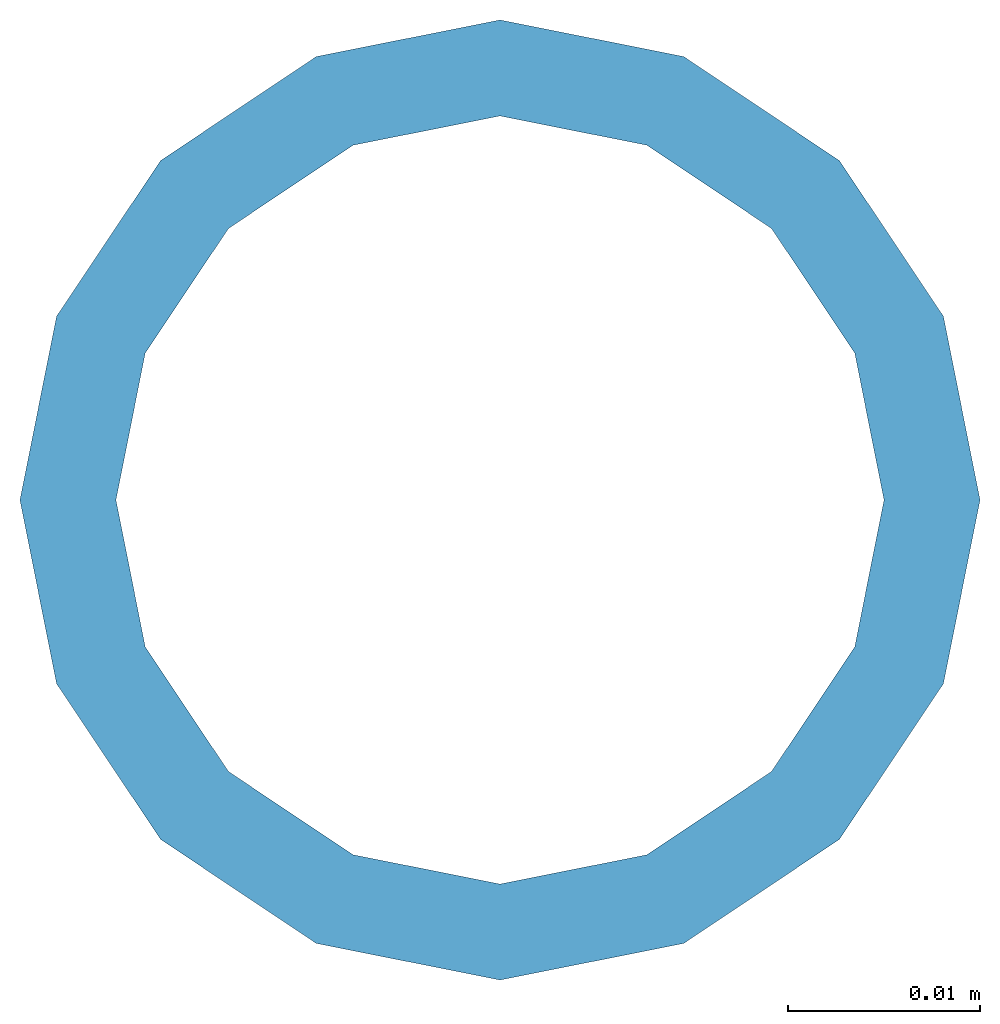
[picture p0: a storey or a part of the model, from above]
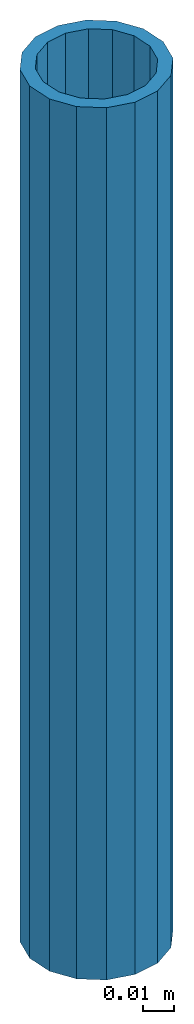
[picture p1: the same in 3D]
Properties of the parts of a building model (IFC2X3), part 1 of 6

# File
Description: ViewDefinition [CoordinationView]
File name: GM.TO-350-205.1 (EDITED).ifc (Edited by Naviate Simple BIM 2022 version 6)
Time: 2026-03-17T17:15:05+01:00
Written by: ODA SDAI 24.12
Made in: Autodesk Revit 25.4.20.11 (ENU) - IFC 25.4.0.27

# IfcProject, A181143
LongName: T2; Phase: Detaljprosjekt

# IfcSite (8)
Name | RefLatitude | RefLongitude | RefElevation (mm) | Reference latitude | Reference elevation | Reference longitude
ENGM | 33, 12, 51, 119999 | -97, -7, -51, -239999 | -4.85124e-10
Gardermoen
ENGM | 33, 12, 51, 119999 | -97, -7, -51, -239999 | 0 | 33, 12, 51, 119999 | 0 | -97, -7, -51, -239999 | MagiCAD Pset_Site - Name: ENGM
ENGM | 59, 54, 49, 759826 | 10, 44, 19, 467315 | 0 | 59, 54, 49, 759826 | 0 | 10, 44, 19, 467315 | MagiCAD Pset_Site - Name: ENGM
ENGM | 42, 24, 53, 508911 | -71, -15, -29, -58837 | 0 | 42, 24, 53, 508911 | 0 | -71, -15, -29, -58837 | MagiCAD Pset_Site - Name: ENGM
Default | 59, 54, 57, 599999 | 10, 44, 59, 999999 | 0
 | 33, 12, 51, 119998 | -97, -7, -51, -239998 | 0 | 33, 12, 51, 119998 | 0 | -97, -7, -51, -239998
ENGM | 33, 12, 51, 119998 | -97, -7, -51, -239998 | 0 | 33, 12, 51, 119998 | 0 | -97, -7, -51, -239998 | MagiCAD Pset_Site - Name: ENGM

# IfcBuilding (8)
Name
TI | LongName: TI; Pset_BuildingCommon - BuildingID: TI; NumberOfStoreys: 15
TI
4 x TI | MagiCAD Pset_Building - Building name: TI
 | Pset_BuildingCommon - NumberOfStoreys: 3; Pset_ProductRequirements - Category: Project Information
mc-building

# IfcBuildingStorey (20)
Name | In | Elevation (mm) | Name
D | TI | 0
F | TI | 0
B | TI | 0
Nivå G + 1,2 m | TI | 216900 | Nivå G + 1,2 m
4 x Nivå F | TI | 210900 | Nivå F
2 x Nivå D + 1,2 m | TI | 205200 | Nivå D + 1,2 m
Nivå H | TI | 219200 | Nivå H
Nivå C | TI | 200300 | Nivå C
Nivå C + 2,7 m | TI | 203000 | Nivå C + 2,7 m
2 x Nivå D | TI | 204000 | Nivå D
Nivå F | mc-building | 210900 | Nivå F
Nivå D | mc-building | 204000 | Nivå D
Nivå F -0,7 | mc-building | 210200 | Nivå F -0,7
Nivå E | TI | 207370 | Nivå E
Nivå F - 0,7 m | TI | 210200 | Nivå F - 0,7 m

# IfcBuildingStorey: Level:8mm Head, Nivå E
LongName: Nivå E; Elevation: 207370 mm
Pset_AirSideSystemInformation - Name: Nivå E
Pset_ProductRequirements - Name: Nivå E; Category: Levels

# IfcBuildingStorey: Level:T2 - Kote (4)
In: TI
Name | LongName | Elevation (mm)
Nivå D | Nivå D | 204000 | Pset_ProductRequirements - Name: Nivå D; sets with these values: 2
Nivå F - 0,7 m | Nivå F - 0,7 m | 210200 | Pset_AirSideSystemInformation - Name: Nivå F - 0,7 m; sets with these values: 2
Nivå F | Nivå F | 210900 | Pset_ProductRequirements - Name: Nivå F; sets with these values: 2
Nivå G - 2,0m | Nivå G - 2,0m | 213700 | Pset_AirSideSystemInformation - Name: Nivå G - 2,0m; sets with these values: 2

# IfcBeam: B223 - Bjelke - HUP:B223 - HUP - 100 x 100 x 5 mm, B223 - Bjelke - HUP:B223 - HUP - 100 x 100 x 5 mm:62363315
In: Nivå F
Type - PredefinedType: BEAM
Type - Pset_BeamCommon - LoadBearing: yes
Material: _NSW Stål
ePset_SimplebimBasicQuantities - Weight, as steel (Simplebim): 21.4029 kg; Area, sides, net (Simplebim): 1.09439 m2; Height (Simplebim): 100 mm; Length (Simplebim): 1434.99 mm; Volume, net (Simplebim): 0.00272648 m3; Width (Simplebim): 100 mm
AVINOR - 03_Ansvar: 72253; 08_Status: S4; 07_Fase: F90; 06_Omrade: TI; 02_Prosjekt: T20100; 01_Lufthavnkode: ENGM
ePset_Simplebim - Assembly Level: Leaf
Pset_ReinforcementBarPitchOfBeam - Reference: B223 - HUP - 100 x 100 x 5 mm; sets with these values: 2
ePset_LocationTool - Splitting: ORIGINAL
Pset_BeamCommon - Span: 1434.99 mm; IsExternal: no; Slope: 0 deg; Reference: B223 - HUP - 100 x 100 x 5 mm

# IfcBeam: FL80*15, STÅLBJELKE
In: F
Description: FL80*15; Material: STEEL/S355
ePset_Simplebim - Assembly Level: Leaf
ePset_LocationTool - Splitting: ORIGINAL
Tekla Quantity - Length: 639.985 mm; AREA_NET: 0.124 m2; AREA_GROSS: 0.124 m2; Width: 15 mm; Heigth: 80 mm; WEIGTH_NET: 6.02866 kg; WEIGTH_GROSS: 6.02866 kg; VOLUME_NET: 0.00077 m3; VOLUME_GROSS: 0.00077 m3
ePset_SimplebimBasicQuantities - Length (Simplebim): 639.985 mm; Volume, net (Simplebim): 0.000767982 m3; Height (Simplebim): 80 mm; Width (Simplebim): 15 mm; Weight, as steel (Simplebim): 6.02866 kg; Area, sides, net (Simplebim): 0.123997 m2
Pset_BeamCommon - LoadBearing: no; Reference: DSB-24802(?)
Tekla Common - Grade: S355; Bottom elevation: +213.805; Top elevation: +213.885; Profile: FL80*15; Name: STÅLBJELKE; Part mark: DSB-24802(?); Class: 330; Assembly mark: SB-14737(?)
AVINOR - 04_Kontrakt: 72253; 05_ID-nummer: +TI=221.025; 08_Status: S4; 07_Fase: F90; 06_Omrade: TI; 02_Prosjekt: T20100; 03_Ansvar: 72101; 01_Lufthavnkode: ENGM

# IfcBeam: HEA600 (2)
In: F
Description: HEA600
ePset_Simplebim - Assembly Level: Leaf
Pset_BeamCommon - LoadBearing: no
AVINOR - 08_Status: S4; 07_Fase: F40; 06_Omrade: TI; 05_ID-nummer: +TI=223.008; 03_Ansvar: 72242; 04_Kontrakt: 72242; 02_Prosjekt: T20100; 01_Lufthavnkode: ENGM
Tekla Common - Grade: S355; Bottom elevation: +210.090; Name: STÅLBJELKE; Profile: HEA600; Top elevation: +210.680; Class: 330
ePset_SimplebimBasicQuantities - Width (Simplebim): 300 mm; Height (Simplebim): 590 mm
Name | Reference = Part mark | Splitting | Assembly mark | Weight, as steel (Simplebim) (kg) | Area, sides, net (Simplebim) (m2) | Volume, net (Simplebim) (m3) | Length (Simplebim) (mm)
STÅLBJELKE | DSB-10256(?) | ORIGINAL | SB-5409(?) | 1493.49 | 20.3826 | 0.190253 | 8640.01 | Material: STEEL/S355; Tekla Quantity - WEIGTH_NET: 1493.49 kg; VOLUME_NET: 0.19025 m3; VOLUME_GROSS: 0.1957 m3; AREA_GROSS: 19.9411 m2; AREA_NET: 20.3826 m2; WEIGTH_GROSS: 1536.22 kg; Width: 300 mm; Heigth: 590 mm; Length: 8640.01 mm
STÅLBJELKE | DSB-10255(?) | RESULT | SB-5408(?) | 223.937 | 3.09366 | 0.028527 | 1296

# IfcBeam: HQ420*15-35*370-25*700 (2)
In: F
Description: HQ420*15-35*370-25*700
ePset_Simplebim - Assembly Level: Leaf
AVINOR - 08_Status: S4; 07_Fase: F40; 06_Omrade: TI; 05_ID-nummer: +TI=223.008; 03_Ansvar: 72242; 04_Kontrakt: 72242; 02_Prosjekt: T20100; 01_Lufthavnkode: ENGM
Tekla Common - Grade: S355; Top elevation: +210.673; Name: STÅLBJELKE; Profile: HQ420*15-35*370-25*700; Class: 330; Bottom elevation: +210.227
ePset_SimplebimBasicQuantities - Height (Simplebim): 444 mm
ePset_LocationTool - Splitting: RESULT
Pset_BeamCommon - LoadBearing: no
Name | Assembly mark | Part mark = Reference | Area, sides, net (Simplebim) (m2) | Volume, net (Simplebim) (m3) | Weight, as steel (Simplebim) (kg) | Width (Simplebim) (mm) | Length (Simplebim) (mm)
STÅLBJELKE | SB-6203 | DSB-373 | 5.1591 | 0.0574717 | 451.153 | 700 | 1335
STÅLBJELKE | SB-7092 | DSB-12327 | 5.4134 | 0.0589778 | 462.976 | 350 | 2740

# IfcBeam: HSQ110*6-10*68-10*280, STÅLBJELKE
In: F
Description: HSQ110*6-10*68-10*280; Material: STEEL/S355J2H
ePset_Simplebim - Assembly Level: Leaf
ePset_LocationTool - Splitting: ORIGINAL
Tekla Common - Top elevation: +213.810; Part mark: DSB-24857(?); Name: STÅLBJELKE; Grade: S355J2H; Assembly mark: SB-14759(?); Profile: HSQ110*6-10*68-10*280; Bottom elevation: +213.690; Class: 330
Tekla Quantity - VOLUME_NET: 0.02027 m3; Length: 4350.93 mm; AREA_NET: 4.82754 m2; VOLUME_GROSS: 0.02088 m3; Heigth: 120 mm; Width: 280 mm; WEIGTH_GROSS: 163.943 kg; WEIGTH_NET: 159.121 kg; AREA_GROSS: 4.95226 m2
Pset_BeamCommon - Reference: DSB-24857(?); LoadBearing: no
ePset_SimplebimBasicQuantities - Length (Simplebim): 4350.93 mm; Area, sides, net (Simplebim): 4.82754 m2; Height (Simplebim): 120 mm; Width (Simplebim): 280 mm; Weight, as steel (Simplebim): 159.121 kg; Volume, net (Simplebim): 0.0202702 m3
AVINOR - 08_Status: S4; 07_Fase: F90; 06_Omrade: TI; 04_Kontrakt: 72717; 02_Prosjekt: T20100; 05_ID-nummer: +TI=221.041; 03_Ansvar: 72101; 01_Lufthavnkode: ENGM

# IfcBeam: IPE120 (3)
In: F
Description: IPE120
ePset_Simplebim - Assembly Level: Leaf
Pset_BeamCommon - LoadBearing: no
ePset_SimplebimBasicQuantities - Height (Simplebim): 120 mm; Width (Simplebim): 64 mm
Tekla Common - Name: STÅLBJELKE; Profile: IPE120; Class: 330
AVINOR - 08_Status: S4; 06_Omrade: TI; 02_Prosjekt: T20100; 01_Lufthavnkode: ENGM
Name | Reference = Part mark | Volume, net (Simplebim) (m3) | Weight, as steel (Simplebim) (kg) | Area, sides, net (Simplebim) (m2) | Length (Simplebim) (mm) | Splitting | Bottom elevation | Top elevation | Grade | Assembly mark | 07_Fase | 04_Kontrakt | 05_ID-nummer | 03_Ansvar
STÅLBJELKE | DSB-22164(?) | 0.00570141 | 44.756 | 2.17868 | 4535.67 | ORIGINAL | +213.580 | +213.700 | S355J2H | SB-13216(?) | F90 | 72717 | +TI=221.041 | 72101 | Material: STEEL/S355J2H; Tekla Quantity - AREA_NET: 2.17868 m2; WEIGTH_GROSS: 46.9986 kg; WEIGTH_NET: 44.756 kg; Length: 4535.67 mm; VOLUME_NET: 0.0057 m3; Width: 64 mm; Heigth: 120 mm; AREA_GROSS: 2.15444 m2; VOLUME_GROSS: 0.00599 m3
2 x STÅLBJELKE | DSB-15659 | 0.00166968 | 13.107 | 0.638595 | 1305 | RESULT | +210.560 | +210.680 | S355 | SB-9378 | F40 | 72242 | +TI=223.008 | 72242

# IfcBeam: IPE140 (7)
In: F
Description: IPE140; Material: STEEL/S355J2H
ePset_Simplebim - Assembly Level: Leaf
ePset_LocationTool - Splitting: ORIGINAL
Tekla Quantity - Width: 73 mm; Heigth: 140 mm
Pset_BeamCommon - LoadBearing: no
Tekla Common - Bottom elevation: +213.560; Top elevation: +213.700; Name: STÅLBJELKE; Grade: S355J2H; Profile: IPE140; Class: 330
AVINOR - 08_Status: S4; 07_Fase: F90; 06_Omrade: TI; 04_Kontrakt: 72717; 02_Prosjekt: T20100; 05_ID-nummer: +TI=221.041; 03_Ansvar: 72101; 01_Lufthavnkode: ENGM
ePset_SimplebimBasicQuantities - Height (Simplebim): 140 mm; Width (Simplebim): 73 mm
Name | WEIGTH_NET (kg) | WEIGTH_GROSS (kg) | VOLUME_GROSS (m3) | VOLUME_NET (m3) | Length (mm) = Length (Simplebim) (mm) | AREA_GROSS (m2) | AREA_NET (m2) | Reference = Part mark | Assembly mark | Area, sides, net (Simplebim) (m2) | Volume, net (Simplebim) (m3) | Weight, as steel (Simplebim) (kg)
STÅLBJELKE | 37.7938 | 39.2136 | 0.00499 | 0.0048 | 3045.95 | 1.67832 | 1.69784 | DSB-19839(?) | SB-11959(?) | 1.69784 | 0.00481608 | 37.8063
STÅLBJELKE | 13.3062 | 13.6343 | 0.00174 | 0.0017 | 1059.06 | 0.58354 | 0.59903 | DSB-19837(?) | SS-7783(?) | 0.599026 | 0.00169506 | 13.3062
STÅLBJELKE | 38.2719 | 39.7163 | 0.00506 | 0.00489 | 3085 | 1.69984 | 1.71967 | DSB-19838(?) | SB-11958(?) | 1.71967 | 0.0048754 | 38.2719
STÅLBJELKE | 27.6579 | 29.7187 | 0.00379 | 0.00352 | 2308.43 | 1.27194 | 1.24608 | DSB-19836(?) | SB-11957(?) | 1.24608 | 0.0035233 | 27.6579
STÅLBJELKE | 7.70276 | 8.10866 | 0.00103 | 0.00098 | 629.848 | 0.34705 | 0.34929 | DSB-19835(?) | SB-11956(?) | 0.349291 | 0.000981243 | 7.70276
STÅLBJELKE | 25.6808 | 26.8353 | 0.00342 | 0.00327 | 2084.46 | 1.14854 | 1.15598 | DSB-19840(?) | SB-11960(?) | 1.15598 | 0.00327144 | 25.6808
STÅLBJELKE | 25.789 | 26.4248 | 0.00337 | 0.00329 | 2052.57 | 1.13097 | 1.15798 | DSB-19827(?) | SB-7478(?) | 1.15798 | 0.00328522 | 25.789

# IfcBeam: IPE180 (4)
In: F
Description: IPE180; Material: STEEL/S355J2H
ePset_Simplebim - Assembly Level: Leaf
ePset_LocationTool - Splitting: ORIGINAL
Pset_BeamCommon - LoadBearing: no
Tekla Quantity - Width: 91 mm; Heigth: 180 mm
Tekla Common - Bottom elevation: +213.520; Top elevation: +213.700; Name: STÅLBJELKE; Grade: S355J2H; Profile: IPE180; Class: 330
ePset_SimplebimBasicQuantities - Width (Simplebim): 91 mm; Height (Simplebim): 180 mm
AVINOR - 08_Status: S4; 07_Fase: F90; 06_Omrade: TI; 04_Kontrakt: 72717; 02_Prosjekt: T20100; 05_ID-nummer: +TI=221.041; 03_Ansvar: 72101; 01_Lufthavnkode: ENGM
Name | Reference = Part mark | VOLUME_GROSS (m3) | AREA_NET (m2) = Area, sides, net (Simplebim) (m2) | WEIGTH_GROSS (kg) | AREA_GROSS (m2) | Length (mm) = Length (Simplebim) (mm) | VOLUME_NET (m3) | WEIGTH_NET (kg) | Assembly mark | Volume, net (Simplebim) (m3) | Weight, as steel (Simplebim) (kg)
STÅLBJELKE | DSB-19708(?) | 0.00552 | 1.65139 | 43.3072 | 1.61119 | 2308.3 | 0.00537 | 42.133 | SB-7476(?) | 0.00536726 | 42.133
STÅLBJELKE | DSB-19707(?) | 0.00876 | 2.61543 | 68.6603 | 2.55443 | 3659.64 | 0.00851 | 66.7987 | SB-11895(?) | 0.00850939 | 66.7987
STÅLBJELKE | DSB-19706(?) | 0.01173 | 3.49031 | 92.0957 | 3.42631 | 4908.76 | 0.01135 | 89.1756 | SB-7474(?) | 0.0113599 | 89.1755
STÅLBJELKE | DSB-19705(?) | 0.01289 | 3.85171 | 101.173 | 3.76402 | 5392.57 | 0.01254 | 98.4297 | SB-7477(?) | 0.0125388 | 98.4297

# IfcBeam: L100*10 (3)
In: F
Description: L100*10; Material: STEEL/S355
Tekla Quantity - Width: 100 mm; Heigth: 100 mm
ePset_Simplebim - Assembly Level: Leaf
ePset_SimplebimBasicQuantities - Width (Simplebim): 100 mm
ePset_LocationTool - Splitting: ORIGINAL
Pset_BeamCommon - Reference: DSB-18464(?); LoadBearing: no
Tekla Common - Grade: S355; Part mark: DSB-18464(?); Bottom elevation: +213.500; Name: STÅLBJELKE; Assembly mark: SB-0(?); Class: 330; Profile: L100*10
AVINOR - 08_Status: S4; 07_Fase: F90; 06_Omrade: TI; 04_Kontrakt: 72717; 02_Prosjekt: T20100; 05_ID-nummer: +TI=221.041; 03_Ansvar: 72101; 01_Lufthavnkode: ENGM
Name | AREA_NET (m2) | Length (mm) | VOLUME_NET (m3) | VOLUME_GROSS (m3) | WEIGTH_GROSS (kg) | AREA_GROSS (m2) | WEIGTH_NET (kg) = Weight, as steel (Simplebim) (kg) | Area, sides, net (Simplebim) (m2) | Volume, net (Simplebim) (m3) | Height (Simplebim) (mm) | Length (Simplebim) (mm) | Top elevation
STÅLBJELKE | 0.0838 | 200 | 0.00037 | 0.00037 | 3.0144 | 0.07799 | 2.983 | 0.0838 | 0.00038 | 100 | 200 | +213.600
2 x STÅLBJELKE | 0.0632 | 183.102 | 0.00028 | 0.00035 | 2.75972 | 0.0714 | 2.18766 | 0.0631987 | 0.000278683 | 183.102 | 100 | +213.683

# IfcBeam: L100*150*10, STÅLBJELKE
In: F
Description: L100*150*10
Tekla Common - Grade: S355; Name: STÅLBJELKE; Top elevation: +210.830; Assembly mark: SB-14547; Profile: L100*150*10; Part mark: DSB-24359; Bottom elevation: +210.680; Class: 330
ePset_SimplebimBasicQuantities - Width (Simplebim): 100 mm; Height (Simplebim): 150 mm; Length (Simplebim): 10475 mm; Area, sides, net (Simplebim): 5.24255 m2; Volume, net (Simplebim): 0.0251412 m3; Weight, as steel (Simplebim): 197.358 kg
ePset_Simplebim - Assembly Level: Leaf
AVINOR - 08_Status: S4; 07_Fase: F40; 06_Omrade: TI; 05_ID-nummer: +TI=223.008; 03_Ansvar: 72242; 04_Kontrakt: 72242; 02_Prosjekt: T20100; 01_Lufthavnkode: ENGM
Pset_BeamCommon - LoadBearing: no; Reference: DSB-24359
ePset_LocationTool - Splitting: RESULT

# IfcBeam: L100*6 (2)
In: F
Description: L100*6; Material: STEEL/S355
ePset_Simplebim - Assembly Level: Leaf
ePset_LocationTool - Splitting: ORIGINAL
Tekla Quantity - Width: 100 mm; Heigth: 100 mm
Pset_BeamCommon - LoadBearing: no
ePset_SimplebimBasicQuantities - Width (Simplebim): 100 mm; Height (Simplebim): 100 mm
Tekla Common - Grade: S355; Name: STÅLBJELKE; Assembly mark: SB-10384(?); Bottom elevation: +213.694; Profile: L100*6; Top elevation: +213.794; Class: 330
AVINOR - 08_Status: S4; 07_Fase: F90; 06_Omrade: TI; 04_Kontrakt: 72717; 02_Prosjekt: T20100; 05_ID-nummer: +TI=221.041; 03_Ansvar: 72101; 01_Lufthavnkode: ENGM
Name | WEIGTH_NET (kg) = WEIGTH_GROSS (kg) = Weight, as steel (Simplebim) (kg) | AREA_GROSS (m2) = AREA_NET (m2) | VOLUME_NET (m3) = VOLUME_GROSS (m3) | Length (mm) = Length (Simplebim) (mm) | Reference = Part mark | Area, sides, net (Simplebim) (m2) | Volume, net (Simplebim) (m3)
STÅLBJELKE | 10.2906 | 0.45281 | 0.00131 | 1126.21 | DSB-18463(?) | 0.452811 | 0.00131091
STÅLBJELKE | 9.5262 | 0.41935 | 0.00121 | 1042.55 | DSB-18464(?) | 0.419348 | 0.00121353

# IfcBeam: L150*100*10 (6)
In: F
Description: L150*100*10; Material: STEEL/S355
ePset_Simplebim - Assembly Level: Leaf
Tekla Quantity - Width: 100 mm; Heigth: 150 mm
Tekla Common - Grade: S355; Name: STÅLBJELKE; Bottom elevation: +213.755; Profile: L150*100*10; Top elevation: +213.905; Class: 330
ePset_LocationTool - Splitting: ORIGINAL
Pset_BeamCommon - LoadBearing: no
AVINOR - 08_Status: S4; 07_Fase: F90; 06_Omrade: TI; 04_Kontrakt: 72717; 02_Prosjekt: T20100; 05_ID-nummer: +TI=221.041; 03_Ansvar: 72101; 01_Lufthavnkode: ENGM
ePset_SimplebimBasicQuantities - Height (Simplebim): 150 mm
Name | WEIGTH_NET (kg) = Weight, as steel (Simplebim) (kg) | VOLUME_NET (m3) = VOLUME_GROSS (m3) | AREA_GROSS (m2) | Length (mm) | AREA_NET (m2) | WEIGTH_GROSS (kg) | Assembly mark | Part mark = Reference | Area, sides, net (Simplebim) (m2) | Width (Simplebim) (mm) | Volume, net (Simplebim) (m3) | Length (Simplebim) (mm)
STÅLBJELKE | 1.92166 | 0.00025 | 0.04988 | 101.999 | 0.0558 | 1.93767 | SB-10597(?) | DSB-23275(?) | 0.0557994 | 100 | 0.000244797 | 101.999
STÅLBJELKE | 1.69558 | 0.00022 | 0.04401 | 89.9988 | 0.0498 | 1.70971 | SB-10385(?) | DSB-23276(?) | 0.0497994 | 89.9988 | 0.000215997 | 100
STÅLBJELKE | 1.69558 | 0.00022 | 0.04401 | 89.9988 | 0.0498 | 1.70971 | SB-10386(?) | DSB-23276(?) | 0.0497994 | 89.9988 | 0.000215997 | 100
STÅLBJELKE | 1.69558 | 0.00022 | 0.04401 | 89.9988 | 0.0498 | 1.70971 | SB-10595(?) | DSB-23276(?) | 0.0497994 | 89.9988 | 0.000215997 | 100
2 x STÅLBJELKE | 1.69558 | 0.00022 | 0.04401 | 89.9988 | 0.0498 | 1.70971 | SB-13280(?) | DSB-23276(?) | 0.0497994 | 89.9988 | 0.000215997 | 100

# IfcBeam: L150*14, STÅLBJELKE
In: F
Description: L150*14; Material: STEEL/S355
ePset_Simplebim - Assembly Level: Leaf
Tekla Quantity - VOLUME_GROSS: 0.04267 m3; AREA_GROSS: 6.20574 m2; WEIGTH_NET: 332.859 kg; AREA_NET: 6.36201 m2; Width: 150 mm; Heigth: 150 mm; Length: 10590 mm; VOLUME_NET: 0.04239 m3; WEIGTH_GROSS: 334.937 kg
Tekla Common - Grade: S355; Name: STÅLBJELKE; Part mark: DSB-12461; Bottom elevation: +210.401; Top elevation: +210.551; Assembly mark: SB-7753; Class: 330; Profile: L150*14
AVINOR - 08_Status: S4; 07_Fase: F40; 06_Omrade: TI; 05_ID-nummer: +TI=223.008; 03_Ansvar: 72242; 04_Kontrakt: 72242; 02_Prosjekt: T20100; 01_Lufthavnkode: ENGM
Pset_BeamCommon - Reference: DSB-12461; LoadBearing: no
ePset_SimplebimBasicQuantities - Weight, as steel (Simplebim): 332.859 kg; Volume, net (Simplebim): 0.0424024 m3; Height (Simplebim): 150 mm; Width (Simplebim): 150 mm; Length (Simplebim): 10590 mm; Area, sides, net (Simplebim): 6.36201 m2
ePset_LocationTool - Splitting: ORIGINAL

# IfcBeam: L150*75*9 (2)
In: F
Description: L150*75*9; Material: STEEL/S355
ePset_Simplebim - Assembly Level: Leaf
ePset_SimplebimBasicQuantities - Weight, as steel (Simplebim): 1.37349 kg; Area, sides, net (Simplebim): 0.0443897 m2; Volume, net (Simplebim): 0.000174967 m3; Width (Simplebim): 75 mm; Height (Simplebim): 150 mm; Length (Simplebim): 90.0038 mm
ePset_LocationTool - Splitting: ORIGINAL
Pset_BeamCommon - Reference: DSB-22246(?); LoadBearing: no
Tekla Common - Grade: S355; Top elevation: +213.850; Bottom elevation: +213.700; Assembly mark: SB-13280(?); Name: STÅLBJELKE; Part mark: DSB-22246(?); Profile: L150*75*9; Class: 330
Tekla Quantity - WEIGTH_NET: 1.37349 kg; WEIGTH_GROSS: 1.37773 kg; VOLUME_GROSS: 0.00017 m3; VOLUME_NET: 0.00017 m3; AREA_NET: 0.04439 m2; Width: 75 mm; Heigth: 150 mm; Length: 90.0038 mm; AREA_GROSS: 0.03969 m2
AVINOR - 08_Status: S4; 07_Fase: F90; 06_Omrade: TI; 04_Kontrakt: 72717; 02_Prosjekt: T20100; 05_ID-nummer: +TI=221.041; 03_Ansvar: 72101; 01_Lufthavnkode: ENGM

# IfcBeam: L180*90*10 (2)
In: F
Description: L180*90*10; Material: STEEL/S355
Pset_BeamCommon - LoadBearing: no
ePset_Simplebim - Assembly Level: Leaf
ePset_LocationTool - Splitting: ORIGINAL
ePset_SimplebimBasicQuantities - Height (Simplebim): 180 mm
Tekla Quantity - Width: 90 mm; Heigth: 180 mm
AVINOR - 08_Status: S4; 07_Fase: F90; 06_Omrade: TI; 04_Kontrakt: 72717; 02_Prosjekt: T20100; 05_ID-nummer: +TI=221.041; 03_Ansvar: 72101; 01_Lufthavnkode: ENGM
Tekla Common - Grade: S355; Top elevation: +213.880; Bottom elevation: +213.700; Name: STÅLBJELKE; Profile: L180*90*10; Class: 330
Name | Reference = Part mark | Area, sides, net (Simplebim) (m2) | Volume, net (Simplebim) (m3) | Length (Simplebim) (mm) | Width (Simplebim) (mm) | Weight, as steel (Simplebim) (kg) = WEIGTH_NET (kg) | AREA_NET (m2) | VOLUME_NET (m3) = VOLUME_GROSS (m3) | Length (mm) | AREA_GROSS (m2) | WEIGTH_GROSS (kg) | Assembly mark
STÅLBJELKE | DSB-24046(?) | 0.0543398 | 0.000236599 | 90.9997 | 90 | 1.8573 | 0.05434 | 0.00025 | 90.9997 | 0.04805 | 1.87159 | SB-7475(?)
STÅLBJELKE | DSB-24047(?) | 0.0446198 | 0.000189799 | 90 | 72.9997 | 1.48992 | 0.04462 | 0.0002 | 72.9997 | 0.03854 | 1.50138 | SB-14398(?)

# IfcBeam: L90*9 (60)
In: F
Description: L90*9; Material: STEEL/S355
ePset_Simplebim - Assembly Level: Leaf
ePset_LocationTool - Splitting: ORIGINAL
ePset_SimplebimBasicQuantities - Height (Simplebim): 90 mm; Width (Simplebim): 90 mm
Tekla Quantity - VOLUME_GROSS: 0.00022 m3; AREA_GROSS: 0.05265 m2; Width: 90 mm; Heigth: 90 mm
AVINOR - 04_Kontrakt: 72253; 05_ID-nummer: +TI=221.025; 08_Status: S4; 07_Fase: F90; 06_Omrade: TI; 02_Prosjekt: T20100; 03_Ansvar: 72101; 01_Lufthavnkode: ENGM
Tekla Common - Profile: L90*9; Grade: S355; Name: STÅLBJELKE; Class: 330
Pset_BeamCommon - LoadBearing: no
Name | Weight, as steel (Simplebim) (kg) | Length (Simplebim) (mm) | Volume, net (Simplebim) (m3) | Area, sides, net (Simplebim) (m2) | VOLUME_NET (m3) | AREA_NET (m2) | WEIGTH_NET (kg) | WEIGTH_GROSS (kg) | Length (mm) | Part mark = Reference | Bottom elevation | Top elevation | Assembly mark
22 x STÅLBJELKE | 1.81217 | 150 | 0.00023085 | 0.057078 | 0.00022 | 0.05708 | 1.81217 | 1.82512 | 149.999 | DSB-19624(?) | +213.405 | +213.495 | SB-11830(?)
22 x STÅLBJELKE | 1.81217 | 150 | 0.00023085 | 0.057078 | 0.00022 | 0.05708 | 1.81217 | 1.82512 | 149.999 | DSB-19624(?) | +213.805 | +213.895 | SB-11830(?)
7 x STÅLBJELKE | 1.81217 | 150 | 0.00023085 | 0.057078 | 0.00022 | 0.05708 | 1.81217 | 1.82513 | 150 | DSB-19624(?) | +213.405 | +213.495 | SB-11830(?)
7 x STÅLBJELKE | 1.81217 | 150 | 0.00023085 | 0.057078 | 0.00022 | 0.05708 | 1.81217 | 1.82513 | 150 | DSB-19624(?) | +213.805 | +213.895 | SB-11830(?)
STÅLBJELKE | 1.34862 | 149.999 | 0.000171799 | 0.0439556 | 0.00017 | 0.04396 | 1.34862 | 1.82512 | 149.999 | DSB-19623(?) | +213.405 | +213.495 | SB-11829(?)
STÅLBJELKE | 1.34863 | 149.999 | 0.0001718 | 0.0439558 | 0.00017 | 0.04396 | 1.34864 | 1.82512 | 149.999 | DSB-19621(?) | +213.805 | +213.895 | SB-11828(?)

# IfcBeam: M20 (19)
In: F
Description: M20; Material: STEEL/S355
ePset_Simplebim - Assembly Level: Leaf
AVINOR - 08_Status: S4; 07_Fase: F40; 06_Omrade: TI; 05_ID-nummer: +TI=222.006; 03_Ansvar: 72242; 04_Kontrakt: 72242; 02_Prosjekt: T20100; 01_Lufthavnkode: ENGM
Tekla Quantity - AREA_NET: 0.01587 m2; AREA_GROSS: 0.01587 m2; VOLUME_GROSS: 0.00007 m3; VOLUME_NET: 0.00007 m3; WEIGTH_NET: 0.55508 kg; WEIGTH_GROSS: 0.55508 kg; Width: 20 mm; Heigth: 20 mm; Length: 250 mm
Tekla Common - Grade: S355; Top elevation: +210.050; Name: INNSTØPNGODS; Part mark: DINN-150; Profile: M20; Class: 371; Bottom elevation: +209.800
ePset_LocationTool - Splitting: ORIGINAL
ePset_SimplebimBasicQuantities - Weight, as steel (Simplebim): 0.555079 kg; Area, sides, net (Simplebim): 0.015873 m2; Volume, net (Simplebim): 0.0000707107 m3; Width (Simplebim): 20 mm; Length (Simplebim): 20 mm; Height (Simplebim): 250 mm
Pset_BeamCommon - Reference: DINN-150; LoadBearing: no
Name | Assembly mark
8 x INNSTØPNGODS | INN-102
4 x INNSTØPNGODS | INN-115
7 x INNSTØPNGODS | INN-104

# IfcBeam: PL10*100 (4)
In: F
Description: PL10*100; Material: STEEL/S355J2H
ePset_Simplebim - Assembly Level: Leaf
ePset_SimplebimBasicQuantities - Height (Simplebim): 185 mm; Width (Simplebim): 10 mm; Length (Simplebim): 100 mm
Tekla Common - Name: STÅLBJELKE; Grade: S355J2H; Part mark: DSB-0(?); Profile: PL10*100; Class: 330
Pset_BeamCommon - LoadBearing: no; Reference: DSB-0(?)
Tekla Quantity - AREA_GROSS: 0.04269 m2; VOLUME_NET: 0.00017 m3; Width: 10 mm; Heigth: 100 mm; Length: 185 mm; WEIGTH_GROSS: 1.45225 kg
ePset_LocationTool - Splitting: ORIGINAL
AVINOR - 08_Status: S4; 07_Fase: F90; 06_Omrade: TI; 04_Kontrakt: 72717; 02_Prosjekt: T20100; 05_ID-nummer: +TI=221.041; 03_Ansvar: 72101; 01_Lufthavnkode: ENGM
Name | Volume, net (Simplebim) (m3) | Weight, as steel (Simplebim) (kg) = WEIGTH_NET (kg) | Area, sides, net (Simplebim) (m2) | Assembly mark | Bottom elevation | Top elevation | VOLUME_GROSS (m3) | AREA_NET (m2)
STÅLBJELKE | 0.000180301 | 1.41536 | 0.0415111 | SD-786(?) | +213.348 | +213.542 | 0.0002 | 0.04151
STÅLBJELKE | 0.000181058 | 1.42131 | 0.0417501 | SD-786(?) | +210.914 | +211.122 | 0.00017 | 0.04175
STÅLBJELKE | 0.000182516 | 1.43275 | 0.042075 | SD-787(?) | +213.225 | +213.434 | 0.00017 | 0.04208
STÅLBJELKE | 0.000182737 | 1.43448 | 0.0421305 | SD-788(?) | +213.160 | +213.370 | 0.00017 | 0.04213

# IfcBeam: PL10*111, STÅLBJELKE
In: F
Description: PL10*111; Material: STEEL/S355
ePset_Simplebim - Assembly Level: Leaf
ePset_SimplebimBasicQuantities - Length (Simplebim): 184.611 mm; Weight, as steel (Simplebim): 1.15222 kg; Width (Simplebim): 117.82 mm; Volume, net (Simplebim): 0.00014678 m3; Height (Simplebim): 10 mm; Area, sides, net (Simplebim): 0.0344922 m2
Pset_BeamCommon - Reference: DSB-17994(?); LoadBearing: no
Tekla Quantity - AREA_GROSS: 0.02096 m2; WEIGTH_NET: 1.15222 kg; VOLUME_NET: 0.00015 m3; VOLUME_GROSS: 0.00015 m3; Width: 10 mm; Length: 188.79 mm; WEIGTH_GROSS: 1.64504 kg; Heigth: 111.001 mm; AREA_NET: 0.03449 m2
ePset_LocationTool - Splitting: ORIGINAL
AVINOR - 08_Status: S4; 07_Fase: F90; 06_Omrade: TI; 04_Kontrakt: 72717; 02_Prosjekt: T20100; 05_ID-nummer: +TI=221.041; 03_Ansvar: 72101; 01_Lufthavnkode: ENGM
Tekla Common - Grade: S355; Profile: PL10*111; Bottom elevation: +213.700; Top elevation: +213.710; Name: STÅLBJELKE; Assembly mark: SB-10384(?); Part mark: DSB-17994(?); Class: 330

# IfcBeam: PL10*117, STÅLBJELKE
In: F
Description: PL10*117; Material: STEEL/S355J2H
ePset_Simplebim - Assembly Level: Leaf
ePset_LocationTool - Splitting: ORIGINAL
ePset_SimplebimBasicQuantities - Length (Simplebim): 231.393 mm; Volume, net (Simplebim): 0.000183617 m3; Area, sides, net (Simplebim): 0.0428143 m2; Height (Simplebim): 117.062 mm; Width (Simplebim): 10 mm; Weight, as steel (Simplebim): 1.44139 kg
Tekla Quantity - WEIGTH_NET: 1.44139 kg; VOLUME_GROSS: 0.00017 m3; VOLUME_NET: 0.00017 m3; Length: 231.393 mm; AREA_NET: 0.04281 m2; AREA_GROSS: 0.02709 m2; Heigth: 117.062 mm; Width: 10 mm; WEIGTH_GROSS: 2.12636 kg
Tekla Common - Name: STÅLBJELKE; Grade: S355J2H; Profile: PL10*117; Bottom elevation: +213.435; Part mark: DSB-0(?); Top elevation: +213.552; Class: 330; Assembly mark: SS-8709(?)
Pset_BeamCommon - LoadBearing: no; Reference: DSB-0(?)
AVINOR - 08_Status: S4; 07_Fase: F90; 06_Omrade: TI; 04_Kontrakt: 72717; 02_Prosjekt: T20100; 05_ID-nummer: +TI=221.041; 03_Ansvar: 72101; 01_Lufthavnkode: ENGM

# IfcBeam: PL10*120 (2)
In: F
Description: PL10*120; Material: STEEL/S355
Tekla Common - Grade: S355; Top elevation: +213.810; Bottom elevation: +213.800; Name: STÅLBJELKE; Profile: PL10*120; Class: 330
ePset_Simplebim - Assembly Level: Leaf
Tekla Quantity - Width: 10 mm
ePset_LocationTool - Splitting: ORIGINAL
Pset_BeamCommon - LoadBearing: no
ePset_SimplebimBasicQuantities - Height (Simplebim): 10 mm
AVINOR - 08_Status: S4; 07_Fase: F90; 06_Omrade: TI; 04_Kontrakt: 72717; 02_Prosjekt: T20100; 05_ID-nummer: +TI=221.041; 03_Ansvar: 72101; 01_Lufthavnkode: ENGM
Name | Part mark = Reference | Assembly mark | AREA_GROSS (m2) | AREA_NET (m2) | Heigth (mm) | VOLUME_NET (m3) = VOLUME_GROSS (m3) | WEIGTH_NET (kg) = Weight, as steel (Simplebim) (kg) | Length (mm) | WEIGTH_GROSS (kg) | Width (Simplebim) (mm) | Length (Simplebim) (mm) | Volume, net (Simplebim) (m3) | Area, sides, net (Simplebim) (m2)
STÅLBJELKE | DSB-17799(?) | SB-10597(?) | 0.01543 | 0.03584 | 119.999 | 0.00015 | 1.21153 | 128.616 | 1.21155 | 120.004 | 128.616 | 0.000154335 | 0.0358392
STÅLBJELKE | DSB-17800(?) | SB-10595(?) | 0.03054 | 0.04665 | 120 | 0.0002 | 1.56814 | 254.417 | 2.39661 | 130.02 | 281.164 | 0.000199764 | 0.0466529

# IfcBeam: PL10*207, STÅLBJELKE
In: F
Description: PL10*207; Material: STEEL/S355J2H
ePset_Simplebim - Assembly Level: Leaf
ePset_SimplebimBasicQuantities - Length (Simplebim): 207.497 mm; Height (Simplebim): 250.99 mm; Width (Simplebim): 10 mm; Volume, net (Simplebim): 0.000342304 m3; Weight, as steel (Simplebim): 2.68709 kg; Area, sides, net (Simplebim): 0.0762861 m2
Tekla Common - Name: STÅLBJELKE; Grade: S355J2H; Bottom elevation: +213.261; Profile: PL10*207; Part mark: DSB-0(?); Assembly mark: SS-8821(?); Top elevation: +213.512; Class: 330
Tekla Quantity - Heigth: 207.497 mm; AREA_NET: 0.0763 m2; VOLUME_GROSS: 0.00034 m3; VOLUME_NET: 0.00034 m3; Length: 250.99 mm; AREA_GROSS: 0.05208 m2; Width: 10 mm; WEIGTH_NET: 2.68709 kg; WEIGTH_GROSS: 4.08825 kg
Pset_BeamCommon - LoadBearing: no; Reference: DSB-0(?)
ePset_LocationTool - Splitting: ORIGINAL
AVINOR - 08_Status: S4; 07_Fase: F90; 06_Omrade: TI; 04_Kontrakt: 72717; 02_Prosjekt: T20100; 05_ID-nummer: +TI=221.041; 03_Ansvar: 72101; 01_Lufthavnkode: ENGM

# IfcBeam: PL10*215, STÅLBJELKE
In: F
Description: PL10*215; Material: STEEL/S355J2H
ePset_Simplebim - Assembly Level: Leaf
Tekla Common - Name: STÅLBJELKE; Top elevation: +213.565; Bottom elevation: +213.323; Grade: S355J2H; Profile: PL10*215; Part mark: DSB-0(?); Class: 330; Assembly mark: SS-7783(?)
ePset_LocationTool - Splitting: ORIGINAL
ePset_SimplebimBasicQuantities - Area, sides, net (Simplebim): 0.0830197 m2; Length (Simplebim): 214.816 mm; Volume, net (Simplebim): 0.000375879 m3; Weight, as steel (Simplebim): 2.95065 kg; Width (Simplebim): 10 mm; Height (Simplebim): 242.204 mm
Tekla Quantity - Heigth: 214.816 mm; VOLUME_NET: 0.00037 m3; VOLUME_GROSS: 0.00037 m3; WEIGTH_NET: 2.95065 kg; AREA_GROSS: 0.05203 m2; Width: 10 mm; AREA_NET: 0.08302 m2; WEIGTH_GROSS: 4.08429 kg; Length: 242.204 mm
Pset_BeamCommon - LoadBearing: no; Reference: DSB-0(?)
AVINOR - 08_Status: S4; 07_Fase: F90; 06_Omrade: TI; 04_Kontrakt: 72717; 02_Prosjekt: T20100; 05_ID-nummer: +TI=221.041; 03_Ansvar: 72101; 01_Lufthavnkode: ENGM

# IfcBeam: PL10*226, STÅLBJELKE
In: F
Description: PL10*226; Material: STEEL/S355J2H
ePset_Simplebim - Assembly Level: Leaf
ePset_LocationTool - Splitting: ORIGINAL
Tekla Common - Assembly mark: SB-7473(?); Name: STÅLBJELKE; Grade: S355J2H; Top elevation: +211.079; Bottom elevation: +210.895; Part mark: DSB-0(?); Class: 330; Profile: PL10*226
ePset_SimplebimBasicQuantities - Volume, net (Simplebim): 0.000334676 m3; Length (Simplebim): 226.458 mm; Width (Simplebim): 10 mm; Height (Simplebim): 184.069 mm; Area, sides, net (Simplebim): 0.0741029 m2; Weight, as steel (Simplebim): 2.62721 kg
Pset_BeamCommon - LoadBearing: no; Reference: DSB-0(?)
Tekla Quantity - AREA_GROSS: 0.04168 m2; AREA_NET: 0.0741 m2; VOLUME_GROSS: 0.00034 m3; VOLUME_NET: 0.00034 m3; WEIGTH_NET: 2.62721 kg; WEIGTH_GROSS: 3.27218 kg; Heigth: 226.458 mm; Width: 10 mm; Length: 184.069 mm
AVINOR - 08_Status: S4; 07_Fase: F90; 06_Omrade: TI; 04_Kontrakt: 72717; 02_Prosjekt: T20100; 05_ID-nummer: +TI=221.041; 03_Ansvar: 72101; 01_Lufthavnkode: ENGM

# IfcBeam: PL10*45 (4)
In: F
Description: PL10*45; Material: STEEL/S355
ePset_Simplebim - Assembly Level: Leaf
ePset_LocationTool - Splitting: ORIGINAL
Tekla Common - Grade: S355; Top elevation: +213.800; Name: STÅLBJELKE; Bottom elevation: +213.755; Class: 330; Profile: PL10*45
Tekla Quantity - Heigth: 44.9997 mm; Width: 10 mm
ePset_SimplebimBasicQuantities - Height (Simplebim): 44.9996 mm; Width (Simplebim): 10 mm
AVINOR - 08_Status: S4; 07_Fase: F90; 06_Omrade: TI; 04_Kontrakt: 72717; 02_Prosjekt: T20100; 05_ID-nummer: +TI=221.041; 03_Ansvar: 72101; 01_Lufthavnkode: ENGM
Pset_BeamCommon - LoadBearing: no
Name | Part mark = Reference | Assembly mark | AREA_GROSS (m2) | Length (mm) = Length (Simplebim) (mm) | WEIGTH_NET (kg) | WEIGTH_GROSS (kg) | AREA_NET (m2) | VOLUME_NET (m3) = VOLUME_GROSS (m3) | Volume, net (Simplebim) (m3) | Area, sides, net (Simplebim) (m2) | Weight, as steel (Simplebim) (kg)
STÅLBJELKE | DSB-17699(?) | SB-10597(?) | 0.00405 | 90.0011 | 0.31792 | 0.31793 | 0.0108 | 0.00003 | 0.0000404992 | 0.0107998 | 0.317919
STÅLBJELKE | DSB-17697(?) | SB-10385(?) | 0.00901 | 200.251 | 0.70737 | 0.70738 | 0.02294 | 0.00009 | 0.0000901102 | 0.022927 | 0.707365
STÅLBJELKE | DSB-17697(?) | SB-10386(?) | 0.00901 | 200.251 | 0.70737 | 0.70738 | 0.02294 | 0.00009 | 0.0000901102 | 0.022927 | 0.707365
STÅLBJELKE | DSB-17697(?) | SB-10595(?) | 0.00901 | 200.251 | 0.70737 | 0.70738 | 0.02294 | 0.00009 | 0.0000901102 | 0.022927 | 0.707365

# IfcBeam: PL10*490 (4)
In: F
Description: PL10*490; Material: STEEL/S355
ePset_Simplebim - Assembly Level: Leaf
Tekla Quantity - Width: 10 mm; Heigth: 490 mm
ePset_SimplebimBasicQuantities - Height (Simplebim): 490 mm; Width (Simplebim): 10 mm
ePset_LocationTool - Splitting: ORIGINAL
AVINOR - 04_Kontrakt: 72253; 05_ID-nummer: +TI=221.025; 08_Status: S4; 07_Fase: F90; 06_Omrade: TI; 02_Prosjekt: T20100; 03_Ansvar: 72101; 01_Lufthavnkode: ENGM
Tekla Common - Grade: S355; Top elevation: +213.895; Name: STÅLBJELKE; Profile: PL10*490; Bottom elevation: +213.405; Class: 330
Pset_BeamCommon - LoadBearing: no
Name | WEIGTH_GROSS (kg) = WEIGTH_NET (kg) = Weight, as steel (Simplebim) (kg) | AREA_GROSS (m2) = AREA_NET (m2) | VOLUME_GROSS (m3) | VOLUME_NET (m3) | Length (mm) | Volume, net (Simplebim) (m3) | Area, sides, net (Simplebim) (m2) | Length (Simplebim) (mm) | Assembly mark | Part mark = Reference
STÅLBJELKE | 16.9246 | 0.4498 | 0.00216 | 0.00216 | 440.001 | 0.002156 | 0.449801 | 440.001 | SB-10614(?) | DSB-17719(?)
STÅLBJELKE | 69.3997 | 1.81403 | 0.00885 | 0.00884 | 1804.23 | 0.00884073 | 1.81403 | 1804.23 | SS-9028(?) | DSS-5879(?)
STÅLBJELKE | 173.554 | 4.5218 | 0.02211 | 0.02211 | 4512 | 0.0221088 | 4.5218 | 4512 | SS-9029(?) | DSS-5880(?)
STÅLBJELKE | 173.554 | 4.52179 | 0.02211 | 0.02211 | 4511.99 | 0.0221088 | 4.5218 | 4512 | SS-9029(?) | DSS-5880(?)

# IfcBeam: PL10*87 (2)
In: F
Description: PL10*87; Material: STEEL/S355
ePset_Simplebim - Assembly Level: Leaf
Pset_BeamCommon - LoadBearing: no; Reference: DSB-17402(?)
Tekla Quantity - VOLUME_GROSS: 0.00034 m3; VOLUME_NET: 0.00034 m3; AREA_NET: 0.07768 m2; WEIGTH_GROSS: 2.86987 kg; AREA_GROSS: 0.03656 m2; Width: 10 mm; WEIGTH_NET: 2.67359 kg; Heigth: 86.9994 mm; Length: 420.22 mm
ePset_SimplebimBasicQuantities - Weight, as steel (Simplebim): 2.67359 kg; Volume, net (Simplebim): 0.000340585 m3; Width (Simplebim): 10 mm; Height (Simplebim): 86.9994 mm; Area, sides, net (Simplebim): 0.0776756 m2; Length (Simplebim): 420.22 mm
ePset_LocationTool - Splitting: ORIGINAL
Tekla Common - Grade: S355; Top elevation: +213.895; Name: STÅLBJELKE; Bottom elevation: +213.808; Profile: PL10*87; Part mark: DSB-17402(?); Class: 330
AVINOR - 08_Status: S4; 07_Fase: F90; 06_Omrade: TI; 04_Kontrakt: 72717; 02_Prosjekt: T20100; 05_ID-nummer: +TI=221.041; 03_Ansvar: 72101; 01_Lufthavnkode: ENGM
Name | Assembly mark
STÅLBJELKE | SB-10385(?)
STÅLBJELKE | SB-10386(?)

# IfcBeam: PL10*90 (3)
In: F
Description: PL10*90
ePset_LocationTool - Splitting: ORIGINAL
ePset_Simplebim - Assembly Level: Leaf
Tekla Common - Name: STÅLBJELKE; Profile: PL10*90; Class: 330
Tekla Quantity - Width: 10 mm
Pset_BeamCommon - LoadBearing: no
AVINOR - 08_Status: S4; 07_Fase: F90; 06_Omrade: TI; 04_Kontrakt: 72717; 02_Prosjekt: T20100; 05_ID-nummer: +TI=221.041; 03_Ansvar: 72101; 01_Lufthavnkode: ENGM
Name | Material | Bottom elevation | Top elevation | Grade | Part mark = Reference | Assembly mark | Volume, net (Simplebim) (m3) | Length (Simplebim) (mm) | Weight, as steel (Simplebim) (kg) | Area, sides, net (Simplebim) (m2) | Width (Simplebim) (mm) | Height (Simplebim) (mm) | AREA_GROSS (m2) | VOLUME_NET (m3) = VOLUME_GROSS (m3) | WEIGTH_NET (kg) | WEIGTH_GROSS (kg) | Heigth (mm) | Length (mm) | AREA_NET (m2)
STÅLBJELKE | STEEL/S355J0 | +213.500 | +213.590 | S355J0 | DSB-0(?) | SB-0(?) | 0.0000525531 | 90 | 0.412542 | 0.0136192 | 10 | 90 | 0.0081 | 0.00005 | 0.41254 | 0.63585 | 90 | 90 | 0.01362
STÅLBJELKE | STEEL/S355 | +213.800 | +213.810 | S355 | DSB-17418(?) | SB-10385(?) | 0.000118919 | 313.716 | 0.933511 | 0.0303504 | 59.9969 | 10 | 0.02756 | 0.00013 | 0.93351 | 2.16351 | 89.9974 | 306.238 | 0.03034
STÅLBJELKE | STEEL/S355 | +213.800 | +213.810 | S355 | DSB-17418(?) | SB-10386(?) | 0.000118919 | 313.716 | 0.933511 | 0.0303504 | 59.9969 | 10 | 0.02756 | 0.00013 | 0.93351 | 2.16351 | 89.9974 | 306.238 | 0.03034

# IfcBeam: PL10*95 (3)
In: F
Description: PL10*95; Material: STEEL/S355
ePset_Simplebim - Assembly Level: Leaf
Tekla Quantity - Width: 10 mm
ePset_SimplebimBasicQuantities - Width (Simplebim): 10 mm
Pset_BeamCommon - LoadBearing: no
Tekla Common - Grade: S355; Name: STÅLBJELKE; Profile: PL10*95; Class: 330
ePset_LocationTool - Splitting: ORIGINAL
AVINOR - 08_Status: S4; 07_Fase: F90; 06_Omrade: TI; 04_Kontrakt: 72717; 02_Prosjekt: T20100; 05_ID-nummer: +TI=221.041; 03_Ansvar: 72101; 01_Lufthavnkode: ENGM
Name | WEIGTH_NET (kg) | AREA_GROSS (m2) | VOLUME_NET (m3) = VOLUME_GROSS (m3) | WEIGTH_GROSS (kg) | AREA_NET (m2) | Heigth (mm) = Height (Simplebim) (mm) | Length (mm) = Length (Simplebim) (mm) | Area, sides, net (Simplebim) (m2) | Weight, as steel (Simplebim) (kg) | Volume, net (Simplebim) (m3) | Reference = Part mark | Top elevation | Bottom elevation | Assembly mark
2 x STÅLBJELKE | 2.93749 | 0.03992 | 0.00037 | 3.13377 | 0.08456 | 94.9994 | 420.22 | 0.0845591 | 2.93749 | 0.000374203 | DSB-17401(?) | +213.895 | +213.800 | SB-10384(?)
STÅLBJELKE | 0.76239 | 0.00971 | 0.00009 | 0.76239 | 0.02337 | 94.9993 | 102.233 | 0.0233687 | 0.762394 | 0.0000971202 | DSB-17698(?) | +213.700 | +213.605 | SB-10596(?)

# IfcBeam: PL170*10 (2)
In: F
Description: PL170*10; Material: STEEL/S355
ePset_Simplebim - Assembly Level: Leaf
Pset_BeamCommon - LoadBearing: no
ePset_LocationTool - Splitting: ORIGINAL
AVINOR - 08_Status: S4; 07_Fase: F40; 06_Omrade: TI; 05_ID-nummer: +TI=223.008; 03_Ansvar: 72242; 04_Kontrakt: 72242; 02_Prosjekt: T20100; 01_Lufthavnkode: ENGM
ePset_SimplebimBasicQuantities - Height (Simplebim): 10 mm; Width (Simplebim): 170 mm
Tekla Common - Top elevation: +210.415; Bottom elevation: +210.405; Grade: S355; Profile: PL170*10; Name: STÅLBJELKE; Assembly mark: SB-7670; Class: 330
Tekla Quantity - Width: 10 mm; Heigth: 170 mm
Name | Reference = Part mark | Weight, as steel (Simplebim) (kg) = WEIGTH_NET (kg) = WEIGTH_GROSS (kg) | Volume, net (Simplebim) (m3) | Area, sides, net (Simplebim) (m2) = AREA_NET (m2) = AREA_GROSS (m2) | Length (Simplebim) (mm) = Length (mm) | VOLUME_GROSS (m3) = VOLUME_NET (m3)
STÅLBJELKE | DSB-13434 | 167.014 | 0.0212756 | 4.50883 | 12515.1 | 0.02128
STÅLBJELKE | DSB-9524 | 141.324 | 0.018003 | 3.8158 | 10590 | 0.018

# IfcBeam: PL20*250 (3)
In: F
Description: PL20*250; Material: STEEL/S355
ePset_Simplebim - Assembly Level: Leaf
Pset_BeamCommon - LoadBearing: no; Reference: DSS-0(?)
Tekla Quantity - Length: 574.794 mm; VOLUME_NET: 0.00287 m3; VOLUME_GROSS: 0.00287 m3; WEIGTH_NET: 22.5607 kg; WEIGTH_GROSS: 22.5607 kg; AREA_NET: 0.32039 m2; AREA_GROSS: 0.32039 m2; Width: 20 mm; Heigth: 250 mm
AVINOR - 07_Fase: F40; 08_Status: S1; 06_Omrade: TI; 05_ID-nummer: +TI=222.007; 03_Ansvar: 72245; 04_Kontrakt: 72245; 02_Prosjekt: T20100; 01_Lufthavnkode: ENGM
ePset_LocationTool - Splitting: ORIGINAL
ePset_SimplebimBasicQuantities - Volume, net (Simplebim): 0.00287397 m3; Area, sides, net (Simplebim): 0.320389 m2; Length (Simplebim): 574.794 mm; Weight, as steel (Simplebim): 22.5607 kg; Height (Simplebim): 20 mm; Width (Simplebim): 250 mm
Tekla Common - Grade: S355; Bottom elevation: +211.000; Top elevation: +211.020; Assembly mark: SS-0(?); Profile: PL20*250; Class: 320; Name: STÅLSØYLE; Part mark: DSS-0(?)

# IfcBeam: PL20*45 (3)
In: F
Description: PL20*45; Material: STEEL/S355
Tekla Quantity - AREA_NET: 0.0369 m2; AREA_GROSS: 0.0369 m2; VOLUME_NET: 0.00025 m3; VOLUME_GROSS: 0.00025 m3; WEIGTH_NET: 1.90755 kg; WEIGTH_GROSS: 1.90755 kg; Width: 20 mm; Heigth: 45 mm; Length: 270 mm
ePset_Simplebim - Assembly Level: Leaf
Pset_BeamCommon - LoadBearing: no; Reference: DSS-0(?)
AVINOR - 07_Fase: F40; 08_Status: S1; 06_Omrade: TI; 05_ID-nummer: +TI=222.007; 03_Ansvar: 72245; 04_Kontrakt: 72245; 02_Prosjekt: T20100; 01_Lufthavnkode: ENGM
ePset_SimplebimBasicQuantities - Area, sides, net (Simplebim): 0.0369 m2; Weight, as steel (Simplebim): 1.90755 kg; Volume, net (Simplebim): 0.000243 m3; Width (Simplebim): 20 mm; Height (Simplebim): 45 mm; Length (Simplebim): 270 mm
Tekla Common - Grade: S355; Bottom elevation: +211.020; Assembly mark: SS-0(?); Class: 320; Name: STÅLSØYLE; Part mark: DSS-0(?); Top elevation: +211.065; Profile: PL20*45
ePset_LocationTool - Splitting: ORIGINAL

# IfcBeam: PL260*25 (6)
In: F
Description: PL260*25; Material: STEEL/S355
ePset_SimplebimBasicQuantities - Width (Simplebim): 206.027 mm; Volume, net (Simplebim): 0.00133917 m3; Area, sides, net (Simplebim): 0.130435 m2; Height (Simplebim): 25 mm; Length (Simplebim): 260 mm; Weight, as steel (Simplebim): 10.5125 kg
ePset_Simplebim - Assembly Level: Leaf
AVINOR - 08_Status: S4; 07_Fase: F40; 06_Omrade: TI; 05_ID-nummer: +TI=223.008; 03_Ansvar: 72242; 04_Kontrakt: 72242; 02_Prosjekt: T20100; 01_Lufthavnkode: ENGM
Tekla Common - Grade: S355; Assembly mark: SB-6984; Name: STÅLBJELKE; Profile: PL260*25; Part mark: DSB-12219; Top elevation: +210.680; Class: 330; Bottom elevation: +210.655
Tekla Quantity - Length: 206.027 mm; WEIGTH_GROSS: 10.5125 kg; WEIGTH_NET: 10.5125 kg; VOLUME_GROSS: 0.00134 m3; VOLUME_NET: 0.00134 m3; AREA_NET: 0.13044 m2; AREA_GROSS: 0.13044 m2; Width: 25 mm; Heigth: 260 mm
Pset_BeamCommon - LoadBearing: no; Reference: DSB-12219
ePset_LocationTool - Splitting: ORIGINAL

# IfcBeam: PL265*10 (2)
In: F
Description: PL265*10; Material: STEEL/S355
ePset_SimplebimBasicQuantities - Width (Simplebim): 10 mm; Height (Simplebim): 265 mm; Length (Simplebim): 12515 mm; Area, sides, net (Simplebim): 6.88855 m2; Weight, as steel (Simplebim): 260.343 kg; Volume, net (Simplebim): 0.0331647 m3
ePset_Simplebim - Assembly Level: Leaf
ePset_LocationTool - Splitting: ORIGINAL
Pset_BeamCommon - LoadBearing: no; Reference: DSB-13433
Tekla Quantity - WEIGTH_NET: 260.345 kg; WEIGTH_GROSS: 260.345 kg; VOLUME_NET: 0.03316 m3; VOLUME_GROSS: 0.03316 m3; AREA_GROSS: 6.88859 m2; AREA_NET: 6.88859 m2; Width: 10 mm; Heigth: 265 mm; Length: 12515.1 mm
AVINOR - 08_Status: S4; 07_Fase: F40; 06_Omrade: TI; 05_ID-nummer: +TI=223.008; 03_Ansvar: 72242; 04_Kontrakt: 72242; 02_Prosjekt: T20100; 01_Lufthavnkode: ENGM
Tekla Common - Top elevation: +210.405; Grade: S355; Profile: PL265*10; Name: STÅLBJELKE; Assembly mark: SB-7670; Bottom elevation: +210.140; Part mark: DSB-13433; Class: 330

# IfcBeam: PL280*4267 (3)
In: F
Description: PL280*4267
ePset_Simplebim - Assembly Level: Leaf
AVINOR - 08_Status: S4; 07_Fase: F40; 06_Omrade: TI; 03_Ansvar: 72245; 04_Kontrakt: 72245; 02_Prosjekt: T20100; 05_ID-nummer: +TI=223.010; 01_Lufthavnkode: ENGM
Tekla Common - Bottom elevation: +211.000; Top elevation: +221.927; Profile: PL280*4267; Grade: GL36c; Name: TREBJELKE; Class: 430
ePset_SimplebimBasicQuantities - Width (Simplebim): 280 mm
ePset_LocationTool - Splitting: RESULT
Pset_BeamCommon - LoadBearing: no
Name | Part mark = Reference | Assembly mark | Volume, net (Simplebim) (m3) | Weight, as steel (Simplebim) (kg) | Length (Simplebim) (mm) | Height (Simplebim) (mm) | Area, sides, net (Simplebim) (m2)
2 x TREBJELKE | DTB-374(?) | TB-313(?) | 0.393405 | 3088.23 | 2887 | 2135 | 5.2406
TREBJELKE | DTB-376(?) | TB-315(?) | 0.393345 | 3087.75 | 657 | 3341 | 5.24581

# IfcBeam: PL5*31 (8)
In: F
Description: PL5*31; Material: STEEL/S355J2H
Tekla Quantity - AREA_NET: 0.00549 m2; VOLUME_GROSS: 0.00001 m3; VOLUME_NET: 0.00001 m3; WEIGTH_NET: 0.08761 kg; WEIGTH_GROSS: 0.08761 kg; Length: 72 mm; AREA_GROSS: 0.00223 m2; Width: 5 mm; Heigth: 31 mm
ePset_Simplebim - Assembly Level: Leaf
Tekla Common - Name: STÅLBJELKE; Grade: S355J2H; Profile: PL5*31; Part mark: DSB-0(?); Class: 330
ePset_SimplebimBasicQuantities - Volume, net (Simplebim): 0.00001116 m3; Weight, as steel (Simplebim): 0.087606 kg; Height (Simplebim): 5 mm; Width (Simplebim): 31 mm; Length (Simplebim): 72 mm; Area, sides, net (Simplebim): 0.005494 m2
Pset_BeamCommon - LoadBearing: no; Reference: DSB-0(?)
AVINOR - 08_Status: S4; 07_Fase: F90; 06_Omrade: TI; 04_Kontrakt: 72717; 02_Prosjekt: T20100; 05_ID-nummer: +TI=221.041; 03_Ansvar: 72101; 01_Lufthavnkode: ENGM
ePset_LocationTool - Splitting: ORIGINAL
Name | Assembly mark | Bottom elevation | Top elevation
2 x STÅLBJELKE | SD-786(?) | +213.437 | +213.483
2 x STÅLBJELKE | SD-786(?) | +210.987 | +211.033
2 x STÅLBJELKE | SD-787(?) | +213.315 | +213.361
2 x STÅLBJELKE | SD-788(?) | +213.255 | +213.293

# IfcBeam: PL8*100 (7)
In: F
Description: PL8*100; Material: STEEL/S355
ePset_Simplebim - Assembly Level: Leaf
ePset_SimplebimBasicQuantities - Height (Simplebim): 8 mm; Width (Simplebim): 100 mm
ePset_LocationTool - Splitting: ORIGINAL
Tekla Common - Grade: S355; Name: STÅLBJELKE; Profile: PL8*100; Class: 330
Pset_BeamCommon - LoadBearing: no
Tekla Quantity - Width: 8 mm; Heigth: 100 mm
AVINOR - 08_Status: S4; 07_Fase: F90; 06_Omrade: TI; 02_Prosjekt: T20100; 03_Ansvar: 72101; 01_Lufthavnkode: ENGM
Name | Volume, net (Simplebim) (m3) | Weight, as steel (Simplebim) (kg) = WEIGTH_NET (kg) = WEIGTH_GROSS (kg) | Length (Simplebim) (mm) = Length (mm) | Area, sides, net (Simplebim) (m2) = AREA_NET (m2) | Top elevation | Assembly mark | Part mark = Reference | Bottom elevation | VOLUME_GROSS (m3) = VOLUME_NET (m3) | AREA_GROSS (m2) | 04_Kontrakt | 05_ID-nummer
STÅLBJELKE | 0.000124 | 0.9734 | 155 | 0.03508 | +213.520 | SS-7492(?) | DSB-0(?) | +213.512 | 0.00013 | 0.03508 | 72717 | +TI=221.041
STÅLBJELKE | 0.000124 | 0.9734 | 155 | 0.03508 | +213.520 | SB-7473(?) | DSB-0(?) | +213.512 | 0.00013 | 0.03508 | 72717 | +TI=221.041
2 x STÅLBJELKE | 0.00016 | 1.256 | 200 | 0.0448 | +213.895 | SB-9013(?) | DSB-14986(?) | +213.887 | 0.00015 | 0.02 | 72253 | +TI=221.025
2 x STÅLBJELKE | 0.00016 | 1.256 | 200 | 0.0448 | +213.745 | SB-9013(?) | DSB-14986(?) | +213.737 | 0.00015 | 0.02 | 72253 | +TI=221.025
STÅLBJELKE | 0.00016 | 1.256 | 200 | 0.0448 | +213.895 | SB-12106(?) | DSB-20132(?) | +213.887 | 0.00015 | 0.02 | 72253 | +TI=221.025

# IfcBeam: PL8*140, STÅLBJELKE
In: F
Description: PL8*140; Material: STEEL/S355
Tekla Quantity - AREA_GROSS: 0.04368 m2; AREA_NET: 0.04368 m2; WEIGTH_NET: 1.23088 kg; WEIGTH_GROSS: 1.23088 kg; VOLUME_NET: 0.00015 m3; VOLUME_GROSS: 0.00015 m3; Width: 8 mm; Heigth: 140 mm; Length: 140 mm
ePset_Simplebim - Assembly Level: Leaf
ePset_LocationTool - Splitting: ORIGINAL
Pset_BeamCommon - LoadBearing: no; Reference: DSB-0(?)
AVINOR - 08_Status: S4; 07_Fase: F90; 06_Omrade: TI; 04_Kontrakt: 72717; 02_Prosjekt: T20100; 05_ID-nummer: +TI=221.041; 03_Ansvar: 72101; 01_Lufthavnkode: ENGM
ePset_SimplebimBasicQuantities - Volume, net (Simplebim): 0.0001568 m3; Area, sides, net (Simplebim): 0.04368 m2; Weight, as steel (Simplebim): 1.23088 kg; Width (Simplebim): 8 mm; Height (Simplebim): 140 mm; Length (Simplebim): 140 mm
Tekla Common - Grade: S355; Bottom elevation: +213.540; Assembly mark: SB-11956(?); Name: STÅLBJELKE; Part mark: DSB-0(?); Top elevation: +213.680; Class: 330; Profile: PL8*140

# IfcBeam: PL8*200 (3)
In: F
Description: PL8*200; Material: STEEL/S355
ePset_Simplebim - Assembly Level: Leaf
ePset_LocationTool - Splitting: ORIGINAL
Tekla Quantity - Width: 8 mm; Heigth: 200 mm
ePset_SimplebimBasicQuantities - Length (Simplebim): 200 mm
Pset_BeamCommon - LoadBearing: no; Reference: DSB-0(?)
Tekla Common - Grade: S355; Name: STÅLBJELKE; Profile: PL8*200; Part mark: DSB-0(?); Class: 330
AVINOR - 08_Status: S4; 07_Fase: F90; 06_Omrade: TI; 04_Kontrakt: 72717; 02_Prosjekt: T20100; 05_ID-nummer: +TI=221.041; 03_Ansvar: 72101; 01_Lufthavnkode: ENGM
Name | AREA_GROSS (m2) | AREA_NET (m2) | VOLUME_GROSS (m3) = VOLUME_NET (m3) | WEIGTH_GROSS (kg) = WEIGTH_NET (kg) = Weight, as steel (Simplebim) (kg) | Length (mm) | Volume, net (Simplebim) (m3) | Height (Simplebim) (mm) | Width (Simplebim) (mm) | Area, sides, net (Simplebim) (m2) | Top elevation | Bottom elevation | Assembly mark
2 x STÅLBJELKE | 0.0473 | 0.0473 | 0.00017 | 1.33136 | 106 | 0.0001696 | 8 | 106 | 0.047296 | +213.708 | +213.700 | SB-14759(?)
STÅLBJELKE | 0.06145 | 0.06144 | 0.00022 | 1.7584 | 140 | 0.000224 | 140 | 8 | 0.06144 | +213.680 | +213.540 | SB-11957(?)

# IfcBeam: PL8*30 (2)
In: F
Description: PL8*30; Material: STEEL/S355J0
ePset_Simplebim - Assembly Level: Leaf
Tekla Common - Profile: PL8*30; Name: STÅLBJELKE; Assembly mark: SB-11957(?); Top elevation: +213.693; Grade: S355J0; Part mark: DSB-19961(?); Class: 330; Bottom elevation: +213.567
ePset_SimplebimBasicQuantities - Height (Simplebim): 126.2 mm; Weight, as steel (Simplebim): 0.231481 kg; Volume, net (Simplebim): 0.000029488 m3; Width (Simplebim): 8 mm; Length (Simplebim): 30 mm; Area, sides, net (Simplebim): 0.00977747 m2
Tekla Quantity - Length: 126.2 mm; WEIGTH_NET: 0.23148 kg; AREA_GROSS: 0.00379 m2; Width: 8 mm; Heigth: 30 mm; WEIGTH_GROSS: 0.23776 kg; AREA_NET: 0.00978 m2; VOLUME_NET: 0.00003 m3; VOLUME_GROSS: 0.00003 m3
ePset_LocationTool - Splitting: ORIGINAL
Pset_BeamCommon - LoadBearing: no; Reference: DSB-19961(?)
AVINOR - 08_Status: S4; 07_Fase: F90; 06_Omrade: TI; 04_Kontrakt: 72717; 02_Prosjekt: T20100; 05_ID-nummer: +TI=221.041; 03_Ansvar: 72101; 01_Lufthavnkode: ENGM

# IfcBeam: PL8*33, STÅLBJELKE
In: F
Description: PL8*33; Material: STEEL/S355J0
ePset_SimplebimBasicQuantities - Volume, net (Simplebim): 0.0000319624 m3; Area, sides, net (Simplebim): 0.0104105 m2; Weight, as steel (Simplebim): 0.250905 kg; Height (Simplebim): 124.1 mm; Width (Simplebim): 8 mm; Length (Simplebim): 33 mm
ePset_Simplebim - Assembly Level: Leaf
Tekla Quantity - AREA_NET: 0.01041 m2; WEIGTH_NET: 0.2509 kg; WEIGTH_GROSS: 0.25718 kg; Length: 124.1 mm; Width: 8 mm; Heigth: 33 mm; AREA_GROSS: 0.0041 m2; VOLUME_NET: 0.00003 m3; VOLUME_GROSS: 0.00003 m3
ePset_LocationTool - Splitting: ORIGINAL
Tekla Common - Bottom elevation: +213.568; Top elevation: +213.692; Assembly mark: SB-7478(?); Name: STÅLBJELKE; Grade: S355J0; Part mark: DSB-19960(?); Class: 330; Profile: PL8*33
Pset_BeamCommon - LoadBearing: no; Reference: DSB-19960(?)
AVINOR - 08_Status: S4; 07_Fase: F90; 06_Omrade: TI; 04_Kontrakt: 72717; 02_Prosjekt: T20100; 05_ID-nummer: +TI=221.041; 03_Ansvar: 72101; 01_Lufthavnkode: ENGM

# IfcBeam: PL8*40 (10)
In: F
Description: PL8*40; Material: STEEL/S355J0
ePset_Simplebim - Assembly Level: Leaf
Tekla Quantity - AREA_NET: 0.01609 m2; AREA_GROSS: 0.00656 m2; VOLUME_NET: 0.00005 m3; VOLUME_GROSS: 0.00005 m3; WEIGTH_NET: 0.40569 kg; Width: 8 mm; Heigth: 40 mm; Length: 164 mm; WEIGTH_GROSS: 0.41197 kg
Pset_BeamCommon - Reference: DSB-19959(?); LoadBearing: no
ePset_SimplebimBasicQuantities - Weight, as steel (Simplebim): 0.405688 kg; Area, sides, net (Simplebim): 0.0160903 m2; Width (Simplebim): 8 mm; Length (Simplebim): 40 mm; Height (Simplebim): 164 mm; Volume, net (Simplebim): 0.00005168 m3
ePset_LocationTool - Splitting: ORIGINAL
Tekla Common - Profile: PL8*40; Bottom elevation: +213.528; Top elevation: +213.692; Name: STÅLBJELKE; Part mark: DSB-19959(?); Grade: S355J0; Class: 330
AVINOR - 08_Status: S4; 07_Fase: F90; 06_Omrade: TI; 04_Kontrakt: 72717; 02_Prosjekt: T20100; 05_ID-nummer: +TI=221.041; 03_Ansvar: 72101; 01_Lufthavnkode: ENGM
Name | Assembly mark
2 x STÅLBJELKE | SB-7474(?)
STÅLBJELKE | SB-0(?)
3 x STÅLBJELKE | SB-7477(?)
2 x STÅLBJELKE | SB-7476(?)
2 x STÅLBJELKE | SB-11895(?)

# IfcBeam: PL8*56 (2)
In: F
Description: PL8*56; Material: STEEL/S355
ePset_SimplebimBasicQuantities - Weight, as steel (Simplebim): 0.376569 kg; Area, sides, net (Simplebim): 0.0146051 m2; Volume, net (Simplebim): 0.0000479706 m3; Length (Simplebim): 55.7798 mm; Width (Simplebim): 8 mm; Height (Simplebim): 107.5 mm
ePset_Simplebim - Assembly Level: Leaf
Tekla Quantity - AREA_GROSS: 0.006 m2; VOLUME_NET: 0.00005 m3; VOLUME_GROSS: 0.00005 m3; AREA_NET: 0.0146 m2; WEIGTH_GROSS: 0.37657 kg; WEIGTH_NET: 0.37657 kg; Heigth: 55.7798 mm; Width: 8 mm; Length: 107.5 mm
ePset_LocationTool - Splitting: ORIGINAL
AVINOR - 04_Kontrakt: 72253; 05_ID-nummer: +TI=221.025; 08_Status: S4; 07_Fase: F90; 06_Omrade: TI; 02_Prosjekt: T20100; 03_Ansvar: 72101; 01_Lufthavnkode: ENGM
Tekla Common - Grade: S355; Part mark: DSB-20131(?); Name: STÅLBJELKE; Bottom elevation: +213.785; Profile: PL8*56; Class: 330; Top elevation: +213.892; Assembly mark: SB-12105(?)
Pset_BeamCommon - Reference: DSB-20131(?); LoadBearing: no

# IfcBeam: PL8*64 (2)
In: F
Description: PL8*64; Material: STEEL/S355
ePset_Simplebim - Assembly Level: Leaf
ePset_SimplebimBasicQuantities - Volume, net (Simplebim): 0.0000514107 m3; Weight, as steel (Simplebim): 0.403574 kg; Area, sides, net (Simplebim): 0.0158854 m2; Width (Simplebim): 8 mm; Length (Simplebim): 63.78 mm; Height (Simplebim): 107.5 mm
Tekla Quantity - VOLUME_NET: 0.00005 m3; VOLUME_GROSS: 0.00005 m3; AREA_NET: 0.01589 m2; AREA_GROSS: 0.00686 m2; Width: 8 mm; Length: 107.5 mm; Heigth: 63.78 mm; WEIGTH_GROSS: 0.43058 kg; WEIGTH_NET: 0.40357 kg
AVINOR - 04_Kontrakt: 72253; 05_ID-nummer: +TI=221.025; 08_Status: S4; 07_Fase: F90; 06_Omrade: TI; 02_Prosjekt: T20100; 03_Ansvar: 72101; 01_Lufthavnkode: ENGM
ePset_LocationTool - Splitting: ORIGINAL
Tekla Common - Grade: S355; Part mark: DSB-20130(?); Name: STÅLBJELKE; Bottom elevation: +213.785; Profile: PL8*64; Class: 330; Top elevation: +213.892; Assembly mark: SB-12104(?)
Pset_BeamCommon - Reference: DSB-20130(?); LoadBearing: no

# IfcBeam: PL8*66 (2)
In: F
Description: PL8*66; Material: STEEL/S355
Tekla Quantity - Length: 90.0027 mm; AREA_NET: 0.01438 m2; AREA_GROSS: 0.01438 m2; VOLUME_NET: 0.00005 m3; VOLUME_GROSS: 0.00005 m3; WEIGTH_GROSS: 0.37304 kg; WEIGTH_NET: 0.37304 kg; Width: 8 mm; Heigth: 66 mm
ePset_Simplebim - Assembly Level: Leaf
Tekla Common - Grade: S355; Name: STÅLBJELKE; Assembly mark: SB-14759(?); Part mark: DSB-0(?); Profile: PL8*66; Top elevation: +213.799; Bottom elevation: +213.709; Class: 330
ePset_LocationTool - Splitting: ORIGINAL
Pset_BeamCommon - LoadBearing: no; Reference: DSB-0(?)
AVINOR - 08_Status: S4; 07_Fase: F90; 06_Omrade: TI; 04_Kontrakt: 72717; 02_Prosjekt: T20100; 05_ID-nummer: +TI=221.041; 03_Ansvar: 72101; 01_Lufthavnkode: ENGM
ePset_SimplebimBasicQuantities - Height (Simplebim): 90.0027 mm; Weight, as steel (Simplebim): 0.373043 kg; Width (Simplebim): 8 mm; Length (Simplebim): 66 mm; Volume, net (Simplebim): 0.0000475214 m3; Area, sides, net (Simplebim): 0.0143764 m2

# IfcBeam: PL8*72 (6)
In: F
Description: PL8*72; Material: STEEL/S355
ePset_Simplebim - Assembly Level: Leaf
Tekla Common - Grade: S355; Name: STÅLBJELKE; Profile: PL8*72; Part mark: DSB-0(?); Class: 330
Tekla Quantity - Width: 8 mm; Heigth: 72.36 mm
ePset_LocationTool - Splitting: ORIGINAL
Pset_BeamCommon - LoadBearing: no; Reference: DSB-0(?)
AVINOR - 08_Status: S4; 07_Fase: F90; 06_Omrade: TI; 04_Kontrakt: 72717; 02_Prosjekt: T20100; 05_ID-nummer: +TI=221.041; 03_Ansvar: 72101; 01_Lufthavnkode: ENGM
ePset_SimplebimBasicQuantities - Width (Simplebim): 8 mm
Name | Assembly mark | Bottom elevation | Top elevation | WEIGTH_GROSS (kg) | AREA_NET (m2) | VOLUME_GROSS (m3) = VOLUME_NET (m3) | Length (mm) = Height (Simplebim) (mm) | WEIGTH_NET (kg) | AREA_GROSS (m2) | Area, sides, net (Simplebim) (m2) | Weight, as steel (Simplebim) (kg) | Length (Simplebim) (mm) | Volume, net (Simplebim) (m3)
STÅLBJELKE | SB-7475(?) | +213.710 | +213.874 | 0.74525 | 0.02278 | 0.00007 | 164 | 0.60727 | 0.01187 | 0.022778 | 0.607268 | 72.3612 | 0.000077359
STÅLBJELKE | SB-7478(?) | +213.568 | +213.692 | 0.56394 | 0.02025 | 0.00007 | 124.1 | 0.54333 | 0.00898 | 0.0202525 | 0.543329 | 72.36 | 0.0000692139
STÅLBJELKE | SB-7477(?) | +213.528 | +213.692 | 0.74525 | 0.02525 | 0.00009 | 164 | 0.6841 | 0.01187 | 0.0252463 | 0.684101 | 72.36 | 0.0000871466
STÅLBJELKE | SB-7474(?) | +213.528 | +213.692 | 0.74525 | 0.02525 | 0.00009 | 164 | 0.6841 | 0.01187 | 0.0252463 | 0.684101 | 72.36 | 0.0000871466
2 x STÅLBJELKE | SB-7476(?) | +213.528 | +213.692 | 0.74525 | 0.02525 | 0.00009 | 164 | 0.6841 | 0.01187 | 0.0252463 | 0.684101 | 72.36 | 0.0000871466

# IfcBeam: PL8*84 (2)
In: F
Description: PL8*84; Material: STEEL/S355
ePset_Simplebim - Assembly Level: Leaf
ePset_SimplebimBasicQuantities - Volume, net (Simplebim): 0.000090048 m3; Weight, as steel (Simplebim): 0.706877 kg; Width (Simplebim): 8 mm; Length (Simplebim): 84 mm; Height (Simplebim): 134 mm; Area, sides, net (Simplebim): 0.026 m2
Tekla Quantity - AREA_GROSS: 0.01126 m2; WEIGTH_GROSS: 0.70688 kg; WEIGTH_NET: 0.70688 kg; VOLUME_NET: 0.00009 m3; VOLUME_GROSS: 0.00009 m3; Width: 8 mm; Heigth: 84 mm; Length: 134 mm; AREA_NET: 0.026 m2
AVINOR - 04_Kontrakt: 72253; 05_ID-nummer: +TI=221.025; 08_Status: S4; 07_Fase: F90; 06_Omrade: TI; 02_Prosjekt: T20100; 03_Ansvar: 72101; 01_Lufthavnkode: ENGM
Pset_BeamCommon - LoadBearing: no; Reference: DSB-20045(?)
ePset_LocationTool - Splitting: ORIGINAL
Tekla Common - Grade: S355; Bottom elevation: +213.758; Name: STÅLBJELKE; Assembly mark: SB-12048(?); Profile: PL8*84; Class: 330; Top elevation: +213.892; Part mark: DSB-20045(?)

# IfcBeam: PLANNJA111 (30)
In: F
Description: PLANNJA111; Material: STEEL/S355J2H
ePset_Simplebim - Assembly Level: Leaf
ePset_LocationTool - Splitting: ORIGINAL
ePset_SimplebimBasicQuantities - Height (Simplebim): 111.5 mm
Tekla Quantity - Heigth: 111.5 mm
AVINOR - 08_Status: S4; 07_Fase: F90; 06_Omrade: TI; 04_Kontrakt: 72717; 02_Prosjekt: T20100; 05_ID-nummer: +TI=251.049; 03_Ansvar: 72101; 01_Lufthavnkode: ENGM
Pset_BeamCommon - LoadBearing: no
Tekla Common - Bottom elevation: +213.700; Name: STÅLBJELKE; Grade: S355J2H; Top elevation: +213.811; Profile: PLANNJA111; Class: 330
Name | Volume, net (Simplebim) (m3) | Area, sides, net (Simplebim) (m2) = AREA_NET (m2) | Width (Simplebim) (mm) = Width (mm) | Length (Simplebim) (mm) = Length (mm) | Weight, as steel (Simplebim) (kg) = WEIGTH_NET (kg) | VOLUME_NET (m3) | AREA_GROSS (m2) | WEIGTH_GROSS (kg) | VOLUME_GROSS (m3) | Reference = Part mark | Assembly mark
8 x STÅLBJELKE | 0.00226517 | 4.5366 | 720 | 1986.5 | 17.7816 | 0.00227 | 0 | 17.4001 | 0.00222 | DSB-22297(?) | SB-13317(?)
STÅLBJELKE | 0.00145551 | 2.91646 | 452.512 | 1986.5 | 11.4258 | 0.00146 | 0 | 17.4001 | 0.00222 | DSB-22295(?) | SB-13315(?)
STÅLBJELKE | 0.00239269 | 4.79516 | 653 | 2357.09 | 18.7826 | 0.00239 | 0 | 20.6462 | 0.00263 | DSB-22298(?) | SB-13318(?)
STÅLBJELKE | 0.00373525 | 7.48035 | 720 | 3786.73 | 29.3217 | 0.00374 | 0 | 33.1686 | 0.00423 | DSB-22288(?) | SB-13308(?)
2 x STÅLBJELKE | 0.00431795 | 8.64574 | 720 | 3786.73 | 33.8959 | 0.00432 | 0 | 33.1686 | 0.00423 | DSB-22299(?) | SB-13319(?)
STÅLBJELKE | 0.00414669 | 8.30529 | 720 | 3786.73 | 32.5515 | 0.00415 | 0 | 33.1686 | 0.00423 | DSB-22287(?) | SB-13307(?)
STÅLBJELKE | 0.00443294 | 8.87693 | 720 | 4148.81 | 34.7986 | 0.00443 | 0 | 36.3401 | 0.00463 | DSB-22286(?) | SB-13306(?)
STÅLBJELKE | 0.0048027 | 9.61624 | 720 | 4395.28 | 37.7012 | 0.0048 | 0 | 38.499 | 0.0049 | DSB-22300(?) | SB-13320(?)
STÅLBJELKE | 0.00508158 | 10.1745 | 720 | 4639.85 | 39.8904 | 0.00507 | 0.00001 | 40.6412 | 0.00518 | DSB-22301(?) | SB-13321(?)
STÅLBJELKE | 0.00530564 | 10.623 | 720 | 4798.28 | 41.6493 | 0.00531 | 0.00001 | 42.0289 | 0.00535 | DSB-22284(?) | SB-13304(?)
STÅLBJELKE | 0.00481577 | 9.64333 | 720 | 4798.28 | 37.8038 | 0.00483 | 0.00001 | 42.0289 | 0.00535 | DSB-22285(?) | SB-13305(?)
STÅLBJELKE | 0.006076 | 12.1675 | 720 | 6081.94 | 47.6966 | 0.00608 | 0.00001 | 53.2727 | 0.00679 | DSB-22283(?) | SB-13303(?)
8 x STÅLBJELKE | 0.00528557 | 10.5827 | 720 | 4635.31 | 41.4917 | 0.0053 | 0.00001 | 40.6015 | 0.00517 | DSB-22302(?) | SB-13322(?)
STÅLBJELKE | 0.00511144 | 10.2358 | 720 | 4635.31 | 40.1248 | 0.00512 | 0.00001 | 40.6015 | 0.00517 | DSB-22282(?) | SB-13302(?)
STÅLBJELKE | 0.00515945 | 10.3311 | 720 | 4635.31 | 40.5017 | 0.00516 | 0.00001 | 40.6015 | 0.00517 | DSB-22281(?) | SB-13301(?)

# IfcBeam: PLANNJA45 (2)
In: F
Description: PLANNJA45; Material: STEEL/S355
ePset_Simplebim - Assembly Level: Leaf
ePset_LocationTool - Splitting: ORIGINAL
Tekla Common - Grade: S355; Name: STÅLBJELKE; Profile: PLANNJA45; Top elevation: +210.724; Bottom elevation: +210.680; Class: 330
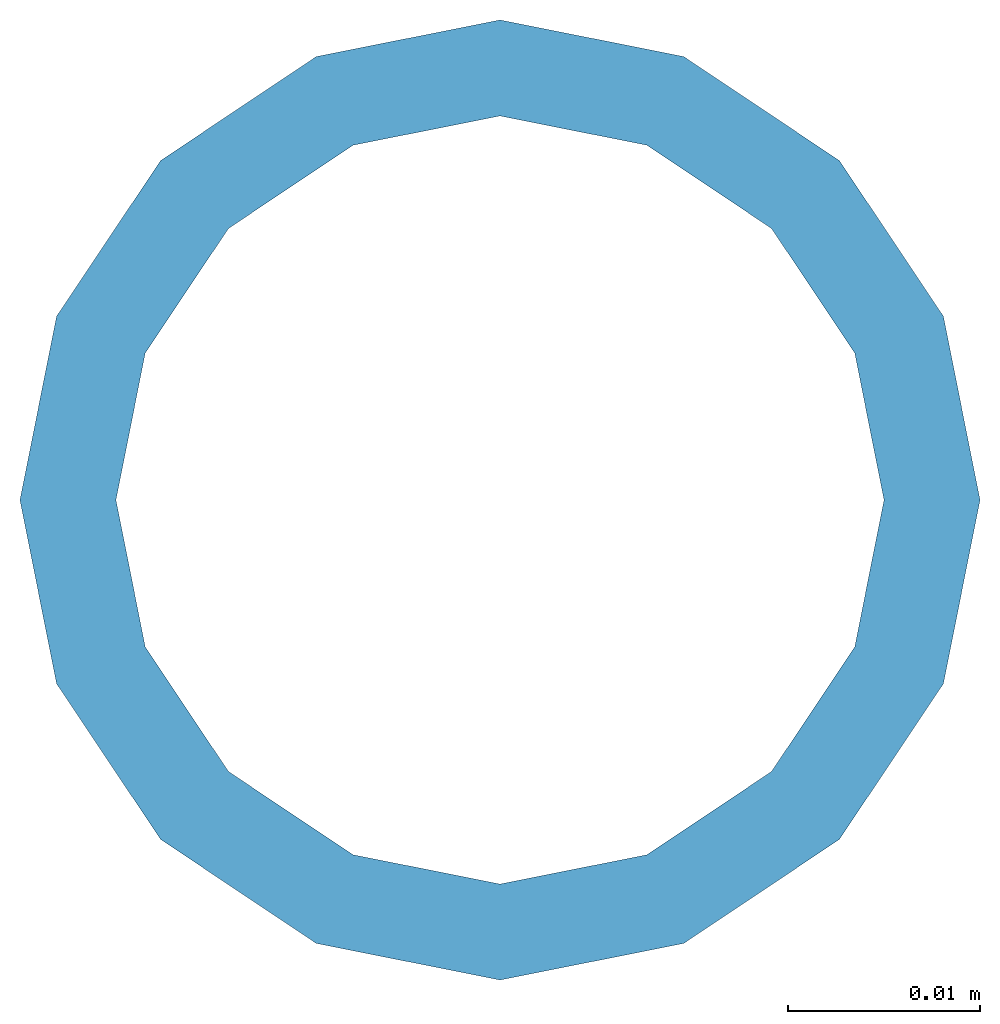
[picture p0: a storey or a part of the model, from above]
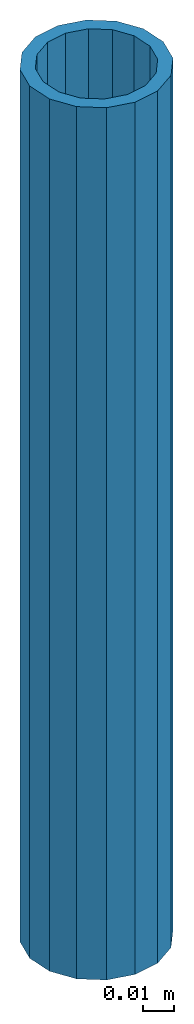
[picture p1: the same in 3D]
Properties of the parts of a building model (IFC2X3), part 2 of 6

# IfcBeam: PLANNJA45 (2)
Tekla Quantity - Heigth: 43.6 mm; Length: 2860.01 mm; WEIGTH_GROSS: 20.483 kg; AREA_GROSS: 0 m2; VOLUME_GROSS: 0.00261 m3
Pset_BeamCommon - LoadBearing: no
ePset_SimplebimBasicQuantities - Length (Simplebim): 2860.01 mm; Height (Simplebim): 43.6 mm
AVINOR - 08_Status: S4; 07_Fase: F40; 05_ID-nummer: +TI=251.008; 06_Omrade: TI; 03_Ansvar: 72242; 04_Kontrakt: 72242; 02_Prosjekt: T20100; 01_Lufthavnkode: ENGM
Name | Part mark = Reference | Assembly mark | Width (mm) = Width (Simplebim) (mm) | AREA_NET (m2) = Area, sides, net (Simplebim) (m2) | VOLUME_NET (m3) | WEIGTH_NET (kg) = Weight, as steel (Simplebim) (kg) | Volume, net (Simplebim) (m3)
STÅLBJELKE | DSB-14467 | SB-8722 | 574.324 | 4.03722 | 0.00202 | 15.8181 | 0.00201505
STÅLBJELKE | DSB-14496 | SB-8749 | 1042.63 | 7.33874 | 0.00366 | 28.772 | 0.00366522

# IfcBeam: RHS150*100*6.3 (6)
In: F
Description: RHS150*100*6.3; Material: STEEL/S355J2H
ePset_Simplebim - Assembly Level: Leaf
ePset_LocationTool - Splitting: ORIGINAL
Pset_BeamCommon - LoadBearing: no
ePset_SimplebimBasicQuantities - Height (Simplebim): 150 mm; Width (Simplebim): 100 mm
Tekla Quantity - Width: 100 mm; Heigth: 150 mm
Tekla Common - Bottom elevation: +213.750; Name: STÅLBJELKE; Grade: S355J2H; Profile: RHS150*100*6.3; Top elevation: +213.900; Class: 330
AVINOR - 08_Status: S4; 07_Fase: F90; 06_Omrade: TI; 04_Kontrakt: 72717; 02_Prosjekt: T20100; 05_ID-nummer: +TI=221.041; 03_Ansvar: 72101; 01_Lufthavnkode: ENGM
Name | Reference = Part mark | Volume, net (Simplebim) (m3) | Weight, as steel (Simplebim) (kg) = WEIGTH_NET (kg) | Length (Simplebim) (mm) = Length (mm) | Area, sides, net (Simplebim) (m2) | AREA_GROSS (m2) | WEIGTH_GROSS (kg) | AREA_NET (m2) | VOLUME_GROSS (m3) | VOLUME_NET (m3) | Assembly mark
STÅLBJELKE | DSB-22352(?) | 0.00767611 | 60.2575 | 2647.85 | 2.44483 | 1.28686 | 61.7334 | 1.27601 | 0.00786 | 0.00768 | SB-10597(?)
STÅLBJELKE | DSB-22353(?) | 0.00752533 | 59.0739 | 2671.63 | 2.40024 | 1.29841 | 62.2878 | 1.25273 | 0.00793 | 0.00753 | SB-10385(?)
STÅLBJELKE | DSB-22354(?) | 0.0163313 | 128.201 | 5615.55 | 5.19578 | 2.72916 | 130.924 | 2.71179 | 0.01668 | 0.01633 | SB-10386(?)
STÅLBJELKE | DSB-22355(?) | 0.0251971 | 197.797 | 8496.87 | 8.00875 | 4.12948 | 198.1 | 4.17993 | 0.02524 | 0.0252 | SB-10595(?)
2 x STÅLBJELKE | DSB-22350(?) | 0.0252608 | 198.297 | 8444.93 | 8.02528 | 4.10423 | 196.889 | 4.18856 | 0.02508 | 0.02526 | SB-13280(?)

# IfcBeam: RHS150*100*8 (6)
In: F
Description: RHS150*100*8; Material: STEEL/S355
Tekla Quantity - Width: 100 mm; Heigth: 150 mm
ePset_Simplebim - Assembly Level: Leaf
ePset_SimplebimBasicQuantities - Width (Simplebim): 100 mm; Height (Simplebim): 150 mm
Pset_BeamCommon - LoadBearing: no
Tekla Common - Grade: S355; Name: STÅLBJELKE; Profile: RHS150*100*8; Class: 330
ePset_LocationTool - Splitting: ORIGINAL
AVINOR - 04_Kontrakt: 72253; 05_ID-nummer: +TI=221.025; 08_Status: S4; 07_Fase: F90; 06_Omrade: TI; 02_Prosjekt: T20100; 03_Ansvar: 72101; 01_Lufthavnkode: ENGM
Name | AREA_NET (m2) | AREA_GROSS (m2) | WEIGTH_GROSS (kg) | WEIGTH_NET (kg) = Weight, as steel (Simplebim) (kg) | Length (mm) | VOLUME_NET (m3) | VOLUME_GROSS (m3) | Volume, net (Simplebim) (m3) | Length (Simplebim) (mm) | Area, sides, net (Simplebim) (m2) | Reference = Part mark | Top elevation | Bottom elevation | Assembly mark
STÅLBJELKE | 0.94534 | 0.91974 | 55.4578 | 55.9661 | 1904.23 | 0.00714 | 0.00706 | 0.00712944 | 1904.23 | 1.78985 | DSS-6603(?) | +213.895 | +213.745 | SS-9350(?)
STÅLBJELKE | 0.89875 | 0.87423 | 52.7132 | 53.1963 | 1809.99 | 0.00678 | 0.00671 | 0.0067766 | 1809.99 | 1.70164 | DSS-6602(?) | +213.555 | +213.405 | SS-9349(?)
STÅLBJELKE | 2.23454 | 2.1793 | 131.405 | 132.609 | 4512 | 0.01689 | 0.01674 | 0.0168929 | 4512 | 4.23072 | DSS-6613(?) | +213.895 | +213.745 | SS-9352(?)
STÅLBJELKE | 2.28397 | 2.22759 | 134.317 | 135.548 | 4611.99 | 0.01728 | 0.01712 | 0.0172673 | 4611.99 | 4.32431 | DSS-6614(?) | +213.895 | +213.745 | SS-9353(?)
STÅLBJELKE | 2.23454 | 2.1793 | 131.405 | 132.609 | 4512 | 0.01689 | 0.01674 | 0.0168929 | 4512 | 4.23072 | DSS-6601(?) | +213.555 | +213.405 | SS-9348(?)
STÅLBJELKE | 2.23454 | 2.1793 | 131.405 | 132.609 | 4511.99 | 0.01689 | 0.01674 | 0.0168929 | 4512 | 4.23072 | DSS-6601(?) | +213.555 | +213.405 | SS-9348(?)

# IfcBeam: RHS150*5 (3)
In: F
Description: RHS150*5
ePset_Simplebim - Assembly Level: Leaf
Tekla Common - Top elevation: +210.415; Grade: S355; Profile: RHS150*5; Bottom elevation: +210.265; Name: STÅLBJELKE; Class: 330
AVINOR - 08_Status: S4; 07_Fase: F40; 06_Omrade: TI; 05_ID-nummer: +TI=223.008; 03_Ansvar: 72242; 04_Kontrakt: 72242; 02_Prosjekt: T20100; 01_Lufthavnkode: ENGM
Pset_BeamCommon - LoadBearing: no
ePset_SimplebimBasicQuantities - Height (Simplebim): 150 mm; Width (Simplebim): 150 mm
ePset_LocationTool - Splitting: RESULT
Name | Assembly mark | Part mark = Reference | Length (Simplebim) (mm) | Weight, as steel (Simplebim) (kg) | Area, sides, net (Simplebim) (m2) | Volume, net (Simplebim) (m3)
STÅLBJELKE | SB-6203 | DSB-983 | 1335 | 30.3917 | 1.55442 | 0.00387156
STÅLBJELKE | SB-6203 | DSB-983 | 1335 | 30.3913 | 1.5544 | 0.0038715
STÅLBJELKE | SB-7036 | DSB-12261 | 2740 | 62.3761 | 3.1842 | 0.007946

# IfcBeam: RHS150*50*5 (2)
In: F
Description: RHS150*50*5; Material: STEEL/S355
ePset_Simplebim - Assembly Level: Leaf
Tekla Quantity - AREA_NET: 0.17493 m2; AREA_GROSS: 0.17493 m2; Width: 50 mm; Heigth: 150 mm; Length: 440 mm; WEIGTH_GROSS: 6.5626 kg; WEIGTH_NET: 6.5626 kg; VOLUME_GROSS: 0.00084 m3; VOLUME_NET: 0.00084 m3
Pset_BeamCommon - LoadBearing: no; Reference: DSS-7668(?)
ePset_LocationTool - Splitting: ORIGINAL
ePset_SimplebimBasicQuantities - Area, sides, net (Simplebim): 0.3382 m2; Height (Simplebim): 150 mm; Length (Simplebim): 440 mm; Width (Simplebim): 50 mm; Volume, net (Simplebim): 0.000836 m3; Weight, as steel (Simplebim): 6.5626 kg
AVINOR - 04_Kontrakt: 72253; 05_ID-nummer: +TI=221.025; 08_Status: S4; 07_Fase: F90; 06_Omrade: TI; 02_Prosjekt: T20100; 03_Ansvar: 72101; 01_Lufthavnkode: ENGM
Tekla Common - Grade: S355; Name: STÅLBJELKE; Assembly mark: SS-9602(?); Profile: RHS150*50*5; Part mark: DSS-7668(?); Class: 330
Name | Top elevation | Bottom elevation
STÅLBJELKE | +213.555 | +213.405
STÅLBJELKE | +213.895 | +213.745

# IfcBeam: RHS200*100*6.3, STÅLBJELKE
In: F
Description: RHS200*100*6.3; Material: STEEL/S355J2H
ePset_LocationTool - Splitting: ORIGINAL
ePset_Simplebim - Assembly Level: Leaf
Tekla Common - Top elevation: +213.800; Name: STÅLBJELKE; Assembly mark: SB-10384(?); Grade: S355J2H; Bottom elevation: +213.600; Class: 330; Part mark: DSB-19538(?); Profile: RHS200*100*6.3
ePset_SimplebimBasicQuantities - Weight, as steel (Simplebim): 197.536 kg; Volume, net (Simplebim): 0.0251639 m3; Area, sides, net (Simplebim): 7.99779 m2; Length (Simplebim): 7041.07 mm; Height (Simplebim): 200 mm; Width (Simplebim): 100 mm
Tekla Quantity - VOLUME_GROSS: 0.02535 m3; WEIGTH_NET: 197.536 kg; WEIGTH_GROSS: 198.981 kg; VOLUME_NET: 0.02516 m3; Length: 7041.07 mm; AREA_GROSS: 4.12607 m2; Width: 100 mm; Heigth: 200 mm; AREA_NET: 4.12896 m2
AVINOR - 08_Status: S4; 07_Fase: F90; 06_Omrade: TI; 04_Kontrakt: 72717; 02_Prosjekt: T20100; 05_ID-nummer: +TI=221.041; 03_Ansvar: 72101; 01_Lufthavnkode: ENGM
Pset_BeamCommon - LoadBearing: no; Reference: DSB-19538(?)

# IfcBeam: RHS200*200*10 (2)
In: F
Description: RHS200*200*10; Material: STEEL/S355
Pset_BeamCommon - Reference: DSB-12381; LoadBearing: no
ePset_Simplebim - Assembly Level: Leaf
AVINOR - 08_Status: S4; 07_Fase: F40; 06_Omrade: TI; 05_ID-nummer: +TI=223.008; 03_Ansvar: 72242; 04_Kontrakt: 72242; 02_Prosjekt: T20100; 01_Lufthavnkode: ENGM
ePset_LocationTool - Splitting: ORIGINAL
ePset_SimplebimBasicQuantities - Weight, as steel (Simplebim): 36.3926 kg; Volume, net (Simplebim): 0.004636 m3; Area, sides, net (Simplebim): 0.9424 m2; Width (Simplebim): 200 mm; Length (Simplebim): 200 mm; Height (Simplebim): 610 mm
Tekla Quantity - AREA_NET: 0.496 m2; WEIGTH_NET: 36.3926 kg; VOLUME_NET: 0.00463 m3; WEIGTH_GROSS: 36.1532 kg; VOLUME_GROSS: 0.0046 m3; Width: 200 mm; Heigth: 200 mm; Length: 610 mm; AREA_GROSS: 0.47519 m2
Tekla Common - Grade: S355; Bottom elevation: +210.080; Profile: RHS200*200*10; Name: STÅLBJELKE; Part mark: DSB-12381; Assembly mark: SB-7129; Top elevation: +210.690; Class: 330

# IfcBeam: RHS80*8 (2)
In: F
Description: RHS80*8; Material: STEEL/S355J2H
ePset_Simplebim - Assembly Level: Leaf
Tekla Common - Profile: RHS80*8; Assembly mark: SB-7473(?); Name: STÅLBJELKE; Grade: S355J2H; Part mark: DSB-22094(?); Class: 330
Tekla Quantity - VOLUME_GROSS: 0.00707 m3; VOLUME_NET: 0.00707 m3; WEIGTH_NET: 55.5254 kg; WEIGTH_GROSS: 55.5254 kg; AREA_GROSS: 0.98496 m2; AREA_NET: 0.98496 m2; Length: 3070.01 mm; Width: 80 mm; Heigth: 80 mm
ePset_SimplebimBasicQuantities - Volume, net (Simplebim): 0.0070733 m3; Weight, as steel (Simplebim): 55.5254 kg; Length (Simplebim): 3070.01 mm; Area, sides, net (Simplebim): 1.77293 m2; Height (Simplebim): 80 mm; Width (Simplebim): 80 mm
ePset_LocationTool - Splitting: ORIGINAL
Pset_BeamCommon - LoadBearing: no; Reference: DSB-22094(?)
AVINOR - 08_Status: S4; 07_Fase: F90; 06_Omrade: TI; 04_Kontrakt: 72717; 02_Prosjekt: T20100; 05_ID-nummer: +TI=221.041; 03_Ansvar: 72101; 01_Lufthavnkode: ENGM
Name | Bottom elevation | Top elevation
STÅLBJELKE | +211.720 | +211.800
STÅLBJELKE | +213.000 | +213.080

# IfcBeam: RHS80*80*6.3 (3)
In: F
Description: RHS80*80*6.3; Material: STEEL/S355
ePset_Simplebim - Assembly Level: Leaf
Tekla Quantity - Width: 80 mm; Heigth: 80 mm
Tekla Common - Grade: S355; Bottom elevation: +213.815; Top elevation: +213.895; Name: STÅLBJELKE; Profile: RHS80*80*6.3; Class: 330
AVINOR - 04_Kontrakt: 72253; 05_ID-nummer: +TI=221.025; 08_Status: S4; 07_Fase: F90; 06_Omrade: TI; 02_Prosjekt: T20100; 03_Ansvar: 72101; 01_Lufthavnkode: ENGM
ePset_SimplebimBasicQuantities - Height (Simplebim): 80 mm; Width (Simplebim): 80 mm
Pset_BeamCommon - LoadBearing: no
ePset_LocationTool - Splitting: ORIGINAL
Name | WEIGTH_NET (kg) = Weight, as steel (Simplebim) (kg) | WEIGTH_GROSS (kg) | VOLUME_NET (m3) | AREA_NET (m2) | Length (mm) = Length (Simplebim) (mm) | AREA_GROSS (m2) | VOLUME_GROSS (m3) | Assembly mark | Part mark = Reference | Volume, net (Simplebim) (m3) | Area, sides, net (Simplebim) (m2)
STÅLBJELKE | 119.55 | 118.441 | 0.01523 | 2.62601 | 8199.99 | 2.5092 | 0.01508 | SB-14385(?) | DSB-24032(?) | 0.0152293 | 4.83843
STÅLBJELKE | 31.3314 | 31.0405 | 0.004 | 0.6897 | 2149.03 | 0.6576 | 0.00396 | SB-14386(?) | DSB-24033(?) | 0.00399126 | 1.27078
STÅLBJELKE | 11.8094 | 11.6998 | 0.0015 | 0.26122 | 810.01 | 0.24786 | 0.0015 | SB-14387(?) | DSB-24034(?) | 0.00150438 | 0.481296

# IfcBeam: WQ545*10-35*360-25*700, STÅLBJELKE
In: F
Description: WQ545*10-35*360-25*700; Material: STEEL/S355
ePset_Simplebim - Assembly Level: Leaf
Tekla Common - Grade: S355; Top elevation: +210.673; Name: STÅLBJELKE; Assembly mark: SB-7670; Part mark: DSB-10287; Bottom elevation: +210.102; Profile: WQ545*10-35*360-25*700; Class: 330
Pset_BeamCommon - Reference: DSB-10287; LoadBearing: no
AVINOR - 08_Status: S4; 07_Fase: F40; 06_Omrade: TI; 05_ID-nummer: +TI=223.008; 03_Ansvar: 72242; 04_Kontrakt: 72242; 02_Prosjekt: T20100; 01_Lufthavnkode: ENGM
ePset_SimplebimBasicQuantities - Volume, net (Simplebim): 0.512348 m3; Area, sides, net (Simplebim): 53.982 m2; Weight, as steel (Simplebim): 4021.93 kg; Width (Simplebim): 700 mm; Height (Simplebim): 570 mm; Length (Simplebim): 12658.6 mm
ePset_LocationTool - Splitting: ORIGINAL
Tekla Quantity - WEIGTH_GROSS: 4078.99 kg; AREA_GROSS: 54.3249 m2; VOLUME_NET: 0.51235 m3; VOLUME_GROSS: 0.51962 m3; WEIGTH_NET: 4021.93 kg; AREA_NET: 53.982 m2; Width: 700 mm; Heigth: 570 mm; Length: 12658.6 mm

# IfcBuildingElementProxy (5)
ePset_Simplebim - Assembly Level: Leaf
Name | In | Splitting | Thickness (Simplebim) (mm) | Length (Simplebim) (mm) | Volume, net (Simplebim) (m3) | Area, largest surface, net (Simplebim) (m2) | Height (Simplebim) (mm)
11143573 | Nivå E | ORIGINAL | 8188.37 | 9465.99 | 0.0748153 | 15.3797 | 136.457 | Pset_ProductRequirements - Category: Generic Models; Group: Model Group:TI-F26:11143567
Håndslukker | Nivå F | ORIGINAL | 179.937 | 323.075 | 0.0130382 | 0.261216 | 600.535
hette 1100-2000-550 2ø315 | Nivå F | ORIGINAL | 1500 | 2000 | 1.50009 | 3 | 509.515
hette 1400-1400-450 | Nivå F | ORIGINAL | 1400 | 1400 | 1.52545 | 3.90646 | 510
11143572 | Nivå E | RESULT | 5151 | 9665 | 0.047515 | 3.03018 | 169 | Pset_ProductRequirements - Category: Generic Models; Group: Model Group:TI-F26:11143567

# IfcBuildingElementProxy: A234 - Gitter:A241 - Gitter 300 x 300_UK_2550 (3)
In: Nivå F
Type - Material: <Unnamed>
ePset_Simplebim - Assembly Level: Leaf
Pset_BuildingElementProxyCommon - Reference: A241 - Gitter 300 x 300_UK_2550; sets with these values: 2
ePset_SimplebimBasicQuantities - Height (Simplebim): 300 mm; Thickness (Simplebim): 300 mm
ePset_LocationTool - Splitting: ORIGINAL
AVINOR - 08_Status: S4; 07_Fase: F90; 05_ID-nummer: +TI=245.051; 06_Omrade: TI; 03_Ansvar: 72717; 02_Prosjekt: T20100; 01_Lufthavnkode: ENGM
Name (A234 - Gitter:A241 - Gitter 300 x 300_UK_2550:...) | Area, largest surface, net (Simplebim) (m2) | Length (Simplebim) (mm) | Volume, net (Simplebim) (m3)
66414007 | 1.39875 | 4662.5 | 0.419625
66414070 | 0.6015 | 2005 | 0.18045
66414279 | 1.39875 | 4662.5 | 0.419625

# IfcBuildingElementProxy: A247 - Fendring - Konsoll FE-S01:A247 - Fendring - Konsoll FE-S01 (10)
In: Nivå F
Type - Material: _NSW Stål
ePset_Simplebim - Assembly Level: Leaf
ePset_LocationTool - Splitting: ORIGINAL
Pset_QuantityTakeOff - Reference: A247 - Fendring - Konsoll FE-S01; sets with these values: 2
AVINOR - 03_Ansvar: 72253; 08_Status: S4; 07_Fase: F90; 06_Omrade: TI; 05_ID-nummer: +TI=251.012-IY0002; 02_Prosjekt: T20100; 01_Lufthavnkode: ENGM
ePset_SimplebimBasicQuantities - Length (Simplebim): 100.913 mm; Area, largest surface, net (Simplebim): 0.0127758 m2; Height (Simplebim): 174.945 mm; Thickness (Simplebim): 15 mm; Volume, net (Simplebim): 0.000191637 m3
Name (A247 - Fendring - Konsoll FE-S01:A247 - Fendring - Konsoll FE-S01:...)
61720054
61720584
61721114
61721644
61722174
61722704
61723234
61723766
61724296
61724826

# IfcBuildingElementProxy: A275 - Pylon - venstrehengslet:A275 - Pylon - venstrehengslet, A275 - Pylon - venstrehengslet:A275 - Pylon - venstrehengslet:68419012
In: Nivå F
Type - Material: <Unnamed>
AVINOR - 08_Status: S1; 06_Omrade: TI; 02_Prosjekt: T20100; 07_Fase: F50; 03_Ansvar: OSL; 01_Lufthavnkode: ENGM
ePset_Simplebim - Assembly Level: Leaf
ePset_SimplebimBasicQuantities - Area, largest surface, net (Simplebim): 1.78713 m2; Volume, net (Simplebim): 0.0408924 m3; Thickness (Simplebim): 195 mm; Length (Simplebim): 752 mm; Height (Simplebim): 2500 mm
Pset_QuantityTakeOff - Reference: A275 - Pylon - venstrehengslet; sets with these values: 2
ePset_LocationTool - Splitting: ORIGINAL

# IfcBuildingElementProxy: A36 - Føringsskinner rullegitter:A36 - Føringsskinner rullegitter (6)
In: Nivå F
Type - Material: <Unnamed>
ePset_Simplebim - Assembly Level: Leaf
ePset_SimplebimBasicQuantities - Volume, net (Simplebim): 0.00117 m3; Area, largest surface, net (Simplebim): 0.25 m2; Thickness (Simplebim): 38 mm; Length (Simplebim): 100 mm; Height (Simplebim): 2500 mm
Pset_BuildingElementProxyCommon - Reference: A36 - Føringsskinner rullegitter; sets with these values: 2
AVINOR - 08_Status: S4; 07_Fase: F90; 05_ID-nummer: +TI=245.051; 06_Omrade: TI; 03_Ansvar: 72717; 02_Prosjekt: T20100; 01_Lufthavnkode: ENGM
ePset_LocationTool - Splitting: ORIGINAL
Name (A36 - Føringsskinner rullegitter:A36 - Føringsskinner rullegitter:...)
62671091
62671092
62671093
62671094
62671095
62671096

# IfcColumn: A222 - Ekstrudert Aluminiumsprofil - Hjørneprofil - Hel:A222 - Ekstrudert Aluminiumsprofil (8)
Type - PredefinedType: COLUMN; Material: _NSW Aluminium
Type - Pset_ColumnCommon - LoadBearing: yes
ePset_Simplebim - Assembly Level: Leaf
AVINOR - 03_Ansvar: 72253; 08_Status: S4; 07_Fase: F90; 06_Omrade: TI; 05_ID-nummer: +TI=245.028; 02_Prosjekt: T20100; 01_Lufthavnkode: ENGM
ePset_SimplebimBasicQuantities - Width (Simplebim): 100 mm; Depth (Simplebim): 100 mm
Pset_QuantityTakeOff - Reference: A222 - Ekstrudert Aluminiumsprofil; sets with these values: 2
Pset_ColumnCommon - Reference: A222 - Ekstrudert Aluminiumsprofil; IsExternal: no
Name (A222 - Ekstrudert Aluminiumsprofil - Hjørneprofil - Hel:A222 - Ekstrudert Aluminiumsprofil:...) | In | Height (Simplebim) (mm) | Volume, net (Simplebim) (m3) | Area, sides, net (Simplebim) (m2) | Weight, as steel (Simplebim) (kg) | Splitting
44746933 | Nivå F | 2800 | 0.00218628 | 1.10919 | 17.1623 | ORIGINAL | Group: Model Group:A240 - Hjørneprofiler - Teknisk Sjakt (members excluded):44025593
44746937 | Nivå F | 2800 | 0.00218628 | 1.10919 | 17.1623 | ORIGINAL | Group: Model Group:A240 - Hjørneprofiler - Teknisk Sjakt (members excluded):44025593
61927427 | Nivå F | 2800 | 0.00218628 | 1.10919 | 17.1623 | ORIGINAL
61927429 | Nivå F | 2800 | 0.00218628 | 1.10919 | 17.1623 | ORIGINAL
44746937 | Nivå G - 2,0m | 500 | 0.000390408 | 0.198069 | 3.0647 | RESULT | Group: Model Group:A240 - Hjørneprofiler - Teknisk Sjakt (members excluded):44025593
61927429 | Nivå G - 2,0m | 500 | 0.000390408 | 0.198069 | 3.0647 | RESULT
61927427 | Nivå G - 2,0m | 500 | 0.000390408 | 0.198069 | 3.0647 | RESULT
44746933 | Nivå G - 2,0m | 500 | 0.000390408 | 0.198069 | 3.0647 | RESULT | Group: Model Group:A240 - Hjørneprofiler - Teknisk Sjakt (members excluded):44025593

# IfcColumn: B220 - Søylefot - Primærdragere - PirNord1:B220 - Søylefot - Primærdragere - PirNord - h=470 (4)
In: Nivå F
Type - PredefinedType: COLUMN; Material: <Unnamed>
Type - Pset_ColumnCommon - LoadBearing: yes
ePset_Simplebim - Assembly Level: Leaf
AVINOR - 08_Status: S4; 06_Omrade: TI; 02_Prosjekt: T20100; 01_Lufthavnkode: ENGM
Pset_ReinforcementBarPitchOfColumn - Reference: B220 - Søylefot - Primærdragere - PirNord - h=470; sets with these values: 2
Pset_ColumnCommon - Reference: B220 - Søylefot - Primærdragere - PirNord - h=470; IsExternal: no
ePset_LocationTool - Splitting: ORIGINAL
Name (B220 - Søylefot - Primærdragere - PirNord1:B220 - Søylefot - Primærdragere - PirNord - h=470:...) | 07_Fase | 03_Ansvar | Width (Simplebim) (mm) | Weight, as steel (Simplebim) (kg) | Volume, net (Simplebim) (m3) | Depth (Simplebim) (mm) | Height (Simplebim) (mm) | Area, sides, net (Simplebim) (m2)
39436117 | F40 | 72245 | 619.009 | 226.004 | 0.0287904 | 651.5 | 820 | 2.89514
39436118 | F40 | 72245 | 619.009 | 226.004 | 0.0287904 | 651.5 | 820 | 2.89514
44181054 | F90 | 72253 | 18 | 66.5419 | 0.00847668 | 677.753 | 880 | 0.0825931
44181055 | F90 | 72253 | 18 | 66.5419 | 0.00847668 | 677.753 | 880 | 0.0825931

# IfcColumn: B222 - HUP:B222 - HUP - 120 x 120 x 5 mm, B222 - HUP:B222 - HUP - 120 x 120 x 5 mm:46053164
In: Nivå F - 0,7 m
Type - PredefinedType: COLUMN; Material: Stål_ RAL 7035
Type - Pset_ColumnCommon - LoadBearing: yes
ePset_Simplebim - Assembly Level: Leaf
AVINOR - 08_Status: S4; 07_Fase: F40; 06_Omrade: TI; 03_Ansvar: 72242; 02_Prosjekt: T20100; 01_Lufthavnkode: ENGM
Pset_ReinforcementBarPitchOfColumn - Reference: B222 - HUP - 120 x 120 x 5 mm; sets with these values: 2
Pset_ColumnCommon - Reference: B222 - HUP - 120 x 120 x 5 mm; IsExternal: no
ePset_LocationTool - Splitting: ORIGINAL
ePset_SimplebimBasicQuantities - Weight, as steel (Simplebim): 7.73605 kg; Volume, net (Simplebim): 0.000985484 m3; Width (Simplebim): 120 mm; Depth (Simplebim): 120 mm; Height (Simplebim): 215 mm; Area, sides, net (Simplebim): 0.392818 m2

# IfcColumn: B222 - HUP:B222 - HUP - 200 x 100 x 8 (5)
In: Nivå F
Type - PredefinedType: COLUMN; Material: _NSW Stål
Type - Pset_ColumnCommon - LoadBearing: yes
Pset_ReinforcementBarPitchOfColumn - Reference: B222 - HUP - 200 x 100 x 8; sets with these values: 2
Pset_ColumnCommon - Reference: B222 - HUP - 200 x 100 x 8; IsExternal: no
AVINOR - 08_Status: S4; 07_Fase: F90; 06_Omrade: TI; 03_Ansvar: 72717; 02_Prosjekt: T20100; 01_Lufthavnkode: ENGM
ePset_Simplebim - Assembly Level: Leaf
ePset_SimplebimBasicQuantities - Height (Simplebim): 2915 mm; Width (Simplebim): 100 mm; Depth (Simplebim): 200 mm; Weight, as steel (Simplebim): 207 kg
ePset_LocationTool - Splitting: ORIGINAL
Name (B222 - HUP:B222 - HUP - 200 x 100 x 8:...) | Area, sides, net (Simplebim) (m2) | Volume, net (Simplebim) (m3)
58551887 | 6.56257 | 0.0263694
58551898 | 6.56257 | 0.0263694
58551900 | 6.56257 | 0.0263694
59292802 | 6.56257 | 0.0263694
59292817 | 6.56256 | 0.0263695

# IfcColumn: B222 - HUP:B222 - HUP - 80 x 80 x 5 mm (4)
Type - PredefinedType: COLUMN; Material: _NSW Stål
Type - Pset_ColumnCommon - LoadBearing: yes
ePset_Simplebim - Assembly Level: Leaf
ePset_SimplebimBasicQuantities - Width (Simplebim): 80 mm; Depth (Simplebim): 80 mm
Pset_ReinforcementBarPitchOfColumn - Reference: B222 - HUP - 80 x 80 x 5 mm; sets with these values: 2
Pset_ColumnCommon - Reference: B222 - HUP - 80 x 80 x 5 mm; IsExternal: no
AVINOR - 03_Ansvar: 72253; 08_Status: S4; 07_Fase: F90; 06_Omrade: TI; 02_Prosjekt: T20100; 01_Lufthavnkode: ENGM
Group: Model Group:A240 - Hjørneprofiler - Teknisk Sjakt (members excluded):44025593
Name (B222 - HUP:B222 - HUP - 80 x 80 x 5 mm:...) | In | Volume, net (Simplebim) (m3) | Weight, as steel (Simplebim) (kg) | Height (Simplebim) (mm) | Area, sides, net (Simplebim) (m2) | Splitting
44746935 | Nivå F | 0.00835418 | 65.5803 | 2800 | 3.3238 | ORIGINAL
44746939 | Nivå F | 0.00835419 | 65.5804 | 2800 | 3.32379 | ORIGINAL
44746935 | Nivå G - 2,0m | 0.00149181 | 11.7107 | 500 | 0.593534 | RESULT
44746939 | Nivå G - 2,0m | 0.00149181 | 11.7107 | 500 | 0.593533 | RESULT

# IfcColumn: D300 (3)
In: F
Description: D300; Material: CONCRETE/C35/45
ePset_Simplebim - Assembly Level: Leaf
Tekla Common - Profile: D300; Bottom elevation: +210.750; Part mark: Concrete-20751; Name: UTSPARING; Top elevation: +210.900; Grade: C35/45; Class: 260; Assembly mark: PLD-2880
AVINOR - 08_Status: S4; 07_Fase: F40; 06_Omrade: TI; 05_ID-nummer: +TI=223.008; 03_Ansvar: 72242; 04_Kontrakt: 72242; 02_Prosjekt: T20100; 01_Lufthavnkode: ENGM
Tekla Quantity - VOLUME_GROSS: 0.01053 m3; VOLUME_NET: 0.01053 m3; AREA_NET: 0.28161 m2; AREA_GROSS: 0.28161 m2; WEIGTH_NET: 25.2838 kg; WEIGTH_GROSS: 25.2838 kg; Width: 300 mm; Heigth: 300 mm; Length: 150.001 mm
Pset_ColumnCommon - Reference: Concrete-20751; LoadBearing: no
ePset_LocationTool - Splitting: ORIGINAL
ePset_SimplebimBasicQuantities - Weight, as steel (Simplebim): 82.6991 kg; Volume, net (Simplebim): 0.0105349 m3; Depth (Simplebim): 300 mm; Height (Simplebim): 300 mm; Area, sides, net (Simplebim): 0.141145 m2; Width (Simplebim): 150.001 mm

# IfcColumn: PL15*100 (6)
In: F
Description: PL15*100; Material: STEEL/S355
Tekla Quantity - AREA_NET: 0.06971 m2; VOLUME_NET: 0.00044 m3; VOLUME_GROSS: 0.00044 m3; AREA_GROSS: 0.0697 m2; Width: 15 mm; Heigth: 100 mm
ePset_Simplebim - Assembly Level: Leaf
ePset_LocationTool - Splitting: ORIGINAL
Tekla Common - Profile: PL15*100; Grade: S355; Class: 320; Bottom elevation: +210.830; Name: STÅLSØYLE; Top elevation: +210.845
Pset_ColumnCommon - LoadBearing: no
AVINOR - 04_Kontrakt: 72253; 05_ID-nummer: +TI=221.025; 08_Status: S4; 07_Fase: F90; 06_Omrade: TI; 02_Prosjekt: T20100; 03_Ansvar: 72101; 01_Lufthavnkode: ENGM
ePset_SimplebimBasicQuantities - Area, sides, net (Simplebim): 0.0117001 m2; Weight, as steel (Simplebim): 3.41478 kg; Height (Simplebim): 290.003 mm; Volume, net (Simplebim): 0.000435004 m3; Width (Simplebim): 15 mm; Depth (Simplebim): 100 mm
Name | Length (mm) | WEIGTH_GROSS (kg) = WEIGTH_NET (kg) | Assembly mark | Part mark = Reference
4 x STÅLSØYLE | 290.003 | 3.41478 | SS-19(?) | DSS-5369(?)
STÅLSØYLE | 290 | 3.41475 | SS-20(?) | DSS-5370(?)
STÅLSØYLE | 289.998 | 3.41473 | SS-19(?) | DSS-5369(?)

# IfcColumn: PL15*280 (9)
In: F
Description: PL15*280; Material: STEEL/S355
Pset_ColumnCommon - LoadBearing: no; Reference: DSS-5405(?)
ePset_Simplebim - Assembly Level: Leaf
Tekla Common - Grade: S355; Class: 320; Profile: PL15*280; Name: STÅLSØYLE; Part mark: DSS-5405(?)
Tekla Quantity - Width: 15 mm; Heigth: 280 mm
ePset_SimplebimBasicQuantities - Width (Simplebim): 15 mm; Height (Simplebim): 280 mm
ePset_LocationTool - Splitting: ORIGINAL
AVINOR - 08_Status: S4; 07_Fase: F90; 06_Omrade: TI; 04_Kontrakt: 72717; 02_Prosjekt: T20100; 05_ID-nummer: +TI=221.041; 03_Ansvar: 72101; 01_Lufthavnkode: ENGM
Name | Bottom elevation | Top elevation | Assembly mark | VOLUME_GROSS (m3) | VOLUME_NET (m3) | WEIGTH_GROSS (kg) = WEIGTH_NET (kg) | Length (mm) | AREA_NET (m2) = AREA_GROSS (m2) | Weight, as steel (Simplebim) (kg) | Area, sides, net (Simplebim) (m2) | Depth (Simplebim) (mm) | Volume, net (Simplebim) (m3)
STÅLSØYLE | +210.830 | +210.845 | SS-8706(?) | 0.00041 | 0.00041 | 3.297 | 100 | 0.0674 | 3.297 | 0.0114 | 100 | 0.00042
STÅLSØYLE | +210.830 | +210.845 | SS-8704(?) | 0.00041 | 0.00041 | 3.297 | 100 | 0.0674 | 3.297 | 0.0114 | 100 | 0.00042
STÅLSØYLE | +210.830 | +210.845 | SS-0(?) | 0.00041 | 0.00041 | 3.297 | 100 | 0.0674 | 3.297 | 0.0114 | 100 | 0.00042
STÅLSØYLE | +210.880 | +210.895 | SS-7783(?) | 0.00034 | 0.00034 | 2.63762 | 80.0007 | 0.0556 | 2.63762 | 0.0108 | 80.0007 | 0.000336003
STÅLSØYLE | +210.880 | +210.895 | SS-8704(?) | 0.00034 | 0.00034 | 2.6376 | 80 | 0.0556 | 2.63762 | 0.0108 | 80.0007 | 0.000336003
STÅLSØYLE | +210.880 | +210.895 | SB-7473(?) | 0.00034 | 0.00034 | 2.6376 | 80 | 0.0556 | 2.63762 | 0.0108 | 80.0007 | 0.000336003
STÅLSØYLE | +210.830 | +210.845 | SS-8704(?) | 0.00046 | 0.00045 | 3.62685 | 110.004 | 0.0733 | 3.62685 | 0.0117001 | 110.004 | 0.000462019
STÅLSØYLE | +210.880 | +210.895 | SS-7492(?) | 0.00034 | 0.00034 | 2.6376 | 80 | 0.0556 | 2.63762 | 0.0108 | 80.0007 | 0.000336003
STÅLSØYLE | +210.880 | +210.895 | SS-8703(?) | 0.00034 | 0.00034 | 2.6376 | 80 | 0.0556 | 2.63762 | 0.0108 | 80.0007 | 0.000336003

# IfcColumn: PL15*350, STÅLSØYLE
In: F
Description: PL15*350; Material: STEEL/S355
ePset_Simplebim - Assembly Level: Leaf
Tekla Common - Grade: S355; Part mark: DSS-5406(?); Profile: PL15*350; Class: 320; Bottom elevation: +210.880; Name: STÅLSØYLE; Top elevation: +210.895; Assembly mark: SS-8709(?)
Pset_ColumnCommon - Reference: DSS-5406(?); LoadBearing: no
ePset_LocationTool - Splitting: ORIGINAL
Tekla Quantity - VOLUME_GROSS: 0.00041 m3; VOLUME_NET: 0.00041 m3; WEIGTH_GROSS: 3.297 kg; WEIGTH_NET: 3.297 kg; AREA_NET: 0.0689 m2; AREA_GROSS: 0.0689 m2; Width: 15 mm; Length: 80 mm; Heigth: 350 mm
AVINOR - 08_Status: S4; 07_Fase: F90; 06_Omrade: TI; 04_Kontrakt: 72717; 02_Prosjekt: T20100; 05_ID-nummer: +TI=221.041; 03_Ansvar: 72101; 01_Lufthavnkode: ENGM
ePset_SimplebimBasicQuantities - Area, sides, net (Simplebim): 0.0129 m2; Depth (Simplebim): 80 mm; Weight, as steel (Simplebim): 3.297 kg; Width (Simplebim): 15 mm; Height (Simplebim): 350 mm; Volume, net (Simplebim): 0.00042 m3

# IfcColumn: PL15*80 (5)
In: F
Description: PL15*80; Material: STEEL/S355
ePset_Simplebim - Assembly Level: Leaf
Tekla Quantity - Width: 15 mm
ePset_LocationTool - Splitting: ORIGINAL
Tekla Common - Grade: S355; Class: 320; Bottom elevation: +210.880; Profile: PL15*80; Name: STÅLSØYLE; Top elevation: +210.895
AVINOR - 08_Status: S4; 07_Fase: F90; 06_Omrade: TI; 04_Kontrakt: 72717; 02_Prosjekt: T20100; 05_ID-nummer: +TI=221.041; 03_Ansvar: 72101; 01_Lufthavnkode: ENGM
ePset_SimplebimBasicQuantities - Width (Simplebim): 15 mm
Pset_ColumnCommon - LoadBearing: no
Name | VOLUME_GROSS (m3) = VOLUME_NET (m3) | Length (mm) = Height (Simplebim) (mm) | AREA_GROSS (m2) | AREA_NET (m2) | WEIGTH_GROSS (kg) | WEIGTH_NET (kg) | Heigth (mm) | Part mark = Reference | Assembly mark | Area, sides, net (Simplebim) (m2) | Depth (Simplebim) (mm) | Volume, net (Simplebim) (m3) | Weight, as steel (Simplebim) (kg)
STÅLSØYLE | 0.00035 | 290.003 | 0.0575 | 0.0575 | 2.73183 | 2.73183 | 80 | DSS-5534(?) | SS-8821(?) | 0.0111001 | 80 | 0.000348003 | 2.73183
STÅLSØYLE | 0.00044 | 360.001 | 0.0288 | 0.0708 | 3.39116 | 3.39116 | 79.999 | DSS-5407(?) | SD-788(?) | 0.0132 | 79.999 | 0.000431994 | 3.39116
STÅLSØYLE | 0.00044 | 360.001 | 0.0288 | 0.0708 | 3.39116 | 3.39115 | 79.9989 | DSS-5407(?) | SD-787(?) | 0.0132 | 79.999 | 0.000431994 | 3.39116
STÅLSØYLE | 0.00044 | 370.001 | 0.02959 | 0.0727 | 3.48536 | 3.48535 | 79.9989 | DSS-5408(?) | SB-7473(?) | 0.0135 | 79.9989 | 0.000443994 | 3.48535
STÅLSØYLE | 0.00041 | 350.001 | 0.028 | 0.0689 | 3.29738 | 3.29737 | 80.0089 | DSS-5408(?) | SS-7783(?) | 0.0129003 | 80.0089 | 0.000420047 | 3.29737

# IfcColumn: PL25*145 (2)
In: F
Description: PL25*145; Material: STEEL/S355
ePset_Simplebim - Assembly Level: Leaf
ePset_SimplebimBasicQuantities - Weight, as steel (Simplebim): 11.3825 kg; Volume, net (Simplebim): 0.00145 m3; Height (Simplebim): 400 mm; Width (Simplebim): 25 mm; Depth (Simplebim): 145 mm; Area, sides, net (Simplebim): 0.02725 m2
Pset_ColumnCommon - Reference: DSS-6185(?); LoadBearing: no
AVINOR - 04_Kontrakt: 72253; 05_ID-nummer: +TI=221.025; 08_Status: S4; 07_Fase: F90; 06_Omrade: TI; 02_Prosjekt: T20100; 03_Ansvar: 72101; 01_Lufthavnkode: ENGM
ePset_LocationTool - Splitting: ORIGINAL
Tekla Quantity - VOLUME_GROSS: 0.00145 m3; VOLUME_NET: 0.00145 m3; WEIGTH_NET: 11.3825 kg; WEIGTH_GROSS: 11.3825 kg; AREA_GROSS: 0.14325 m2; AREA_NET: 0.14325 m2; Width: 25 mm; Heigth: 145 mm; Length: 400 mm
Tekla Common - Grade: S355; Assembly mark: SS-46(?); Part mark: DSS-6185(?); Profile: PL25*145; Class: 320; Bottom elevation: +210.830; Name: STÅLSØYLE; Top elevation: +210.855

# IfcColumn: PL25*240 (3)
In: F
Description: PL25*240; Material: STEEL/S355
Pset_ColumnCommon - LoadBearing: no; Reference: DSS-6148(?)
ePset_Simplebim - Assembly Level: Leaf
Tekla Common - Grade: S355; Assembly mark: SS-41(?); Class: 320; Bottom elevation: +210.830; Profile: PL25*240; Name: STÅLSØYLE; Top elevation: +210.855; Part mark: DSS-6148(?)
Tekla Quantity - AREA_GROSS: 0.2028 m2; WEIGTH_NET: 16.22 kg; AREA_NET: 0.20076 m2; VOLUME_NET: 0.00207 m3; VOLUME_GROSS: 0.00216 m3; WEIGTH_GROSS: 16.956 kg; Width: 25 mm; Heigth: 240 mm; Length: 360 mm
AVINOR - 04_Kontrakt: 72253; 05_ID-nummer: +TI=221.025; 08_Status: S4; 07_Fase: F90; 06_Omrade: TI; 02_Prosjekt: T20100; 03_Ansvar: 72101; 01_Lufthavnkode: ENGM
ePset_SimplebimBasicQuantities - Volume, net (Simplebim): 0.00206624 m3; Area, sides, net (Simplebim): 0.0354625 m2; Width (Simplebim): 25 mm; Depth (Simplebim): 240 mm; Height (Simplebim): 360 mm; Weight, as steel (Simplebim): 16.22 kg
ePset_LocationTool - Splitting: ORIGINAL

# IfcColumn: PL25*260 (2)
In: F
Description: PL25*260; Material: STEEL/S355
ePset_Simplebim - Assembly Level: Leaf
ePset_SimplebimBasicQuantities - Width (Simplebim): 25 mm; Depth (Simplebim): 260 mm
Tekla Quantity - Width: 25 mm; Heigth: 260 mm
Tekla Common - Grade: S355; Class: 320; Bottom elevation: +210.830; Profile: PL25*260; Name: STÅLSØYLE; Top elevation: +210.855
ePset_LocationTool - Splitting: ORIGINAL
AVINOR - 04_Kontrakt: 72253; 05_ID-nummer: +TI=221.025; 08_Status: S4; 07_Fase: F90; 06_Omrade: TI; 02_Prosjekt: T20100; 03_Ansvar: 72101; 01_Lufthavnkode: ENGM
Pset_ColumnCommon - LoadBearing: no
Name | Volume, net (Simplebim) (m3) | Weight, as steel (Simplebim) (kg) = WEIGTH_NET (kg) | Area, sides, net (Simplebim) (m2) | Height (Simplebim) (mm) = Length (mm) | VOLUME_NET (m3) | VOLUME_GROSS (m3) | AREA_NET (m2) | AREA_GROSS (m2) | WEIGTH_GROSS (kg) | Assembly mark | Part mark = Reference
STÅLSØYLE | 0.00195 | 15.3075 | 0.028 | 300 | 0.00195 | 0.00195 | 0.184 | 0.184 | 15.3075 | SS-47(?) | DSS-6186(?)
STÅLSØYLE | 0.00224624 | 17.633 | 0.0364625 | 360 | 0.00225 | 0.00234 | 0.21616 | 0.2182 | 18.369 | SS-42(?) | DSS-6149(?)

# IfcColumn: PL5*72 (4)
In: F
Description: PL5*72; Material: STEEL/S355J0
ePset_Simplebim - Assembly Level: Leaf
Pset_ColumnCommon - LoadBearing: no; Reference: DSS-6994(?)
ePset_SimplebimBasicQuantities - Weight, as steel (Simplebim): 0.203472 kg; Volume, net (Simplebim): 0.00002592 m3; Area, sides, net (Simplebim): 0.00144 m2; Width (Simplebim): 5 mm; Depth (Simplebim): 72 mm; Height (Simplebim): 72 mm
Tekla Quantity - WEIGTH_NET: 0.20347 kg; WEIGTH_GROSS: 0.20347 kg; Width: 5 mm; Length: 72 mm; Heigth: 72 mm; AREA_GROSS: 0.01181 m2; AREA_NET: 0.01181 m2; VOLUME_GROSS: 0.00003 m3; VOLUME_NET: 0.00003 m3
AVINOR - 08_Status: S4; 07_Fase: F90; 06_Omrade: TI; 04_Kontrakt: 72717; 02_Prosjekt: T20100; 05_ID-nummer: +TI=221.041; 03_Ansvar: 72101; 01_Lufthavnkode: ENGM
Tekla Common - Top elevation: +213.700; Class: 320; Profile: PL5*72; Name: STÅLSØYLE; Grade: S355J0; Part mark: DSS-6994(?); Bottom elevation: +213.695
ePset_LocationTool - Splitting: ORIGINAL
Name | Assembly mark
STÅLSØYLE | SS-8703(?)
2 x STÅLSØYLE | SS-7783(?)
STÅLSØYLE | SB-7473(?)

# IfcColumn: PL8*105 (4)
In: F
Description: PL8*105; Material: STEEL/S355J0
ePset_Simplebim - Assembly Level: Leaf
Tekla Common - Top elevation: +213.682; Class: 320; Name: STÅLSØYLE; Profile: PL8*105; Grade: S355J0; Bottom elevation: +213.577
Pset_ColumnCommon - LoadBearing: no
ePset_SimplebimBasicQuantities - Width (Simplebim): 8 mm; Depth (Simplebim): 105 mm
AVINOR - 08_Status: S4; 07_Fase: F90; 06_Omrade: TI; 04_Kontrakt: 72717; 02_Prosjekt: T20100; 05_ID-nummer: +TI=221.041; 03_Ansvar: 72101; 01_Lufthavnkode: ENGM
Tekla Quantity - Width: 8 mm; Heigth: 105 mm
ePset_LocationTool - Splitting: ORIGINAL
Name | Part mark = Reference | Assembly mark | Weight, as steel (Simplebim) (kg) = WEIGTH_GROSS (kg) = WEIGTH_NET (kg) | Height (Simplebim) (mm) = Length (mm) | Area, sides, net (Simplebim) (m2) | Volume, net (Simplebim) (m3) | AREA_NET (m2) | AREA_GROSS (m2) | VOLUME_NET (m3) = VOLUME_GROSS (m3)
2 x STÅLSØYLE | DSS-6518(?) | SS-8703(?) | 1.18692 | 180 | 0.03948 | 0.0001512 | 0.04236 | 0.0189 | 0.00015
STÅLSØYLE | DSS-6516(?) | SS-7783(?) | 1.71444 | 260 | 0.05628 | 0.0002184 | 0.06044 | 0.0273 | 0.00022
STÅLSØYLE | DSS-6516(?) | SB-7473(?) | 1.71444 | 260 | 0.05628 | 0.0002184 | 0.06044 | 0.0273 | 0.00022

# IfcColumn: PL8*140, STÅLSØYLE
In: F
Description: PL8*140; Material: STEEL/S355
ePset_Simplebim - Assembly Level: Leaf
Tekla Common - Grade: S355; Bottom elevation: +213.540; Class: 320; Name: STÅLSØYLE; Part mark: DSS-6517(?); Top elevation: +213.680; Assembly mark: SS-7783(?); Profile: PL8*140
Tekla Quantity - VOLUME_NET: 0.00022 m3; VOLUME_GROSS: 0.00022 m3; AREA_GROSS: 0.028 m2; Length: 200 mm; WEIGTH_GROSS: 1.7584 kg; WEIGTH_NET: 1.7584 kg; Width: 8 mm; Heigth: 140 mm; AREA_NET: 0.06144 m2
ePset_LocationTool - Splitting: ORIGINAL
Pset_ColumnCommon - Reference: DSS-6517(?); LoadBearing: no
ePset_SimplebimBasicQuantities - Area, sides, net (Simplebim): 0.05824 m2; Weight, as steel (Simplebim): 1.7584 kg; Volume, net (Simplebim): 0.000224 m3; Height (Simplebim): 200 mm; Depth (Simplebim): 140 mm; Width (Simplebim): 8 mm
AVINOR - 08_Status: S4; 07_Fase: F90; 06_Omrade: TI; 04_Kontrakt: 72717; 02_Prosjekt: T20100; 05_ID-nummer: +TI=221.041; 03_Ansvar: 72101; 01_Lufthavnkode: ENGM

# IfcColumn: PL8*95 (7)
In: F
Description: PL8*95; Material: STEEL/S355J0
ePset_Simplebim - Assembly Level: Leaf
Pset_ColumnCommon - LoadBearing: no
ePset_LocationTool - Splitting: ORIGINAL
Tekla Quantity - Width: 8 mm; Heigth: 95 mm
ePset_SimplebimBasicQuantities - Width (Simplebim): 8 mm; Depth (Simplebim): 95 mm
Tekla Common - Profile: PL8*95; Class: 320; Name: STÅLSØYLE; Grade: S355J0
AVINOR - 08_Status: S4; 07_Fase: F90; 06_Omrade: TI; 04_Kontrakt: 72717; 02_Prosjekt: T20100; 05_ID-nummer: +TI=221.041; 03_Ansvar: 72101; 01_Lufthavnkode: ENGM
Name | Reference = Part mark | AREA_NET (m2) | AREA_GROSS (m2) | VOLUME_NET (m3) = VOLUME_GROSS (m3) | WEIGTH_NET (kg) = WEIGTH_GROSS (kg) = Weight, as steel (Simplebim) (kg) | Length (mm) = Height (Simplebim) (mm) | Area, sides, net (Simplebim) (m2) | Volume, net (Simplebim) (m3) | Top elevation | Bottom elevation | Assembly mark
STÅLSØYLE | DSS-6520(?) | 0.05302 | 0.05302 | 0.0002 | 1.4915 | 250 | 0.00552 | 0.00019 | +213.560 | +213.552 | SS-8709(?)
STÅLSØYLE | DSS-6519(?) | 0.0489 | 0.0489 | 0.00017 | 1.37218 | 230 | 0.0052 | 0.0001748 | +213.600 | +213.592 | SS-0(?)
STÅLSØYLE | DSS-6522(?) | 0.04709 | 0.0471 | 0.00017 | 1.32017 | 221.282 | 0.00506051 | 0.000168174 | +213.520 | +213.512 | SS-8821(?)
3 x STÅLSØYLE | DSS-6521(?) | 0.0489 | 0.0489 | 0.00017 | 1.37218 | 230 | 0.0052 | 0.0001748 | +213.520 | +213.512 | SS-8704(?)
STÅLSØYLE | DSS-6523(?) | 0.05096 | 0.05096 | 0.00017 | 1.43184 | 240 | 0.00536 | 0.0001824 | +213.520 | +213.512 | SS-8706(?)

# IfcColumn: RHS200*100*8 (5)
In: F
Description: RHS200*100*8; Material: STEEL/S355
ePset_SimplebimBasicQuantities - Width (Simplebim): 100 mm; Depth (Simplebim): 200 mm
ePset_Simplebim - Assembly Level: Leaf
ePset_LocationTool - Splitting: ORIGINAL
AVINOR - 04_Kontrakt: 72253; 05_ID-nummer: +TI=221.025; 08_Status: S4; 07_Fase: F90; 06_Omrade: TI; 02_Prosjekt: T20100; 03_Ansvar: 72101; 01_Lufthavnkode: ENGM
Pset_ColumnCommon - LoadBearing: no
Tekla Quantity - Width: 100 mm; Heigth: 200 mm
Tekla Common - Grade: S355; Class: 320; Name: STÅLSØYLE; Profile: RHS200*100*8; Bottom elevation: +210.855
Name | Height (Simplebim) (mm) = Length (mm) | Weight, as steel (Simplebim) (kg) | Area, sides, net (Simplebim) (m2) | Volume, net (Simplebim) (m3) | Reference = Part mark | AREA_NET (m2) | AREA_GROSS (m2) | WEIGTH_NET (kg) | VOLUME_NET (m3) | WEIGTH_GROSS (kg) | VOLUME_GROSS (m3) | Assembly mark | Top elevation
STÅLSØYLE | 2882 | 102.32 | 3.26245 | 0.0130344 | DSS-7491(?) | 1.70392 | 1.68021 | 102.331 | 0.01305 | 102.033 | 0.01299 | SS-9580(?) | +213.737
STÅLSØYLE | 3032 | 107.681 | 3.43285 | 0.0137173 | DSS-7492(?) | 1.79267 | 1.76766 | 107.682 | 0.01371 | 107.343 | 0.01367 | SS-9581(?) | +213.887
STÅLSØYLE | 3032 | 108.153 | 3.44435 | 0.0137774 | DSS-7498(?) | 1.79867 | 1.76766 | 108.153 | 0.01378 | 107.343 | 0.01367 | SS-9583(?) | +213.887
STÅLSØYLE | 2882 | 102.334 | 3.26245 | 0.0130362 | DSS-7491(?) | 1.70393 | 1.68021 | 102.331 | 0.01305 | 102.033 | 0.01299 | SS-9580(?) | +213.737
STÅLSØYLE | 3032 | 107.446 | 3.42709 | 0.0136874 | DSS-7500(?) | 1.78968 | 1.76766 | 107.446 | 0.01369 | 107.343 | 0.01367 | SS-9584(?) | +213.887

# IfcColumn: RHS80*8 (6)
In: F
Description: RHS80*8; Material: STEEL/S355J2H
ePset_Simplebim - Assembly Level: Leaf
Pset_ColumnCommon - LoadBearing: no
Tekla Quantity - Width: 80 mm; Heigth: 80 mm
ePset_LocationTool - Splitting: ORIGINAL
ePset_SimplebimBasicQuantities - Width (Simplebim): 80 mm; Depth (Simplebim): 80 mm
AVINOR - 08_Status: S4; 07_Fase: F90; 06_Omrade: TI; 04_Kontrakt: 72717; 02_Prosjekt: T20100; 05_ID-nummer: +TI=221.041; 03_Ansvar: 72101; 01_Lufthavnkode: ENGM
Tekla Common - Profile: RHS80*8; Class: 320; Grade: S355J2H; Name: STÅLSØYLE
Name | Reference = Part mark | VOLUME_NET (m3) | VOLUME_GROSS (m3) | WEIGTH_GROSS (kg) | AREA_NET (m2) | AREA_GROSS (m2) | Length (mm) = Height (Simplebim) (mm) | WEIGTH_NET (kg) | Volume, net (Simplebim) (m3) | Area, sides, net (Simplebim) (m2) | Weight, as steel (Simplebim) (kg) | Bottom elevation | Top elevation | Assembly mark
STÅLSØYLE | DSS-7270(?) | 0.00611 | 0.00611 | 48.0556 | 0.85209 | 0.8528 | 2657 | 47.9344 | 0.0061063 | 1.52915 | 47.9344 | +210.895 | +213.552 | SS-8709(?)
2 x STÅLSØYLE | DSS-7268(?) | 0.00614 | 0.00614 | 48.2364 | 0.856 | 0.856 | 2667 | 48.2364 | 0.00495326 | 1.57246 | 38.8831 | +210.845 | +213.512 | SS-8704(?)
STÅLSØYLE | DSS-7276(?) | 0.0064 | 0.00645 | 50.6419 | 0.89662 | 0.89856 | 2800 | 50.2286 | 0.00639855 | 1.60898 | 50.2286 | +210.895 | +213.695 | SB-7473(?)
STÅLSØYLE | DSS-7268(?) | 0.00603 | 0.00603 | 47.3321 | 0.84 | 0.84 | 2617 | 47.3321 | 0.0048604 | 1.54298 | 38.1541 | +210.895 | +213.512 | SB-7473(?)
STÅLSØYLE | DSS-7268(?) | 0.00603 | 0.00603 | 47.3321 | 0.84 | 0.84 | 2617 | 47.3321 | 0.0048604 | 1.54298 | 38.1541 | +210.895 | +213.512 | SS-8704(?)

# IfcColumn: RHS80*80*6.3 (18)
In: F
Description: RHS80*80*6.3
ePset_Simplebim - Assembly Level: Leaf
Tekla Quantity - Width: 80 mm; Heigth: 80 mm
ePset_SimplebimBasicQuantities - Width (Simplebim): 80 mm; Depth (Simplebim): 80 mm
ePset_LocationTool - Splitting: ORIGINAL
Pset_ColumnCommon - LoadBearing: no
Tekla Common - Profile: RHS80*80*6.3
AVINOR - 08_Status: S4; 07_Fase: F90; 06_Omrade: TI; 02_Prosjekt: T20100; 03_Ansvar: 72101; 01_Lufthavnkode: ENGM
Name | Material | AREA_NET (m2) | WEIGTH_GROSS (kg) | VOLUME_NET (m3) | WEIGTH_NET (kg) | AREA_GROSS (m2) | Length (mm) = Height (Simplebim) (mm) | VOLUME_GROSS (m3) | Weight, as steel (Simplebim) (kg) | Area, sides, net (Simplebim) (m2) | Volume, net (Simplebim) (m3) | Reference = Part mark | Assembly mark | Class | Grade | Name | Bottom elevation | Top elevation | 04_Kontrakt | 05_ID-nummer
STÅLSØYLE | STEEL/S355J2H | 0.88106 | 39.6777 | 0.0051 | 40.0494 | 0.84058 | 2747 | 0.00506 | 40.0494 | 1.61963 | 0.00510184 | DSS-7948(?) | SS-0(?) | 320 | S355J2H | STÅLSØYLE | +210.845 | +213.592 | 72717 | +TI=221.041
STÅLSØYLE | STEEL/S355J2H | 0.89657 | 40.4432 | 0.00516 | 40.6105 | 0.8568 | 2800 | 0.00515 | 40.6105 | 1.64771 | 0.00517331 | DSS-7944(?) | SS-8703(?) | 320 | S355J2H | STÅLSØYLE | +210.895 | +213.695 | 72717 | +TI=221.041
STÅLSØYLE | STEEL/S355J2H | 0.85546 | 38.5222 | 0.00496 | 38.8831 | 0.8161 | 2667 | 0.0049 | 38.8831 | 1.57246 | 0.00495326 | DSS-7946(?) | SS-8706(?) | 320 | S355J2H | STÅLSØYLE | +210.845 | +213.512 | 72717 | +TI=221.041
STÅLSØYLE | STEEL/S355J2H | 0.8369 | 37.8 | 0.00483 | 37.9092 | 0.8008 | 2617 | 0.00483 | 37.9092 | 1.53828 | 0.0048292 | DSS-7921(?) | SS-8821(?) | 320 | S355J2H | STÅLSØYLE | +210.895 | +213.512 | 72717 | +TI=221.041
STÅLSØYLE | STEEL/S355J2H | 0.83946 | 37.8 | 0.00487 | 38.1541 | 0.8008 | 2617 | 0.00483 | 38.1541 | 1.54298 | 0.0048604 | DSS-7946(?) | SS-7492(?) | 320 | S355J2H | STÅLSØYLE | +210.895 | +213.512 | 72717 | +TI=221.041
STÅLSØYLE | STEEL/S355J2H | 0.8964 | 40.4432 | 0.00518 | 40.6512 | 0.8568 | 2800 | 0.00515 | 40.6512 | 1.6476 | 0.0051785 | DSS-7920(?) | SS-7783(?) | 320 | S355J2H | STÅLSØYLE | +210.895 | +213.695 | 72717 | +TI=221.041
STÅLSØYLE | STEEL/S355J2H | 0.89444 | 40.4432 | 0.00515 | 40.4265 | 0.8568 | 2800 | 0.00515 | 40.4265 | 1.64373 | 0.00514987 | DSS-7945(?) | SS-7783(?) | 320 | S355J2H | STÅLSØYLE | +210.895 | +213.695 | 72717 | +TI=221.041
STÅLSØYLE | STEEL/S355 | 0.99143 | 44.6598 | 0.00573 | 45.0782 | 0.94613 | 3091.93 | 0.00569 | 45.0782 | 1.823 | 0.00574245 | DSS-7960(?) | SS-9708(?) | 320 | S355 | STÅLSØYLE | +210.855 | +213.844 | 72253 | +TI=221.025
STÅLDIAGONAL | STEEL/S355 | 1.12942 | 50.8882 | 0.00654 | 51.365 | 1.07808 | 3523.14 | 0.00647 | 51.365 | 2.07724 | 0.00654331 | DSB-24044(?) | SB-14397(?) | 331 | S355 | STÅLDIAGONAL | +210.855 | +213.814 | 72253 | +TI=221.025
STÅLDIAGONAL | STEEL/S355 | 1.1571 | 52.1377 | 0.00669 | 52.6262 | 1.10455 | 3609.64 | 0.00664 | 52.6262 | 2.12824 | 0.00670397 | DSB-24043(?) | SB-14396(?) | 331 | S355 | STÅLDIAGONAL | +210.845 | +213.816 | 72253 | +TI=221.025
5 x STÅLSØYLE | STEEL/S355 | 0.95242 | 42.8987 | 0.00552 | 43.3006 | 0.90882 | 2970 | 0.00545 | 43.3006 | 1.75111 | 0.005516 | DSS-7954(?) | SS-9705(?) | 320 | S355 | STÅLSØYLE | +210.845 | +213.815 | 72253 | +TI=221.025
2 x STÅLSØYLE | STEEL/S355 | 0.94922 | 42.7542 | 0.00551 | 43.1548 | 0.90576 | 2960 | 0.00545 | 43.1548 | 1.74522 | 0.00549743 | DSS-7955(?) | SS-9706(?) | 320 | S355 | STÅLSØYLE | +210.855 | +213.815 | 72253 | +TI=221.025
STÅLSØYLE | STEEL/S355 | 0.97802 | 44.0542 | 0.00565 | 44.467 | 0.9333 | 3050 | 0.00561 | 42.5219 | 1.8056 | 0.0054168 | DSS-7956(?) | SS-9707(?) | 320 | S355 | STÅLSØYLE | +210.845 | +213.895 | 72253 | +TI=221.025

# IfcColumn: Ø50*5, INNSTØPNGODS
In: D
Description: Ø50*5; Material: MISCELLANEOUS/Misc_Undefined
ePset_SimplebimBasicQuantities - Volume, net (Simplebim): 0.000237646 m3; Weight, as steel (Simplebim): 1.86552 kg; Depth (Simplebim): 50 mm; Width (Simplebim): 50 mm; Height (Simplebim): 345 mm; Area, sides, net (Simplebim): 0.0969209 m2
ePset_Simplebim - Assembly Level: Leaf
AVINOR - 08_Status: S4; 07_Fase: F40; 06_Omrade: TI; 05_ID-nummer: +TI=222.006; 03_Ansvar: 72242; 04_Kontrakt: 72242; 02_Prosjekt: T20100; 01_Lufthavnkode: ENGM
Tekla Quantity - AREA_GROSS: 0.05461 m2; AREA_NET: 0.05461 m2; VOLUME_GROSS: 0.00025 m3; VOLUME_NET: 0.00025 m3; WEIGTH_GROSS: 0 kg; WEIGTH_NET: 0 kg; Width: 50 mm; Heigth: 50 mm; Length: 345 mm
ePset_LocationTool - Splitting: ORIGINAL
Pset_ColumnCommon - Reference: DINN-145; LoadBearing: no
Tekla Common - Top elevation: +210.555; Grade: Misc_Undefined; Name: INNSTØPNGODS; Part mark: DINN-145; Assembly mark: INN-108; Class: 371; Profile: Ø50*5; Bottom elevation: +210.210

# IfcCovering (257)
PredefinedType: INSULATION
ePset_Simplebim - Assembly Level: Leaf
Name | In | Description | Length (Simplebim) (mm) | Area, largest surface, net (Simplebim) (m2) | Volume, net (Simplebim) (m3) | Height (Simplebim) (mm) | Width (Simplebim) (mm) | Splitting
BI11T - Rørskål m/Al.folie - varme 60-25 | Nivå C + 2,7 m | BI11T - Rørskål m/Al.folie - varme 60-25 | 160.4 | 0.0497388 | 0.00189969 | 140.6 | 140.6 | ORIGINAL | MagiCAD Pset_Elbow - qv_SizingFlow_ls: 0 m3/s; pTot_SizingFlow_Pa: 0 Pa; dpTot_SizingFlow_Pa: 0 Pa; v_SizingFlow_ms: 0 m/s; ConnectionSize_mm: 0 mm; Insulation_thickness_mm: 50 mm
BI11T - Rørskål m/Al.folie - varme 60-25 | Nivå D | BI11T - Rørskål m/Al.folie - varme 60-25 | 102.8 | 0.0483819 | 0.00160659 | 150 | 150 | ORIGINAL | MagiCAD Pset_Heating - v_SizingFlow_ms: 0 m/s; pTot_SizingFlow_kPa: 0 Pa; dpTot_SizingFlow_kPa: 0 Pa; MagiCAD Pset_Water - dpTot_SizingFlow_kPa: 0 Pa; pTot_SizingFlow_kPa: 0 Pa; v_SizingFlow_ms: 0 m/s; MagiCAD Pset_Pipe - Length_mm: 102.752 mm; SystemName: +TI=322.004 T; SystemType: SHUNTET VARME T; qv_SizingFlow_ls: 0 m3/s; NationalCode: UB3.144613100; ConnectionSize_mm: 50 mm; Insulation_thickness_mm: 50 mm; User Code: DN; SystemClass: Hydronic Supply; Material: Stålrør normaltykke
5 x BI11T - Rørskål m/Al.folie - varme 60-25 | Nivå D | BI11T - Rørskål m/Al.folie - varme 60-25 | 128.4 | 0.0318666 | 0.000974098 | 112.6 | 112.6 | ORIGINAL | MagiCAD Pset_Elbow - qv_SizingFlow_ls: 0 m3/s; pTot_SizingFlow_Pa: 0 Pa; dpTot_SizingFlow_Pa: 0 Pa; v_SizingFlow_ms: 0 m/s; ConnectionSize_mm: 0 mm; Insulation_thickness_mm: 40 mm
BI11T - Rørskål m/Al.folie - varme 60-25 | Nivå D | BI11T - Rørskål m/Al.folie - varme 60-25 | 26.6 | 0.0156283 | 0.000415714 | 150 | 150 | ORIGINAL | MagiCAD Pset_Heating - v_SizingFlow_ms: 0 m/s; pTot_SizingFlow_kPa: 0 Pa; dpTot_SizingFlow_kPa: 0 Pa; MagiCAD Pset_Water - dpTot_SizingFlow_kPa: 0 Pa; pTot_SizingFlow_kPa: 0 Pa; v_SizingFlow_ms: 0 m/s; MagiCAD Pset_Pipe - Length_mm: 26.605 mm; SystemName: +TI=322.004 R; SystemType: SHUNTET VARME R; qv_SizingFlow_ls: 0 m3/s; NationalCode: UB3.144613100; ConnectionSize_mm: 50 mm; Insulation_thickness_mm: 50 mm; User Code: DN; SystemClass: Hydronic Return; Material: Stålrør normaltykke
3 x BI11T - Rørskål m/Al.folie - varme 60-25 | Nivå D | BI11T - Rørskål m/Al.folie - varme 60-25 | 160.4 | 0.0497388 | 0.00189969 | 140.6 | 140.6 | ORIGINAL | MagiCAD Pset_Elbow - qv_SizingFlow_ls: 0 m3/s; pTot_SizingFlow_Pa: 0 Pa; dpTot_SizingFlow_Pa: 0 Pa; v_SizingFlow_ms: 0 m/s; ConnectionSize_mm: 0 mm; Insulation_thickness_mm: 50 mm
BI11T - Rørskål m/Al.folie - varme 60-25 | Nivå D | BI11T - Rørskål m/Al.folie - varme 60-25 | 533.4 | 0.25104 | 0.00833615 | 150 | 150 | ORIGINAL | MagiCAD Pset_Heating - v_SizingFlow_ms: 0 m/s; pTot_SizingFlow_kPa: 0 Pa; dpTot_SizingFlow_kPa: 0 Pa; MagiCAD Pset_Water - dpTot_SizingFlow_kPa: 0 Pa; pTot_SizingFlow_kPa: 0 Pa; v_SizingFlow_ms: 0 m/s; MagiCAD Pset_Pipe - Length_mm: 533.417 mm; SystemName: +TI=322.004 R; SystemType: SHUNTET VARME R; qv_SizingFlow_ls: 0 m3/s; NationalCode: UB3.144613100; ConnectionSize_mm: 50 mm; Insulation_thickness_mm: 50 mm; User Code: DN; SystemClass: Hydronic Return; Material: Stålrør normaltykke
BI11T - Rørskål m/Al.folie - varme 60-25 | Nivå D | BI11T - Rørskål m/Al.folie - varme 60-25 | 717.4 | 0.337638 | 0.0112118 | 150 | 150 | ORIGINAL | MagiCAD Pset_Heating - v_SizingFlow_ms: 0 m/s; pTot_SizingFlow_kPa: 0 Pa; dpTot_SizingFlow_kPa: 0 Pa; MagiCAD Pset_Water - dpTot_SizingFlow_kPa: 0 Pa; pTot_SizingFlow_kPa: 0 Pa; v_SizingFlow_ms: 0 m/s; MagiCAD Pset_Pipe - Length_mm: 717.417 mm; SystemName: +TI=322.004 T; SystemType: SHUNTET VARME T; qv_SizingFlow_ls: 0 m3/s; NationalCode: UB3.144613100; ConnectionSize_mm: 50 mm; Insulation_thickness_mm: 50 mm; User Code: DN; SystemClass: Hydronic Supply; Material: Stålrør normaltykke
BI11T - Rørskål m/Al.folie - varme 60-25 | Nivå D | BI11T - Rørskål m/Al.folie - varme 60-25 | 140 | 0.0613995 | 0.0021306 | 140 | 140 | ORIGINAL | MagiCAD Pset_Valve - Manufacturer: Axel Larsson; Description: Magnetventil; qv_SizingFlow_ls: 0 m3/s; pTot_SizingFlow_kPa: 0 Pa; dpTot_SizingFlow_kPa: 0 Pa; Product Code: 322G-3910-40; User Code: MV04; Insulation_thickness_mm: 40 mm; MagiCAD Pset_FireDamper - Manufacturer: Axel Larsson; Description: Magnetventil; qv_SizingFlow_ls: 0 m3/s; pTot_SizingFlow_Pa: 0 Pa; dpTot_SizingFlow_Pa: 0 Pa; v_SizingFlow_ms: 0 m/s; Product Code: 322G-3910-40; User Code: MV04; sets with these values: 2; MagiCAD Pset_Silencer - Manufacturer: Axel Larsson; Description: Magnetventil; qv_SizingFlow_ls: 0 m3/s; pTot_SizingFlow_Pa: 0 Pa; dpTot_SizingFlow_Pa: 0 Pa; ProductCode: 322G-3910-40; User Code: MV04
BI11T - Rørskål m/Al.folie - varme 60-25 | Nivå D | BI11T - Rørskål m/Al.folie - varme 60-25 | 109.1 | 0.0410775 | 0.00109123 | 120 | 120 | ORIGINAL | MagiCAD Pset_Heating - v_SizingFlow_ms: 0 m/s; pTot_SizingFlow_kPa: 0 Pa; dpTot_SizingFlow_kPa: 0 Pa; MagiCAD Pset_Water - dpTot_SizingFlow_kPa: 0 Pa; pTot_SizingFlow_kPa: 0 Pa; v_SizingFlow_ms: 0 m/s; MagiCAD Pset_Pipe - Length_mm: 109.141 mm; SystemName: +TI=322.004 R; SystemType: SHUNTET VARME R; qv_SizingFlow_ls: 0 m3/s; NationalCode: UB3.144613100; ConnectionSize_mm: 40 mm; Insulation_thickness_mm: 40 mm; User Code: DN; SystemClass: Hydronic Return; Material: Stålrør normaltykke
2 x BI11T - Rørskål m/Al.folie - varme 60-25 | Nivå D | BI11T - Rørskål m/Al.folie - varme 60-25 | 128.4 | 0.0107831 | 0.000370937 | 100.5 | 34.4 | ORIGINAL | MagiCAD Pset_TBranch - qv_SizingFlow_ls: 0 m3/s; pTot_SizingFlow_Pa: 0 Pa; dpTot_SizingFlow_Pa: 0 Pa; v_SizingFlow_ms: 0 m/s; ConnectionSize_mm: 0 mm; Insulation_thickness_mm: 40 mm
BI11T - Rørskål m/Al.folie - varme 60-25 | Nivå D | BI11T - Rørskål m/Al.folie - varme 60-25 | 266.5 | 0.100341 | 0.00266557 | 120 | 120 | ORIGINAL | MagiCAD Pset_Heating - v_SizingFlow_ms: 0 m/s; pTot_SizingFlow_kPa: 0 Pa; dpTot_SizingFlow_kPa: 0 Pa; MagiCAD Pset_Water - dpTot_SizingFlow_kPa: 0 Pa; pTot_SizingFlow_kPa: 0 Pa; v_SizingFlow_ms: 0 m/s; MagiCAD Pset_Pipe - Length_mm: 266.548 mm; SystemName: +TI=322.004 R; SystemType: SHUNTET VARME R; qv_SizingFlow_ls: 0 m3/s; NationalCode: UB3.144613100; ConnectionSize_mm: 40 mm; Insulation_thickness_mm: 40 mm; User Code: DN; SystemClass: Hydronic Return; Material: Stålrør normaltykke
2 x BI11T - Rørskål m/Al.folie - varme 60-25 | Nivå D | BI11T - Rørskål m/Al.folie - varme 60-25 | 146.5 | 0.0321762 | 0.000549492 | 70 | 70 | ORIGINAL | MagiCAD Pset_Heating - v_SizingFlow_ms: 0 m/s; pTot_SizingFlow_kPa: 0 Pa; dpTot_SizingFlow_kPa: 0 Pa; MagiCAD Pset_Water - dpTot_SizingFlow_kPa: 0 Pa; pTot_SizingFlow_kPa: 0 Pa; v_SizingFlow_ms: 0 m/s; MagiCAD Pset_Pipe - Length_mm: 146.5 mm; SystemName: +TI=322.004 R; SystemType: SHUNTET VARME R; qv_SizingFlow_ls: 0 m3/s; NationalCode: UB3.144613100; ConnectionSize_mm: 10 mm; Insulation_thickness_mm: 30 mm; User Code: DN; SystemClass: Hydronic Return; Material: Stålrør normaltykke
BI11T - Rørskål m/Al.folie - varme 60-25 | Nivå D | BI11T - Rørskål m/Al.folie - varme 60-25 | 134.6 | 0.0295625 | 0.000504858 | 70 | 70 | ORIGINAL | MagiCAD Pset_Heating - v_SizingFlow_ms: 0 m/s; pTot_SizingFlow_kPa: 0 Pa; dpTot_SizingFlow_kPa: 0 Pa; MagiCAD Pset_Water - dpTot_SizingFlow_kPa: 0 Pa; pTot_SizingFlow_kPa: 0 Pa; v_SizingFlow_ms: 0 m/s; MagiCAD Pset_Pipe - Length_mm: 134.55 mm; SystemName: +TI=322.004 R; SystemType: SHUNTET VARME R; qv_SizingFlow_ls: 0 m3/s; NationalCode: UB3.144613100; ConnectionSize_mm: 10 mm; Insulation_thickness_mm: 30 mm; User Code: DN; SystemClass: Hydronic Return; Material: Stålrør normaltykke
2 x BI11T - Rørskål m/Al.folie - varme 60-25 | Nivå D | BI11T - Rørskål m/Al.folie - varme 60-25 | 77.2 | 0.00790934 | 0.000138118 | 55.8 | 55.8 | ORIGINAL | MagiCAD Pset_Elbow - qv_SizingFlow_ls: 0 m3/s; pTot_SizingFlow_Pa: 0 Pa; dpTot_SizingFlow_Pa: 0 Pa; v_SizingFlow_ms: 0 m/s; ConnectionSize_mm: 0 mm; Insulation_thickness_mm: 30 mm
BI11T - Rørskål m/Al.folie - varme 60-25 | Nivå D | BI11T - Rørskål m/Al.folie - varme 60-25 | 116.5 | 0.0438637 | 0.00116525 | 120 | 120 | ORIGINAL | MagiCAD Pset_Heating - v_SizingFlow_ms: 0 m/s; pTot_SizingFlow_kPa: 0 Pa; dpTot_SizingFlow_kPa: 0 Pa; MagiCAD Pset_Water - dpTot_SizingFlow_kPa: 0 Pa; pTot_SizingFlow_kPa: 0 Pa; v_SizingFlow_ms: 0 m/s; MagiCAD Pset_Pipe - Length_mm: 116.459 mm; SystemName: +TI=322.004 R; SystemType: SHUNTET VARME R; qv_SizingFlow_ls: 0 m3/s; NationalCode: UB3.144613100; ConnectionSize_mm: 40 mm; Insulation_thickness_mm: 40 mm; User Code: DN; SystemClass: Hydronic Return; Material: Stålrør normaltykke
BI11T - Rørskål m/Al.folie - varme 60-25 | Nivå D | BI11T - Rørskål m/Al.folie - varme 60-25 | 83 | 0.0152625 | 0.000222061 | 58.7 | 58.7 | ORIGINAL | MagiCAD Pset_Valve - Manufacturer: TA; Description: Presetting of flow, shut-off valve, flow measuring,pressure reading 10-50; qv_SizingFlow_ls: 0 m3/s; pTot_SizingFlow_kPa: 0 Pa; dpTot_SizingFlow_kPa: 0 Pa; Product Code: STAD/F-10/09; User Code: SV01T; Insulation_thickness_mm: 20 mm; NationalCode: UL5.11091
BI11T - Rørskål m/Al.folie - varme 60-25 | Nivå D | BI11T - Rørskål m/Al.folie - varme 60-25 | 148 | 0.0325056 | 0.000555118 | 70 | 70 | ORIGINAL | MagiCAD Pset_Heating - v_SizingFlow_ms: 0 m/s; pTot_SizingFlow_kPa: 0 Pa; dpTot_SizingFlow_kPa: 0 Pa; MagiCAD Pset_Water - dpTot_SizingFlow_kPa: 0 Pa; pTot_SizingFlow_kPa: 0 Pa; v_SizingFlow_ms: 0 m/s; MagiCAD Pset_Pipe - Length_mm: 148.05 mm; SystemName: +TI=322.004 R; SystemType: SHUNTET VARME R; qv_SizingFlow_ls: 0 m3/s; NationalCode: UB3.144613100; ConnectionSize_mm: 10 mm; Insulation_thickness_mm: 30 mm; User Code: DN; SystemClass: Hydronic Return; Material: Stålrør normaltykke
BI11T - Rørskål m/Al.folie - varme 60-25 | Nivå D | BI11T - Rørskål m/Al.folie - varme 60-25 | 132.8 | 0.0540817 | 0.00178015 | 132.8 | 130 | ORIGINAL | MagiCAD Pset_Valve - Manufacturer: TA; Description: Presetting of flow, shut-off valve, flow measuring,pressure reading 10-50; qv_SizingFlow_ls: 0 m3/s; pTot_SizingFlow_kPa: 0 Pa; dpTot_SizingFlow_kPa: 0 Pa; Product Code: STAD/F-40; User Code: SV01T; Insulation_thickness_mm: 40 mm; NationalCode: UL5.11091
BI11T - Rørskål m/Al.folie - varme 60-25 | Nivå D | BI11T - Rørskål m/Al.folie - varme 60-25 | 156.7 | 0.0589996 | 0.00156733 | 120 | 120 | ORIGINAL | MagiCAD Pset_Heating - v_SizingFlow_ms: 0 m/s; pTot_SizingFlow_kPa: 0 Pa; dpTot_SizingFlow_kPa: 0 Pa; MagiCAD Pset_Water - dpTot_SizingFlow_kPa: 0 Pa; pTot_SizingFlow_kPa: 0 Pa; v_SizingFlow_ms: 0 m/s; MagiCAD Pset_Pipe - Length_mm: 156.595 mm; SystemName: +TI=322.004 R; SystemType: SHUNTET VARME R; qv_SizingFlow_ls: 0 m3/s; NationalCode: UB3.144613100; ConnectionSize_mm: 40 mm; Insulation_thickness_mm: 40 mm; User Code: DN; SystemClass: Hydronic Return; Material: Stålrør normaltykke
2 x BI11T - Rørskål m/Al.folie - varme 60-25 | Nivå D | BI11T - Rørskål m/Al.folie - varme 60-25 | 160.4 | 0.0201302 | 0.0019486 | 125.5 | 96.8 | ORIGINAL | MagiCAD Pset_TBranch - qv_SizingFlow_ls: 0 m3/s; pTot_SizingFlow_Pa: 0 Pa; dpTot_SizingFlow_Pa: 0 Pa; v_SizingFlow_ms: 0 m/s; ConnectionSize_mm: 0 mm; Insulation_thickness_mm: 50 mm
BI11T - Rørskål m/Al.folie - varme 60-25 | Nivå D | BI11T - Rørskål m/Al.folie - varme 60-25 | 591.4 | 0.22267 | 0.00591526 | 120 | 120 | ORIGINAL | MagiCAD Pset_Heating - v_SizingFlow_ms: 0 m/s; pTot_SizingFlow_kPa: 0 Pa; dpTot_SizingFlow_kPa: 0 Pa; MagiCAD Pset_Water - dpTot_SizingFlow_kPa: 0 Pa; pTot_SizingFlow_kPa: 0 Pa; v_SizingFlow_ms: 0 m/s; MagiCAD Pset_Pipe - Length_mm: 591.401 mm; SystemName: +TI=322.004 T; SystemType: SHUNTET VARME T; qv_SizingFlow_ls: 0 m3/s; NationalCode: UB3.144613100; ConnectionSize_mm: 40 mm; Insulation_thickness_mm: 40 mm; User Code: DN; SystemClass: Hydronic Supply; Material: Stålrør normaltykke
BI11T - Rørskål m/Al.folie - varme 60-25 | Nivå D | BI11T - Rørskål m/Al.folie - varme 60-25 | 127.1 | 0.0478548 | 0.00127127 | 120 | 120 | ORIGINAL | MagiCAD Pset_Heating - v_SizingFlow_ms: 0 m/s; pTot_SizingFlow_kPa: 0 Pa; dpTot_SizingFlow_kPa: 0 Pa; MagiCAD Pset_Water - dpTot_SizingFlow_kPa: 0 Pa; pTot_SizingFlow_kPa: 0 Pa; v_SizingFlow_ms: 0 m/s; MagiCAD Pset_Pipe - Length_mm: 127.106 mm; SystemName: +TI=322.004 R; SystemType: SHUNTET VARME R; qv_SizingFlow_ls: 0 m3/s; NationalCode: UB3.144613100; ConnectionSize_mm: 40 mm; Insulation_thickness_mm: 40 mm; User Code: DN; SystemClass: Hydronic Return; Material: Stålrør normaltykke
BI11T - Rørskål m/Al.folie - varme 60-25 | Nivå D | BI11T - Rørskål m/Al.folie - varme 60-25 | 283.3 | 0.106666 | 0.0028336 | 120 | 120 | ORIGINAL | MagiCAD Pset_Heating - v_SizingFlow_ms: 0 m/s; pTot_SizingFlow_kPa: 0 Pa; dpTot_SizingFlow_kPa: 0 Pa; MagiCAD Pset_Water - dpTot_SizingFlow_kPa: 0 Pa; pTot_SizingFlow_kPa: 0 Pa; v_SizingFlow_ms: 0 m/s; MagiCAD Pset_Pipe - Length_mm: 283.3 mm; SystemName: +TI=322.004 T; SystemType: SHUNTET VARME T; qv_SizingFlow_ls: 0 m3/s; NationalCode: UB3.144613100; ConnectionSize_mm: 40 mm; Insulation_thickness_mm: 40 mm; User Code: DN; SystemClass: Hydronic Supply; Material: Stålrør normaltykke
BI11T - Rørskål m/Al.folie - varme 60-25 | Nivå D | BI11T - Rørskål m/Al.folie - varme 60-25 | 376.9 | 0.141908 | 0.0037698 | 120 | 120 | ORIGINAL | MagiCAD Pset_Heating - v_SizingFlow_ms: 0 m/s; pTot_SizingFlow_kPa: 0 Pa; dpTot_SizingFlow_kPa: 0 Pa; MagiCAD Pset_Water - dpTot_SizingFlow_kPa: 0 Pa; pTot_SizingFlow_kPa: 0 Pa; v_SizingFlow_ms: 0 m/s; MagiCAD Pset_Pipe - Length_mm: 376.89 mm; SystemName: +TI=322.004 R; SystemType: SHUNTET VARME R; qv_SizingFlow_ls: 0 m3/s; NationalCode: UB3.144613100; ConnectionSize_mm: 40 mm; Insulation_thickness_mm: 40 mm; User Code: DN; SystemClass: Hydronic Return; Material: Stålrør normaltykke
2 x BI11T - Rørskål m/Al.folie - varme 60-25 | Nivå D | BI11T - Rørskål m/Al.folie - varme 60-25 | 12 | 0.0196915 | 0.00021906 | 160.4 | 160.4 | ORIGINAL | MagiCAD Pset_Reduction - qv_SizingFlow_ls: 0 m3/s; pTot_SizingFlow_Pa: 0 Pa; dpTot_SizingFlow_Pa: 0 Pa; v_SizingFlow_ms: 0 m/s; ConnectionSize_mm: 0 mm; Insulation_thickness_mm: 50 mm
BI11T - Rørskål m/Al.folie - varme 60-25 | Nivå D | BI11T - Rørskål m/Al.folie - varme 60-25 | 120 | 0.0225908 | 0.000600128 | 60 | 120 | ORIGINAL | MagiCAD Pset_Heating - v_SizingFlow_ms: 0 m/s; pTot_SizingFlow_kPa: 0 Pa; dpTot_SizingFlow_kPa: 0 Pa; MagiCAD Pset_Water - dpTot_SizingFlow_kPa: 0 Pa; pTot_SizingFlow_kPa: 0 Pa; v_SizingFlow_ms: 0 m/s; MagiCAD Pset_Pipe - Length_mm: 60.018 mm; SystemName: +TI=322.004 T; SystemType: SHUNTET VARME T; qv_SizingFlow_ls: 0 m3/s; NationalCode: UB3.144613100; ConnectionSize_mm: 40 mm; Insulation_thickness_mm: 40 mm; User Code: DN; SystemClass: Hydronic Supply; Material: Stålrør normaltykke
BI11T - Rørskål m/Al.folie - varme 60-25 | Nivå D | BI11T - Rørskål m/Al.folie - varme 60-25 | 643.4 | 0.211967 | 0.00522874 | 105 | 105 | ORIGINAL | MagiCAD Pset_Heating - v_SizingFlow_ms: 0 m/s; pTot_SizingFlow_kPa: 0 Pa; dpTot_SizingFlow_kPa: 0 Pa; MagiCAD Pset_Water - dpTot_SizingFlow_kPa: 0 Pa; pTot_SizingFlow_kPa: 0 Pa; v_SizingFlow_ms: 0 m/s; MagiCAD Pset_Pipe - Length_mm: 642.716 mm; SystemName: 32= T 55° Kopi 1; SystemType: GULVVARME T; qv_SizingFlow_ls: 0 m3/s; NationalCode: UB3.144613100; ConnectionSize_mm: 25 mm; Insulation_thickness_mm: 40 mm; User Code: DN; SystemClass: Hydronic Supply; Material: Stålrør normaltykke
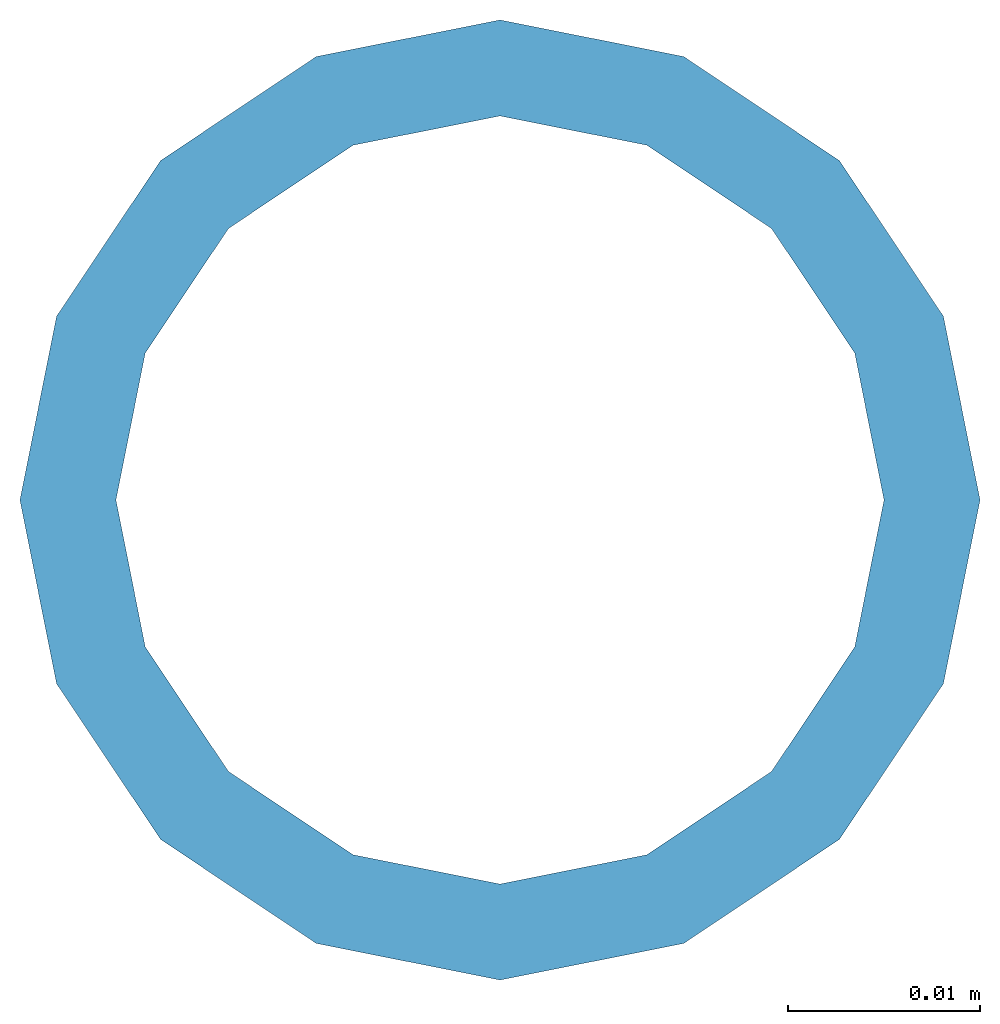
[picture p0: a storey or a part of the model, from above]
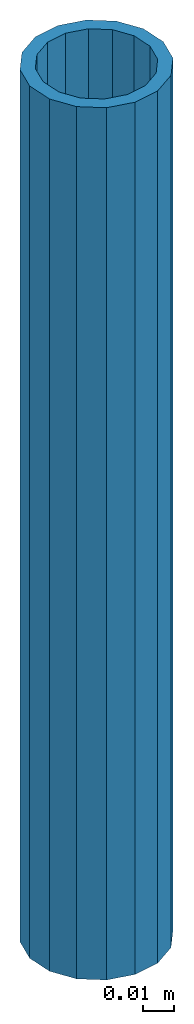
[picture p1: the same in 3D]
Properties of the parts of a building model (IFC2X3), part 3 of 6

# IfcCovering (257)
Name | In | Description | Length (Simplebim) (mm) | Area, largest surface, net (Simplebim) (m2) | Volume, net (Simplebim) (m3) | Height (Simplebim) (mm) | Width (Simplebim) (mm) | Splitting
BI11T - Rørskål m/Al.folie - varme 60-25 | Nivå D | BI11T - Rørskål m/Al.folie - varme 60-25 | 966.4 | 0.318379 | 0.00785368 | 105 | 105 | ORIGINAL | MagiCAD Pset_Heating - v_SizingFlow_ms: 0 m/s; pTot_SizingFlow_kPa: 0 Pa; dpTot_SizingFlow_kPa: 0 Pa; MagiCAD Pset_Water - dpTot_SizingFlow_kPa: 0 Pa; pTot_SizingFlow_kPa: 0 Pa; v_SizingFlow_ms: 0 m/s; MagiCAD Pset_Pipe - Length_mm: 966.448 mm; SystemName: +TI=323.002 R-1; SystemType: GULVVARME R; qv_SizingFlow_ls: 0 m3/s; NationalCode: UB3.144613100; ConnectionSize_mm: 25 mm; Insulation_thickness_mm: 40 mm; User Code: DN; SystemClass: Hydronic Return; Material: Stålrør normaltykke
BI11T - Rørskål m/Al.folie - varme 60-25 | Nivå D | BI11T - Rørskål m/Al.folie - varme 60-25 | 27.2 | 0.00751018 | 0.000147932 | 88 | 88 | ORIGINAL | MagiCAD Pset_Heating - v_SizingFlow_ms: 0 m/s; pTot_SizingFlow_kPa: 0 Pa; dpTot_SizingFlow_kPa: 0 Pa; MagiCAD Pset_Water - dpTot_SizingFlow_kPa: 0 Pa; pTot_SizingFlow_kPa: 0 Pa; v_SizingFlow_ms: 0 m/s; MagiCAD Pset_Pipe - Length_mm: 27.199 mm; SystemName: 32= T 55° Kopi 1; SystemType: GULVVARME T; qv_SizingFlow_ls: 0 m3/s; NationalCode: UB1.111423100; ConnectionSize_mm: 28 mm; Insulation_thickness_mm: 30 mm; SystemClass: Hydronic Supply; Material: PEX rør
BI11T - Rørskål m/Al.folie - varme 60-25 | Nivå D | BI11T - Rørskål m/Al.folie - varme 60-25 | 27.2 | 0.00751018 | 0.000147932 | 88 | 88 | ORIGINAL | MagiCAD Pset_Heating - v_SizingFlow_ms: 0 m/s; pTot_SizingFlow_kPa: 0 Pa; dpTot_SizingFlow_kPa: 0 Pa; MagiCAD Pset_Water - dpTot_SizingFlow_kPa: 0 Pa; pTot_SizingFlow_kPa: 0 Pa; v_SizingFlow_ms: 0 m/s; MagiCAD Pset_Pipe - Length_mm: 27.2 mm; SystemName: +TI=323.002 R-1; SystemType: GULVVARME R; qv_SizingFlow_ls: 0 m3/s; NationalCode: UB1.111423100; ConnectionSize_mm: 28 mm; Insulation_thickness_mm: 30 mm; SystemClass: Hydronic Return; Material: PEX rør
BI11T - Rørskål m/Al.folie - varme 60-25 | Nivå D | BI11T - Rørskål m/Al.folie - varme 60-25 | 175.5 | 0.0578182 | 0.00142624 | 105 | 105 | ORIGINAL | MagiCAD Pset_Heating - v_SizingFlow_ms: 0 m/s; pTot_SizingFlow_kPa: 0 Pa; dpTot_SizingFlow_kPa: 0 Pa; MagiCAD Pset_Water - dpTot_SizingFlow_kPa: 0 Pa; pTot_SizingFlow_kPa: 0 Pa; v_SizingFlow_ms: 0 m/s; MagiCAD Pset_Pipe - Length_mm: 175.502 mm; SystemName: 32= T 55° Kopi 1; SystemType: GULVVARME T; qv_SizingFlow_ls: 0 m3/s; NationalCode: UB3.144613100; ConnectionSize_mm: 25 mm; Insulation_thickness_mm: 40 mm; User Code: DN; SystemClass: Hydronic Supply; Material: Stålrør normaltykke
BI11T - Rørskål m/Al.folie - varme 60-25 | Nivå D | BI11T - Rørskål m/Al.folie - varme 60-25 | 66.4 | 0.0218754 | 0.000539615 | 105 | 105 | ORIGINAL | MagiCAD Pset_Heating - v_SizingFlow_ms: 0 m/s; pTot_SizingFlow_kPa: 0 Pa; dpTot_SizingFlow_kPa: 0 Pa; MagiCAD Pset_Water - dpTot_SizingFlow_kPa: 0 Pa; pTot_SizingFlow_kPa: 0 Pa; v_SizingFlow_ms: 0 m/s; MagiCAD Pset_Pipe - Length_mm: 66.386 mm; SystemName: 32= T 55° Kopi 1; SystemType: GULVVARME T; qv_SizingFlow_ls: 0 m3/s; NationalCode: UB3.144613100; ConnectionSize_mm: 25 mm; Insulation_thickness_mm: 40 mm; User Code: DN; SystemClass: Hydronic Supply; Material: Stålrør normaltykke
4 x BI11T - Rørskål m/Al.folie - varme 60-25 | Nivå D | BI11T - Rørskål m/Al.folie - varme 60-25 | 113.8 | 0.021304 | 0.000551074 | 90.7 | 90.7 | ORIGINAL | MagiCAD Pset_Elbow - qv_SizingFlow_ls: 0 m3/s; pTot_SizingFlow_Pa: 0 Pa; dpTot_SizingFlow_Pa: 0 Pa; v_SizingFlow_ms: 0 m/s; ConnectionSize_mm: 0 mm; Insulation_thickness_mm: 40 mm
2 x BI11T - Rørskål m/Al.folie - varme 60-25 | Nivå D | BI11T - Rørskål m/Al.folie - varme 60-25 | 5.8 | 0.00673403 | 0.0000363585 | 93.8 | 93.8 | ORIGINAL | MagiCAD Pset_Reduction - qv_SizingFlow_ls: 0 m3/s; pTot_SizingFlow_Pa: 0 Pa; dpTot_SizingFlow_Pa: 0 Pa; v_SizingFlow_ms: 0 m/s; ConnectionSize_mm: 0 mm; Insulation_thickness_mm: 30 mm
BI11T - Rørskål m/Al.folie - varme 60-25 | Nivå D | BI11T - Rørskål m/Al.folie - varme 60-25 | 234.1 | 0.0771239 | 0.00190247 | 105 | 105 | ORIGINAL | MagiCAD Pset_Heating - v_SizingFlow_ms: 0 m/s; pTot_SizingFlow_kPa: 0 Pa; dpTot_SizingFlow_kPa: 0 Pa; MagiCAD Pset_Water - dpTot_SizingFlow_kPa: 0 Pa; pTot_SizingFlow_kPa: 0 Pa; v_SizingFlow_ms: 0 m/s; MagiCAD Pset_Pipe - Length_mm: 234.099 mm; SystemName: +TI=323.002 R-1; SystemType: GULVVARME R; qv_SizingFlow_ls: 0 m3/s; NationalCode: UB3.144613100; ConnectionSize_mm: 25 mm; Insulation_thickness_mm: 40 mm; User Code: DN; SystemClass: Hydronic Return; Material: Stålrør normaltykke
BI11T - Rørskål m/Al.folie - varme 60-25 | Nivå D | BI11T - Rørskål m/Al.folie - varme 60-25 | 192 | 0.0632542 | 0.00156033 | 105 | 105 | ORIGINAL | MagiCAD Pset_Heating - v_SizingFlow_ms: 0 m/s; pTot_SizingFlow_kPa: 0 Pa; dpTot_SizingFlow_kPa: 0 Pa; MagiCAD Pset_Water - dpTot_SizingFlow_kPa: 0 Pa; pTot_SizingFlow_kPa: 0 Pa; v_SizingFlow_ms: 0 m/s; MagiCAD Pset_Pipe - Length_mm: 192.04 mm; SystemName: +TI=323.002 R-1; SystemType: GULVVARME R; qv_SizingFlow_ls: 0 m3/s; NationalCode: UB3.144613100; ConnectionSize_mm: 25 mm; Insulation_thickness_mm: 40 mm; User Code: DN; SystemClass: Hydronic Return; Material: Stålrør normaltykke
BI11T - Rørskål m/Al.folie - varme 60-25 | Nivå D | BI11T - Rørskål m/Al.folie - varme 60-25 | 113.8 | 0.0213021 | 0.000551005 | 90.7 | 90.7007 | ORIGINAL | MagiCAD Pset_Elbow - qv_SizingFlow_ls: 0 m3/s; pTot_SizingFlow_Pa: 0 Pa; dpTot_SizingFlow_Pa: 0 Pa; v_SizingFlow_ms: 0 m/s; ConnectionSize_mm: 0 mm; Insulation_thickness_mm: 40 mm
BI11T - Rørskål m/Al.folie - varme 60-25 | Nivå D | BI11T - Rørskål m/Al.folie - varme 60-25 | 113.8 | 0.0213022 | 0.000551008 | 90.7 | 90.7016 | ORIGINAL | MagiCAD Pset_Elbow - qv_SizingFlow_ls: 0 m3/s; pTot_SizingFlow_Pa: 0 Pa; dpTot_SizingFlow_Pa: 0 Pa; v_SizingFlow_ms: 0 m/s; ConnectionSize_mm: 0 mm; Insulation_thickness_mm: 40 mm
BI15T - Cellegummi KV 15mm | Nivå D | BI15T - Cellegummi KV 15mm | 70 | 0.00392 | 0.00021952 | 56 | 56 | ORIGINAL | MagiCAD Pset_TBranch - qv_SizingFlow_ls: 0 m3/s; pTot_SizingFlow_Pa: 0 Pa; dpTot_SizingFlow_Pa: 0 Pa; v_SizingFlow_ms: 0 m/s; ConnectionSize_mm: 0 mm; Insulation_thickness_mm: 21 mm
BI15T - Cellegummi KV 15mm | Nivå D | BI15T - Cellegummi KV 15mm | 67 | 0.018365 | 0.000398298 | 87.5 | 87.5 | ORIGINAL | MagiCAD Pset_Valve - Manufacturer: Armatec; Description: Ball valve, threaded, brass; qv_SizingFlow_ls: 0 m3/s; pTot_SizingFlow_kPa: 0 Pa; dpTot_SizingFlow_kPa: 0 Pa; Product Code: AT3600-25; User Code: SM01T; Insulation_thickness_mm: 21 mm
BI15T - Cellegummi KV 15mm | Nivå D | BI15T - Cellegummi KV 15mm | 159.6 | 0.0350533 | 0.000513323 | 70 | 70 | ORIGINAL | MagiCAD Pset_Heating - v_SizingFlow_ms: 0 m/s; pTot_SizingFlow_kPa: 0 Pa; dpTot_SizingFlow_kPa: 0 Pa; MagiCAD Pset_Water - dpTot_SizingFlow_kPa: 0 Pa; pTot_SizingFlow_kPa: 0 Pa; v_SizingFlow_ms: 0 m/s; MagiCAD Pset_Pipe - Length_mm: 159.593 mm; SystemName: +TI=310.101-1; SystemType: KV; qv_SizingFlow_ls: 0 m3/s; NationalCode: UB1.111713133; ConnectionSize_mm: 28 mm; Insulation_thickness_mm: 21 mm; User Code: Cu; SystemClass: Domestic Cold Water; Material: Kobberrør
4 x BI15T - Cellegummi KV 15mm | Nivå D | BI15T - Cellegummi KV 15mm | 3 | 0.003675 | 0.000011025 | 70 | 70 | ORIGINAL | MagiCAD Pset_Reduction - qv_SizingFlow_ls: 0 m3/s; pTot_SizingFlow_Pa: 0 Pa; dpTot_SizingFlow_Pa: 0 Pa; v_SizingFlow_ms: 0 m/s; ConnectionSize_mm: 0 mm; Insulation_thickness_mm: 21 mm
BI16T - Rørskål m/Al.folie - VV 40mm | Nivå D | BI16T - Rørskål m/Al.folie - VV 40mm | 67 | 0.022143 | 0.000579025 | 105.5 | 105.5 | ORIGINAL | MagiCAD Pset_Valve - Manufacturer: Armatec; Description: Ball valve, threaded, brass; qv_SizingFlow_ls: 0 m3/s; pTot_SizingFlow_kPa: 0 Pa; dpTot_SizingFlow_kPa: 0 Pa; Product Code: AT3600-25; User Code: SM01T; Insulation_thickness_mm: 30 mm
2 x BI16T - Rørskål m/Al.folie - VV 40mm | Nivå D | BI16T - Rørskål m/Al.folie - VV 40mm | 7 | 0.00843817 | 0.0000590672 | 105 | 105 | ORIGINAL | MagiCAD Pset_Reduction - qv_SizingFlow_ls: 0 m3/s; pTot_SizingFlow_Pa: 0 Pa; dpTot_SizingFlow_Pa: 0 Pa; v_SizingFlow_ms: 0 m/s; ConnectionSize_mm: 0 mm; Insulation_thickness_mm: 40 mm
2 x BI10T - Cellegummi 18-32 mm kalde rør | Nivå D | BI10T - Cellegummi 18-32 mm kalde rør | 81 | 0.0247907 | 0.000600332 | 97.7 | 97.7 | ORIGINAL | MagiCAD Pset_Valve - Manufacturer: Armatec; Description: Ball valve, threaded, brass; qv_SizingFlow_ls: 0 m3/s; pTot_SizingFlow_kPa: 0 Pa; dpTot_SizingFlow_kPa: 0 Pa; Product Code: AT3600-32; User Code: SM01T; Insulation_thickness_mm: 24 mm
BI11T - Rørskål m/Al.folie - varme 60-25 | Nivå D | BI11T - Rørskål m/Al.folie - varme 60-25 | 95 | 0.0199392 | 0.000469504 | 95 | 67 | ORIGINAL | MagiCAD Pset_Valve - Manufacturer: Armatec; Description: Ball valve, threaded, brass, long neck; qv_SizingFlow_ls: 0 m3/s; pTot_SizingFlow_kPa: 0 Pa; dpTot_SizingFlow_kPa: 0 Pa; Product Code: AT3601-25; User Code: SM02T; Insulation_thickness_mm: 30 mm; NationalCode: UL1.4091
BI11T - Rørskål m/Al.folie - varme 60-25 | Nivå D | BI11T - Rørskål m/Al.folie - varme 60-25 | 1249.8 | 0.411745 | 0.0101568 | 105 | 105 | ORIGINAL | MagiCAD Pset_Heating - v_SizingFlow_ms: 0 m/s; pTot_SizingFlow_kPa: 0 Pa; dpTot_SizingFlow_kPa: 0 Pa; MagiCAD Pset_Water - dpTot_SizingFlow_kPa: 0 Pa; pTot_SizingFlow_kPa: 0 Pa; v_SizingFlow_ms: 0 m/s; MagiCAD Pset_Pipe - Length_mm: 1249.77 mm; SystemName: +TI=323.002 R-1; SystemType: GULVVARME R; qv_SizingFlow_ls: 0 m3/s; NationalCode: UB3.144613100; ConnectionSize_mm: 25 mm; Insulation_thickness_mm: 40 mm; User Code: DN; SystemClass: Hydronic Return; Material: Stålrør normaltykke
BI11T - Rørskål m/Al.folie - varme 60-25 | Nivå D | BI11T - Rørskål m/Al.folie - varme 60-25 | 67 | 0.0199392 | 0.000469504 | 95 | 95 | ORIGINAL | MagiCAD Pset_Valve - Manufacturer: Armatec; Description: Ball valve, threaded, brass, long neck; qv_SizingFlow_ls: 0 m3/s; pTot_SizingFlow_kPa: 0 Pa; dpTot_SizingFlow_kPa: 0 Pa; Product Code: AT3601-25; User Code: SM02T; Insulation_thickness_mm: 30 mm; NationalCode: UL1.4091
BI11T - Rørskål m/Al.folie - varme 60-25 | Nivå D | BI11T - Rørskål m/Al.folie - varme 60-25 | 701.7 | 0.231174 | 0.00570253 | 105 | 105 | ORIGINAL | MagiCAD Pset_Heating - v_SizingFlow_ms: 0 m/s; pTot_SizingFlow_kPa: 0 Pa; dpTot_SizingFlow_kPa: 0 Pa; MagiCAD Pset_Water - dpTot_SizingFlow_kPa: 0 Pa; pTot_SizingFlow_kPa: 0 Pa; v_SizingFlow_ms: 0 m/s; MagiCAD Pset_Pipe - Length_mm: 701.668 mm; SystemName: 32= T 55° Kopi 1; SystemType: GULVVARME T; qv_SizingFlow_ls: 0 m3/s; NationalCode: UB3.144613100; ConnectionSize_mm: 25 mm; Insulation_thickness_mm: 40 mm; User Code: DN; SystemClass: Hydronic Supply; Material: Stålrør normaltykke
BI11T - Rørskål m/Al.folie - varme 60-25 | Nivå D | BI11T - Rørskål m/Al.folie - varme 60-25 | 94 | 0.0382807 | 0.00123348 | 130 | 130 | ORIGINAL | MagiCAD Pset_Valve - Manufacturer: Armatec; Description: Ball valve, threaded, brass, long neck; qv_SizingFlow_ls: 0 m3/s; pTot_SizingFlow_kPa: 0 Pa; dpTot_SizingFlow_kPa: 0 Pa; Product Code: AT3601-40; User Code: SM02T; Insulation_thickness_mm: 40 mm; NationalCode: UL1.4091
BI11T - Rørskål m/Al.folie - varme 60-25 | Nivå D | BI11T - Rørskål m/Al.folie - varme 60-25 | 613.2 | 0.230878 | 0.00613331 | 120 | 120 | ORIGINAL | MagiCAD Pset_Heating - v_SizingFlow_ms: 0 m/s; pTot_SizingFlow_kPa: 0 Pa; dpTot_SizingFlow_kPa: 0 Pa; MagiCAD Pset_Water - dpTot_SizingFlow_kPa: 0 Pa; pTot_SizingFlow_kPa: 0 Pa; v_SizingFlow_ms: 0 m/s; MagiCAD Pset_Pipe - Length_mm: 613.248 mm; SystemName: +TI=322.004 T; SystemType: SHUNTET VARME T; qv_SizingFlow_ls: 0 m3/s; NationalCode: UB3.144613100; ConnectionSize_mm: 40 mm; Insulation_thickness_mm: 40 mm; User Code: DN; SystemClass: Hydronic Supply; Material: Stålrør normaltykke
BI11T - Rørskål m/Al.folie - varme 60-25 | Nivå D | BI11T - Rørskål m/Al.folie - varme 60-25 | 4145.8 | 1.56095 | 0.0414669 | 120 | 120 | ORIGINAL | MagiCAD Pset_Heating - v_SizingFlow_ms: 0 m/s; pTot_SizingFlow_kPa: 0 Pa; dpTot_SizingFlow_kPa: 0 Pa; MagiCAD Pset_Water - dpTot_SizingFlow_kPa: 0 Pa; pTot_SizingFlow_kPa: 0 Pa; v_SizingFlow_ms: 0 m/s; MagiCAD Pset_Pipe - Length_mm: 4145.84 mm; SystemName: +TI=322.004 T; SystemType: SHUNTET VARME T; qv_SizingFlow_ls: 0 m3/s; NationalCode: UB3.144613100; ConnectionSize_mm: 40 mm; Insulation_thickness_mm: 40 mm; User Code: DN; SystemClass: Hydronic Supply; Material: Stålrør normaltykke
BI10T - Cellegummi 18-32 mm kalde rør | Nivå D | BI10T - Cellegummi 18-32 mm kalde rør | 9506.4 | 1.8493 | 0.0255836 | 62 | 62 | ORIGINAL | MagiCAD Pset_Heating - v_SizingFlow_ms: 0 m/s; pTot_SizingFlow_kPa: 0 Pa; dpTot_SizingFlow_kPa: 0 Pa; MagiCAD Pset_Water - dpTot_SizingFlow_kPa: 0 Pa; pTot_SizingFlow_kPa: 0 Pa; v_SizingFlow_ms: 0 m/s; MagiCAD Pset_Pipe - Length_mm: 9506.4 mm; SystemName: +TI=370.001 T; SystemType: KJØL T; qv_SizingFlow_ls: 0 m3/s; NationalCode: UB3.144613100; ConnectionSize_mm: 20 mm; Insulation_thickness_mm: 21 mm; User Code: DN; SystemClass: Hydronic Supply; Material: Stålrør normaltykke
10 x BI10T - Cellegummi 18-32 mm kalde rør | Nivå D | BI10T - Cellegummi 18-32 mm kalde rør | 68.8 | 0.00821363 | 0.000154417 | 61.2 | 61.2 | ORIGINAL | MagiCAD Pset_Elbow - qv_SizingFlow_ls: 0 m3/s; pTot_SizingFlow_Pa: 0 Pa; dpTot_SizingFlow_Pa: 0 Pa; v_SizingFlow_ms: 0 m/s; ConnectionSize_mm: 0 mm; Insulation_thickness_mm: 21 mm
BI10T - Cellegummi 18-32 mm kalde rør | Nivå D | BI10T - Cellegummi 18-32 mm kalde rør | 3366.4 | 0.654871 | 0.00905965 | 62 | 62 | ORIGINAL | MagiCAD Pset_Heating - v_SizingFlow_ms: 0 m/s; pTot_SizingFlow_kPa: 0 Pa; dpTot_SizingFlow_kPa: 0 Pa; MagiCAD Pset_Water - dpTot_SizingFlow_kPa: 0 Pa; pTot_SizingFlow_kPa: 0 Pa; v_SizingFlow_ms: 0 m/s; MagiCAD Pset_Pipe - Length_mm: 3366.4 mm; SystemName: +TI=370.001 T; SystemType: KJØL T; qv_SizingFlow_ls: 0 m3/s; NationalCode: UB3.144613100; ConnectionSize_mm: 20 mm; Insulation_thickness_mm: 21 mm; User Code: DN; SystemClass: Hydronic Supply; Material: Stålrør normaltykke
BI10T - Cellegummi 18-32 mm kalde rør | Nivå D | BI10T - Cellegummi 18-32 mm kalde rør | 9343.9 | 1.81768 | 0.0251463 | 62 | 62 | ORIGINAL | MagiCAD Pset_Heating - v_SizingFlow_ms: 0 m/s; pTot_SizingFlow_kPa: 0 Pa; dpTot_SizingFlow_kPa: 0 Pa; MagiCAD Pset_Water - dpTot_SizingFlow_kPa: 0 Pa; pTot_SizingFlow_kPa: 0 Pa; v_SizingFlow_ms: 0 m/s; MagiCAD Pset_Pipe - Length_mm: 9343.9 mm; SystemName: +TI=370.001 R; SystemType: KJØL R; qv_SizingFlow_ls: 0 m3/s; NationalCode: UB3.144613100; ConnectionSize_mm: 20 mm; Insulation_thickness_mm: 21 mm; User Code: DN; SystemClass: Hydronic Return; Material: Stålrør normaltykke
BI10T - Cellegummi 18-32 mm kalde rør | Nivå D | BI10T - Cellegummi 18-32 mm kalde rør | 3366.4 | 0.654871 | 0.00905965 | 62 | 62 | ORIGINAL | MagiCAD Pset_Heating - v_SizingFlow_ms: 0 m/s; pTot_SizingFlow_kPa: 0 Pa; dpTot_SizingFlow_kPa: 0 Pa; MagiCAD Pset_Water - dpTot_SizingFlow_kPa: 0 Pa; pTot_SizingFlow_kPa: 0 Pa; v_SizingFlow_ms: 0 m/s; MagiCAD Pset_Pipe - Length_mm: 3366.4 mm; SystemName: +TI=370.001 R; SystemType: KJØL R; qv_SizingFlow_ls: 0 m3/s; NationalCode: UB3.144613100; ConnectionSize_mm: 20 mm; Insulation_thickness_mm: 21 mm; User Code: DN; SystemClass: Hydronic Return; Material: Stålrør normaltykke
BI16T - Rørskål m/Al.folie - VV 40mm | Nivå D | BI16T - Rørskål m/Al.folie - VV 40mm | 9064 | 2.21826 | 0.0407967 | 78 | 78 | ORIGINAL | MagiCAD Pset_Heating - v_SizingFlow_ms: 0 m/s; pTot_SizingFlow_kPa: 0 Pa; dpTot_SizingFlow_kPa: 0 Pa; MagiCAD Pset_Water - dpTot_SizingFlow_kPa: 0 Pa; pTot_SizingFlow_kPa: 0 Pa; v_SizingFlow_ms: 0 m/s; MagiCAD Pset_Pipe - Length_mm: 9064 mm; SystemName: +TI=310.201-1; SystemType: VV; qv_SizingFlow_ls: 0 m3/s; NationalCode: UB1.111713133; ConnectionSize_mm: 18 mm; Insulation_thickness_mm: 30 mm; User Code: Cu; SystemClass: Domestic Hot Water; Material: Kobberrør
4 x BI16T - Rørskål m/Al.folie - VV 40mm | Nivå D | BI16T - Rørskål m/Al.folie - VV 40mm | 78 | 0.00819582 | 0.000146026 | 57 | 57 | ORIGINAL | MagiCAD Pset_Elbow - qv_SizingFlow_ls: 0 m3/s; pTot_SizingFlow_Pa: 0 Pa; dpTot_SizingFlow_Pa: 0 Pa; v_SizingFlow_ms: 0 m/s; ConnectionSize_mm: 0 mm; Insulation_thickness_mm: 30 mm
BI15T - Cellegummi KV 15mm | Nivå D | BI15T - Cellegummi KV 15mm | 9194 | 2.0193 | 0.0295708 | 70 | 70 | ORIGINAL | MagiCAD Pset_Heating - v_SizingFlow_ms: 0 m/s; pTot_SizingFlow_kPa: 0 Pa; dpTot_SizingFlow_kPa: 0 Pa; MagiCAD Pset_Water - dpTot_SizingFlow_kPa: 0 Pa; pTot_SizingFlow_kPa: 0 Pa; v_SizingFlow_ms: 0 m/s; MagiCAD Pset_Pipe - Length_mm: 9194 mm; SystemName: +TI=310.101-1; SystemType: KV; qv_SizingFlow_ls: 0 m3/s; NationalCode: UB1.111713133; ConnectionSize_mm: 28 mm; Insulation_thickness_mm: 21 mm; User Code: Cu; SystemClass: Domestic Cold Water; Material: Kobberrør
BI10T - Cellegummi 18-32 mm kalde rør | Nivå D | BI10T - Cellegummi 18-32 mm kalde rør | 2091.8 | 0.406921 | 0.00562945 | 62 | 62 | ORIGINAL | MagiCAD Pset_Heating - v_SizingFlow_ms: 0 m/s; pTot_SizingFlow_kPa: 0 Pa; dpTot_SizingFlow_kPa: 0 Pa; MagiCAD Pset_Water - dpTot_SizingFlow_kPa: 0 Pa; pTot_SizingFlow_kPa: 0 Pa; v_SizingFlow_ms: 0 m/s; MagiCAD Pset_Pipe - Length_mm: 2091.85 mm; SystemName: +TI=370.001 T; SystemType: KJØL T; qv_SizingFlow_ls: 0 m3/s; NationalCode: UB3.144613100; ConnectionSize_mm: 20 mm; Insulation_thickness_mm: 21 mm; User Code: DN; SystemClass: Hydronic Supply; Material: Stålrør normaltykke
BI10T - Cellegummi 18-32 mm kalde rør | Nivå D | BI10T - Cellegummi 18-32 mm kalde rør | 2091.8 | 0.406921 | 0.00562945 | 62 | 62 | ORIGINAL | MagiCAD Pset_Heating - v_SizingFlow_ms: 0 m/s; pTot_SizingFlow_kPa: 0 Pa; dpTot_SizingFlow_kPa: 0 Pa; MagiCAD Pset_Water - dpTot_SizingFlow_kPa: 0 Pa; pTot_SizingFlow_kPa: 0 Pa; v_SizingFlow_ms: 0 m/s; MagiCAD Pset_Pipe - Length_mm: 2091.85 mm; SystemName: +TI=370.001 R; SystemType: KJØL R; qv_SizingFlow_ls: 0 m3/s; NationalCode: UB3.144613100; ConnectionSize_mm: 20 mm; Insulation_thickness_mm: 21 mm; User Code: DN; SystemClass: Hydronic Return; Material: Stålrør normaltykke
BI15T - Cellegummi KV 15mm | Nivå D | BI15T - Cellegummi KV 15mm | 2117.3 | 0.465028 | 0.0068099 | 70 | 70 | ORIGINAL | MagiCAD Pset_Heating - v_SizingFlow_ms: 0 m/s; pTot_SizingFlow_kPa: 0 Pa; dpTot_SizingFlow_kPa: 0 Pa; MagiCAD Pset_Water - dpTot_SizingFlow_kPa: 0 Pa; pTot_SizingFlow_kPa: 0 Pa; v_SizingFlow_ms: 0 m/s; MagiCAD Pset_Pipe - Length_mm: 2117.25 mm; SystemName: +TI=310.101-1; SystemType: KV; qv_SizingFlow_ls: 0 m3/s; NationalCode: UB1.111713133; ConnectionSize_mm: 28 mm; Insulation_thickness_mm: 21 mm; User Code: Cu; SystemClass: Domestic Cold Water; Material: Kobberrør
BI16T - Rørskål m/Al.folie - VV 40mm | Nivå D | BI16T - Rørskål m/Al.folie - VV 40mm | 2140 | 0.523729 | 0.00963206 | 78 | 78 | ORIGINAL | MagiCAD Pset_Heating - v_SizingFlow_ms: 0 m/s; pTot_SizingFlow_kPa: 0 Pa; dpTot_SizingFlow_kPa: 0 Pa; MagiCAD Pset_Water - dpTot_SizingFlow_kPa: 0 Pa; pTot_SizingFlow_kPa: 0 Pa; v_SizingFlow_ms: 0 m/s; MagiCAD Pset_Pipe - Length_mm: 2140 mm; SystemName: +TI=310.201-1; SystemType: VV; qv_SizingFlow_ls: 0 m3/s; NationalCode: UB1.111713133; ConnectionSize_mm: 18 mm; Insulation_thickness_mm: 30 mm; User Code: Cu; SystemClass: Domestic Hot Water; Material: Kobberrør
2 x BI15T - Cellegummi KV 15mm | Nivå D | BI15T - Cellegummi KV 15mm | 70 | 0.00863032 | 0.000166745 | 63 | 63 | ORIGINAL | MagiCAD Pset_Elbow - qv_SizingFlow_ls: 0 m3/s; pTot_SizingFlow_Pa: 0 Pa; dpTot_SizingFlow_Pa: 0 Pa; v_SizingFlow_ms: 0 m/s; ConnectionSize_mm: 0 mm; Insulation_thickness_mm: 21 mm
BI16T - Rørskål m/Al.folie - VV 40mm | Nivå D | BI16T - Rørskål m/Al.folie - VV 40mm | 4799 | 1.17448 | 0.0216001 | 78 | 78 | ORIGINAL | MagiCAD Pset_Heating - v_SizingFlow_ms: 0 m/s; pTot_SizingFlow_kPa: 0 Pa; dpTot_SizingFlow_kPa: 0 Pa; MagiCAD Pset_Water - dpTot_SizingFlow_kPa: 0 Pa; pTot_SizingFlow_kPa: 0 Pa; v_SizingFlow_ms: 0 m/s; MagiCAD Pset_Pipe - Length_mm: 4799 mm; SystemName: +TI=310.201-1; SystemType: VV; qv_SizingFlow_ls: 0 m3/s; NationalCode: UB1.111713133; ConnectionSize_mm: 18 mm; Insulation_thickness_mm: 30 mm; User Code: Cu; SystemClass: Domestic Hot Water; Material: Kobberrør
BI16T - Rørskål m/Al.folie - VV 40mm | Nivå D | BI16T - Rørskål m/Al.folie - VV 40mm | 131.8 | 0.0322559 | 0.000593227 | 78 | 78 | ORIGINAL | MagiCAD Pset_Heating - v_SizingFlow_ms: 0 m/s; pTot_SizingFlow_kPa: 0 Pa; dpTot_SizingFlow_kPa: 0 Pa; MagiCAD Pset_Water - dpTot_SizingFlow_kPa: 0 Pa; pTot_SizingFlow_kPa: 0 Pa; v_SizingFlow_ms: 0 m/s; MagiCAD Pset_Pipe - Length_mm: 131.8 mm; SystemName: +TI=310.201-1; SystemType: VV; qv_SizingFlow_ls: 0 m3/s; NationalCode: UB1.111713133; ConnectionSize_mm: 18 mm; Insulation_thickness_mm: 30 mm; User Code: Cu; SystemClass: Domestic Hot Water; Material: Kobberrør
BI15T - Cellegummi KV 15mm | Nivå D | BI15T - Cellegummi KV 15mm | 112 | 0.0245988 | 0.000360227 | 70 | 70 | ORIGINAL | MagiCAD Pset_Heating - v_SizingFlow_ms: 0 m/s; pTot_SizingFlow_kPa: 0 Pa; dpTot_SizingFlow_kPa: 0 Pa; MagiCAD Pset_Water - dpTot_SizingFlow_kPa: 0 Pa; pTot_SizingFlow_kPa: 0 Pa; v_SizingFlow_ms: 0 m/s; MagiCAD Pset_Pipe - Length_mm: 111.818 mm; SystemName: +TI=310.101-1; SystemType: KV; qv_SizingFlow_ls: 0 m3/s; NationalCode: UB1.111713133; ConnectionSize_mm: 28 mm; Insulation_thickness_mm: 21 mm; User Code: Cu; SystemClass: Domestic Cold Water; Material: Kobberrør
BI15T - Cellegummi KV 15mm | Nivå D | BI15T - Cellegummi KV 15mm | 70 | 0.00863755 | 0.000166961 | 63.0002 | 63 | ORIGINAL | MagiCAD Pset_Elbow - qv_SizingFlow_ls: 0 m3/s; pTot_SizingFlow_Pa: 0 Pa; dpTot_SizingFlow_Pa: 0 Pa; v_SizingFlow_ms: 0 m/s; ConnectionSize_mm: 0 mm; Insulation_thickness_mm: 21 mm
2 x BI10T - Cellegummi 18-32 mm kalde rør | Nivå D | BI10T - Cellegummi 18-32 mm kalde rør | 15.6 | 0.00612912 | 0.0000800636 | 90.4 | 90.4 | ORIGINAL | MagiCAD Pset_Reduction - qv_SizingFlow_ls: 0 m3/s; pTot_SizingFlow_Pa: 0 Pa; dpTot_SizingFlow_Pa: 0 Pa; v_SizingFlow_ms: 0 m/s; ConnectionSize_mm: 0 mm; Insulation_thickness_mm: 24 mm
BI10T - Cellegummi 18-32 mm kalde rør | Nivå D | BI10T - Cellegummi 18-32 mm kalde rør | 5312.1 | 1.03337 | 0.0142959 | 62 | 62 | ORIGINAL | MagiCAD Pset_Heating - v_SizingFlow_ms: 0 m/s; pTot_SizingFlow_kPa: 0 Pa; dpTot_SizingFlow_kPa: 0 Pa; MagiCAD Pset_Water - dpTot_SizingFlow_kPa: 0 Pa; pTot_SizingFlow_kPa: 0 Pa; v_SizingFlow_ms: 0 m/s; MagiCAD Pset_Pipe - Length_mm: 5312.15 mm; SystemName: +TI=370.001 R; SystemType: KJØL R; qv_SizingFlow_ls: 0 m3/s; NationalCode: UB3.144613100; ConnectionSize_mm: 20 mm; Insulation_thickness_mm: 21 mm; User Code: DN; SystemClass: Hydronic Return; Material: Stålrør normaltykke
BI10T - Cellegummi 18-32 mm kalde rør | Nivå D | BI10T - Cellegummi 18-32 mm kalde rør | 5412.2 | 1.05284 | 0.0145653 | 62 | 62 | ORIGINAL | MagiCAD Pset_Heating - v_SizingFlow_ms: 0 m/s; pTot_SizingFlow_kPa: 0 Pa; dpTot_SizingFlow_kPa: 0 Pa; MagiCAD Pset_Water - dpTot_SizingFlow_kPa: 0 Pa; pTot_SizingFlow_kPa: 0 Pa; v_SizingFlow_ms: 0 m/s; MagiCAD Pset_Pipe - Length_mm: 5412.15 mm; SystemName: +TI=370.001 T; SystemType: KJØL T; qv_SizingFlow_ls: 0 m3/s; NationalCode: UB3.144613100; ConnectionSize_mm: 20 mm; Insulation_thickness_mm: 21 mm; User Code: DN; SystemClass: Hydronic Supply; Material: Stålrør normaltykke
BI10T - Cellegummi 18-32 mm kalde rør | Nivå D | BI10T - Cellegummi 18-32 mm kalde rør | 114.2 | 0.0222155 | 0.000307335 | 62 | 62 | ORIGINAL | MagiCAD Pset_Heating - v_SizingFlow_ms: 0 m/s; pTot_SizingFlow_kPa: 0 Pa; dpTot_SizingFlow_kPa: 0 Pa; MagiCAD Pset_Water - dpTot_SizingFlow_kPa: 0 Pa; pTot_SizingFlow_kPa: 0 Pa; v_SizingFlow_ms: 0 m/s; MagiCAD Pset_Pipe - Length_mm: 114.2 mm; SystemName: +TI=370.001 T; SystemType: KJØL T; qv_SizingFlow_ls: 0 m3/s; NationalCode: UB3.144613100; ConnectionSize_mm: 20 mm; Insulation_thickness_mm: 21 mm; User Code: DN; SystemClass: Hydronic Supply; Material: Stålrør normaltykke
BI10T - Cellegummi 18-32 mm kalde rør | Nivå D | BI10T - Cellegummi 18-32 mm kalde rør | 114.2 | 0.0222155 | 0.000307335 | 62 | 62 | ORIGINAL | MagiCAD Pset_Heating - v_SizingFlow_ms: 0 m/s; pTot_SizingFlow_kPa: 0 Pa; dpTot_SizingFlow_kPa: 0 Pa; MagiCAD Pset_Water - dpTot_SizingFlow_kPa: 0 Pa; pTot_SizingFlow_kPa: 0 Pa; v_SizingFlow_ms: 0 m/s; MagiCAD Pset_Pipe - Length_mm: 113.996 mm; SystemName: +TI=370.001 R; SystemType: KJØL R; qv_SizingFlow_ls: 0 m3/s; NationalCode: UB3.144613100; ConnectionSize_mm: 20 mm; Insulation_thickness_mm: 21 mm; User Code: DN; SystemClass: Hydronic Return; Material: Stålrør normaltykke
BI15T - Cellegummi KV 15mm | Nivå D | BI15T - Cellegummi KV 15mm | 613.9 | 0.10594 | 0.00134319 | 55 | 55 | ORIGINAL | MagiCAD Pset_Heating - v_SizingFlow_ms: 0 m/s; pTot_SizingFlow_kPa: 0 Pa; dpTot_SizingFlow_kPa: 0 Pa; MagiCAD Pset_Water - dpTot_SizingFlow_kPa: 0 Pa; pTot_SizingFlow_kPa: 0 Pa; v_SizingFlow_ms: 0 m/s; MagiCAD Pset_Pipe - Length_mm: 613.9 mm; SystemName: +TI=310.101-1; SystemType: KV; qv_SizingFlow_ls: 0 m3/s; NationalCode: UB1.111713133; ConnectionSize_mm: 15 mm; Insulation_thickness_mm: 20 mm; User Code: Cu; SystemClass: Domestic Cold Water; Material: Kobberrør
BI15T - Cellegummi KV 15mm | Nivå D | BI15T - Cellegummi KV 15mm | 132.2 | 0.0228135 | 0.000289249 | 55 | 55 | ORIGINAL | MagiCAD Pset_Heating - v_SizingFlow_ms: 0 m/s; pTot_SizingFlow_kPa: 0 Pa; dpTot_SizingFlow_kPa: 0 Pa; MagiCAD Pset_Water - dpTot_SizingFlow_kPa: 0 Pa; pTot_SizingFlow_kPa: 0 Pa; v_SizingFlow_ms: 0 m/s; MagiCAD Pset_Pipe - Length_mm: 132.212 mm; SystemName: +TI=310.101-1; SystemType: KV; qv_SizingFlow_ls: 0 m3/s; NationalCode: UB1.111713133; ConnectionSize_mm: 15 mm; Insulation_thickness_mm: 20 mm; User Code: Cu; SystemClass: Domestic Cold Water; Material: Kobberrør
BI15T - Cellegummi KV 15mm | Nivå D | BI15T - Cellegummi KV 15mm | 59 | 0.0101815 | 0.00012909 | 55 | 55 | ORIGINAL | MagiCAD Pset_Heating - v_SizingFlow_ms: 0 m/s; pTot_SizingFlow_kPa: 0 Pa; dpTot_SizingFlow_kPa: 0 Pa; MagiCAD Pset_Water - dpTot_SizingFlow_kPa: 0 Pa; pTot_SizingFlow_kPa: 0 Pa; v_SizingFlow_ms: 0 m/s; MagiCAD Pset_Pipe - Length_mm: 59 mm; SystemName: +TI=310.101-1; SystemType: KV; qv_SizingFlow_ls: 0 m3/s; NationalCode: UB1.111713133; ConnectionSize_mm: 15 mm; Insulation_thickness_mm: 20 mm; User Code: Cu; SystemClass: Domestic Cold Water; Material: Kobberrør
BI15T - Cellegummi KV 15mm | Nivå D | BI15T - Cellegummi KV 15mm | 70 | 0.00392 | 0.0001176 | 56 | 30 | ORIGINAL | MagiCAD Pset_TBranch - qv_SizingFlow_ls: 0 m3/s; pTot_SizingFlow_Pa: 0 Pa; dpTot_SizingFlow_Pa: 0 Pa; v_SizingFlow_ms: 0 m/s; ConnectionSize_mm: 0 mm; Insulation_thickness_mm: 21 mm
BI15T - Cellegummi KV 15mm | Nivå D | BI15T - Cellegummi KV 15mm | 1996.7 | 0.43854 | 0.00642201 | 70 | 70 | ORIGINAL | MagiCAD Pset_Heating - v_SizingFlow_ms: 0 m/s; pTot_SizingFlow_kPa: 0 Pa; dpTot_SizingFlow_kPa: 0 Pa; MagiCAD Pset_Water - dpTot_SizingFlow_kPa: 0 Pa; pTot_SizingFlow_kPa: 0 Pa; v_SizingFlow_ms: 0 m/s; MagiCAD Pset_Pipe - Length_mm: 1996.72 mm; SystemName: +TI=310.101-1; SystemType: KV; qv_SizingFlow_ls: 0 m3/s; NationalCode: UB1.111713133; ConnectionSize_mm: 28 mm; Insulation_thickness_mm: 21 mm; User Code: Cu; SystemClass: Domestic Cold Water; Material: Kobberrør
2 x BI15T - Cellegummi KV 15mm | Nivå D | BI15T - Cellegummi KV 15mm | 55 | 0.00439181 | 0.0000578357 | 42.5 | 42.5 | ORIGINAL | MagiCAD Pset_Elbow - qv_SizingFlow_ls: 0 m3/s; pTot_SizingFlow_Pa: 0 Pa; dpTot_SizingFlow_Pa: 0 Pa; v_SizingFlow_ms: 0 m/s; ConnectionSize_mm: 0 mm; Insulation_thickness_mm: 20 mm
BI10T - Cellegummi 18-32 mm kalde rør | Nivå D | BI10T - Cellegummi 18-32 mm kalde rør | 1351.3 | 0.245911 | 0.00321002 | 58 | 58 | ORIGINAL | MagiCAD Pset_Heating - v_SizingFlow_ms: 0 m/s; pTot_SizingFlow_kPa: 0 Pa; dpTot_SizingFlow_kPa: 0 Pa; MagiCAD Pset_Water - dpTot_SizingFlow_kPa: 0 Pa; pTot_SizingFlow_kPa: 0 Pa; v_SizingFlow_ms: 0 m/s; MagiCAD Pset_Pipe - Length_mm: 1351.26 mm; SystemName: +TI=350.001 R-1; SystemType: KJØLMEDIE R; qv_SizingFlow_ls: 0 m3/s; NationalCode: UB1.111713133; ConnectionSize_mm: 18 mm; Insulation_thickness_mm: 20 mm; User Code: Cu; SystemClass: Hydronic Return; Material: Kobberrør
BI10T - Cellegummi 18-32 mm kalde rør | Nivå D | BI10T - Cellegummi 18-32 mm kalde rør | 1004 | 0.182709 | 0.00238501 | 58 | 58 | ORIGINAL | MagiCAD Pset_Heating - v_SizingFlow_ms: 0 m/s; pTot_SizingFlow_kPa: 0 Pa; dpTot_SizingFlow_kPa: 0 Pa; MagiCAD Pset_Water - dpTot_SizingFlow_kPa: 0 Pa; pTot_SizingFlow_kPa: 0 Pa; v_SizingFlow_ms: 0 m/s; MagiCAD Pset_Pipe - Length_mm: 1004 mm; SystemName: +TI=350.001 R-1; SystemType: KJØLMEDIE R; qv_SizingFlow_ls: 0 m3/s; NationalCode: UB1.111713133; ConnectionSize_mm: 18 mm; Insulation_thickness_mm: 20 mm; User Code: Cu; SystemClass: Hydronic Return; Material: Kobberrør
BI10T - Cellegummi 18-32 mm kalde rør | Nivå D | BI10T - Cellegummi 18-32 mm kalde rør | 174 | 0.0316647 | 0.000413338 | 58 | 58 | ORIGINAL | MagiCAD Pset_Heating - v_SizingFlow_ms: 0 m/s; pTot_SizingFlow_kPa: 0 Pa; dpTot_SizingFlow_kPa: 0 Pa; MagiCAD Pset_Water - dpTot_SizingFlow_kPa: 0 Pa; pTot_SizingFlow_kPa: 0 Pa; v_SizingFlow_ms: 0 m/s; MagiCAD Pset_Pipe - Length_mm: 174 mm; SystemName: +TI=350.001 R-1; SystemType: KJØLMEDIE R; qv_SizingFlow_ls: 0 m3/s; NationalCode: UB1.111713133; ConnectionSize_mm: 18 mm; Insulation_thickness_mm: 20 mm; User Code: Cu; SystemClass: Hydronic Return; Material: Kobberrør
14 x BI10T - Cellegummi 18-32 mm kalde rør | Nivå D | BI10T - Cellegummi 18-32 mm kalde rør | 58 | 0.00520685 | 0.0000756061 | 47 | 47 | ORIGINAL | MagiCAD Pset_Elbow - qv_SizingFlow_ls: 0 m3/s; pTot_SizingFlow_Pa: 0 Pa; dpTot_SizingFlow_Pa: 0 Pa; v_SizingFlow_ms: 0 m/s; ConnectionSize_mm: 0 mm; Insulation_thickness_mm: 20 mm
BI10T - Cellegummi 18-32 mm kalde rør | Nivå D | BI10T - Cellegummi 18-32 mm kalde rør | 3644 | 0.663139 | 0.00865635 | 58 | 58 | ORIGINAL | MagiCAD Pset_Heating - v_SizingFlow_ms: 0 m/s; pTot_SizingFlow_kPa: 0 Pa; dpTot_SizingFlow_kPa: 0 Pa; MagiCAD Pset_Water - dpTot_SizingFlow_kPa: 0 Pa; pTot_SizingFlow_kPa: 0 Pa; v_SizingFlow_ms: 0 m/s; MagiCAD Pset_Pipe - Length_mm: 3644 mm; SystemName: +TI=350.001 R-1; SystemType: KJØLMEDIE R; qv_SizingFlow_ls: 0 m3/s; NationalCode: UB1.111713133; ConnectionSize_mm: 18 mm; Insulation_thickness_mm: 20 mm; User Code: Cu; SystemClass: Hydronic Return; Material: Kobberrør
BI10T - Cellegummi 18-32 mm kalde rør | Nivå D | BI10T - Cellegummi 18-32 mm kalde rør | 1336.3 | 0.243181 | 0.00317439 | 58 | 58 | ORIGINAL | MagiCAD Pset_Heating - v_SizingFlow_ms: 0 m/s; pTot_SizingFlow_kPa: 0 Pa; dpTot_SizingFlow_kPa: 0 Pa; MagiCAD Pset_Water - dpTot_SizingFlow_kPa: 0 Pa; pTot_SizingFlow_kPa: 0 Pa; v_SizingFlow_ms: 0 m/s; MagiCAD Pset_Pipe - Length_mm: 1336.26 mm; SystemName: +TI=350.001 T-1; SystemType: KJØLMEDIE T; qv_SizingFlow_ls: 0 m3/s; NationalCode: UB1.111713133; ConnectionSize_mm: 18 mm; Insulation_thickness_mm: 20 mm; User Code: Cu; SystemClass: Hydronic Supply; Material: Kobberrør
BI10T - Cellegummi 18-32 mm kalde rør | Nivå D | BI10T - Cellegummi 18-32 mm kalde rør | 899.3 | 0.163656 | 0.00213629 | 58 | 58 | ORIGINAL | MagiCAD Pset_Heating - v_SizingFlow_ms: 0 m/s; pTot_SizingFlow_kPa: 0 Pa; dpTot_SizingFlow_kPa: 0 Pa; MagiCAD Pset_Water - dpTot_SizingFlow_kPa: 0 Pa; pTot_SizingFlow_kPa: 0 Pa; v_SizingFlow_ms: 0 m/s; MagiCAD Pset_Pipe - Length_mm: 899.267 mm; SystemName: +TI=350.001 T-1; SystemType: KJØLMEDIE T; qv_SizingFlow_ls: 0 m3/s; NationalCode: UB1.111713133; ConnectionSize_mm: 18 mm; Insulation_thickness_mm: 20 mm; User Code: Cu; SystemClass: Hydronic Supply; Material: Kobberrør
BI10T - Cellegummi 18-32 mm kalde rør | Nivå D | BI10T - Cellegummi 18-32 mm kalde rør | 104 | 0.018926 | 0.000247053 | 58 | 58 | ORIGINAL | MagiCAD Pset_Heating - v_SizingFlow_ms: 0 m/s; pTot_SizingFlow_kPa: 0 Pa; dpTot_SizingFlow_kPa: 0 Pa; MagiCAD Pset_Water - dpTot_SizingFlow_kPa: 0 Pa; pTot_SizingFlow_kPa: 0 Pa; v_SizingFlow_ms: 0 m/s; MagiCAD Pset_Pipe - Length_mm: 104 mm; SystemName: +TI=350.001 T-1; SystemType: KJØLMEDIE T; qv_SizingFlow_ls: 0 m3/s; NationalCode: UB1.111713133; ConnectionSize_mm: 18 mm; Insulation_thickness_mm: 20 mm; User Code: Cu; SystemClass: Hydronic Supply; Material: Kobberrør
BI10T - Cellegummi 18-32 mm kalde rør | Nivå D | BI10T - Cellegummi 18-32 mm kalde rør | 3644 | 0.663139 | 0.00865635 | 58 | 58 | ORIGINAL | MagiCAD Pset_Heating - v_SizingFlow_ms: 0 m/s; pTot_SizingFlow_kPa: 0 Pa; dpTot_SizingFlow_kPa: 0 Pa; MagiCAD Pset_Water - dpTot_SizingFlow_kPa: 0 Pa; pTot_SizingFlow_kPa: 0 Pa; v_SizingFlow_ms: 0 m/s; MagiCAD Pset_Pipe - Length_mm: 3644 mm; SystemName: +TI=350.001 T-1; SystemType: KJØLMEDIE T; qv_SizingFlow_ls: 0 m3/s; NationalCode: UB1.111713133; ConnectionSize_mm: 18 mm; Insulation_thickness_mm: 20 mm; User Code: Cu; SystemClass: Hydronic Supply; Material: Kobberrør
BI10T - Cellegummi 18-32 mm kalde rør | Nivå D | BI10T - Cellegummi 18-32 mm kalde rør | 809 | 0.147223 | 0.00192179 | 58 | 58 | ORIGINAL | MagiCAD Pset_Heating - v_SizingFlow_ms: 0 m/s; pTot_SizingFlow_kPa: 0 Pa; dpTot_SizingFlow_kPa: 0 Pa; MagiCAD Pset_Water - dpTot_SizingFlow_kPa: 0 Pa; pTot_SizingFlow_kPa: 0 Pa; v_SizingFlow_ms: 0 m/s; MagiCAD Pset_Pipe - Length_mm: 809 mm; SystemName: +TI=350.001 T-1; SystemType: KJØLMEDIE T; qv_SizingFlow_ls: 0 m3/s; NationalCode: UB1.111713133; ConnectionSize_mm: 18 mm; Insulation_thickness_mm: 20 mm; User Code: Cu; SystemClass: Hydronic Supply; Material: Kobberrør
BI10T - Cellegummi 18-32 mm kalde rør | Nivå D | BI10T - Cellegummi 18-32 mm kalde rør | 373.8 | 0.0680246 | 0.000887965 | 58 | 58 | ORIGINAL | MagiCAD Pset_Heating - v_SizingFlow_ms: 0 m/s; pTot_SizingFlow_kPa: 0 Pa; dpTot_SizingFlow_kPa: 0 Pa; MagiCAD Pset_Water - dpTot_SizingFlow_kPa: 0 Pa; pTot_SizingFlow_kPa: 0 Pa; v_SizingFlow_ms: 0 m/s; MagiCAD Pset_Pipe - Length_mm: 374 mm; SystemName: +TI=350.001 T-1; SystemType: KJØLMEDIE T; qv_SizingFlow_ls: 0 m3/s; NationalCode: UB1.111713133; ConnectionSize_mm: 18 mm; Insulation_thickness_mm: 20 mm; User Code: Cu; SystemClass: Hydronic Supply; Material: Kobberrør
BI10T - Cellegummi 18-32 mm kalde rør | Nivå D | BI10T - Cellegummi 18-32 mm kalde rør | 821.9 | 0.14957 | 0.00195243 | 58 | 58 | ORIGINAL | MagiCAD Pset_Heating - v_SizingFlow_ms: 0 m/s; pTot_SizingFlow_kPa: 0 Pa; dpTot_SizingFlow_kPa: 0 Pa; MagiCAD Pset_Water - dpTot_SizingFlow_kPa: 0 Pa; pTot_SizingFlow_kPa: 0 Pa; v_SizingFlow_ms: 0 m/s; MagiCAD Pset_Pipe - Length_mm: 821.931 mm; SystemName: +TI=350.001 R-1; SystemType: KJØLMEDIE R; qv_SizingFlow_ls: 0 m3/s; NationalCode: UB1.111713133; ConnectionSize_mm: 18 mm; Insulation_thickness_mm: 20 mm; User Code: Cu; SystemClass: Hydronic Return; Material: Kobberrør
BI10T - Cellegummi 18-32 mm kalde rør | Nivå D | BI10T - Cellegummi 18-32 mm kalde rør | 373.8 | 0.0680246 | 0.000887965 | 58 | 58 | ORIGINAL | MagiCAD Pset_Heating - v_SizingFlow_ms: 0 m/s; pTot_SizingFlow_kPa: 0 Pa; dpTot_SizingFlow_kPa: 0 Pa; MagiCAD Pset_Water - dpTot_SizingFlow_kPa: 0 Pa; pTot_SizingFlow_kPa: 0 Pa; v_SizingFlow_ms: 0 m/s; MagiCAD Pset_Pipe - Length_mm: 374 mm; SystemName: +TI=350.001 R-1; SystemType: KJØLMEDIE R; qv_SizingFlow_ls: 0 m3/s; NationalCode: UB1.111713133; ConnectionSize_mm: 18 mm; Insulation_thickness_mm: 20 mm; User Code: Cu; SystemClass: Hydronic Return; Material: Kobberrør
BI15T - Cellegummi KV 15mm | Nivå D | BI15T - Cellegummi KV 15mm | 70 | 0.00990542 | 0.000145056 | 45.1 | 70 | ORIGINAL | MagiCAD Pset_Heating - v_SizingFlow_ms: 0 m/s; pTot_SizingFlow_kPa: 0 Pa; dpTot_SizingFlow_kPa: 0 Pa; MagiCAD Pset_Water - dpTot_SizingFlow_kPa: 0 Pa; pTot_SizingFlow_kPa: 0 Pa; v_SizingFlow_ms: 0 m/s; MagiCAD Pset_Pipe - Length_mm: 45.057 mm; SystemName: +TI=310.101-1; SystemType: KV; qv_SizingFlow_ls: 0 m3/s; NationalCode: UB1.111713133; ConnectionSize_mm: 28 mm; Insulation_thickness_mm: 21 mm; User Code: Cu; SystemClass: Domestic Cold Water; Material: Kobberrør
BI16T - Rørskål m/Al.folie - VV 40mm | Nivå D | BI16T - Rørskål m/Al.folie - VV 40mm | 78 | 0.0133869 | 0.000246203 | 54.7 | 78 | ORIGINAL | MagiCAD Pset_Heating - v_SizingFlow_ms: 0 m/s; pTot_SizingFlow_kPa: 0 Pa; dpTot_SizingFlow_kPa: 0 Pa; MagiCAD Pset_Water - dpTot_SizingFlow_kPa: 0 Pa; pTot_SizingFlow_kPa: 0 Pa; v_SizingFlow_ms: 0 m/s; MagiCAD Pset_Pipe - Length_mm: 54.66 mm; SystemName: +TI=310.201-1; SystemType: VV; qv_SizingFlow_ls: 0 m3/s; NationalCode: UB1.111713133; ConnectionSize_mm: 18 mm; Insulation_thickness_mm: 30 mm; User Code: Cu; SystemClass: Domestic Hot Water; Material: Kobberrør
BI15T - Cellegummi KV 15mm | Nivå D | BI15T - Cellegummi KV 15mm | 190 | 0.04464 | 0.000829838 | 75 | 75 | ORIGINAL | MagiCAD Pset_PipeComponent - User Code: RF11T; ConnectionSize_mm: 0 mm; qv_SizingFlow_ls: 0 m3/s; pTot_SizingFlow_Pa: 0 Pa; dpTot_SizingFlow_kPa: 0 Pa; Manufacturer: General; Description: Flow meter; Product Code: FM-25
BI15T - Cellegummi KV 15mm | Nivå D | BI15T - Cellegummi KV 15mm | 858.9 | 0.188642 | 0.00276249 | 70 | 70 | ORIGINAL | MagiCAD Pset_Heating - v_SizingFlow_ms: 0 m/s; pTot_SizingFlow_kPa: 0 Pa; dpTot_SizingFlow_kPa: 0 Pa; MagiCAD Pset_Water - dpTot_SizingFlow_kPa: 0 Pa; pTot_SizingFlow_kPa: 0 Pa; v_SizingFlow_ms: 0 m/s; MagiCAD Pset_Pipe - Length_mm: 858.943 mm; SystemName: +TI=310.101-1; SystemType: KV; qv_SizingFlow_ls: 0 m3/s; NationalCode: UB1.111713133; ConnectionSize_mm: 28 mm; Insulation_thickness_mm: 21 mm; User Code: Cu; SystemClass: Domestic Cold Water; Material: Kobberrør
BI16T - Rørskål m/Al.folie - VV 40mm | Nivå D | BI16T - Rørskål m/Al.folie - VV 40mm | 190 | 0.0553535 | 0.00127596 | 93 | 93 | ORIGINAL | MagiCAD Pset_PipeComponent - User Code: RF11T; ConnectionSize_mm: 0 mm; qv_SizingFlow_ls: 0 m3/s; pTot_SizingFlow_Pa: 0 Pa; dpTot_SizingFlow_kPa: 0 Pa; Manufacturer: General; Description: Flow meter; Product Code: FM-25
BI16T - Rørskål m/Al.folie - VV 40mm | Nivå D | BI16T - Rørskål m/Al.folie - VV 40mm | 851.3 | 0.208341 | 0.00383167 | 78 | 78 | ORIGINAL | MagiCAD Pset_Heating - v_SizingFlow_ms: 0 m/s; pTot_SizingFlow_kPa: 0 Pa; dpTot_SizingFlow_kPa: 0 Pa; MagiCAD Pset_Water - dpTot_SizingFlow_kPa: 0 Pa; pTot_SizingFlow_kPa: 0 Pa; v_SizingFlow_ms: 0 m/s; MagiCAD Pset_Pipe - Length_mm: 851.34 mm; SystemName: +TI=310.201-1; SystemType: VV; qv_SizingFlow_ls: 0 m3/s; NationalCode: UB1.111713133; ConnectionSize_mm: 18 mm; Insulation_thickness_mm: 30 mm; User Code: Cu; SystemClass: Domestic Hot Water; Material: Kobberrør
2 x BI16T - Rørskål m/Al.folie - VV 40mm | Nivå D | BI16T - Rørskål m/Al.folie - VV 40mm | 85 | 0.00541875 | 0.0000379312 | 7 | 85 | ORIGINAL | MagiCAD Pset_Reduction - qv_SizingFlow_ls: 0 m3/s; pTot_SizingFlow_Pa: 0 Pa; dpTot_SizingFlow_Pa: 0 Pa; v_SizingFlow_ms: 0 m/s; ConnectionSize_mm: 0 mm; Insulation_thickness_mm: 30 mm
BI15T - Cellegummi KV 15mm | Nivå D | BI15T - Cellegummi KV 15mm | 70 | 0.00863754 | 0.00016696 | 63 | 63.0001 | ORIGINAL | MagiCAD Pset_Elbow - qv_SizingFlow_ls: 0 m3/s; pTot_SizingFlow_Pa: 0 Pa; dpTot_SizingFlow_Pa: 0 Pa; v_SizingFlow_ms: 0 m/s; ConnectionSize_mm: 0 mm; Insulation_thickness_mm: 21 mm
BI10T - Cellegummi 18-32 mm kalde rør | Nivå F | BI10T - Cellegummi 18-32 mm kalde rør | 76.7 | 0.0149206 | 0.000206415 | 62 | 62 | ORIGINAL | MagiCAD Pset_Heating - v_SizingFlow_ms: 0 m/s; pTot_SizingFlow_kPa: 0 Pa; dpTot_SizingFlow_kPa: 0 Pa; MagiCAD Pset_Water - dpTot_SizingFlow_kPa: 0 Pa; pTot_SizingFlow_kPa: 0 Pa; v_SizingFlow_ms: 0 m/s; MagiCAD Pset_Pipe - Length_mm: 76.684 mm; SystemType: Undefined; qv_SizingFlow_ls: 0 m3/s; NationalCode: UB3.144613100; ConnectionSize_mm: 20 mm; Insulation_thickness_mm: 21 mm; User Code: DN; SystemClass: Undefined; Material: Stålrør normaltykke
BI10T - Cellegummi 18-32 mm kalde rør | Nivå F | BI10T - Cellegummi 18-32 mm kalde rør | 72 | 0.0130819 | 0.000233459 | 72 | 58 | ORIGINAL | MagiCAD Pset_Valve - Manufacturer: Armatec; Description: Ball valve, threaded, brass, long neck; qv_SizingFlow_ls: 0 m3/s; pTot_SizingFlow_kPa: 0 Pa; dpTot_SizingFlow_kPa: 0 Pa; Product Code: AT3601-20; User Code: SM02T; Insulation_thickness_mm: 21 mm; NationalCode: UL1.4091
BI10T - Cellegummi 18-32 mm kalde rør | Nivå F | BI10T - Cellegummi 18-32 mm kalde rør | 97 | 0.0217871 | 0.000387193 | 71.7 | 71.7 | ORIGINAL | MagiCAD Pset_Valve - Manufacturer: TA; Description: Presetting of flow, shut-off valve, flow measuring,pressure reading 10-50; qv_SizingFlow_ls: 0 m3/s; pTot_SizingFlow_kPa: 0 Pa; dpTot_SizingFlow_kPa: 0 Pa; Product Code: STAD/F-20; User Code: SV01T; Insulation_thickness_mm: 21 mm; NationalCode: UL5.11091
BI10T - Cellegummi 18-32 mm kalde rør | Nivå F | BI10T - Cellegummi 18-32 mm kalde rør | 83 | 0.0239208 | 0.00054547 | 92 | 92 | ORIGINAL | MagiCAD Pset_Valve - Manufacturer: Honeywell; Description: Two-way control valve PN16, threaded, with 600N motor; qv_SizingFlow_ls: 0 m3/s; pTot_SizingFlow_kPa: 0 Pa; dpTot_SizingFlow_kPa: 0 Pa; Product Code: V5011R1059+ML6425A; User Code: MV01; Insulation_thickness_mm: 21 mm; MagiCAD Pset_FireDamper - Manufacturer: Honeywell; Description: Two-way control valve PN16, threaded, with 600N motor; qv_SizingFlow_ls: 0 m3/s; pTot_SizingFlow_Pa: 0 Pa; dpTot_SizingFlow_Pa: 0 Pa; v_SizingFlow_ms: 0 m/s; Product Code: V5011R1059+ML6425A; User Code: MV01; sets with these values: 2; MagiCAD Pset_Silencer - Manufacturer: Honeywell; Description: Two-way control valve PN16, threaded, with 600N motor; qv_SizingFlow_ls: 0 m3/s; pTot_SizingFlow_Pa: 0 Pa; dpTot_SizingFlow_Pa: 0 Pa; ProductCode: V5011R1059+ML6425A; User Code: MV01
BI10T - Cellegummi 18-32 mm kalde rør | Nivå F | BI10T - Cellegummi 18-32 mm kalde rør | 7.6 | 0.0026912 | 0.0000204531 | 62 | 62 | ORIGINAL | MagiCAD Pset_Heating - v_SizingFlow_ms: 0 m/s; pTot_SizingFlow_kPa: 0 Pa; dpTot_SizingFlow_kPa: 0 Pa; MagiCAD Pset_Water - dpTot_SizingFlow_kPa: 0 Pa; pTot_SizingFlow_kPa: 0 Pa; v_SizingFlow_ms: 0 m/s; MagiCAD Pset_Pipe - Length_mm: 8.054 mm; SystemType: Undefined; qv_SizingFlow_ls: 0 m3/s; NationalCode: UB3.144613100; ConnectionSize_mm: 20 mm; Insulation_thickness_mm: 21 mm; User Code: DN; SystemClass: Undefined; Material: Stålrør normaltykke
BI10T - Cellegummi 18-32 mm kalde rør | Nivå F | BI10T - Cellegummi 18-32 mm kalde rør | 89.6 | 0.01743 | 0.000241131 | 62 | 62 | ORIGINAL | MagiCAD Pset_Heating - v_SizingFlow_ms: 0 m/s; pTot_SizingFlow_kPa: 0 Pa; dpTot_SizingFlow_kPa: 0 Pa; MagiCAD Pset_Water - dpTot_SizingFlow_kPa: 0 Pa; pTot_SizingFlow_kPa: 0 Pa; v_SizingFlow_ms: 0 m/s; MagiCAD Pset_Pipe - Length_mm: 89.641 mm; SystemType: Undefined; qv_SizingFlow_ls: 0 m3/s; NationalCode: UB3.144613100; ConnectionSize_mm: 20 mm; Insulation_thickness_mm: 21 mm; User Code: DN; SystemClass: Undefined; Material: Stålrør normaltykke
11 x BI10T - Cellegummi 18-32 mm kalde rør | Nivå F | BI10T - Cellegummi 18-32 mm kalde rør | 68.8 | 0.00821363 | 0.000154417 | 61.2 | 61.2 | ORIGINAL | MagiCAD Pset_Elbow - qv_SizingFlow_ls: 0 m3/s; pTot_SizingFlow_Pa: 0 Pa; dpTot_SizingFlow_Pa: 0 Pa; v_SizingFlow_ms: 0 m/s; ConnectionSize_mm: 0 mm; Insulation_thickness_mm: 21 mm
BI10T - Cellegummi 18-32 mm kalde rør | Nivå F | BI10T - Cellegummi 18-32 mm kalde rør | 13.8 | 0.0026912 | 0.0000371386 | 62 | 62 | ORIGINAL | MagiCAD Pset_Heating - v_SizingFlow_ms: 0 m/s; pTot_SizingFlow_kPa: 0 Pa; dpTot_SizingFlow_kPa: 0 Pa; MagiCAD Pset_Water - dpTot_SizingFlow_kPa: 0 Pa; pTot_SizingFlow_kPa: 0 Pa; v_SizingFlow_ms: 0 m/s; MagiCAD Pset_Pipe - Length_mm: 13.774 mm; SystemType: Undefined; qv_SizingFlow_ls: 0 m3/s; NationalCode: UB3.144613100; ConnectionSize_mm: 20 mm; Insulation_thickness_mm: 21 mm; User Code: DN; SystemClass: Undefined; Material: Stålrør normaltykke
BI10T - Cellegummi 18-32 mm kalde rør | Nivå F | BI10T - Cellegummi 18-32 mm kalde rør | 762.8 | 0.148389 | 0.00205285 | 62 | 62 | ORIGINAL | MagiCAD Pset_Heating - v_SizingFlow_ms: 0 m/s; pTot_SizingFlow_kPa: 0 Pa; dpTot_SizingFlow_kPa: 0 Pa; MagiCAD Pset_Water - dpTot_SizingFlow_kPa: 0 Pa; pTot_SizingFlow_kPa: 0 Pa; v_SizingFlow_ms: 0 m/s; MagiCAD Pset_Pipe - Length_mm: 762.811 mm; SystemType: Undefined; qv_SizingFlow_ls: 0 m3/s; NationalCode: UB3.144613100; ConnectionSize_mm: 20 mm; Insulation_thickness_mm: 21 mm; User Code: DN; SystemClass: Undefined; Material: Stålrør normaltykke
BI10T - Cellegummi 18-32 mm kalde rør | Nivå F | BI10T - Cellegummi 18-32 mm kalde rør | 1071.7 | 0.20848 | 0.00288416 | 62 | 62 | ORIGINAL | MagiCAD Pset_Heating - v_SizingFlow_ms: 0 m/s; pTot_SizingFlow_kPa: 0 Pa; dpTot_SizingFlow_kPa: 0 Pa; MagiCAD Pset_Water - dpTot_SizingFlow_kPa: 0 Pa; pTot_SizingFlow_kPa: 0 Pa; v_SizingFlow_ms: 0 m/s; MagiCAD Pset_Pipe - Length_mm: 1071.69 mm; SystemName: +TI=370.001 T; SystemType: KJØL T; qv_SizingFlow_ls: 0 m3/s; NationalCode: UB3.144613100; ConnectionSize_mm: 20 mm; Insulation_thickness_mm: 21 mm; User Code: DN; SystemClass: Hydronic Supply; Material: Stålrør normaltykke
BI10T - Cellegummi 18-32 mm kalde rør | Nivå F | BI10T - Cellegummi 18-32 mm kalde rør | 144 | 0.0262053 | 0.000342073 | 58 | 58 | ORIGINAL | MagiCAD Pset_Heating - v_SizingFlow_ms: 0 m/s; pTot_SizingFlow_kPa: 0 Pa; dpTot_SizingFlow_kPa: 0 Pa; MagiCAD Pset_Water - dpTot_SizingFlow_kPa: 0 Pa; pTot_SizingFlow_kPa: 0 Pa; v_SizingFlow_ms: 0 m/s; MagiCAD Pset_Pipe - Length_mm: 144 mm; SystemName: +TI=350.001 R-1; SystemType: KJØLMEDIE R; qv_SizingFlow_ls: 0 m3/s; NationalCode: UB1.111713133; ConnectionSize_mm: 18 mm; Insulation_thickness_mm: 20 mm; User Code: Cu; SystemClass: Hydronic Return; Material: Kobberrør
BI10T - Cellegummi 18-32 mm kalde rør | Nivå F | BI10T - Cellegummi 18-32 mm kalde rør | 104 | 0.018926 | 0.000247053 | 58 | 58 | ORIGINAL | MagiCAD Pset_Heating - v_SizingFlow_ms: 0 m/s; pTot_SizingFlow_kPa: 0 Pa; dpTot_SizingFlow_kPa: 0 Pa; MagiCAD Pset_Water - dpTot_SizingFlow_kPa: 0 Pa; pTot_SizingFlow_kPa: 0 Pa; v_SizingFlow_ms: 0 m/s; MagiCAD Pset_Pipe - Length_mm: 104 mm; SystemName: +TI=350.001 T-1; SystemType: KJØLMEDIE T; qv_SizingFlow_ls: 0 m3/s; NationalCode: UB1.111713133; ConnectionSize_mm: 18 mm; Insulation_thickness_mm: 20 mm; User Code: Cu; SystemClass: Hydronic Supply; Material: Kobberrør
BI10T - Cellegummi 18-32 mm kalde rør | Nivå F | BI10T - Cellegummi 18-32 mm kalde rør | 3722 | 0.677334 | 0.00884164 | 58 | 58 | ORIGINAL | MagiCAD Pset_Heating - v_SizingFlow_ms: 0 m/s; pTot_SizingFlow_kPa: 0 Pa; dpTot_SizingFlow_kPa: 0 Pa; MagiCAD Pset_Water - dpTot_SizingFlow_kPa: 0 Pa; pTot_SizingFlow_kPa: 0 Pa; v_SizingFlow_ms: 0 m/s; MagiCAD Pset_Pipe - Length_mm: 3722 mm; SystemName: +TI=350.001 T-1; SystemType: KJØLMEDIE T; qv_SizingFlow_ls: 0 m3/s; NationalCode: UB1.111713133; ConnectionSize_mm: 18 mm; Insulation_thickness_mm: 20 mm; User Code: Cu; SystemClass: Hydronic Supply; Material: Kobberrør
2 x BI10T - Cellegummi 18-32 mm kalde rør | Nivå F | BI10T - Cellegummi 18-32 mm kalde rør | 58 | 0.00520685 | 0.0000756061 | 47 | 47 | ORIGINAL | MagiCAD Pset_Elbow - qv_SizingFlow_ls: 0 m3/s; pTot_SizingFlow_Pa: 0 Pa; dpTot_SizingFlow_Pa: 0 Pa; v_SizingFlow_ms: 0 m/s; ConnectionSize_mm: 0 mm; Insulation_thickness_mm: 20 mm
BI10T - Cellegummi 18-32 mm kalde rør | Nivå F | BI10T - Cellegummi 18-32 mm kalde rør | 3772 | 0.686433 | 0.00896041 | 58 | 58 | ORIGINAL | MagiCAD Pset_Heating - v_SizingFlow_ms: 0 m/s; pTot_SizingFlow_kPa: 0 Pa; dpTot_SizingFlow_kPa: 0 Pa; MagiCAD Pset_Water - dpTot_SizingFlow_kPa: 0 Pa; pTot_SizingFlow_kPa: 0 Pa; v_SizingFlow_ms: 0 m/s; MagiCAD Pset_Pipe - Length_mm: 3772 mm; SystemName: +TI=350.001 R-1; SystemType: KJØLMEDIE R; qv_SizingFlow_ls: 0 m3/s; NationalCode: UB1.111713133; ConnectionSize_mm: 18 mm; Insulation_thickness_mm: 20 mm; User Code: Cu; SystemClass: Hydronic Return; Material: Kobberrør
BI10T - Cellegummi 18-32 mm kalde rør | Nivå F | BI10T - Cellegummi 18-32 mm kalde rør | 140 | 0.0272344 | 0.000376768 | 62 | 62 | ORIGINAL | MagiCAD Pset_Heating - v_SizingFlow_ms: 0 m/s; pTot_SizingFlow_kPa: 0 Pa; dpTot_SizingFlow_kPa: 0 Pa; MagiCAD Pset_Water - dpTot_SizingFlow_kPa: 0 Pa; pTot_SizingFlow_kPa: 0 Pa; v_SizingFlow_ms: 0 m/s; MagiCAD Pset_Pipe - Length_mm: 140 mm; SystemName: +TI=370.001 R; SystemType: KJØL R; qv_SizingFlow_ls: 0 m3/s; NationalCode: UB3.144613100; ConnectionSize_mm: 20 mm; Insulation_thickness_mm: 21 mm; User Code: DN; SystemClass: Hydronic Return; Material: Stålrør normaltykke
BI16T - Rørskål m/Al.folie - VV 40mm | Nivå F | BI16T - Rørskål m/Al.folie - VV 40mm | 62 | 0.0112245 | 0.000155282 | 57.7 | 62 | ORIGINAL | MagiCAD Pset_Heating - v_SizingFlow_ms: 0 m/s; pTot_SizingFlow_kPa: 0 Pa; dpTot_SizingFlow_kPa: 0 Pa; MagiCAD Pset_Water - dpTot_SizingFlow_kPa: 0 Pa; pTot_SizingFlow_kPa: 0 Pa; v_SizingFlow_ms: 0 m/s; MagiCAD Pset_Pipe - Length_mm: 58.4 mm; SystemName: 37= T 9° Kopi 1; SystemType: KJØL T; qv_SizingFlow_ls: 0 m3/s; NationalCode: UB3.144613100; ConnectionSize_mm: 20 mm; Insulation_thickness_mm: 21 mm; User Code: DN; SystemClass: Hydronic Supply; Material: Stålrør normaltykke
BI10T - Cellegummi 18-32 mm kalde rør | Nivå F | BI10T - Cellegummi 18-32 mm kalde rør | 68.8 | 0.0043105 | 0.0000735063 | 20 | 68.8 | ORIGINAL | MagiCAD Pset_Joint - qv_SizingFlow_ls: 0 m3/s; pTot_SizingFlow_Pa: 0 Pa; dpTot_SizingFlow_Pa: 0 Pa; v_SizingFlow_ms: 0 m/s; ConnectionSize_mm: 0 mm; Insulation_thickness_mm: 21 mm
BI10T - Cellegummi 18-32 mm kalde rør | Nivå F | BI10T - Cellegummi 18-32 mm kalde rør | 133.4 | 0.0259505 | 0.000359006 | 62 | 62 | ORIGINAL | MagiCAD Pset_Heating - v_SizingFlow_ms: 0 m/s; pTot_SizingFlow_kPa: 0 Pa; dpTot_SizingFlow_kPa: 0 Pa; MagiCAD Pset_Water - dpTot_SizingFlow_kPa: 0 Pa; pTot_SizingFlow_kPa: 0 Pa; v_SizingFlow_ms: 0 m/s; MagiCAD Pset_Pipe - Length_mm: 133.2 mm; SystemName: 37= T 9° Kopi 1; SystemType: KJØL T; qv_SizingFlow_ls: 0 m3/s; NationalCode: UB3.144613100; ConnectionSize_mm: 20 mm; Insulation_thickness_mm: 21 mm; User Code: DN; SystemClass: Hydronic Supply; Material: Stålrør normaltykke
BI10T - Cellegummi 18-32 mm kalde rør | Nivå F | BI10T - Cellegummi 18-32 mm kalde rør | 20.6 | 0.00400735 | 0.0000554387 | 62 | 62 | ORIGINAL | MagiCAD Pset_Heating - v_SizingFlow_ms: 0 m/s; pTot_SizingFlow_kPa: 0 Pa; dpTot_SizingFlow_kPa: 0 Pa; MagiCAD Pset_Water - dpTot_SizingFlow_kPa: 0 Pa; pTot_SizingFlow_kPa: 0 Pa; v_SizingFlow_ms: 0 m/s; MagiCAD Pset_Pipe - Length_mm: 21.4 mm; SystemName: 37= T 9° Kopi 1; SystemType: KJØL T; qv_SizingFlow_ls: 0 m3/s; NationalCode: UB3.144613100; ConnectionSize_mm: 20 mm; Insulation_thickness_mm: 21 mm; User Code: DN; SystemClass: Hydronic Supply; Material: Stålrør normaltykke
BI10T - Cellegummi 18-32 mm kalde rør | Nivå F | BI10T - Cellegummi 18-32 mm kalde rør | 291.4 | 0.0566865 | 0.000784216 | 62 | 62 | ORIGINAL | MagiCAD Pset_Heating - v_SizingFlow_ms: 0 m/s; pTot_SizingFlow_kPa: 0 Pa; dpTot_SizingFlow_kPa: 0 Pa; MagiCAD Pset_Water - dpTot_SizingFlow_kPa: 0 Pa; pTot_SizingFlow_kPa: 0 Pa; v_SizingFlow_ms: 0 m/s; MagiCAD Pset_Pipe - Length_mm: 291.4 mm; SystemName: 37= T 9° Kopi 1; SystemType: KJØL T; qv_SizingFlow_ls: 0 m3/s; NationalCode: UB3.144613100; ConnectionSize_mm: 20 mm; Insulation_thickness_mm: 21 mm; User Code: DN; SystemClass: Hydronic Supply; Material: Stålrør normaltykke
BI10T - Cellegummi 18-32 mm kalde rør | Nivå F | BI10T - Cellegummi 18-32 mm kalde rør | 142.8 | 0.0277791 | 0.000384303 | 62 | 62 | ORIGINAL | MagiCAD Pset_Heating - v_SizingFlow_ms: 0 m/s; pTot_SizingFlow_kPa: 0 Pa; dpTot_SizingFlow_kPa: 0 Pa; MagiCAD Pset_Water - dpTot_SizingFlow_kPa: 0 Pa; pTot_SizingFlow_kPa: 0 Pa; v_SizingFlow_ms: 0 m/s; MagiCAD Pset_Pipe - Length_mm: 142.875 mm; SystemName: 37= T 9° Kopi 1; SystemType: KJØL T; qv_SizingFlow_ls: 0 m3/s; NationalCode: UB3.144613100; ConnectionSize_mm: 20 mm; Insulation_thickness_mm: 21 mm; User Code: DN; SystemClass: Hydronic Supply; Material: Stålrør normaltykke
BI10T - Cellegummi 18-32 mm kalde rør | Nivå F | BI10T - Cellegummi 18-32 mm kalde rør | 103.2 | 0.0200757 | 0.000277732 | 62 | 62 | ORIGINAL | MagiCAD Pset_Heating - v_SizingFlow_ms: 0 m/s; pTot_SizingFlow_kPa: 0 Pa; dpTot_SizingFlow_kPa: 0 Pa; MagiCAD Pset_Water - dpTot_SizingFlow_kPa: 0 Pa; pTot_SizingFlow_kPa: 0 Pa; v_SizingFlow_ms: 0 m/s; MagiCAD Pset_Pipe - Length_mm: 103.2 mm; SystemName: 37= R 18° Kopi 1; SystemType: KJØL R; qv_SizingFlow_ls: 0 m3/s; NationalCode: UB3.144613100; ConnectionSize_mm: 20 mm; Insulation_thickness_mm: 21 mm; User Code: DN; SystemClass: Hydronic Return; Material: Stålrør normaltykke
BI10T - Cellegummi 18-32 mm kalde rør | Nivå F | BI10T - Cellegummi 18-32 mm kalde rør | 210.9 | 0.0410267 | 0.000567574 | 62 | 62 | ORIGINAL | MagiCAD Pset_Heating - v_SizingFlow_ms: 0 m/s; pTot_SizingFlow_kPa: 0 Pa; dpTot_SizingFlow_kPa: 0 Pa; MagiCAD Pset_Water - dpTot_SizingFlow_kPa: 0 Pa; pTot_SizingFlow_kPa: 0 Pa; v_SizingFlow_ms: 0 m/s; MagiCAD Pset_Pipe - Length_mm: 211.4 mm; SystemName: 37= R 18° Kopi 1; SystemType: KJØL R; qv_SizingFlow_ls: 0 m3/s; NationalCode: UB3.144613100; ConnectionSize_mm: 20 mm; Insulation_thickness_mm: 21 mm; User Code: DN; SystemClass: Hydronic Return; Material: Stålrør normaltykke
BI10T - Cellegummi 18-32 mm kalde rør | Nivå F | BI10T - Cellegummi 18-32 mm kalde rør | 299.9 | 0.05834 | 0.000807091 | 62 | 62 | ORIGINAL | MagiCAD Pset_Heating - v_SizingFlow_ms: 0 m/s; pTot_SizingFlow_kPa: 0 Pa; dpTot_SizingFlow_kPa: 0 Pa; MagiCAD Pset_Water - dpTot_SizingFlow_kPa: 0 Pa; pTot_SizingFlow_kPa: 0 Pa; v_SizingFlow_ms: 0 m/s; MagiCAD Pset_Pipe - Length_mm: 299.6 mm; SystemName: 37= R 18° Kopi 1; SystemType: KJØL R; qv_SizingFlow_ls: 0 m3/s; NationalCode: UB3.144613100; ConnectionSize_mm: 20 mm; Insulation_thickness_mm: 21 mm; User Code: DN; SystemClass: Hydronic Return; Material: Stålrør normaltykke
BI10T - Cellegummi 18-32 mm kalde rør | Nivå F | BI10T - Cellegummi 18-32 mm kalde rør | 62 | 0.00599157 | 0.0000828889 | 30.8 | 62 | ORIGINAL | MagiCAD Pset_Heating - v_SizingFlow_ms: 0 m/s; pTot_SizingFlow_kPa: 0 Pa; dpTot_SizingFlow_kPa: 0 Pa; MagiCAD Pset_Water - dpTot_SizingFlow_kPa: 0 Pa; pTot_SizingFlow_kPa: 0 Pa; v_SizingFlow_ms: 0 m/s; MagiCAD Pset_Pipe - Length_mm: 31.4 mm; SystemName: 37= R 18° Kopi 1; SystemType: KJØL R; qv_SizingFlow_ls: 0 m3/s; NationalCode: UB3.144613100; ConnectionSize_mm: 20 mm; Insulation_thickness_mm: 21 mm; User Code: DN; SystemClass: Hydronic Return; Material: Stålrør normaltykke
BI10T - Cellegummi 18-32 mm kalde rør | Nivå F | BI10T - Cellegummi 18-32 mm kalde rør | 106.4 | 0.0206982 | 0.000286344 | 62 | 62 | ORIGINAL | MagiCAD Pset_Heating - v_SizingFlow_ms: 0 m/s; pTot_SizingFlow_kPa: 0 Pa; dpTot_SizingFlow_kPa: 0 Pa; MagiCAD Pset_Water - dpTot_SizingFlow_kPa: 0 Pa; pTot_SizingFlow_kPa: 0 Pa; v_SizingFlow_ms: 0 m/s; MagiCAD Pset_Pipe - Length_mm: 106.4 mm; SystemName: 37= R 18° Kopi 1; SystemType: KJØL R; qv_SizingFlow_ls: 0 m3/s; NationalCode: UB3.144613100; ConnectionSize_mm: 20 mm; Insulation_thickness_mm: 21 mm; User Code: DN; SystemClass: Hydronic Return; Material: Stålrør normaltykke
BI10T - Cellegummi 18-32 mm kalde rør | Nivå F | BI10T - Cellegummi 18-32 mm kalde rør | 38.2 | 0.00743111 | 0.000102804 | 62 | 62 | ORIGINAL | MagiCAD Pset_Heating - v_SizingFlow_ms: 0 m/s; pTot_SizingFlow_kPa: 0 Pa; dpTot_SizingFlow_kPa: 0 Pa; MagiCAD Pset_Water - dpTot_SizingFlow_kPa: 0 Pa; pTot_SizingFlow_kPa: 0 Pa; v_SizingFlow_ms: 0 m/s; MagiCAD Pset_Pipe - Length_mm: 38.2 mm; SystemName: 37= R 18° Kopi 1; SystemType: KJØL R; qv_SizingFlow_ls: 0 m3/s; NationalCode: UB3.144613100; ConnectionSize_mm: 20 mm; Insulation_thickness_mm: 21 mm; User Code: DN; SystemClass: Hydronic Return; Material: Stålrør normaltykke
BI11T - Rørskål m/Al.folie - varme 60-25 | Nivå D + 1,2 m | BI11T - Rørskål m/Al.folie - varme 60-25 | 113.8 | 0.021304 | 0.000551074 | 90.7 | 90.7 | ORIGINAL | MagiCAD Pset_Elbow - qv_SizingFlow_ls: 0 m3/s; pTot_SizingFlow_Pa: 0 Pa; dpTot_SizingFlow_Pa: 0 Pa; v_SizingFlow_ms: 0 m/s; ConnectionSize_mm: 0 mm; Insulation_thickness_mm: 40 mm
050mm | Nivå E | 50 mm lamellmatte | 2550 | 3.4425 | 0.38475 | 1350 | 400 | ORIGINAL | MagiCAD Pset_Duct - qv_SizingFlow_ls: 0 m3/s; dpTot_SizingFlow_Pa: 0 Pa; pTot_SizingFlow_Pa: 0 Pa; v_SizingFlow_ms: 0 m/s; Description: Rektangulære, Forsinket stål; Insulation_thickness_mm: 50 mm; Length_mm: 1350 mm; UserCode: 1-REKT
T=25mm | Nivå F | 25mm lamellmatte | 464.2 | 0.990404 | 0.0237591 | 680 | 680 | ORIGINAL | MagiCAD Pset_Duct - qv_SizingFlow_ls: 0 m3/s; dpTot_SizingFlow_Pa: 0 Pa; pTot_SizingFlow_Pa: 0 Pa; v_SizingFlow_ms: 0 m/s; Description: Spiro kanaler, Forsinket stål; Insulation_thickness_mm: 25 mm; Length_mm: 464.193 mm; UserCode: Circ
T=25mm | Nivå F | 25mm lamellmatte | 680 | 0.361327 | 4.69725e-08 | 680 | 0.00039 | ORIGINAL
B-EI60 | Nivå F | EI60 Brannisolasjon 30 mm | 923.1 | 1.08612 | 0.0298629 | 375 | 375 | ORIGINAL | MagiCAD Pset_Duct - qv_SizingFlow_ls: 0 m3/s; dpTot_SizingFlow_Pa: 0 Pa; pTot_SizingFlow_Pa: 0 Pa; v_SizingFlow_ms: 0 m/s; Description: Spiro kanaler, Forsinket stål; Insulation_thickness_mm: 30 mm; Length_mm: 923.135 mm; UserCode: Circ
B-EI60 | Nivå F | EI60 Brannisolasjon 30 mm | 502.5 | 0.57858 | 0.0537249 | 375 | 502.5 | ORIGINAL | MagiCAD Pset_Elbow - qv_SizingFlow_ls: 0 m3/s; pTot_SizingFlow_Pa: 0 Pa; dpTot_SizingFlow_Pa: 0 Pa; v_SizingFlow_ms: 0 m/s; ConnectionSize_mm: 0 mm; Insulation_thickness_mm: 30 mm
B-EI60 | Nivå F | EI60 Brannisolasjon 30 mm | 1368.3 | 1.60995 | 0.0442654 | 375 | 375 | ORIGINAL | MagiCAD Pset_Duct - qv_SizingFlow_ls: 0 m3/s; dpTot_SizingFlow_Pa: 0 Pa; pTot_SizingFlow_Pa: 0 Pa; v_SizingFlow_ms: 0 m/s; Description: Spiro kanaler, Forsinket stål; Insulation_thickness_mm: 30 mm; Length_mm: 1368.35 mm; UserCode: Circ
2 x B-EI60 | Nivå F | EI60 Brannisolasjon 30 mm | 438.75 | 0.38566 | 0.0358162 | 375 | 435.178 | ORIGINAL | MagiCAD Pset_Elbow - qv_SizingFlow_ls: 0 m3/s; pTot_SizingFlow_Pa: 0 Pa; dpTot_SizingFlow_Pa: 0 Pa; v_SizingFlow_ms: 0 m/s; ConnectionSize_mm: 0 mm; Insulation_thickness_mm: 30 mm
B-EI60 | Nivå F | EI60 Brannisolasjon 30 mm | 235 | 0.228212 | 0.0175351 | 310 | 310 | ORIGINAL | MagiCAD Pset_FireDamper - Manufacturer: RF-Technologies; Description: Circular fire damper; qv_SizingFlow_ls: 0 m3/s; pTot_SizingFlow_Pa: 0 Pa; dpTot_SizingFlow_Pa: 0 Pa; v_SizingFlow_ms: 0 m/s; Product Code: CR60-250; User Code: DI-EI60/120 Ø315; ConnectionSize_mm: 250
B-EI60 | Nivå F | EI60 Brannisolasjon 30 mm | 116.2 | 0.113023 | 0.0030509 | 310 | 310 | ORIGINAL | MagiCAD Pset_Duct - qv_SizingFlow_ls: 0 m3/s; dpTot_SizingFlow_Pa: 0 Pa; pTot_SizingFlow_Pa: 0 Pa; v_SizingFlow_ms: 0 m/s; Description: Spiro kanaler, Forsinket stål; Insulation_thickness_mm: 30 mm; Length_mm: 116.23 mm; UserCode: Circ
B-EI60 | Nivå F | EI60 Brannisolasjon 30 mm | 38 | 0.036961 | 0.000997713 | 310 | 310 | ORIGINAL | MagiCAD Pset_Duct - qv_SizingFlow_ls: 0 m3/s; dpTot_SizingFlow_Pa: 0 Pa; pTot_SizingFlow_Pa: 0 Pa; v_SizingFlow_ms: 0 m/s; Description: Spiro kanaler, Forsinket stål; Insulation_thickness_mm: 30 mm; Length_mm: 38.013 mm; UserCode: Circ
B-EI60 | Nivå F | EI60 Brannisolasjon 30 mm | 322.728 | 0.126342 | 0.00968982 | 310 | 202.5 | ORIGINAL | MagiCAD Pset_Elbow - qv_SizingFlow_ls: 0 m3/s; pTot_SizingFlow_Pa: 0 Pa; dpTot_SizingFlow_Pa: 0 Pa; v_SizingFlow_ms: 0 m/s; ConnectionSize_mm: 0 mm; Insulation_thickness_mm: 30 mm
B-EI60 | Nivå F | EI60 Brannisolasjon 30 mm | 310 | 0.0746175 | 0.00410396 | 55 | 310 | ORIGINAL | MagiCAD Pset_FlowDamper - Description: Balancing damper; Product Code: IRIS-250; qv_SizingFlow_ls: 0 m3/s; pTot_SizingFlow_Pa: 0 Pa; dpTot_SizingFlow_Pa: 0 Pa; v_SizingFlow_ms: 0 m/s; NationalCode: VE5.142012; ConnectionSize_mm: 250; Manufacturer: Oeland; User Code: SR01T
B-EI60 | Nivå F | EI60 Brannisolasjon 30 mm | 147.7 | 0.143662 | 0.00387795 | 310 | 310 | ORIGINAL | MagiCAD Pset_Duct - qv_SizingFlow_ls: 0 m3/s; dpTot_SizingFlow_Pa: 0 Pa; pTot_SizingFlow_Pa: 0 Pa; v_SizingFlow_ms: 0 m/s; Description: Spiro kanaler, Forsinket stål; Insulation_thickness_mm: 30 mm; Length_mm: 147.684 mm; UserCode: Circ
B-EI60 | Nivå F | EI60 Brannisolasjon 30 mm | 55 | 0.109522 | 0.00602371 | 375 | 375 | ORIGINAL | MagiCAD Pset_FlowDamper - Description: Balancing damper; Product Code: IRIS-315; qv_SizingFlow_ls: 0 m3/s; pTot_SizingFlow_Pa: 0 Pa; dpTot_SizingFlow_Pa: 0 Pa; v_SizingFlow_ms: 0 m/s; NationalCode: VE5.142012; ConnectionSize_mm: 315; Manufacturer: Oeland; User Code: SR01T
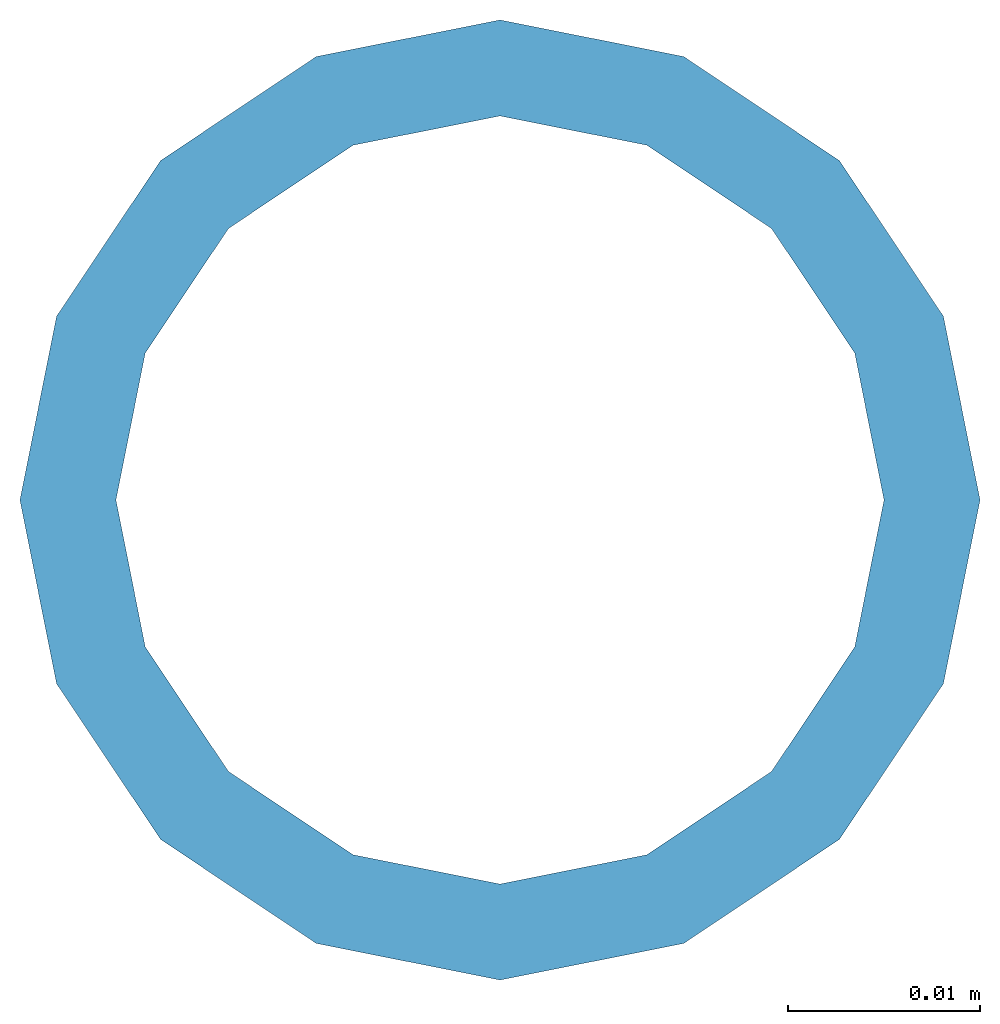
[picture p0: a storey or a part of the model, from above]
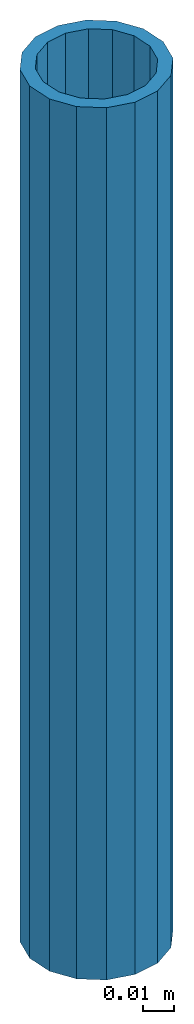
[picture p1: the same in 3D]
Properties of the parts of a building model (IFC2X3), part 4 of 6

# IfcCovering (257)
Name | In | Description | Length (Simplebim) (mm) | Area, largest surface, net (Simplebim) (m2) | Volume, net (Simplebim) (m3) | Height (Simplebim) (mm) | Width (Simplebim) (mm) | Splitting
B-EI60 | Nivå F | EI60 Brannisolasjon 30 mm | 1336.6 | 1.57265 | 0.0432399 | 375 | 375 | ORIGINAL | MagiCAD Pset_Duct - qv_SizingFlow_ls: 0 m3/s; dpTot_SizingFlow_Pa: 0 Pa; pTot_SizingFlow_Pa: 0 Pa; v_SizingFlow_ms: 0 m/s; Description: Spiro kanaler, Forsinket stål; Insulation_thickness_mm: 30 mm; Length_mm: 1336.6 mm; UserCode: Circ
B-EI60 | Nivå F | EI60 Brannisolasjon 30 mm | 76.4 | 0.0743111 | 0.00200593 | 310 | 310 | ORIGINAL | MagiCAD Pset_Duct - qv_SizingFlow_ls: 0 m3/s; dpTot_SizingFlow_Pa: 0 Pa; pTot_SizingFlow_Pa: 0 Pa; v_SizingFlow_ms: 0 m/s; Description: Spiro kanaler, Forsinket stål; Insulation_thickness_mm: 30 mm; Length_mm: 76.447 mm; UserCode: Circ
B-EI60 | Nivå F | EI60 Brannisolasjon 30 mm | 405 | 0.379852 | 0.0291658 | 310 | 405 | ORIGINAL | MagiCAD Pset_Elbow - qv_SizingFlow_ls: 0 m3/s; pTot_SizingFlow_Pa: 0 Pa; dpTot_SizingFlow_Pa: 0 Pa; v_SizingFlow_ms: 0 m/s; ConnectionSize_mm: 0 mm; Insulation_thickness_mm: 30 mm
B-EI60 | Nivå F | EI60 Brannisolasjon 30 mm | 867.7 | 0.843975 | 0.022782 | 310 | 310 | ORIGINAL | MagiCAD Pset_Duct - qv_SizingFlow_ls: 0 m3/s; dpTot_SizingFlow_Pa: 0 Pa; pTot_SizingFlow_Pa: 0 Pa; v_SizingFlow_ms: 0 m/s; Description: Spiro kanaler, Forsinket stål; Insulation_thickness_mm: 30 mm; Length_mm: 867.696 mm; UserCode: Circ
4 x B-EI60 | Nivå F | EI60 Brannisolasjon 30 mm | 337.825 | 0.189962 | 0.0145856 | 310 | 286.378 | ORIGINAL | MagiCAD Pset_Elbow - qv_SizingFlow_ls: 0 m3/s; pTot_SizingFlow_Pa: 0 Pa; dpTot_SizingFlow_Pa: 0 Pa; v_SizingFlow_ms: 0 m/s; ConnectionSize_mm: 0 mm; Insulation_thickness_mm: 30 mm
B-EI60 | Nivå F | EI60 Brannisolasjon 30 mm | 69.9 | 0.0679888 | 0.00183527 | 310 | 310 | ORIGINAL | MagiCAD Pset_Duct - qv_SizingFlow_ls: 0 m3/s; dpTot_SizingFlow_Pa: 0 Pa; pTot_SizingFlow_Pa: 0 Pa; v_SizingFlow_ms: 0 m/s; Description: Spiro kanaler, Forsinket stål; Insulation_thickness_mm: 30 mm; Length_mm: 69.871 mm; UserCode: Circ
B-EI60 | Nivå F | EI60 Brannisolasjon 30 mm | 276.2 | 0.268648 | 0.0072518 | 310 | 310 | ORIGINAL | MagiCAD Pset_Duct - qv_SizingFlow_ls: 0 m3/s; dpTot_SizingFlow_Pa: 0 Pa; pTot_SizingFlow_Pa: 0 Pa; v_SizingFlow_ms: 0 m/s; Description: Spiro kanaler, Forsinket stål; Insulation_thickness_mm: 30 mm; Length_mm: 276.181 mm; UserCode: Circ
B-EI60 | Nivå F | EI60 Brannisolasjon 30 mm | 705 | 0.685724 | 0.0185102 | 310 | 310 | ORIGINAL | MagiCAD Pset_Duct - qv_SizingFlow_ls: 0 m3/s; dpTot_SizingFlow_Pa: 0 Pa; pTot_SizingFlow_Pa: 0 Pa; v_SizingFlow_ms: 0 m/s; Description: Spiro kanaler, Forsinket stål; Insulation_thickness_mm: 30 mm; Length_mm: 705 mm; UserCode: Circ
B-EI60 | Nivå F | EI60 Brannisolasjon 30 mm | 138.904 | 0.134892 | 0.0103647 | 310 | 310 | ORIGINAL
B-EI60 | Nivå F | EI60 Brannisolasjon 30 mm | 660 | 0.3696 | 0.030096 | 260 | 560 | ORIGINAL | MagiCAD Pset_Duct - qv_SizingFlow_ls: 0 m3/s; dpTot_SizingFlow_Pa: 0 Pa; pTot_SizingFlow_Pa: 0 Pa; v_SizingFlow_ms: 0 m/s; Description: Rektangulære, Forsinket stål; Insulation_thickness_mm: 30 mm; Length_mm: 660.003 mm; UserCode: Rect; NationalCode: VB2.111212
B-EI60 | Nivå F | EI60 Brannisolasjon 30 mm | 56.6 | 0.0665957 | 0.00183105 | 375 | 375 | ORIGINAL | MagiCAD Pset_Duct - qv_SizingFlow_ls: 0 m3/s; dpTot_SizingFlow_Pa: 0 Pa; pTot_SizingFlow_Pa: 0 Pa; v_SizingFlow_ms: 0 m/s; Description: Spiro kanaler, Forsinket stål; Insulation_thickness_mm: 30 mm; Length_mm: 56.601 mm; UserCode: Circ
B-EI60 | Nivå F | EI60 Brannisolasjon 30 mm | 10 | 0.109522 | 0.00109522 | 375 | 375 | ORIGINAL | MagiCAD Pset_Joint - qv_SizingFlow_ls: 0 m3/s; pTot_SizingFlow_Pa: 0 Pa; dpTot_SizingFlow_Pa: 0 Pa; v_SizingFlow_ms: 0 m/s; ConnectionSize_mm: 0 mm; Insulation_thickness_mm: 30 mm
B-EI60 | Nivå F | EI60 Brannisolasjon 30 mm | 1545.5 | 1.81844 | 0.0499979 | 375 | 375 | ORIGINAL | MagiCAD Pset_Duct - qv_SizingFlow_ls: 0 m3/s; dpTot_SizingFlow_Pa: 0 Pa; pTot_SizingFlow_Pa: 0 Pa; v_SizingFlow_ms: 0 m/s; Description: Spiro kanaler, Forsinket stål; Insulation_thickness_mm: 30 mm; Length_mm: 1545.52 mm; UserCode: Circ
B-EI60 | Nivå F | EI60 Brannisolasjon 30 mm | 530 | 0.515509 | 0.0139155 | 310 | 310 | ORIGINAL | MagiCAD Pset_Duct - qv_SizingFlow_ls: 0 m3/s; dpTot_SizingFlow_Pa: 0 Pa; pTot_SizingFlow_Pa: 0 Pa; v_SizingFlow_ms: 0 m/s; Description: Spiro kanaler, Forsinket stål; Insulation_thickness_mm: 30 mm; Length_mm: 530 mm; UserCode: Circ
B-EI60 | Nivå F | EI60 Brannisolasjon 30 mm | 10 | 0.0746175 | 0.000746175 | 310 | 310 | ORIGINAL | MagiCAD Pset_Joint - qv_SizingFlow_ls: 0 m3/s; pTot_SizingFlow_Pa: 0 Pa; dpTot_SizingFlow_Pa: 0 Pa; v_SizingFlow_ms: 0 m/s; ConnectionSize_mm: 0 mm; Insulation_thickness_mm: 30 mm
B-EI60 | Nivå F | EI60 Brannisolasjon 30 mm | 246.4 | 0.239663 | 0.00646938 | 310 | 310 | ORIGINAL | MagiCAD Pset_Duct - qv_SizingFlow_ls: 0 m3/s; dpTot_SizingFlow_Pa: 0 Pa; pTot_SizingFlow_Pa: 0 Pa; v_SizingFlow_ms: 0 m/s; Description: Spiro kanaler, Forsinket stål; Insulation_thickness_mm: 30 mm; Length_mm: 246.447 mm; UserCode: Circ
B-EI60 | Nivå F | EI60 Brannisolasjon 30 mm | 19.2 | 0.0262556 | 0.000504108 | 310 | 310 | ORIGINAL | MagiCAD Pset_Duct - qv_SizingFlow_ls: 0 m3/s; dpTot_SizingFlow_Pa: 0 Pa; pTot_SizingFlow_Pa: 0 Pa; v_SizingFlow_ms: 0 m/s; Description: Spiro kanaler, Forsinket stål; Insulation_thickness_mm: 30 mm; Length_mm: 19.167 mm; UserCode: Circ
2 x B-EI60 | Nivå F | EI60 Brannisolasjon 30 mm | 49.5 | 0.040381 | 0.00106757 | 260 | 260 | ORIGINAL | MagiCAD Pset_Duct - qv_SizingFlow_ls: 0 m3/s; dpTot_SizingFlow_Pa: 0 Pa; pTot_SizingFlow_Pa: 0 Pa; v_SizingFlow_ms: 0 m/s; Description: Spiro kanaler, Forsinket stål; Insulation_thickness_mm: 30 mm; Length_mm: 49.469 mm; UserCode: Circ
4 x B-EI60 | Nivå F | EI60 Brannisolasjon 30 mm | 264.222 | 0.0563246 | 0.0036163 | 260 | 112.867 | ORIGINAL | MagiCAD Pset_Elbow - qv_SizingFlow_ls: 0 m3/s; pTot_SizingFlow_Pa: 0 Pa; dpTot_SizingFlow_Pa: 0 Pa; v_SizingFlow_ms: 0 m/s; ConnectionSize_mm: 0 mm; Insulation_thickness_mm: 30 mm
B-EI60 | Nivå F | EI60 Brannisolasjon 30 mm | 84.7 | 0.0690964 | 0.00182673 | 260 | 260 | ORIGINAL | MagiCAD Pset_Duct - qv_SizingFlow_ls: 0 m3/s; dpTot_SizingFlow_Pa: 0 Pa; pTot_SizingFlow_Pa: 0 Pa; v_SizingFlow_ms: 0 m/s; Description: Spiro kanaler, Forsinket stål; Insulation_thickness_mm: 30 mm; Length_mm: 84.735 mm; UserCode: Circ
2 x B-EI60 | Nivå F | EI60 Brannisolasjon 30 mm | 75 | 0.0746175 | 0.00474221 | 310 | 310 | ORIGINAL | MagiCAD Pset_Reduction - qv_SizingFlow_ls: 0 m3/s; pTot_SizingFlow_Pa: 0 Pa; dpTot_SizingFlow_Pa: 0 Pa; v_SizingFlow_ms: 0 m/s; ConnectionSize_mm: 0 mm; Insulation_thickness_mm: 30 mm
B-EI60 | Nivå F | EI60 Brannisolasjon 30 mm | 310 | 0.228128 | 0.017491 | 305 | 305 | ORIGINAL | MagiCAD Pset_Elbow - qv_SizingFlow_ls: 0 m3/s; pTot_SizingFlow_Pa: 0 Pa; dpTot_SizingFlow_Pa: 0 Pa; v_SizingFlow_ms: 0 m/s; ConnectionSize_mm: 0 mm; Insulation_thickness_mm: 30 mm
B-EI60 | Nivå F | EI60 Brannisolasjon 30 mm | 260 | 0.0215671 | 0.000312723 | 14.5 | 260 | ORIGINAL | MagiCAD Pset_Duct - qv_SizingFlow_ls: 0 m3/s; dpTot_SizingFlow_Pa: 0 Pa; pTot_SizingFlow_Pa: 0 Pa; v_SizingFlow_ms: 0 m/s; Description: Spiro kanaler, Forsinket stål; Insulation_thickness_mm: 30 mm; Length_mm: 14.469 mm; UserCode: Circ
B-EI60 | Nivå F | EI60 Brannisolasjon 30 mm | 64.7 | 0.0527808 | 0.00139539 | 260 | 260 | ORIGINAL | MagiCAD Pset_Duct - qv_SizingFlow_ls: 0 m3/s; dpTot_SizingFlow_Pa: 0 Pa; pTot_SizingFlow_Pa: 0 Pa; v_SizingFlow_ms: 0 m/s; Description: Spiro kanaler, Forsinket stål; Insulation_thickness_mm: 30 mm; Length_mm: 64.735 mm; UserCode: Circ
T=25mm | Nivå F | 25mm lamellmatte | 11.6 | 0.0323507 | 0.000375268 | 375 | 375 | ORIGINAL | MagiCAD Pset_Duct - qv_SizingFlow_ls: 0 m3/s; dpTot_SizingFlow_Pa: 0 Pa; pTot_SizingFlow_Pa: 0 Pa; v_SizingFlow_ms: 0 m/s; Description: Spiro kanaler, Forsinket stål; Insulation_thickness_mm: 30 mm; Length_mm: 11.627 mm; UserCode: Circ
T=25mm | Nivå F | 25mm lamellmatte | 15.7 | 0.0323507 | 0.000507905 | 375 | 375 | ORIGINAL | MagiCAD Pset_Duct - qv_SizingFlow_ls: 0 m3/s; dpTot_SizingFlow_Pa: 0 Pa; pTot_SizingFlow_Pa: 0 Pa; v_SizingFlow_ms: 0 m/s; Description: Spiro kanaler, Forsinket stål; Insulation_thickness_mm: 30 mm; Length_mm: 15.654 mm; UserCode: Circ
T=25mm | Nivå F | 25mm lamellmatte | 377.283 | 0.110131 | 0.00652578 | 375 | 94.674 | ORIGINAL | MagiCAD Pset_Elbow - qv_SizingFlow_ls: 0 m3/s; pTot_SizingFlow_Pa: 0 Pa; dpTot_SizingFlow_Pa: 0 Pa; v_SizingFlow_ms: 0 m/s; ConnectionSize_mm: 0 mm; Insulation_thickness_mm: 30 mm
T=25mm | Nivå F | 25mm lamellmatte | 51.2 | 0.0602421 | 0.00165635 | 375 | 375 | ORIGINAL | MagiCAD Pset_Duct - qv_SizingFlow_ls: 0 m3/s; dpTot_SizingFlow_Pa: 0 Pa; pTot_SizingFlow_Pa: 0 Pa; v_SizingFlow_ms: 0 m/s; Description: Spiro kanaler, Forsinket stål; Insulation_thickness_mm: 30 mm; Length_mm: 51.192 mm; UserCode: Circ
2 x T=25mm | Nivå F | 25mm lamellmatte | 392.082 | 0.192853 | 0.0179181 | 375 | 251.25 | ORIGINAL | MagiCAD Pset_Elbow - qv_SizingFlow_ls: 0 m3/s; pTot_SizingFlow_Pa: 0 Pa; dpTot_SizingFlow_Pa: 0 Pa; v_SizingFlow_ms: 0 m/s; ConnectionSize_mm: 0 mm; Insulation_thickness_mm: 30 mm
BI17T - Cellegummi 13 mm SPV fett | Nivå D | BI17T - Cellegummi 13 mm SPV fett | 4506 | 0.0659742 | 0.0567497 | 168 | 168 | RESULT | MagiCAD Pset_Pipe - SystemName: +TI=313.403; SystemType: SPV FETT; NationalCode: UB2.1115131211; User Code: Super-MA; SystemClass: Sanitary; Material: MA
BI11T - Rørskål m/Al.folie - varme 60-25 | Nivå D | BI11T - Rørskål m/Al.folie - varme 60-25 | 5312 | 0.0486099 | 0.0431673 | 104 | 104 | RESULT | MagiCAD Pset_Pipe - SystemName: 32= T 55° Kopi 1; SystemType: GULVVARME T; NationalCode: UB3.144613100; User Code: DN; SystemClass: Hydronic Supply; Material: Stålrør normaltykke
BI11T - Rørskål m/Al.folie - varme 60-25 | Nivå D | BI11T - Rørskål m/Al.folie - varme 60-25 | 4889 | 0.0447439 | 0.0397342 | 104 | 104 | RESULT | MagiCAD Pset_Pipe - SystemName: +TI=323.002 R-1; SystemType: GULVVARME R; NationalCode: UB3.144613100; User Code: DN; SystemClass: Hydronic Return; Material: Stålrør normaltykke
BI10T - Cellegummi 18-32 mm kalde rør | Nivå D | BI10T - Cellegummi 18-32 mm kalde rør | 666 | 0.00336507 | 0.00158134 | 58 | 58 | RESULT | MagiCAD Pset_Pipe - SystemName: +TI=350.001 T-1; SystemType: KJØLMEDIE T; NationalCode: UB1.111713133; User Code: Cu; SystemClass: Hydronic Supply; Material: Kobberrør
BI10T - Cellegummi 18-32 mm kalde rør | Nivå D | BI10T - Cellegummi 18-32 mm kalde rør | 721 | 0.00364332 | 0.0017121 | 58 | 58 | RESULT | MagiCAD Pset_Pipe - SystemName: +TI=350.001 R-1; SystemType: KJØLMEDIE R; NationalCode: UB1.111713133; User Code: Cu; SystemClass: Hydronic Return; Material: Kobberrør
BI11T - Rørskål m/Al.folie - varme 60-25 | Nivå D + 1,2 m | BI11T - Rørskål m/Al.folie - varme 60-25 | 9790 | 0.0895939 | 0.0795626 | 104 | 104 | RESULT | MagiCAD Pset_Pipe - SystemName: +TI=320.001 T; SystemType: VARME T; NationalCode: UB3.144613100; User Code: DN; SystemClass: Hydronic Supply; Material: Stålrør normaltykke
B-EI60 | Nivå F | EI60 Brannisolasjon 30 mm | 538 | 0.0323507 | 0.0174125 | 376 | 376 | RESULT | MagiCAD Pset_Duct - Description: Spiro kanaler, Forsinket stål; UserCode: Circ
BI11T - Rørskål m/Al.folie - varme 60-25 | Nivå D | BI11T - Rørskål m/Al.folie - varme 60-25 | 6277 | 0.0656572 | 0.0627911 | 120 | 120 | RESULT | MagiCAD Pset_Pipe - SystemName: +TI=322.004 T; SystemType: SHUNTET VARME T; NationalCode: UB3.144613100; User Code: DN; SystemClass: Hydronic Supply; Material: Stålrør normaltykke
BI11T - Rørskål m/Al.folie - varme 60-25 | Nivå D | BI11T - Rørskål m/Al.folie - varme 60-25 | 10704 | 0.111954 | 0.107067 | 120 | 120 | RESULT | MagiCAD Pset_Pipe - SystemName: +TI=322.004 R; SystemType: SHUNTET VARME R; NationalCode: UB3.144613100; User Code: DN; SystemClass: Hydronic Return; Material: Stålrør normaltykke
BI15T - Cellegummi KV 15mm | Nivå D | BI15T - Cellegummi KV 15mm | 434 | 0.00321631 | 0.00139572 | 70 | 70 | RESULT | MagiCAD Pset_Pipe - SystemName: +TI=310.101-1; SystemType: KV; NationalCode: UB1.111713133; User Code: Cu; SystemClass: Domestic Cold Water; Material: Kobberrør
BI16T - Rørskål m/Al.folie - VV 40mm | Nivå D | BI16T - Rørskål m/Al.folie - VV 40mm | 629 | 0.00450096 | 0.00283025 | 78 | 78 | RESULT | MagiCAD Pset_Pipe - SystemName: +TI=310.201-1; SystemType: VV; NationalCode: UB1.111713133; User Code: Cu; SystemClass: Domestic Hot Water; Material: Kobberrør
BI10T - Cellegummi 18-32 mm kalde rør | Nivå D | BI10T - Cellegummi 18-32 mm kalde rør | 653 | 0.0045497 | 0.00274118 | 80 | 80 | RESULT | MagiCAD Pset_Pipe - SystemName: +TI=370.001 R; SystemType: KJØL R; NationalCode: UB3.144613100; User Code: DN; SystemClass: Hydronic Return; Material: Stålrør normaltykke
BI10T - Cellegummi 18-32 mm kalde rør | Nivå D | BI10T - Cellegummi 18-32 mm kalde rør | 653 | 0.00454967 | 0.00274117 | 80 | 80 | RESULT | MagiCAD Pset_Pipe - SystemName: +TI=370.001 T; SystemType: KJØL T; NationalCode: UB3.144613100; User Code: DN; SystemClass: Hydronic Supply; Material: Stålrør normaltykke
BI15T - Cellegummi KV 15mm | Nivå D | BI15T - Cellegummi KV 15mm | 9985 | 0.0609216 | 0.0321168 | 70 | 70 | RESULT | MagiCAD Pset_Pipe - SystemName: +TI=310.101-1; SystemType: KV; NationalCode: UB1.111713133; User Code: Cu; SystemClass: Domestic Cold Water; Material: Kobberrør

# IfcCovering: Compound Ceiling:A255 - HI-G03 (2)
In: Nivå D
Type - PredefinedType: CEILING
Type - Pset_CoveringCommon - TotalThickness: 30 mm
ePset_LocationTool - Splitting: RESULT
ePset_SimplebimBasicQuantities - Height (Simplebim): 30 mm
ePset_Simplebim - Assembly Level: Leaf
AVINOR - 03_Ansvar: 72253; 08_Status: S4; 07_Fase: F90; 06_Omrade: TI; 05_ID-nummer: +TI=255.001-ID0005; 02_Prosjekt: T20100; 01_Lufthavnkode: ENGM
Pset_CoveringCommon - Reference: A255 - HI-G03; sets with these values: 2
Name (Compound Ceiling:A255 - HI-G03:...) | Area, largest surface, net (Simplebim) (m2) | Volume, net (Simplebim) (m3) | Width (Simplebim) (mm) | Length (Simplebim) (mm)
3403036 | 4.1565 | 0.143154 | 1025 | 9600
3402959 | 87.84 | 2.6352 | 8100 | 12000

# IfcCurtainWall: Curtain Wall:A242 - IGV - Glass - 10 mm, Curtain Wall:A242 - IGV - Glass - 10 mm:66368416
In: Nivå F
Pset_CurtainWallCommon - IsExternal: no; Reference: A242 - IGV - Glass - 10 mm
Pset_QuantityTakeOff - Reference: A242 - IGV - Glass - 10 mm
AVINOR - 08_Status: S4; 07_Fase: F90; 06_Omrade: TI; 03_Ansvar: 72717; 02_Prosjekt: T20100; 05_ID-nummer: +TI=245.039; 01_Lufthavnkode: ENGM
ePset_Simplebim - Assembly Level: Topmost
ePset_SimplebimBasicQuantities - Volume, net (Simplebim): 0.00878669 m3; Length: 713.138 mm; Width: 10 mm; Height: 2300 mm

# IfcCurtainWall: Curtain Wall:A245 - IGK - Glass Kledning, Curtain Wall:A245 - IGK - Glass Kledning:58696939
In: Nivå F
Pset_QuantityTakeOff - Reference: A245 - IGK - Glass Kledning
Pset_CurtainWallCommon - Reference: A245 - IGK - Glass Kledning; IsExternal: no
AVINOR - 03_Ansvar: 72253; 08_Status: S4; 07_Fase: F90; 05_ID-nummer: +TI=245.002; 06_Omrade: TI; 02_Prosjekt: T20100; 01_Lufthavnkode: ENGM
ePset_Simplebim - Assembly Level: Topmost
ePset_SimplebimBasicQuantities - Height: 2986 mm; Length: 823.003 mm; Volume, net (Simplebim): 0.0246572 m3; Width: 20 mm

# IfcCurtainWall: Curtain Wall:A245 - IMK - Metal Kledning (12)
In: Nivå F
Pset_QuantityTakeOff - Reference: A245 - IMK - Metal Kledning
AVINOR - 08_Status: S4; 07_Fase: F90; 06_Omrade: TI; 02_Prosjekt: T20100; 01_Lufthavnkode: ENGM
Pset_CurtainWallCommon - IsExternal: no; Reference: A245 - IMK - Metal Kledning
ePset_Simplebim - Assembly Level: Topmost
Name (Curtain Wall:A245 - IMK - Metal Kledning:...) | 03_Ansvar | 05_ID-nummer | Height (mm) | Volume, net (Simplebim) (m3) | Width (mm) | Length (mm)
15186954 | 72253 | +TI=245.003 | 9850 | 0.109718 | 20 | 3418
21289026 | 72253 | +TI=245.003 | 6000 | 0.0257541 | 20 | 7318
27491891 | 72253 | +TI=245.003 | 9850 | 0.234908 | 20 | 7318
44968983 | 72253 | +TI=245.003 | 4640 | 0.114326 | 20 | 7162.75
44969053 | 72253 | +TI=245.003 | 4490 | 0.226079 | 30 | 7162.44
44969057 | 72253 | +TI=245.003 | 4490 | 0.133938 | 30 | 3180
58847891 | 72253 | +TI=245.003 | 500 | 0.28785 | 60 | 9594.99
59292838 | 72253 | +TI=245.003 | 500 | 0.07605 | 60 | 2535
62371177 | 72253 | +TI=245.003 | 140 | 0.0200528 | 37 | 7161.7
62371495 | 72253 | +TI=245.003 | 150 | 0.00954413 | 20 | 3181.38
67003903 | 72717 | +TI=245.015 | 2986 | 0.0031353 | 3 | 350
68555852 | 72253 | +TI=245.003 | 500 | 0.00627 | 60 | 209

# IfcDistributionControlElement: Brann Spjeld (2)
In: Nivå F
Type - Description: BrannSpjeld
Classification: XN1.31 Not defined (NS3420); Group: Brannspjeld
MagiCAD Pset_Device - User code: -DI; System code: 542-DI; Length [mm]: 0 mm; Height [mm]: 0 mm; Width [mm]: 0 mm; Manufacturer: General; National code: XN1.31
ePset_Simplebim - Assembly Level: Leaf
ePset_LocationTool - Splitting: ORIGINAL

# IfcDistributionControlElement: Brannalarm Røykdetektor (3)
Type - Description: Brannalarm Røykdetektor
Classification: XJ1.1115 Not defined (NS3420); Group: Brannalarm
ePset_Simplebim - Assembly Level: Leaf
ePset_LocationTool - Splitting: ORIGINAL
MagiCAD Pset_Device - System code: 542; User code: -TY; Host: +TI=542.302; National code: XJ1.1115; IP_Code: IP20; P1: -RY; Length [mm]: 0 mm; Product code: Smoke detector 2; Manufacturer: General; Height [mm]: 45 mm; Width [mm]: 100 mm
Pset_ElectricalDeviceCommon - IP_Code: IP20
Name | In | Circuit order no | Installation Code
2 x Brannalarm Røykdetektor | Nivå F | 18 | 3
Brannalarm Røykdetektor | Nivå D + 1,2 m | 21 | 2

# IfcDistributionControlElement: CONTROL UNIT
In: Nivå F
Type - Description: Nødåpner KAC
ePset_Simplebim - Assembly Level: Leaf
MagiCAD Pset_Device - System code: 543; IP_Code: IP20; Product code: CONTROL UNIT; P1: -XS; Length [mm]: 0 mm; Manufacturer: General; Width [mm]: 58 mm; Height [mm]: 122 mm
ePset_LocationTool - Splitting: ORIGINAL
Pset_ElectricalDeviceCommon - IP_Code: IP20
Group: Adgangskontroll, Innbruddsalarm

# IfcDistributionControlElement: SECURITY ALARM 3 (3)
In: Nivå F
Type - Description: Kortleser med tastatur
ePset_LocationTool - Splitting: ORIGINAL
Pset_ElectricalDeviceCommon - IP_Code: IP44
ePset_Simplebim - Assembly Level: Leaf
MagiCAD Pset_Device - System code: 543; Product code: Security alarm 3; P1: -QP; Length [mm]: 0 mm; Manufacturer: General; Width [mm]: 25 mm; Height [mm]: 140 mm; IP_Code: IP44
Group: Adgangskontroll, Innbruddsalarm

# IfcDistributionControlElement: Standard (8)
In: Nivå F
Type - Description: Brannalarm Multikriteriedetektor OT Blue
ePset_Simplebim - Assembly Level: Leaf
MagiCAD Pset_Device - System code: 542; Length [mm]: 0 mm; Height [mm]: 0 mm; Width [mm]: 0 mm
ePset_LocationTool - Splitting: ORIGINAL
Group: Brannalarm
Name | Description | User code | Host | Circuit order no | Installation Code
2 x Standard | Brannalarm Multikriteriedetektor | -TY | +TI=542.302 | 18 | 2 | Classification: XJ1.1115 Not defined (NS3420); MagiCAD Pset_Device - P1: -TY; National code: XJ1.1115; Manufacturer: General
3 x Standard | Brannalarm Røykdetektor over himling | -TY | +TI=542.302 | 18 | 2
Standard | Brannalarm Varmedetektor | TY | +TI=542.302 | 18 | Classification: XJ1.1117 Not defined (NS3420); MagiCAD Pset_Device - P1: -RY; National code: XJ1.1117; Manufacturer: General
Standard | Brannalarm Dørholdemagnet |  | +TI=542.302 | 38 | Classification: XJ4.1 Not defined (NS3420); MagiCAD Pset_Device - P1: -QZ; National code: XJ4.1; Manufacturer: General; IP_Code: IP54; Pset_ElectricalDeviceCommon - IP_Code: IP54
Standard |  | -TY |  |  | 3

# IfcDistributionControlElement: Switch with one push button (3)
In: Nivå F
Type - Description: Åpneknapp
MagiCAD Pset_Device - Product code: Switch with one push button; System code: 543; P1: -QG; Length [mm]: 0 mm; Manufacturer: General; Width [mm]: 10 mm; Height [mm]: 60 mm; IP_Code: IP21
ePset_Simplebim - Assembly Level: Leaf
Pset_ElectricalDeviceCommon - IP_Code: IP21
ePset_LocationTool - Splitting: ORIGINAL
Group: Adgangskontroll, Innbruddsalarm

# IfcDoor: A20 - Slagdør - Enkel:A243 - DI_LTO - 1190 x 2240 mm, A20 - Slagdør - Enkel:A243 - DI_LTO - 1190 x 2240 mm:52785398
In: Nivå F
Type - OperationType: SINGLE_SWING_LEFT; ParameterTakesPrecedence: no; Sizeable: no; Material: N_Door - Handle, _NSW Stål - rustfritt, _NSW Dør - karm, hvit, N_Door - Threshold, N_Door - Panel
Type - IfcDoorPanelProperties - PanelOperation: SWINGING
OverallHeight: 2257.5 mm; OverallWidth: 1204.99 mm
ePset_Simplebim - Assembly Level: Leaf
ePset_LocationTool - Splitting: ORIGINAL
ePset_SimplebimBasicQuantities - Area, opening (Simplebim): 2.72027 m2; Height, opening (Simplebim): 2257.5 mm; Width, opening (Simplebim): 1204.99 mm; Width (Simplebim): 1190 mm; Height (Simplebim): 2240 mm; Length, frame (Simplebim): 5670 mm; Area (Simplebim): 2.6656 m2
Pset_QuantityTakeOff - Reference: A243 - DI_LTO - 1190 x 2240 mm
Pset_DoorCommon - IsExternal: no; Reference: A243 - DI_LTO - 1190 x 2240 mm; SecurityRating: DK03
AVINOR - 08_Status: S4; 07_Fase: F90; 05_ID-nummer: +TI=243.001-IP0115; 06_Omrade: TI; 02_Prosjekt: T20100; 03_Ansvar: 72231; 01_Lufthavnkode: ENGM

# IfcDoor: A233 - Rulleport:A233 - RI_AAO - 1910 x 2500, A233 - Rulleport:A233 - RI_AAO - 1910 x 2500:61156322
In: Nivå F
Type - ParameterTakesPrecedence: no; Sizeable: no; Material: NO_Aluminium
OverallHeight: 2500 mm; OverallWidth: 1910 mm
ePset_SimplebimBasicQuantities - Area (Simplebim): 4.7 m2; Area, opening (Simplebim): 4.775 m2; Width (Simplebim): 1880 mm; Width, opening (Simplebim): 1910 mm; Height, opening (Simplebim): 2500 mm; Height (Simplebim): 2500 mm; Length, frame (Simplebim): 6880 mm
ePset_Simplebim - Assembly Level: Leaf
ePset_LocationTool - Splitting: ORIGINAL
Pset_DoorCommon - Reference: A233 - RI_AAO - 1910 x 2500; IsExternal: yes
Pset_QuantityTakeOff - Reference: A233 - RI_AAO - 1910 x 2500
AVINOR - 05_ID-nummer: +TI=243.001-IR0015; 08_Status: S4; 07_Fase: F90; 06_Omrade: TI; 03_Ansvar: 72717; 02_Prosjekt: T20100; 01_Lufthavnkode: ENGM

# IfcDoor: A233 - Rulleport:A233 - RI_AAO - 4610 x 2500 (2)
In: Nivå F
Type - ParameterTakesPrecedence: no; Sizeable: no; Material: NO_Aluminium
OverallHeight: 2500 mm; OverallWidth: 4610 mm
AVINOR - 08_Status: S4; 07_Fase: F90; 06_Omrade: TI; 03_Ansvar: 72717; 02_Prosjekt: T20100; 01_Lufthavnkode: ENGM
ePset_Simplebim - Assembly Level: Leaf
ePset_LocationTool - Splitting: ORIGINAL
Pset_QuantityTakeOff - Reference: A233 - RI_AAO - 4610 x 2500
Pset_DoorCommon - Reference: A233 - RI_AAO - 4610 x 2500; IsExternal: yes
ePset_SimplebimBasicQuantities - Area, opening (Simplebim): 11.525 m2; Area (Simplebim): 11.45 m2; Height, opening (Simplebim): 2500 mm; Height (Simplebim): 2500 mm; Width, opening (Simplebim): 4610 mm; Width (Simplebim): 4580 mm; Length, frame (Simplebim): 9580 mm
Name (A233 - Rulleport:A233 - RI_AAO - 4610 x 2500:...) | 05_ID-nummer
61156258 | +TI=243.001-IR0017
61156313 | +TI=243.001-IR0018

# IfcElectricalCircuit (7)
Name | Description
Belysningsutstyr | 442
Kursopplegg for underfordelinger | 4332
KNX Bryter | 561
Utstyr for nødlys | 443
Utstyr for virksomhet | 561
Røyklukesentral | 542
Adgangskontroll, Innbruddsalarm | 543

# IfcEnergyConversionDevice: GCS1.UWW.K01
In: Nivå F
Type - Description: Casette fancoil; PredefinedType: WATERHEATINGCOIL
MagiCAD Pset_FanCoilUnit - Description: Casette fancoil; qv_SizingFlow_ls: 0 m3/s; dpTot_SizingFlow_Pa: 0 Pa; qv_SizingFlow_ms: 0 m/s; ProductCode: GCS1.UWW.K01; User Code: Fancoil; Manufacturer: GEA
ePset_LocationTool - Splitting: ORIGINAL
ePset_Simplebim - Assembly Level: Leaf
Group: 32= R 50° Kopi 1; 32= T 60° Kopi 4

# IfcFlowController, El. ford. stativ
In: Nivå F
Description: El. ford. stativ; Group: Røyklukesentral
Pset_ElectricalDeviceCommon - NumberOfPoles: 1; NominalVoltage: 420; ElectricalDeviceNominalPower: 15000 W
ePset_Simplebim - Assembly Level: Leaf
ePset_LocationTool - Splitting: ORIGINAL
MagiCAD Pset_Switchboard - System code: 542; Switchboard code: +TI=542.955; Circuit order no: <unnamed>; User code: 02; Number of Poles: 1; Voltage: 420; Active Power: 15000 W; Power Factor: 0.95

# IfcFlowController: 322G-3910-40
In: Nivå D
Type - Description: Magnetventil
MagiCAD Pset_Valve - Manufacturer: Axel Larsson; Description: Magnetventil; qv_SizingFlow_ls: 0 m3/s; pTot_SizingFlow_kPa: 0 Pa; dpTot_SizingFlow_kPa: 0 Pa; Product Code: 322G-3910-40; User Code: MV04; Insulation_thickness_mm: 40 mm
ePset_Simplebim - Assembly Level: Leaf
MagiCAD Pset_FireDamper - Manufacturer: Axel Larsson; Description: Magnetventil; qv_SizingFlow_ls: 0 m3/s; pTot_SizingFlow_Pa: 0 Pa; dpTot_SizingFlow_Pa: 0 Pa; v_SizingFlow_ms: 0 m/s; Product Code: 322G-3910-40; User Code: MV04; sets with these values: 2
ePset_LocationTool - Splitting: ORIGINAL
MagiCAD Pset_Silencer - Manufacturer: Axel Larsson; Description: Magnetventil; qv_SizingFlow_ls: 0 m3/s; pTot_SizingFlow_Pa: 0 Pa; dpTot_SizingFlow_Pa: 0 Pa; ProductCode: 322G-3910-40; User Code: MV04
Group: +TI=322.004 R

# IfcFlowController: AT-3600-25 (2)
In: Nivå D
Type - Description: Ball valve, threaded, brass
ePset_Simplebim - Assembly Level: Leaf
MagiCAD Pset_Valve - Description: Ball valve, threaded, brass; qv_SizingFlow_ls: 0 m3/s; pTot_SizingFlow_kPa: 0 Pa; dpTot_SizingFlow_kPa: 0 Pa; Manufacturer: Armatec; Product Code: AT3600-25; User Code: SM01T
ePset_LocationTool - Splitting: ORIGINAL
Name | Insulation_thickness_mm (mm) | Group
AT-3600-25 | 21 | +TI=310.101-1
AT-3600-25 | 30 | +TI=310.201-1

# IfcFlowController: AT-3600-32 (2)
In: Nivå D
Type - Description: Ball valve, threaded, brass
ePset_Simplebim - Assembly Level: Leaf
MagiCAD Pset_Valve - Product Code: AT3600-32; Description: Ball valve, threaded, brass; qv_SizingFlow_ls: 0 m3/s; pTot_SizingFlow_kPa: 0 Pa; dpTot_SizingFlow_kPa: 0 Pa; Manufacturer: Armatec; User Code: SM01T; Insulation_thickness_mm: 24 mm
ePset_LocationTool - Splitting: ORIGINAL
Name | Group
AT-3600-32 | +TI=370.001 R
AT-3600-32 | +TI=370.001 T

# IfcFlowController: AT3601-20
In: Nivå F
Type - Description: Ball valve, threaded, brass, long neck
Classification: UL1.4091 Not defined (NS3420)
ePset_Simplebim - Assembly Level: Leaf
MagiCAD Pset_Valve - Product Code: AT3601-20; Description: Ball valve, threaded, brass, long neck; qv_SizingFlow_ls: 0 m3/s; pTot_SizingFlow_kPa: 0 Pa; dpTot_SizingFlow_kPa: 0 Pa; Manufacturer: Armatec; NationalCode: UL1.4091; Insulation_thickness_mm: 21 mm; User Code: SM02T
ePset_LocationTool - Splitting: ORIGINAL

# IfcFlowController: AT3601-25 (2)
In: Nivå D
Type - Description: Ball valve, threaded, brass, long neck
Classification: UL1.4091 Not defined (NS3420)
ePset_Simplebim - Assembly Level: Leaf
ePset_LocationTool - Splitting: ORIGINAL
MagiCAD Pset_Valve - Product Code: AT3601-25; Description: Ball valve, threaded, brass, long neck; qv_SizingFlow_ls: 0 m3/s; pTot_SizingFlow_kPa: 0 Pa; dpTot_SizingFlow_kPa: 0 Pa; Manufacturer: Armatec; NationalCode: UL1.4091; Insulation_thickness_mm: 30 mm; User Code: SM02T
Name | Group
AT3601-25 | +TI=323.002 R-1
AT3601-25 | 32= T 55° Kopi 1

# IfcFlowController: AT3601-40
In: Nivå D
Type - Description: Ball valve, threaded, brass, long neck
Classification: UL1.4091 Not defined (NS3420); Group: +TI=322.004 T
ePset_Simplebim - Assembly Level: Leaf
MagiCAD Pset_Valve - Description: Ball valve, threaded, brass, long neck; Product Code: AT3601-40; qv_SizingFlow_ls: 0 m3/s; pTot_SizingFlow_kPa: 0 Pa; dpTot_SizingFlow_kPa: 0 Pa; Manufacturer: Armatec; NationalCode: UL1.4091; Insulation_thickness_mm: 40 mm; User Code: SM02T
ePset_LocationTool - Splitting: ORIGINAL

# IfcFlowController: Bryter KNX (2)
In: Nivå F
Type - Description: Vippebryter KNX
Classification: WL1.311 Not defined (NS3420); Group: KNX Bryter
Pset_ElectricalDeviceCommon - ElectricalDeviceNominalPower: 0 W; NumberOfPoles: 1; NominalVoltage: 230; IP_Code: IP21
ePset_LocationTool - Splitting: ORIGINAL
MagiCAD Pset_Device - National code: WL1.311; User code: B28; P1: -XS; Length [mm]: 0 mm; Number of Poles: 1; Active Power: 0 W; Product code: Switch - 2 buttons; Manufacturer: General; Power Factor: 1; Width [mm]: 30 mm; Height [mm]: 70 mm; Voltage: 230; System code: 561; IP_Code: IP21
ePset_Simplebim - Assembly Level: Leaf

# IfcFlowController: CR2-400
In: Nivå D
Type - Description: Circular fire damper; PredefinedType: FIREDAMPER
MagiCAD Pset_FireDamper - Manufacturer: RF-Technologies; qv_SizingFlow_ls: 0 m3/s; pTot_SizingFlow_Pa: 0 Pa; dpTot_SizingFlow_Pa: 0 Pa; v_SizingFlow_ms: 0 m/s; ConnectionSize_mm: 400; Description: Circular fire damper; Product Code: CR2-400; User Code: DIEI60/120 Ø400
ePset_Simplebim - Assembly Level: Leaf
ePset_LocationTool - Splitting: ORIGINAL
Group: 36= T Kopi 13

# IfcFlowController: CR60-250
In: Nivå F
Type - Description: Circular fire damper; PredefinedType: FIREDAMPER
ePset_LocationTool - Splitting: ORIGINAL
MagiCAD Pset_FireDamper - Manufacturer: RF-Technologies; qv_SizingFlow_ls: 0 m3/s; pTot_SizingFlow_Pa: 0 Pa; dpTot_SizingFlow_Pa: 0 Pa; v_SizingFlow_ms: 0 m/s; ConnectionSize_mm: 250; Description: Circular fire damper; User Code: DI-EI60/120 Ø315; Product Code: CR60-250
ePset_Simplebim - Assembly Level: Leaf
Group: 36= A Kopi 20

# IfcFlowController: FM-25 (2)
In: Nivå D
Type - Description: Flow meter; PredefinedType: FLOWMETER
ePset_LocationTool - Splitting: ORIGINAL
ePset_Simplebim - Assembly Level: Leaf
MagiCAD Pset_PipeComponent - User Code: RF11T; ConnectionSize_mm: 0 mm; qv_SizingFlow_ls: 0 m3/s; pTot_SizingFlow_Pa: 0 Pa; dpTot_SizingFlow_kPa: 0 Pa; Manufacturer: General; Description: Flow meter; Product Code: FM-25
Name | Group
FM-25 | +TI=310.101-1
FM-25 | +TI=310.201-1

# IfcFlowController: IRIS-250
In: Nivå F
Type - Description: Balancing damper; PredefinedType: BALANCINGDAMPER
Classification: VE5.142012 Not defined (NS3420); Group: 36= A Kopi 20
MagiCAD Pset_FlowDamper - Description: Balancing damper; Product Code: IRIS-250; qv_SizingFlow_ls: 0 m3/s; pTot_SizingFlow_Pa: 0 Pa; dpTot_SizingFlow_Pa: 0 Pa; v_SizingFlow_ms: 0 m/s; NationalCode: VE5.142012; ConnectionSize_mm: 250; Manufacturer: Oeland; User Code: SR01T
ePset_LocationTool - Splitting: ORIGINAL
ePset_Simplebim - Assembly Level: Leaf

# IfcFlowController: IRIS-315
In: Nivå F
Type - PredefinedType: BALANCINGDAMPER
Description: Balancing damper; Classification: VE5.142012 Not defined (NS3420); Group: +TI=360.051 A
ePset_LocationTool - Splitting: ORIGINAL
ePset_Simplebim - Assembly Level: Leaf
MagiCAD Pset_FlowDamper - ConnectionSize_mm: 315; Description: Balancing damper; qv_SizingFlow_ls: 0 m3/s; pTot_SizingFlow_Pa: 0 Pa; dpTot_SizingFlow_Pa: 0 Pa; v_SizingFlow_ms: 0 m/s; NationalCode: VE5.142012; Product Code: IRIS-315; Manufacturer: Oeland; User Code: SR01T

# IfcFlowController: STAD/F-10/09
In: Nivå D
Type - Description: Presetting of flow, shut-off valve, flow measuring,pressure reading 10-50
Classification: UL5.11091 Not defined (NS3420); Group: +TI=322.004 R
ePset_LocationTool - Splitting: ORIGINAL
ePset_Simplebim - Assembly Level: Leaf
MagiCAD Pset_Valve - Manufacturer: TA; qv_SizingFlow_ls: 0 m3/s; pTot_SizingFlow_kPa: 0 Pa; dpTot_SizingFlow_kPa: 0 Pa; Description: Presetting of flow, shut-off valve, flow measuring,pressure reading 10-50; NationalCode: UL5.11091; Insulation_thickness_mm: 20 mm; User Code: SV01T; Product Code: STAD/F-10/09

# IfcFlowController: STAD/F-20
In: Nivå F
Type - Description: Presetting of flow, shut-off valve, flow measuring,pressure reading 10-50
Classification: UL5.11091 Not defined (NS3420)
MagiCAD Pset_Valve - Manufacturer: TA; qv_SizingFlow_ls: 0 m3/s; pTot_SizingFlow_kPa: 0 Pa; dpTot_SizingFlow_kPa: 0 Pa; Description: Presetting of flow, shut-off valve, flow measuring,pressure reading 10-50; NationalCode: UL5.11091; Product Code: STAD/F-20; Insulation_thickness_mm: 21 mm; User Code: SV01T
ePset_LocationTool - Splitting: ORIGINAL
ePset_Simplebim - Assembly Level: Leaf

# IfcFlowController: STAD/F-40
In: Nivå D
Type - Description: Presetting of flow, shut-off valve, flow measuring,pressure reading 10-50
Classification: UL5.11091 Not defined (NS3420); Group: +TI=322.004 R
MagiCAD Pset_Valve - Manufacturer: TA; qv_SizingFlow_ls: 0 m3/s; pTot_SizingFlow_kPa: 0 Pa; dpTot_SizingFlow_kPa: 0 Pa; Description: Presetting of flow, shut-off valve, flow measuring,pressure reading 10-50; NationalCode: UL5.11091; Insulation_thickness_mm: 40 mm; User Code: SV01T; Product Code: STAD/F-40
ePset_LocationTool - Splitting: ORIGINAL
ePset_Simplebim - Assembly Level: Leaf

# IfcFlowController: V5011R1059+ML6425A
In: Nivå F
Type - Description: Two-way control valve PN16, threaded, with 600N motor
MagiCAD Pset_FireDamper - Description: Two-way control valve PN16, threaded, with 600N motor; Manufacturer: Honeywell; qv_SizingFlow_ls: 0 m3/s; pTot_SizingFlow_Pa: 0 Pa; dpTot_SizingFlow_Pa: 0 Pa; v_SizingFlow_ms: 0 m/s; Product Code: V5011R1059+ML6425A; User Code: MV01; sets with these values: 2
MagiCAD Pset_Silencer - Description: Two-way control valve PN16, threaded, with 600N motor; Manufacturer: Honeywell; qv_SizingFlow_ls: 0 m3/s; pTot_SizingFlow_Pa: 0 Pa; dpTot_SizingFlow_Pa: 0 Pa; ProductCode: V5011R1059+ML6425A; User Code: MV01
ePset_Simplebim - Assembly Level: Leaf
ePset_LocationTool - Splitting: ORIGINAL
MagiCAD Pset_Valve - Description: Two-way control valve PN16, threaded, with 600N motor; Manufacturer: Honeywell; qv_SizingFlow_ls: 0 m3/s; pTot_SizingFlow_kPa: 0 Pa; dpTot_SizingFlow_kPa: 0 Pa; Product Code: V5011R1059+ML6425A; Insulation_thickness_mm: 21 mm; User Code: MV01
Group: 37= R 18° Kopi 1

# IfcFlowFitting: Junction box round1 (3)
In: Nivå F
Type - Description: Koblingsboks åpen tele-data
MagiCAD Pset_Device - System code: 543; Length [mm]: 0 mm; Width [mm]: 0 mm; Height [mm]: 0 mm; Product code: Junction box round1; Manufacturer: General
ePset_LocationTool - Splitting: ORIGINAL
ePset_Simplebim - Assembly Level: Leaf
Group: Adgangskontroll, Innbruddsalarm

# IfcFlowFitting: Kabelrenne, bend vertikal (Inside) (2)
Type - PredefinedType: BEND
MagiCAD Pset_Cabletray - Width [mm]: 0 mm; Height [mm]: 0 mm; Length [mm]: 0 mm; System code: 501-B
ePset_LocationTool - Splitting: ORIGINAL
ePset_Simplebim - Assembly Level: Leaf
Group: STIGEKABEL-SEKUNDÆR
Name | In | O1
Kabelrenne, bend vertikal (Inside) | Nivå G + 1,2 m | TI04 - TI26
Kabelrenne, bend vertikal (Inside) | Nivå F | TI04 - TI16

# IfcFlowFitting: Koblingsboks skjult vegg
In: Nivå F
Type - Description: Koblingsboks skjult
Pset_ElectricalDeviceCommon - IP_Code: IP20; ElectricalDeviceNominalPower: 0 W; NumberOfPoles: 1; NominalVoltage: 230
ePset_Simplebim - Assembly Level: Leaf
ePset_LocationTool - Splitting: ORIGINAL
MagiCAD Pset_Device - Switchboard: +TI=433.625; Circuit order no: 49; User code: -QM; IP_Code: IP20; System code: 4332; Length [mm]: 0 mm; Number of Poles: 1; Active Power: 0 W; Manufacturer: General; Power Factor: 1; Width [mm]: 45 mm; Height [mm]: 71 mm; Voltage: 230
Group: Kursopplegg for underfordelinger

# IfcFlowFitting: Koblingsboks åpen (14)
Type - Description: Koblingsboks åpen
Pset_ElectricalDeviceCommon - IP_Code: IP20; ElectricalDeviceNominalPower: 0 W; NumberOfPoles: 1; NominalVoltage: 230
ePset_Simplebim - Assembly Level: Leaf
MagiCAD Pset_Device - User code: -QM; IP_Code: IP20; Length [mm]: 0 mm; Number of Poles: 1; Active Power: 0 W; Manufacturer: General; Power Factor: 1; Width [mm]: 46 mm; Height [mm]: 104 mm; Voltage: 230
ePset_LocationTool - Splitting: ORIGINAL
Name | In | Switchboard | Circuit order no | System code | Group
5 x Koblingsboks åpen | Nivå F | +TI=433.625 | 54 | 4332 | Kursopplegg for underfordelinger
Koblingsboks åpen | Nivå F | +TI=433.625 | 56 | 4332 | Kursopplegg for underfordelinger
Koblingsboks åpen | Nivå F | +TI=433.625 | 57 | 463 | Utstyr for virksomhet | MagiCAD Pset_Device - Installation Code: 4
2 x Koblingsboks åpen | Nivå F |  |  | 4332 | Kursopplegg for underfordelinger
Koblingsboks åpen | Nivå F |  |  | 463 | Utstyr for virksomhet | MagiCAD Pset_Device - Installation Code: 4
Koblingsboks åpen | Nivå D + 1,2 m | +TI=433.623 | 14 | 4332 | Kursopplegg for underfordelinger
Koblingsboks åpen | Nivå D + 1,2 m | +TI=433.623 | 13 | 4332 | Kursopplegg for underfordelinger
Koblingsboks åpen | Nivå D + 1,2 m | +TI=433.623 | 16 | 4332 | Kursopplegg for underfordelinger
Koblingsboks åpen | Nivå D + 1,2 m | +TI=433.623 | 15 | 4332 | Kursopplegg for underfordelinger

# IfcFlowFitting: Logiske føringsveier (bend)
In: Nivå F
Type - PredefinedType: BEND
ePset_Simplebim - Assembly Level: Leaf
ePset_LocationTool - Splitting: ORIGINAL
MagiCAD Pset_Cabletray - O1: TI04 - TI16; Width [mm]: 0 mm; Height [mm]: 0 mm; Length [mm]: 0 mm; System code: 501-B
Group: STIGEKABEL-SEKUNDÆR

# IfcFlowFitting: Trekkerør, glatt bend (100)
In: Nivå F
Type - PredefinedType: BEND
ePset_LocationTool - Splitting: ORIGINAL
ePset_Simplebim - Assembly Level: Leaf
MagiCAD Pset_Conduit - System code: 4110; Diameter [mm]: 0 mm; Length [mm]: 0 mm
Group: Trekkerør generelt

# IfcFlowFitting: XD - Binærinngang
In: Nivå F
Type - Description: Koblingsboks åpen
Pset_ElectricalDeviceCommon - ElectricalDeviceNominalPower: 0 W; NumberOfPoles: 1; NominalVoltage: 230
MagiCAD Pset_Device - User code: -QM; P1: -XK; Length [mm]: 0 mm; Number of Poles: 1; Active Power: 0 W; Width [mm]: 0 mm; Height [mm]: 0 mm; Installation Code: 4; Manufacturer: General; Power Factor: 1; Voltage: 230; System code: 561
ePset_LocationTool - Splitting: ORIGINAL
ePset_Simplebim - Assembly Level: Leaf
Group: Utstyr for virksomhet

# IfcFlowFitting: XD - KNX-DALI GATEWAY
In: Nivå F
Type - Description: Koblingsboks åpen
Pset_ElectricalDeviceCommon - ElectricalDeviceNominalPower: 0 W; NumberOfPoles: 1; NominalVoltage: 230
MagiCAD Pset_Device - User code: -QM; P1: -XD; Length [mm]: 0 mm; Number of Poles: 1; Active Power: 0 W; Width [mm]: 0 mm; Height [mm]: 0 mm; Installation Code: 4; Manufacturer: General; Power Factor: 1; Voltage: 230; System code: 561
ePset_LocationTool - Splitting: ORIGINAL
ePset_Simplebim - Assembly Level: Leaf
Group: Utstyr for virksomhet

# IfcFlowFitting: magi_pipe_cu_elbow_short_001 (27)
Type - PredefinedType: BEND
MagiCAD Pset_Elbow - qv_SizingFlow_ls: 0 m3/s; pTot_SizingFlow_Pa: 0 Pa; dpTot_SizingFlow_Pa: 0 Pa; v_SizingFlow_ms: 0 m/s; ConnectionSize_mm: 0 mm
ePset_Simplebim - Assembly Level: Leaf
ePset_LocationTool - Splitting: ORIGINAL
Name | In | Insulation_thickness_mm (mm) | Group
4 x magi_pipe_cu_elbow_short_001 | Nivå D | 30 | +TI=310.201-1
magi_pipe_cu_elbow_short_001 | Nivå D | 0 | +TI=310.101-1
4 x magi_pipe_cu_elbow_short_001 | Nivå D | 21 | +TI=310.101-1
2 x magi_pipe_cu_elbow_short_001 | Nivå D | 20 | +TI=310.101-1
7 x magi_pipe_cu_elbow_short_001 | Nivå D | 20 | +TI=350.001 R-1
7 x magi_pipe_cu_elbow_short_001 | Nivå D | 20 | +TI=350.001 T-1
magi_pipe_cu_elbow_short_001 | Nivå F | 20 | +TI=350.001 T-1
magi_pipe_cu_elbow_short_001 | Nivå F | 20 | +TI=350.001 R-1

# IfcFlowFitting: magi_pipe_cu_reducer_centric_short_001 (8)
In: Nivå D
Type - PredefinedType: TRANSITION
MagiCAD Pset_Reduction - qv_SizingFlow_ls: 0 m3/s; pTot_SizingFlow_Pa: 0 Pa; dpTot_SizingFlow_Pa: 0 Pa; v_SizingFlow_ms: 0 m/s; ConnectionSize_mm: 0 mm
ePset_Simplebim - Assembly Level: Leaf
ePset_LocationTool - Splitting: ORIGINAL
Name | Insulation_thickness_mm (mm) | Group
4 x magi_pipe_cu_reducer_centric_short_001 | 21 | +TI=310.101-1
2 x magi_pipe_cu_reducer_centric_short_001 | 40 | +TI=310.201-1
2 x magi_pipe_cu_reducer_centric_short_001 | 30 | +TI=310.201-1

# IfcFlowFitting: magi_pipe_cu_tee_centric_90_001 (2)
In: Nivå D
Type - PredefinedType: JUNCTION
MagiCAD Pset_TBranch - qv_SizingFlow_ls: 0 m3/s; pTot_SizingFlow_Pa: 0 Pa; dpTot_SizingFlow_Pa: 0 Pa; v_SizingFlow_ms: 0 m/s; ConnectionSize_mm: 0 mm; Insulation_thickness_mm: 21 mm
ePset_Simplebim - Assembly Level: Leaf
ePset_LocationTool - Splitting: ORIGINAL
Group: +TI=310.101-1

# IfcFlowFitting: magi_pipe_elbow_short_001 (2)
In: Nivå D
Type - PredefinedType: BEND
MagiCAD Pset_Elbow - Insulation_thickness_mm: 0 mm; qv_SizingFlow_ls: 0 m3/s; pTot_SizingFlow_Pa: 0 Pa; dpTot_SizingFlow_Pa: 0 Pa; v_SizingFlow_ms: 0 m/s; ConnectionSize_mm: 0 mm
ePset_Simplebim - Assembly Level: Leaf
ePset_LocationTool - Splitting: ORIGINAL
Group: 31= Spillvann 3

# IfcFlowFitting: magi_pipe_fe_elbow_short_001 (98)
Type - PredefinedType: BEND
MagiCAD Pset_Elbow - qv_SizingFlow_ls: 0 m3/s; pTot_SizingFlow_Pa: 0 Pa; dpTot_SizingFlow_Pa: 0 Pa; v_SizingFlow_ms: 0 m/s; ConnectionSize_mm: 0 mm
ePset_Simplebim - Assembly Level: Leaf
ePset_LocationTool - Splitting: ORIGINAL
Name | In | Insulation_thickness_mm (mm) | Group
3 x magi_pipe_fe_elbow_short_001 | Nivå C | 0 | +TI=330.003 B-1
magi_pipe_fe_elbow_short_001 | Nivå C + 2,7 m | 50 | +TI=322.004 R
3 x magi_pipe_fe_elbow_short_001 | Nivå D | 40 | +TI=322.004 T
2 x magi_pipe_fe_elbow_short_001 | Nivå D | 40 | +TI=322.004 R
magi_pipe_fe_elbow_short_001 | Nivå D | 50 | +TI=322.004 R
2 x magi_pipe_fe_elbow_short_001 | Nivå D | 50 | +TI=322.004 T
2 x magi_pipe_fe_elbow_short_001 | Nivå D | 30 | +TI=322.004 R
3 x magi_pipe_fe_elbow_short_001 | Nivå D | 40 | 32= T 55° Kopi 1
3 x magi_pipe_fe_elbow_short_001 | Nivå D | 40 | +TI=323.002 R-1
3 x magi_pipe_fe_elbow_short_001 | Nivå D | 0 | +TI=322.004 T
5 x magi_pipe_fe_elbow_short_001 | Nivå D | 21 | +TI=370.001 T
5 x magi_pipe_fe_elbow_short_001 | Nivå D | 21 | +TI=370.001 R
3 x magi_pipe_fe_elbow_short_001 | Nivå F | 21
3 x magi_pipe_fe_elbow_short_001 | Nivå F | 21 | 37= T 9° Kopi 1
5 x magi_pipe_fe_elbow_short_001 | Nivå F | 21 | 37= R 18° Kopi 1
magi_pipe_fe_elbow_short_001 | Nivå D + 1,2 m | 40 | +TI=320.001 T
44 x magi_pipe_fe_elbow_short_001 | Nivå F | 0 | +TI=332.001-NZ0003
5 x magi_pipe_fe_elbow_short_001 | Nivå D | 0 | +TI=332.001-NZ0005
3 x magi_pipe_fe_elbow_short_001 | Nivå D | 0 | +TI=332.001-NZ0006
magi_pipe_fe_elbow_short_001 | Nivå F -0,7 | 0 | +TI=332.001-NZ0003

# IfcFlowFitting: magi_pipe_fe_joint_001 (3)
In: Nivå F
Type - PredefinedType: CONNECTOR
MagiCAD Pset_Joint - qv_SizingFlow_ls: 0 m3/s; pTot_SizingFlow_Pa: 0 Pa; dpTot_SizingFlow_Pa: 0 Pa; v_SizingFlow_ms: 0 m/s; ConnectionSize_mm: 0 mm
ePset_Simplebim - Assembly Level: Leaf
ePset_LocationTool - Splitting: ORIGINAL
Name | Insulation_thickness_mm (mm) | Group
magi_pipe_fe_joint_001 | 21 | 37= T 9° Kopi 1
2 x magi_pipe_fe_joint_001 | 0 | +TI=332.001-NZ0003

# IfcFlowFitting: magi_pipe_fe_reducer_centric_short_NOR (49)
Type - PredefinedType: TRANSITION
ePset_Simplebim - Assembly Level: Leaf
ePset_LocationTool - Splitting: ORIGINAL
MagiCAD Pset_Reduction - qv_SizingFlow_ls: 0 m3/s; pTot_SizingFlow_Pa: 0 Pa; dpTot_SizingFlow_Pa: 0 Pa; v_SizingFlow_ms: 0 m/s; ConnectionSize_mm: 0 mm
Name | In | Insulation_thickness_mm (mm) | Group
magi_pipe_fe_reducer_centric_short_NOR | Nivå D | 50 | +TI=322.004 T
magi_pipe_fe_reducer_centric_short_NOR | Nivå D | 50 | +TI=322.004 R
magi_pipe_fe_reducer_centric_short_NOR | Nivå D | 30 | 32= T 55° Kopi 1
magi_pipe_fe_reducer_centric_short_NOR | Nivå D | 30 | +TI=323.002 R-1
magi_pipe_fe_reducer_centric_short_NOR | Nivå D | 24 | +TI=370.001 T
magi_pipe_fe_reducer_centric_short_NOR | Nivå D | 24 | +TI=370.001 R
35 x magi_pipe_fe_reducer_centric_short_NOR | Nivå F | 0 | +TI=332.001-NZ0003
5 x magi_pipe_fe_reducer_centric_short_NOR | Nivå D | 0 | +TI=332.001-NZ0006
2 x magi_pipe_fe_reducer_centric_short_NOR | Nivå D | 0 | +TI=332.001-NZ0005
magi_pipe_fe_reducer_centric_short_NOR | Nivå F -0,7 | 0 | +TI=332.001-NZ0003

# IfcFlowFitting: magi_pipe_fe_tee_centric_90_NOR (41)
Type - PredefinedType: JUNCTION
ePset_LocationTool - Splitting: ORIGINAL
MagiCAD Pset_TBranch - qv_SizingFlow_ls: 0 m3/s; pTot_SizingFlow_Pa: 0 Pa; dpTot_SizingFlow_Pa: 0 Pa; v_SizingFlow_ms: 0 m/s; ConnectionSize_mm: 0 mm
ePset_Simplebim - Assembly Level: Leaf
Name | In | Insulation_thickness_mm (mm) | Group
2 x magi_pipe_fe_tee_centric_90_NOR | Nivå D | 40 | +TI=322.004 R
magi_pipe_fe_tee_centric_90_NOR | Nivå D | 50 | +TI=322.004 T
magi_pipe_fe_tee_centric_90_NOR | Nivå D | 50 | +TI=322.004 R
24 x magi_pipe_fe_tee_centric_90_NOR | Nivå F | 0 | +TI=332.001-NZ0003
13 x magi_pipe_fe_tee_centric_90_NOR | Nivå D | 0 | +TI=332.001-NZ0006

# IfcFlowFitting: magi_pipe_pex_tee_centric_90_001 (18)
In: Nivå D
Type - PredefinedType: JUNCTION
MagiCAD Pset_TBranch - qv_SizingFlow_ls: 0 m3/s; pTot_SizingFlow_Pa: 0 Pa; dpTot_SizingFlow_Pa: 0 Pa; v_SizingFlow_ms: 0 m/s; ConnectionSize_mm: 0 mm; Insulation_thickness_mm: 0 mm
ePset_Simplebim - Assembly Level: Leaf
ePset_LocationTool - Splitting: ORIGINAL
Name | Group
9 x magi_pipe_pex_tee_centric_90_001 | +TI=323.002 R-1
9 x magi_pipe_pex_tee_centric_90_001 | 32= T 55° Kopi 1

# IfcFlowFitting: magi_sewer_bend_001 (15)
In: Nivå D
Type - PredefinedType: BEND
MagiCAD Pset_Elbow - Insulation_thickness_mm: 0 mm; qv_SizingFlow_ls: 0 m3/s; pTot_SizingFlow_Pa: 0 Pa; dpTot_SizingFlow_Pa: 0 Pa; v_SizingFlow_ms: 0 m/s; ConnectionSize_mm: 0 mm
ePset_LocationTool - Splitting: ORIGINAL
ePset_Simplebim - Assembly Level: Leaf
Name | Group
5 x magi_sewer_bend_001 | +TI=313.403
8 x magi_sewer_bend_001 | +TI=313.003
2 x magi_sewer_bend_001

# IfcFlowFitting: magi_sewer_endcap_001 (23)
Type - PredefinedType: OBSTRUCTION
ePset_Simplebim - Assembly Level: Leaf
MagiCAD Pset_Plug - Insulation_thickness_mm: 0 mm; ConnectionSize_mm: 0 mm; pTot_SizingFlow_kPa: 0 Pa
ePset_LocationTool - Splitting: ORIGINAL
Name | In | Group
10 x magi_sewer_endcap_001 | Nivå D | +TI=323.002 R-1
10 x magi_sewer_endcap_001 | Nivå D | 32= T 55° Kopi 1
magi_sewer_endcap_001 | Nivå F | +TI=332.001-NZ0003
magi_sewer_endcap_001 | Nivå D | +TI=332.001-NZ0005
magi_sewer_endcap_001 | Nivå D | +TI=332.001-NZ0006

# IfcFlowFitting: magi_sewer_tee_wye_001
In: Nivå D
Type - PredefinedType: JUNCTION
MagiCAD Pset_TBranch - qv_SizingFlow_ls: 0 m3/s; pTot_SizingFlow_Pa: 0 Pa; dpTot_SizingFlow_Pa: 0 Pa; v_SizingFlow_ms: 0 m/s; ConnectionSize_mm: 0 mm; Insulation_thickness_mm: 0 mm
ePset_Simplebim - Assembly Level: Leaf
ePset_LocationTool - Splitting: ORIGINAL
Group: +TI=313.403

# IfcFlowFitting: magi_sewer_tee_wye_NOR (4)
In: Nivå D
Type - PredefinedType: JUNCTION
MagiCAD Pset_TBranch - qv_SizingFlow_ls: 0 m3/s; pTot_SizingFlow_Pa: 0 Pa; dpTot_SizingFlow_Pa: 0 Pa; v_SizingFlow_ms: 0 m/s; ConnectionSize_mm: 0 mm; Insulation_thickness_mm: 0 mm
ePset_Simplebim - Assembly Level: Leaf
ePset_LocationTool - Splitting: ORIGINAL
Name | Group
3 x magi_sewer_tee_wye_NOR | +TI=313.003
magi_sewer_tee_wye_NOR | 31= Spillvann 3

# IfcFlowFitting: magi_sewer_transition_001 (2)
In: Nivå D
Type - PredefinedType: TRANSITION
MagiCAD Pset_Reduction - qv_SizingFlow_ls: 0 m3/s; pTot_SizingFlow_Pa: 0 Pa; dpTot_SizingFlow_Pa: 0 Pa; v_SizingFlow_ms: 0 m/s; ConnectionSize_mm: 0 mm; Insulation_thickness_mm: 0 mm
ePset_Simplebim - Assembly Level: Leaf
ePset_LocationTool - Splitting: ORIGINAL
Name
magi_sewer_transition_001 | Group: +TI=313.003
magi_sewer_transition_001

# IfcFlowFitting: magi_sewer_union_001
In: Nivå D
Type - PredefinedType: CONNECTOR
MagiCAD Pset_Joint - Insulation_thickness_mm: 0 mm; qv_SizingFlow_ls: 0 m3/s; pTot_SizingFlow_Pa: 0 Pa; dpTot_SizingFlow_Pa: 0 Pa; v_SizingFlow_ms: 0 m/s; ConnectionSize_mm: 0 mm
ePset_LocationTool - Splitting: ORIGINAL
ePset_Simplebim - Assembly Level: Leaf
Group: +TI=313.003

# IfcFlowFitting: magicirc_elbow_full_radius_001 (17)
In: Nivå F
Type - PredefinedType: BEND
MagiCAD Pset_Elbow - qv_SizingFlow_ls: 0 m3/s; pTot_SizingFlow_Pa: 0 Pa; dpTot_SizingFlow_Pa: 0 Pa; v_SizingFlow_ms: 0 m/s; ConnectionSize_mm: 0 mm
ePset_Simplebim - Assembly Level: Leaf
ePset_LocationTool - Splitting: ORIGINAL
Name | Insulation_thickness_mm (mm) | Group
6 x magicirc_elbow_full_radius_001 | 30 | +TI=360.051 A
10 x magicirc_elbow_full_radius_001 | 30 | 36= A Kopi 20
magicirc_elbow_full_radius_001 | 0 | 36= A Kopi 21

# IfcFlowFitting: magicirc_elbow_short_001 (3)
In: Nivå F
Type - PredefinedType: BEND
MagiCAD Pset_Elbow - qv_SizingFlow_ls: 0 m3/s; pTot_SizingFlow_Pa: 0 Pa; dpTot_SizingFlow_Pa: 0 Pa; v_SizingFlow_ms: 0 m/s; ConnectionSize_mm: 0 mm
ePset_Simplebim - Assembly Level: Leaf
ePset_LocationTool - Splitting: ORIGINAL
Name | Insulation_thickness_mm (mm) | Group
2 x magicirc_elbow_short_001 | 0 | 36= A Kopi 21
magicirc_elbow_short_001 | 30 | 36= A Kopi 20

# IfcFlowFitting: magicirc_joint_001 (2)
In: Nivå F
Type - PredefinedType: CONNECTOR
MagiCAD Pset_Joint - qv_SizingFlow_ls: 0 m3/s; pTot_SizingFlow_Pa: 0 Pa; dpTot_SizingFlow_Pa: 0 Pa; v_SizingFlow_ms: 0 m/s; ConnectionSize_mm: 0 mm; Insulation_thickness_mm: 30 mm
ePset_LocationTool - Splitting: ORIGINAL
ePset_Simplebim - Assembly Level: Leaf
Name | Group
magicirc_joint_001 | +TI=360.051 A
magicirc_joint_001 | 36= A Kopi 20

# IfcFlowFitting: magicirc_multi_shape_trans_001
In: Nivå F
Type - PredefinedType: TRANSITION
MagiCAD Pset_Reduction - qv_SizingFlow_ls: 0 m3/s; pTot_SizingFlow_Pa: 0 Pa; dpTot_SizingFlow_Pa: 0 Pa; v_SizingFlow_ms: 0 m/s; ConnectionSize_mm: 0 mm; Insulation_thickness_mm: 0 mm
ePset_Simplebim - Assembly Level: Leaf
ePset_LocationTool - Splitting: ORIGINAL
Group: +TI=360.051 A

# IfcFlowFitting: magicirc_reduction_001 (2)
In: Nivå F
Type - PredefinedType: TRANSITION
MagiCAD Pset_Reduction - qv_SizingFlow_ls: 0 m3/s; pTot_SizingFlow_Pa: 0 Pa; dpTot_SizingFlow_Pa: 0 Pa; v_SizingFlow_ms: 0 m/s; ConnectionSize_mm: 0 mm; Insulation_thickness_mm: 30 mm
ePset_Simplebim - Assembly Level: Leaf
ePset_LocationTool - Splitting: ORIGINAL
Group: 36= A Kopi 20

# IfcFlowFitting: magicirc_tapoutlet_001 (3)
In: Nivå F
Type - PredefinedType: CONNECTOR
ePset_LocationTool - Splitting: ORIGINAL
ePset_Simplebim - Assembly Level: Leaf
Name | Group
magicirc_tapoutlet_001 | 36= T Kopi 184
magicirc_tapoutlet_001 | +TI=360.051 A
magicirc_tapoutlet_001 | 36= A Kopi 20

# IfcFlowSegment: 1-REKT
In: Nivå E
Type - Description: Rektangulære, Forsinket stål; PredefinedType: RIGIDSEGMENT
MagiCAD Pset_Duct - qv_SizingFlow_ls: 0 m3/s; dpTot_SizingFlow_Pa: 0 Pa; pTot_SizingFlow_Pa: 0 Pa; v_SizingFlow_ms: 0 m/s; Description: Rektangulære, Forsinket stål; Insulation_thickness_mm: 50 mm; Length_mm: 1350 mm; UserCode: 1-REKT
ePset_SimplebimBasicQuantities - Width (Simplebim): 300 mm; Height (Simplebim): 1350 mm; Length (Simplebim): 2450 mm
ePset_Simplebim - Assembly Level: Leaf
ePset_LocationTool - Splitting: ORIGINAL
Group: 36= T Kopi 184

# IfcFlowSegment: 2 - Spiro kanaler, Forsinket stål (33)
Type - Description: Spiro kanaler, Forsinket stål; PredefinedType: RIGIDSEGMENT
ePset_Simplebim - Assembly Level: Leaf
MagiCAD Pset_Duct - UserCode: Circ; Description: Spiro kanaler, Forsinket stål
Name | In | Height (Simplebim) (mm) | Length (Simplebim) (mm) | Width (Simplebim) (mm) | Splitting | qv_SizingFlow_ls (m3/s) | dpTot_SizingFlow_Pa (Pa) = pTot_SizingFlow_Pa (Pa) = v_SizingFlow_ms (m/s) | Insulation_thickness_mm (mm) | Length_mm (mm) | Group
2 - Spiro kanaler, Forsinket stål | Nivå D | 50 | 400 | 400 | ORIGINAL | 0 | 0 | 0 | 50 | 36= T Kopi 13
2 - Spiro kanaler, Forsinket stål | Nivå D | 400 | 245.4 | 400 | ORIGINAL | 0 | 0 | 0 | 245 | 36= T Kopi 13
2 - Spiro kanaler, Forsinket stål | Nivå F | 630 | 464.2 | 630 | ORIGINAL | 0 | 0 | 25 | 464.193 | 36= T Kopi 184
2 - Spiro kanaler, Forsinket stål | Nivå F | 315 | 923.1 | 315 | ORIGINAL | 0 | 0 | 30 | 923.135 | +TI=360.051 A
2 - Spiro kanaler, Forsinket stål | Nivå F | 315 | 1368.5 | 315 | ORIGINAL | 0 | 0 | 30 | 1368.35 | +TI=360.051 A
2 - Spiro kanaler, Forsinket stål | Nivå F | 250 | 116.4 | 250 | ORIGINAL | 0 | 0 | 30 | 116.23 | 36= A Kopi 20
2 - Spiro kanaler, Forsinket stål | Nivå F | 250 | 76.7 | 250 | ORIGINAL | 0 | 0 | 0 | 76.695 | +TI=360.051 A
2 - Spiro kanaler, Forsinket stål | Nivå F | 250 | 38 | 250 | ORIGINAL | 0 | 0 | 30 | 38.013 | 36= A Kopi 210
2 - Spiro kanaler, Forsinket stål | Nivå F | 250 | 147.7 | 250 | ORIGINAL | 0 | 0 | 30 | 147.684 | 36= A Kopi 20
2 - Spiro kanaler, Forsinket stål | Nivå F | 315 | 1336.6 | 315 | ORIGINAL | 0 | 0 | 30 | 1336.6 | +TI=360.051 A
2 - Spiro kanaler, Forsinket stål | Nivå F | 250 | 76.4 | 250 | ORIGINAL | 0 | 0 | 30 | 76.447 | 36= A Kopi 20
2 - Spiro kanaler, Forsinket stål | Nivå F | 250 | 867.7 | 250 | ORIGINAL | 0 | 0 | 30 | 867.696 | 36= A Kopi 20
2 - Spiro kanaler, Forsinket stål | Nivå F | 250 | 69.9 | 250 | ORIGINAL | 0 | 0 | 30 | 69.871 | 36= A Kopi 20
2 - Spiro kanaler, Forsinket stål | Nivå F | 250 | 276.2 | 250 | ORIGINAL | 0 | 0 | 30 | 276.181 | 36= A Kopi 20
2 - Spiro kanaler, Forsinket stål | Nivå F | 250 | 705 | 250 | ORIGINAL | 0 | 0 | 30 | 705 | 36= A Kopi 20
2 - Spiro kanaler, Forsinket stål | Nivå F | 29 | 160 | 160 | ORIGINAL | 60 | 0 | 0 | 29 | 36= A Kopi 21
2 - Spiro kanaler, Forsinket stål | Nivå F | 315 | 56.6 | 315 | ORIGINAL | 0 | 0 | 30 | 56.601 | +TI=360.051 A
2 - Spiro kanaler, Forsinket stål | Nivå F | 315 | 1545.5 | 315 | ORIGINAL | 0 | 0 | 30 | 1545.52 | +TI=360.051 A
2 - Spiro kanaler, Forsinket stål | Nivå F | 250 | 530 | 250 | ORIGINAL | 0 | 0 | 30 | 530 | 36= A Kopi 20
2 - Spiro kanaler, Forsinket stål | Nivå F | 250 | 246.4 | 250 | ORIGINAL | 0 | 0 | 30 | 246.447 | 36= A Kopi 20
2 - Spiro kanaler, Forsinket stål | Nivå F | 250 | 19.2 | 250 | ORIGINAL | 0 | 0 | 30 | 19.167 | 36= A Kopi 20
2 x 2 - Spiro kanaler, Forsinket stål | Nivå F | 200 | 49.5 | 200 | ORIGINAL | 0 | 0 | 30 | 49.469 | 36= A Kopi 20
2 - Spiro kanaler, Forsinket stål | Nivå F | 200 | 85 | 200 | ORIGINAL | 0 | 0 | 30 | 84.735 | 36= A Kopi 20
2 - Spiro kanaler, Forsinket stål | Nivå F | 14.5 | 200 | 200 | ORIGINAL | 0 | 0 | 30 | 14.469 | 36= A Kopi 20
2 - Spiro kanaler, Forsinket stål | Nivå F | 200 | 64.7 | 200 | ORIGINAL | 0 | 0 | 30 | 64.735 | 36= A Kopi 20
2 - Spiro kanaler, Forsinket stål | Nivå F | 160 | 197.5 | 160 | ORIGINAL | 60 | 0 | 0 | 198.35 | 36= A Kopi 21
2 - Spiro kanaler, Forsinket stål | Nivå F | 160 | 71.3 | 160 | ORIGINAL | 60 | 0 | 0 | 70.978 | 36= A Kopi 21
2 - Spiro kanaler, Forsinket stål | Nivå F | 315 | 12 | 315 | ORIGINAL | 0 | 0 | 30 | 11.627 | +TI=360.051 A
2 - Spiro kanaler, Forsinket stål | Nivå F | 16 | 315 | 315 | ORIGINAL | 0 | 0 | 30 | 15.654 | +TI=360.051 A
2 - Spiro kanaler, Forsinket stål | Nivå F | 315 | 51.2 | 315 | ORIGINAL | 0 | 0 | 30 | 51.192 | +TI=360.051 A
2 - Spiro kanaler, Forsinket stål | Nivå F | 160 | 367.1 | 160 | ORIGINAL | 60 | 0 | 0 | 367.061 | 36= A Kopi 21
2 - Spiro kanaler, Forsinket stål | Nivå F | 316 | 538 | 316 | RESULT |  |  |  |  | +TI=360.051 A

# IfcFlowSegment: KK002T - Rektangulære, Forsinket stål
In: Nivå F
Type - Description: Rektangulære, Forsinket stål; PredefinedType: RIGIDSEGMENT
Classification: VB2.111212 Not defined (NS3420); Group: +TI=360.051 A
ePset_SimplebimBasicQuantities - Height (Simplebim): 200 mm; Width (Simplebim): 500 mm; Length (Simplebim): 660 mm
MagiCAD Pset_Duct - NationalCode: VB2.111212; UserCode: Rect; qv_SizingFlow_ls: 0 m3/s; dpTot_SizingFlow_Pa: 0 Pa; pTot_SizingFlow_Pa: 0 Pa; v_SizingFlow_ms: 0 m/s; Description: Rektangulære, Forsinket stål; Insulation_thickness_mm: 30 mm; Length_mm: 660.003 mm
ePset_Simplebim - Assembly Level: Leaf
ePset_LocationTool - Splitting: ORIGINAL

# IfcFlowSegment: Kabelbro (2)
In: Nivå F
Type - PredefinedType: CABLELADDERSEGMENT
ePset_LocationTool - Splitting: RESULT
ePset_Simplebim - Assembly Level: Leaf
ePset_SimplebimBasicQuantities - Width (Simplebim): 60 mm; Height (Simplebim): 600 mm; Length (Simplebim): 1270 mm
Name | System code | Group
Kabelbro | 410 | Bæresystem generelt
Kabelbro | 5111 | Bæresystem for tele- og automasjon

# IfcFlowSegment: Kobberrør (40)
Type - PredefinedType: RIGIDSEGMENT
Classification: UB1.111713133 Not defined (NS3420)
MagiCAD Pset_Pipe - User Code: Cu; NationalCode: UB1.111713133; Material: Kobberrør
ePset_Simplebim - Assembly Level: Leaf
Name | In | Splitting | SystemName = Group | Insulation_thickness_mm (mm) | qv_SizingFlow_ls (m3/s) = MagiCAD Pset_Water, dpTot_SizingFlow_kPa (Pa) = MagiCAD Pset_Water, pTot_SizingFlow_kPa (Pa) = MagiCAD Pset_Water, v_SizingFlow_ms (m/s) = MagiCAD Pset_Heating, v_SizingFlow_ms (m/s) = MagiCAD Pset_Heating, pTot_SizingFlow_kPa (Pa) = MagiCAD Pset_Heating, dpTot_SizingFlow_kPa (Pa) | ConnectionSize_mm (mm) | Length_mm (mm) | SystemType | SystemClass | Height (Simplebim) (mm) = Width (Simplebim) (mm) | Length (Simplebim) (mm)
Kobberrør | Nivå D | ORIGINAL | +TI=310.101-1 | 0 | 0 | 28 | 124 | KV | Domestic Cold Water | 28 | 123.8
Kobberrør | Nivå D | ORIGINAL | +TI=310.101-1 | 0 | 0 | 28 | 130.975 | KV | Domestic Cold Water | 28 | 131
Kobberrør | Nivå D | ORIGINAL | +TI=310.101-1 | 21 | 0 | 28 | 159.593 | KV | Domestic Cold Water | 28 | 159.6
Kobberrør | Nivå D | ORIGINAL | +TI=310.201-1 | 30 | 0 | 18 | 9064 | VV | Domestic Hot Water | 18 | 9064
Kobberrør | Nivå D | ORIGINAL | +TI=310.101-1 | 21 | 0 | 28 | 9194 | KV | Domestic Cold Water | 28 | 9194
Kobberrør | Nivå D | ORIGINAL | +TI=310.101-1 | 21 | 0 | 28 | 2117.25 | KV | Domestic Cold Water | 28 | 2117.3
Kobberrør | Nivå D | ORIGINAL | +TI=310.201-1 | 30 | 0 | 18 | 2140 | VV | Domestic Hot Water | 18 | 2140
Kobberrør | Nivå D | ORIGINAL | +TI=310.201-1 | 30 | 0 | 18 | 4799 | VV | Domestic Hot Water | 18 | 4799
Kobberrør | Nivå D | ORIGINAL | +TI=310.201-1 | 30 | 0 | 18 | 131.8 | VV | Domestic Hot Water | 18 | 131.8
Kobberrør | Nivå D | ORIGINAL | +TI=310.101-1 | 0 | 0 | 28 | 2889.03 | KV | Domestic Cold Water | 28 | 2889
Kobberrør | Nivå D | ORIGINAL | +TI=310.101-1 | 21 | 0 | 28 | 111.818 | KV | Domestic Cold Water | 28 | 112
Kobberrør | Nivå D | ORIGINAL | +TI=310.101-1 | 20 | 0 | 15 | 613.9 | KV | Domestic Cold Water | 15 | 613.9
Kobberrør | Nivå D | ORIGINAL | +TI=310.101-1 | 20 | 0 | 15 | 132.212 | KV | Domestic Cold Water | 15 | 132.2
Kobberrør | Nivå D | ORIGINAL | +TI=310.101-1 | 20 | 0 | 15 | 59 | KV | Domestic Cold Water | 15 | 59
Kobberrør | Nivå D | ORIGINAL | +TI=310.101-1 | 21 | 0 | 28 | 1996.72 | KV | Domestic Cold Water | 28 | 1996.7
Kobberrør | Nivå D | ORIGINAL | +TI=350.001 R-1 | 20 | 0 | 18 | 1351.26 | KJØLMEDIE R | Hydronic Return | 18 | 1351.3
Kobberrør | Nivå D | ORIGINAL | +TI=350.001 R-1 | 20 | 0 | 18 | 1004 | KJØLMEDIE R | Hydronic Return | 18 | 1004
Kobberrør | Nivå D | ORIGINAL | +TI=350.001 R-1 | 20 | 0 | 18 | 174 | KJØLMEDIE R | Hydronic Return | 18 | 174
Kobberrør | Nivå D | ORIGINAL | +TI=350.001 R-1 | 20 | 0 | 18 | 3644 | KJØLMEDIE R | Hydronic Return | 18 | 3644
Kobberrør | Nivå D | ORIGINAL | +TI=350.001 T-1 | 20 | 0 | 18 | 1336.26 | KJØLMEDIE T | Hydronic Supply | 18 | 1336.3
Kobberrør | Nivå D | ORIGINAL | +TI=350.001 T-1 | 20 | 0 | 18 | 899.267 | KJØLMEDIE T | Hydronic Supply | 18 | 899.3
Kobberrør | Nivå D | ORIGINAL | +TI=350.001 T-1 | 20 | 0 | 18 | 104 | KJØLMEDIE T | Hydronic Supply | 18 | 104
Kobberrør | Nivå D | ORIGINAL | +TI=350.001 T-1 | 20 | 0 | 18 | 3644 | KJØLMEDIE T | Hydronic Supply | 18 | 3644
Kobberrør | Nivå D | ORIGINAL | +TI=350.001 T-1 | 20 | 0 | 18 | 809 | KJØLMEDIE T | Hydronic Supply | 18 | 809
Kobberrør | Nivå D | ORIGINAL | +TI=350.001 T-1 | 20 | 0 | 18 | 374 | KJØLMEDIE T | Hydronic Supply | 18 | 373.8
Kobberrør | Nivå D | ORIGINAL | +TI=350.001 R-1 | 20 | 0 | 18 | 821.931 | KJØLMEDIE R | Hydronic Return | 18 | 821.9
Kobberrør | Nivå D | ORIGINAL | +TI=350.001 R-1 | 20 | 0 | 18 | 374 | KJØLMEDIE R | Hydronic Return | 18 | 373.8
Kobberrør | Nivå D | ORIGINAL | +TI=310.101-1 | 21 | 0 | 28 | 45.057 | KV | Domestic Cold Water | 28 | 45.4
Kobberrør | Nivå D | ORIGINAL | +TI=310.201-1 | 30 | 0 | 18 | 54.66 | VV | Domestic Hot Water | 18 | 54.6
Kobberrør | Nivå D | ORIGINAL | +TI=310.101-1 | 21 | 0 | 28 | 858.943 | KV | Domestic Cold Water | 28 | 858.9
Kobberrør | Nivå D | ORIGINAL | +TI=310.201-1 | 30 | 0 | 18 | 851.34 | VV | Domestic Hot Water | 18 | 851.3
Kobberrør | Nivå F | ORIGINAL | +TI=350.001 R-1 | 20 | 0 | 18 | 144 | KJØLMEDIE R | Hydronic Return | 18 | 144
Kobberrør | Nivå F | ORIGINAL | +TI=350.001 T-1 | 20 | 0 | 18 | 104 | KJØLMEDIE T | Hydronic Supply | 18 | 104
Kobberrør | Nivå F | ORIGINAL | +TI=350.001 T-1 | 20 | 0 | 18 | 3722 | KJØLMEDIE T | Hydronic Supply | 18 | 3722
Kobberrør | Nivå F | ORIGINAL | +TI=350.001 R-1 | 20 | 0 | 18 | 3772 | KJØLMEDIE R | Hydronic Return | 18 | 3772
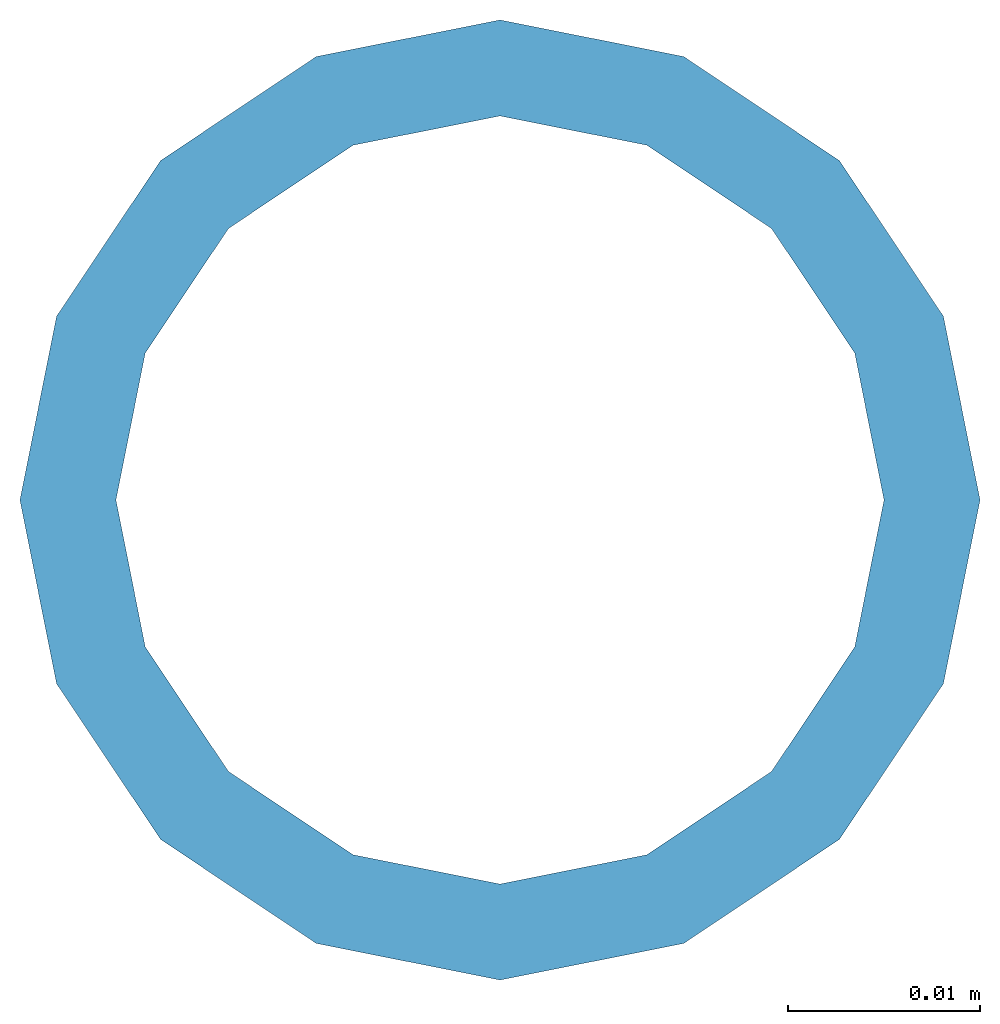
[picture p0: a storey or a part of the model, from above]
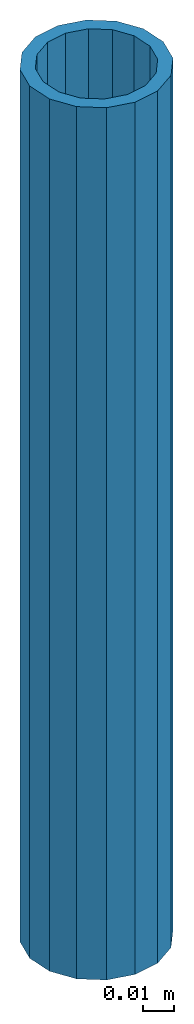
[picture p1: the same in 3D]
Properties of the parts of a building model (IFC2X3), part 5 of 6

# IfcFlowSegment: Kobberrør (40)
Name | In | Splitting | SystemName = Group | Insulation_thickness_mm (mm) | qv_SizingFlow_ls (m3/s) = MagiCAD Pset_Water, dpTot_SizingFlow_kPa (Pa) = MagiCAD Pset_Water, pTot_SizingFlow_kPa (Pa) = MagiCAD Pset_Water, v_SizingFlow_ms (m/s) = MagiCAD Pset_Heating, v_SizingFlow_ms (m/s) = MagiCAD Pset_Heating, pTot_SizingFlow_kPa (Pa) = MagiCAD Pset_Heating, dpTot_SizingFlow_kPa (Pa) | ConnectionSize_mm (mm) | Length_mm (mm) | SystemType | SystemClass | Height (Simplebim) (mm) = Width (Simplebim) (mm) | Length (Simplebim) (mm)
Kobberrør | Nivå D | RESULT | +TI=350.001 T-1 |  |  |  |  | KJØLMEDIE T | Hydronic Supply | 18 | 666
Kobberrør | Nivå D | RESULT | +TI=350.001 R-1 |  |  |  |  | KJØLMEDIE R | Hydronic Return | 18 | 721
Kobberrør | Nivå D | RESULT | +TI=310.101-1 |  |  |  |  | KV | Domestic Cold Water | 28 | 434
Kobberrør | Nivå D | RESULT | +TI=310.201-1 |  |  |  |  | VV | Domestic Hot Water | 18 | 629
Kobberrør | Nivå D | RESULT | +TI=310.101-1 |  |  |  |  | KV | Domestic Cold Water | 28 | 9985

# IfcFlowSegment: Logiske føringsveier (3)
Type - PredefinedType: CABLELADDERSEGMENT
ePset_Simplebim - Assembly Level: Leaf
MagiCAD Pset_Cabletray - System code: 501-B
ePset_SimplebimBasicQuantities - Height (Simplebim): 30 mm; Width (Simplebim): 30 mm
Group: STIGEKABEL-SEKUNDÆR
Name | In | O1 | Length (Simplebim) (mm) | Splitting
Logiske føringsveier | Nivå F | TI04 - TI16 | 382.5 | ORIGINAL | Pset_CableCarrierSegmentTypeCableLadderSegment - NominalLength: 382.979 mm; NominalWidth: 30 mm; NominalHeight: 30 mm; MagiCAD Pset_Cabletray - Length [mm]: 382.979 mm; Width [mm]: 30 mm; Height [mm]: 30 mm
Logiske føringsveier | Nivå G + 1,2 m | TI04 - TI26 | 503 | RESULT
Logiske føringsveier | Nivå F | TI04 - TI16 | 503 | RESULT

# IfcFlowSegment: MA (18)
In: Nivå D
Type - PredefinedType: RIGIDSEGMENT
Classification: UB2.1115131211 Not defined (NS3420)
MagiCAD Pset_Pipe - Material: MA; User Code: MA; NationalCode: UB2.1115131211
ePset_Simplebim - Assembly Level: Leaf
Name | Length (Simplebim) (mm) | Height (Simplebim) (mm) | Width (Simplebim) (mm) | SystemName = Group | Insulation_thickness_mm (mm) = qv_SizingFlow_ls (m3/s) = MagiCAD Pset_Water, dpTot_SizingFlow_kPa (Pa) = MagiCAD Pset_Water, pTot_SizingFlow_kPa (Pa) = MagiCAD Pset_Water, v_SizingFlow_ms (m/s) = MagiCAD Pset_Heating, v_SizingFlow_ms (m/s) = MagiCAD Pset_Heating, pTot_SizingFlow_kPa (Pa) = MagiCAD Pset_Heating, dpTot_SizingFlow_kPa (Pa) | SystemType | SystemClass | ConnectionSize_mm (mm) | Length_mm (mm) | Splitting
MA | 204.8 | 110 | 110 | +TI=313.003 | 0 | SPV | Sanitary | 110 | 204.683 | ORIGINAL
MA | 907.5 | 110 | 110 | +TI=313.003 | 0 | SPV | Sanitary | 110 | 907.507 | ORIGINAL
MA | 751.5 | 110 | 110 | +TI=313.003 | 0 | SPV | Sanitary | 110 | 752.089 | ORIGINAL
MA | 133.9 | 110 | 110 | +TI=313.003 | 0 | SPV | Sanitary | 110 | 133.576 | ORIGINAL
MA | 121.9 | 75 | 75 |  | 0 | Undefined | Undefined | 75 | 121.942 | ORIGINAL
MA | 4785.4 | 110 | 110 | +TI=313.003 | 0 | SPV | Sanitary | 110 | 4785.36 | ORIGINAL
MA | 969.1 | 75 | 75 |  | 0 | Undefined | Undefined | 75 | 969.13 | ORIGINAL
MA | 81.3 | 75 | 75 |  | 0 | Undefined | Undefined | 75 | 80.773 | ORIGINAL
MA | 59.7 | 110 | 110 | +TI=313.003 | 0 | SPV | Sanitary | 110 | 59.475 | ORIGINAL
MA | 613.9 | 75 | 75 | +TI=313.003 | 0 | SPV | Sanitary | 75 | 613.863 | ORIGINAL
MA | 1704.7 | 75 | 75 | +TI=313.003 | 0 | SPV | Sanitary | 75 | 1704.7 | ORIGINAL
MA | 167.6 | 75 | 75 | +TI=313.003 | 0 | SPV | Sanitary | 75 | 167.605 | ORIGINAL
MA | 404.8 | 75 | 75 | +TI=313.003 | 0 | SPV | Sanitary | 75 | 404.825 | ORIGINAL
MA | 75 | 75 | 74.6 | +TI=313.003 | 0 | SPV | Sanitary | 75 | 75.423 | ORIGINAL
MA | 337.1 | 110 | 110 | +TI=313.003 | 0 | SPV | Sanitary | 110 | 337.44 | ORIGINAL
MA | 75 | 40 | 75 |  | 0 | Undefined | Undefined | 75 | 40 | ORIGINAL
MA | 438.7 | 75 | 75 | +TI=313.003 | 0 | SPV | Sanitary | 75 | 438.888 | ORIGINAL
MA | 4932 | 110 | 110 | +TI=313.003 |  | SPV | Sanitary |  |  | RESULT

# IfcFlowSegment: PE rør
In: Nivå D
Type - PredefinedType: RIGIDSEGMENT
MagiCAD Pset_Pipe - Material: PE 80 trykkrør SDR 11; SystemName: +TI=313.207; SystemClass: Sanitary; SystemType: OV; User Code: PE
ePset_LocationTool - Splitting: RESULT
ePset_SimplebimBasicQuantities - Width (Simplebim): 25 mm; Height (Simplebim): 50 mm; Length (Simplebim): 4300 mm
ePset_Simplebim - Assembly Level: Leaf
Group: +TI=313.207

# IfcFlowSegment: PEX rør (38)
In: Nivå D
Type - PredefinedType: RIGIDSEGMENT
Classification: UB1.111423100 Not defined (NS3420)
ePset_Simplebim - Assembly Level: Leaf
MagiCAD Pset_Water - dpTot_SizingFlow_kPa: 0 Pa; pTot_SizingFlow_kPa: 0 Pa; v_SizingFlow_ms: 0 m/s
MagiCAD Pset_Heating - v_SizingFlow_ms: 0 m/s; pTot_SizingFlow_kPa: 0 Pa; dpTot_SizingFlow_kPa: 0 Pa
ePset_LocationTool - Splitting: ORIGINAL
MagiCAD Pset_Pipe - NationalCode: UB1.111423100; qv_SizingFlow_ls: 0 m3/s; Material: PEX rør
Name | SystemClass | Insulation_thickness_mm (mm) | SystemName = Group | SystemType | ConnectionSize_mm (mm) = Height (Simplebim) (mm) | Length_mm (mm) | Width (Simplebim) (mm) | Length (Simplebim) (mm)
9 x PEX rør | Hydronic Return | 0 | +TI=323.002 R-1 | GULVVARME R | 18 | 79.11 | 18 | 79
8 x PEX rør | Hydronic Return | 0 | +TI=323.002 R-1 | GULVVARME R | 28 | 4 | 4 | 28
9 x PEX rør | Hydronic Supply | 0 | 32= T 55° Kopi 1 | GULVVARME T | 18 | 79.429 | 18 | 79
8 x PEX rør | Hydronic Supply | 0 | 32= T 55° Kopi 1 | GULVVARME T | 28 | 4 | 4 | 28
PEX rør | Hydronic Supply | 0 | 32= T 55° Kopi 1 | GULVVARME T | 28 | 35 | 28 | 35
PEX rør | Hydronic Return | 0 | +TI=323.002 R-1 | GULVVARME R | 28 | 34.999 | 28 | 35
PEX rør | Hydronic Supply | 30 | 32= T 55° Kopi 1 | GULVVARME T | 28 | 27.199 | 28 | 27.2
PEX rør | Hydronic Return | 30 | +TI=323.002 R-1 | GULVVARME R | 28 | 27.2 | 28 | 27.2

# IfcFlowSegment: PP avløpsrør (5)
Type - PredefinedType: RIGIDSEGMENT
Classification: UB2.1114431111 Not defined (NS3420); Group: 31= Spillvann 3
ePset_SimplebimBasicQuantities - Height (Simplebim): 32 mm; Width (Simplebim): 32 mm
ePset_Simplebim - Assembly Level: Leaf
MagiCAD Pset_Water - dpTot_SizingFlow_kPa: 0 Pa; pTot_SizingFlow_kPa: 0 Pa; v_SizingFlow_ms: 0 m/s
MagiCAD Pset_Heating - v_SizingFlow_ms: 0 m/s; pTot_SizingFlow_kPa: 0 Pa; dpTot_SizingFlow_kPa: 0 Pa
ePset_LocationTool - Splitting: ORIGINAL
MagiCAD Pset_Pipe - Material: PP avløpsrør; Insulation_thickness_mm: 0 mm; qv_SizingFlow_ls: 0 m3/s; User Code: PP; SystemName: 31= Spillvann 3; NationalCode: UB2.1114431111; SystemClass: Sanitary; ConnectionSize_mm: 32 mm; SystemType: 31 Spillvann
Name | In | Length (Simplebim) (mm) | Length_mm (mm)
PP avløpsrør | Nivå D | 152.4 | 152.413
PP avløpsrør | Nivå D | 946.7 | 946.677
PP avløpsrør | Nivå D | 91.4 | 91.373
PP avløpsrør | Nivå D | 899.1 | 899.104
PP avløpsrør | Nivå F | 3253.5 | 3253.47

# IfcFlowSegment: Stålrør normaltykke (205)
Type - PredefinedType: RIGIDSEGMENT
Classification: UB3.144613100 Not defined (NS3420)
ePset_Simplebim - Assembly Level: Leaf
MagiCAD Pset_Pipe - NationalCode: UB3.144613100; User Code: DN; Material: Stålrør normaltykke
Name | In | Splitting | SystemClass | SystemName = Group | Length_mm (mm) | Insulation_thickness_mm (mm) | qv_SizingFlow_ls (m3/s) = MagiCAD Pset_Water, dpTot_SizingFlow_kPa (Pa) = MagiCAD Pset_Water, pTot_SizingFlow_kPa (Pa) = MagiCAD Pset_Water, v_SizingFlow_ms (m/s) = MagiCAD Pset_Heating, v_SizingFlow_ms (m/s) = MagiCAD Pset_Heating, pTot_SizingFlow_kPa (Pa) = MagiCAD Pset_Heating, dpTot_SizingFlow_kPa (Pa) | ConnectionSize_mm (mm) | SystemType | Height (Simplebim) (mm) | Width (Simplebim) (mm) | Length (Simplebim) (mm)
Stålrør normaltykke | Nivå C | ORIGINAL | Fire Protection Other | +TI=330.003 B-1 | 79.692 | 0 | 0 | 100 | BRANNVANN TRYKK | 114.2 | 114.2 | 79.7
Stålrør normaltykke | Nivå C | ORIGINAL | Fire Protection Other | +TI=330.003 B-1 | 6694.29 | 0 | 0 | 100 | BRANNVANN TRYKK | 114.2 | 114.2 | 6694.3
Stålrør normaltykke | Nivå D | ORIGINAL | Hydronic Supply | +TI=322.004 T | 102.752 | 50 | 0 | 50 | SHUNTET VARME T | 60.2 | 60.2 | 102.8
Stålrør normaltykke | Nivå D | ORIGINAL | Hydronic Return | +TI=322.004 R | 26.605 | 50 | 0 | 50 | SHUNTET VARME R | 27.1 | 60.2 | 60.2
Stålrør normaltykke | Nivå D | ORIGINAL | Hydronic Return | +TI=322.004 R | 533.417 | 50 | 0 | 50 | SHUNTET VARME R | 60.2 | 60.2 | 533.4
Stålrør normaltykke | Nivå D | ORIGINAL | Hydronic Supply | +TI=322.004 T | 717.417 | 50 | 0 | 50 | SHUNTET VARME T | 60.2 | 60.2 | 717.4
Stålrør normaltykke | Nivå D | ORIGINAL | Hydronic Return | +TI=322.004 R | 109.141 | 40 | 0 | 40 | SHUNTET VARME R | 48.2 | 48.2 | 109.1
Stålrør normaltykke | Nivå D | ORIGINAL | Hydronic Return | +TI=322.004 R | 266.548 | 40 | 0 | 40 | SHUNTET VARME R | 48.2 | 48.2 | 266.5
2 x Stålrør normaltykke | Nivå D | ORIGINAL | Hydronic Return | +TI=322.004 R | 146.5 | 30 | 0 | 10 | SHUNTET VARME R | 17.2 | 17.2 | 146.5
Stålrør normaltykke | Nivå D | ORIGINAL | Hydronic Return | +TI=322.004 R | 134.55 | 30 | 0 | 10 | SHUNTET VARME R | 17.2 | 17.2 | 134.6
Stålrør normaltykke | Nivå D | ORIGINAL | Hydronic Return | +TI=322.004 R | 116.459 | 40 | 0 | 40 | SHUNTET VARME R | 48.2 | 48.2 | 116.5
Stålrør normaltykke | Nivå D | ORIGINAL | Hydronic Return | +TI=322.004 R | 148.05 | 30 | 0 | 10 | SHUNTET VARME R | 17.2 | 17.2 | 148
Stålrør normaltykke | Nivå D | ORIGINAL | Hydronic Return | +TI=322.004 R | 156.595 | 40 | 0 | 40 | SHUNTET VARME R | 48.2 | 48.2 | 156.7
Stålrør normaltykke | Nivå D | ORIGINAL | Hydronic Supply | +TI=322.004 T | 591.401 | 40 | 0 | 40 | SHUNTET VARME T | 48.2 | 48.2 | 591
Stålrør normaltykke | Nivå D | ORIGINAL | Hydronic Return | +TI=322.004 R | 127.106 | 40 | 0 | 40 | SHUNTET VARME R | 48.2 | 48.2 | 126.7
Stålrør normaltykke | Nivå D | ORIGINAL | Hydronic Supply | +TI=322.004 T | 283.3 | 40 | 0 | 40 | SHUNTET VARME T | 48.2 | 48.2 | 283.3
Stålrør normaltykke | Nivå D | ORIGINAL | Hydronic Return | +TI=322.004 R | 376.89 | 40 | 0 | 40 | SHUNTET VARME R | 48.2 | 48.2 | 376.9
Stålrør normaltykke | Nivå D | ORIGINAL | Hydronic Supply | +TI=322.004 T | 60.018 | 40 | 0 | 40 | SHUNTET VARME T | 48.2 | 48.2 | 60.3
Stålrør normaltykke | Nivå D | ORIGINAL | Hydronic Supply | 32= T 55° Kopi 1 | 642.716 | 40 | 0 | 25 | GULVVARME T | 33.8 | 33.8 | 643.4
Stålrør normaltykke | Nivå D | ORIGINAL | Hydronic Return | +TI=323.002 R-1 | 966.448 | 40 | 0 | 25 | GULVVARME R | 33.8 | 33.8 | 966.4
Stålrør normaltykke | Nivå D | ORIGINAL | Hydronic Supply | 32= T 55° Kopi 1 | 175.502 | 40 | 0 | 25 | GULVVARME T | 33.8 | 33.8 | 175.5
Stålrør normaltykke | Nivå D | ORIGINAL | Hydronic Supply | 32= T 55° Kopi 1 | 66.386 | 40 | 0 | 25 | GULVVARME T | 33.8 | 33.8 | 66.4
Stålrør normaltykke | Nivå D | ORIGINAL | Hydronic Return | +TI=323.002 R-1 | 234.099 | 40 | 0 | 25 | GULVVARME R | 33.8 | 33.8 | 234.1
Stålrør normaltykke | Nivå D | ORIGINAL | Hydronic Return | +TI=323.002 R-1 | 192.04 | 40 | 0 | 25 | GULVVARME R | 33.8 | 33.8 | 192
Stålrør normaltykke | Nivå D | ORIGINAL | Hydronic Return | +TI=323.002 R-1 | 1249.77 | 40 | 0 | 25 | GULVVARME R | 33.8 | 33.8 | 1249.8
Stålrør normaltykke | Nivå D | ORIGINAL | Hydronic Supply | 32= T 55° Kopi 1 | 701.668 | 40 | 0 | 25 | GULVVARME T | 33.8 | 33.8 | 701.7
Stålrør normaltykke | Nivå D | ORIGINAL | Hydronic Supply | +TI=322.004 T | 613.248 | 40 | 0 | 40 | SHUNTET VARME T | 48.2 | 48.2 | 613.1
Stålrør normaltykke | Nivå D | ORIGINAL | Hydronic Supply | +TI=322.004 T | 4145.84 | 40 | 0 | 40 | SHUNTET VARME T | 48.2 | 48.2 | 4145.8
Stålrør normaltykke | Nivå D | ORIGINAL | Hydronic Supply | +TI=322.004 T | 87.214 | 0 | 0 | 40 | SHUNTET VARME T | 48.2 | 48.2 | 87.2
Stålrør normaltykke | Nivå D | ORIGINAL | Hydronic Supply | +TI=322.004 T | 64.214 | 0 | 0 | 40 | SHUNTET VARME T | 48.2 | 48.2 | 63.5
Stålrør normaltykke | Nivå D | ORIGINAL | Hydronic Supply | +TI=370.001 T | 9506.4 | 21 | 0 | 20 | KJØL T | 26.6 | 26.6 | 9506.4
Stålrør normaltykke | Nivå D | ORIGINAL | Hydronic Supply | +TI=370.001 T | 3366.4 | 21 | 0 | 20 | KJØL T | 26.6 | 26.6 | 3366.4
Stålrør normaltykke | Nivå D | ORIGINAL | Hydronic Return | +TI=370.001 R | 9343.9 | 21 | 0 | 20 | KJØL R | 26.6 | 26.6 | 9343.9
Stålrør normaltykke | Nivå D | ORIGINAL | Hydronic Return | +TI=370.001 R | 3366.4 | 21 | 0 | 20 | KJØL R | 26.6 | 26.6 | 3366.4
Stålrør normaltykke | Nivå D | ORIGINAL | Hydronic Supply | +TI=370.001 T | 2091.85 | 21 | 0 | 20 | KJØL T | 26.6 | 26.6 | 2091.8
Stålrør normaltykke | Nivå D | ORIGINAL | Hydronic Return | +TI=370.001 R | 2091.85 | 21 | 0 | 20 | KJØL R | 26.6 | 26.6 | 2091.8
Stålrør normaltykke | Nivå D | ORIGINAL | Hydronic Return | +TI=370.001 R | 5312.15 | 21 | 0 | 20 | KJØL R | 26.6 | 26.6 | 5312.1
Stålrør normaltykke | Nivå D | ORIGINAL | Hydronic Supply | +TI=370.001 T | 5412.15 | 21 | 0 | 20 | KJØL T | 26.6 | 26.6 | 5412.2
Stålrør normaltykke | Nivå D | ORIGINAL | Hydronic Supply | +TI=370.001 T | 114.2 | 21 | 0 | 20 | KJØL T | 26.6 | 26.6 | 114
Stålrør normaltykke | Nivå D | ORIGINAL | Hydronic Return | +TI=370.001 R | 113.996 | 21 | 0 | 20 | KJØL R | 26.6 | 26.6 | 114
Stålrør normaltykke | Nivå F | ORIGINAL | Undefined |  | 76.684 | 21 | 0 | 20 | Undefined | 26.6 | 26.6 | 76.9
Stålrør normaltykke | Nivå F | ORIGINAL | Undefined |  | 8.054 | 21 | 0 | 20 | Undefined | 26.6 | 26.6 | 7.6
Stålrør normaltykke | Nivå F | ORIGINAL | Undefined |  | 89.641 | 21 | 0 | 20 | Undefined | 26.6 | 26.6 | 89.6
Stålrør normaltykke | Nivå F | ORIGINAL | Undefined |  | 13.774 | 21 | 0 | 20 | Undefined | 26.6 | 26.6 | 13.8
Stålrør normaltykke | Nivå F | ORIGINAL | Undefined |  | 762.811 | 21 | 0 | 20 | Undefined | 26.6 | 26.6 | 762.8
Stålrør normaltykke | Nivå F | ORIGINAL | Hydronic Supply | +TI=370.001 T | 1071.69 | 21 | 0 | 20 | KJØL T | 26.6 | 26.6 | 1071.7
Stålrør normaltykke | Nivå F | ORIGINAL | Hydronic Return | +TI=370.001 R | 140 | 21 | 0 | 20 | KJØL R | 26.6 | 26.6 | 140.3
Stålrør normaltykke | Nivå F | ORIGINAL | Hydronic Supply | 37= T 9° Kopi 1 | 58.4 | 21 | 0 | 20 | KJØL T | 26.6 | 26.6 | 57.7
Stålrør normaltykke | Nivå F | ORIGINAL | Hydronic Supply | 37= T 9° Kopi 1 | 133.2 | 21 | 0 | 20 | KJØL T | 26.6 | 26.6 | 133.4
Stålrør normaltykke | Nivå F | ORIGINAL | Hydronic Supply | 37= T 9° Kopi 1 | 21.4 | 21 | 0 | 20 | KJØL T | 26.6 | 26.6 | 20.6
Stålrør normaltykke | Nivå F | ORIGINAL | Hydronic Supply | 37= T 9° Kopi 1 | 291.4 | 21 | 0 | 20 | KJØL T | 26.6 | 26.6 | 291.4
Stålrør normaltykke | Nivå F | ORIGINAL | Hydronic Supply | 37= T 9° Kopi 1 | 142.875 | 21 | 0 | 20 | KJØL T | 26.6 | 26.6 | 142.8
Stålrør normaltykke | Nivå F | ORIGINAL | Hydronic Return | 37= R 18° Kopi 1 | 103.2 | 21 | 0 | 20 | KJØL R | 26.6 | 26.6 | 103.2
Stålrør normaltykke | Nivå F | ORIGINAL | Hydronic Return | 37= R 18° Kopi 1 | 211.4 | 21 | 0 | 20 | KJØL R | 26.6 | 26.6 | 210.9
Stålrør normaltykke | Nivå F | ORIGINAL | Hydronic Return | 37= R 18° Kopi 1 | 299.6 | 21 | 0 | 20 | KJØL R | 26.6 | 26.6 | 299.5
Stålrør normaltykke | Nivå F | ORIGINAL | Hydronic Return | 37= R 18° Kopi 1 | 31.4 | 21 | 0 | 20 | KJØL R | 26.6 | 26.6 | 30.8
Stålrør normaltykke | Nivå F | ORIGINAL | Hydronic Return | 37= R 18° Kopi 1 | 106.4 | 21 | 0 | 20 | KJØL R | 26.7 | 20 | 142.044
Stålrør normaltykke | Nivå F | ORIGINAL | Hydronic Return | 37= R 18° Kopi 1 | 38.2 | 21 | 0 | 20 | KJØL R | 26.6 | 26.6 | 38.2
Stålrør normaltykke | Nivå F | ORIGINAL | Fire Protection Wet | +TI=332.001-NZ0003 | 84.476 | 0 | 0 | 25 | Sprinkel | 33.8 | 33.8 | 84.4
Stålrør normaltykke | Nivå F | ORIGINAL | Fire Protection Wet | +TI=332.001-NZ0003 | 138.277 | 0 | 0 | 25 | Sprinkel | 33.8 | 33.8 | 138.2
2 x Stålrør normaltykke | Nivå F | ORIGINAL | Fire Protection Wet | +TI=332.001-NZ0003 | 191.848 | 0 | 0 | 25 | Sprinkel | 33.8 | 33.8 | 191.5
Stålrør normaltykke | Nivå F | ORIGINAL | Fire Protection Wet | +TI=332.001-NZ0003 | 39.5 | 0 | 0 | 15 | Sprinkel | 21.4 | 21.4 | 39.5
Stålrør normaltykke | Nivå F | ORIGINAL | Fire Protection Wet | +TI=332.001-NZ0003 | 56.848 | 0 | 0 | 25 | Sprinkel | 33.8 | 33.8 | 56.9
Stålrør normaltykke | Nivå F | ORIGINAL | Fire Protection Wet | +TI=332.001-NZ0003 | 176.848 | 0 | 0 | 25 | Sprinkel | 33.8 | 33.8 | 176.9
Stålrør normaltykke | Nivå F | ORIGINAL | Fire Protection Wet | +TI=332.001-NZ0003 | 40 | 0 | 0 | 15 | Sprinkel | 21.4 | 21.4 | 39.5
Stålrør normaltykke | Nivå F | ORIGINAL | Fire Protection Wet | +TI=332.001-NZ0003 | 108.762 | 0 | 0 | 25 | Sprinkel | 33.8 | 33.8 | 108.8
Stålrør normaltykke | Nivå F | ORIGINAL | Fire Protection Wet | +TI=332.001-NZ0003 | 490.536 | 0 | 0 | 32 | Sprinkel | 42.4 | 42.4 | 490.3
Stålrør normaltykke | Nivå F | ORIGINAL | Fire Protection Wet | +TI=332.001-NZ0003 | 37 | 0 | 0 | 40 | Sprinkel | 48.2 | 48.2 | 37
Stålrør normaltykke | Nivå F | ORIGINAL | Fire Protection Wet | +TI=332.001-NZ0003 | 203.2 | 0 | 0 | 40 | Sprinkel | 48.2 | 48.2 | 203.2
Stålrør normaltykke | Nivå F | ORIGINAL | Fire Protection Wet | +TI=332.001-NZ0003 | 293.2 | 0 | 0 | 40 | Sprinkel | 48.2 | 48.2 | 293.2
Stålrør normaltykke | Nivå F | ORIGINAL | Fire Protection Wet | +TI=332.001-NZ0003 | 1199.4 | 0 | 0 | 40 | Sprinkel | 48.2 | 48.2 | 1199.4
Stålrør normaltykke | Nivå F | ORIGINAL | Fire Protection Wet | +TI=332.001-NZ0003 | 471.308 | 0 | 0 | 25 | Sprinkel | 33.8 | 33.8 | 470.8
Stålrør normaltykke | Nivå F | ORIGINAL | Fire Protection Wet | +TI=332.001-NZ0003 | 273.808 | 0 | 0 | 40 | Sprinkel | 48.2 | 48.2 | 273.8
Stålrør normaltykke | Nivå F | ORIGINAL | Fire Protection Wet | +TI=332.001-NZ0003 | 206.174 | 0 | 0 | 25 | Sprinkel | 33.8 | 33.8 | 205.8
Stålrør normaltykke | Nivå F | ORIGINAL | Fire Protection Wet | +TI=332.001-NZ0003 | 1555.59 | 0 | 0 | 50 | Sprinkel | 60.2 | 60.2 | 1555.6
Stålrør normaltykke | Nivå F | ORIGINAL | Fire Protection Wet | +TI=332.001-NZ0003 | 28.319 | 0 | 0 | 25 | Sprinkel | 28.3 | 33.8 | 33.8
Stålrør normaltykke | Nivå F | ORIGINAL | Fire Protection Wet | +TI=332.001-NZ0003 | 101.672 | 0 | 0 | 25 | Sprinkel | 33.8 | 33.8 | 102.4
Stålrør normaltykke | Nivå F | ORIGINAL | Fire Protection Wet | +TI=332.001-NZ0003 | 531.326 | 0 | 0 | 32 | Sprinkel | 42.4 | 42.4 | 530.8
Stålrør normaltykke | Nivå F | ORIGINAL | Fire Protection Wet | +TI=332.001-NZ0003 | 682.477 | 0 | 0 | 80 | Sprinkel | 89 | 89 | 682.5
Stålrør normaltykke | Nivå F | ORIGINAL | Fire Protection Wet | +TI=332.001-NZ0003 | 2024.09 | 0 | 0 | 40 | Sprinkel | 48.2 | 48.2 | 2024.1
Stålrør normaltykke | Nivå F | ORIGINAL | Fire Protection Wet | +TI=332.001-NZ0003 | 10 | 0 | 0 | 50 | Sprinkel | 60.2 | 60.2 | 10.4
Stålrør normaltykke | Nivå F | ORIGINAL | Fire Protection Wet | +TI=332.001-NZ0003 | 668.483 | 0 | 0 | 80 | Sprinkel | 89 | 89 | 668.5
Stålrør normaltykke | Nivå F | ORIGINAL | Fire Protection Wet | +TI=332.001-NZ0003 | 704.633 | 0 | 0 | 25 | Sprinkel | 33.8 | 33.8 | 704.6
Stålrør normaltykke | Nivå F | ORIGINAL | Fire Protection Wet | +TI=332.001-NZ0003 | 1102.08 | 0 | 0 | 65 | Sprinkel | 76 | 76 | 1102.1
Stålrør normaltykke | Nivå F | ORIGINAL | Fire Protection Wet | +TI=332.001-NZ0003 | 430.072 | 0 | 0 | 25 | Sprinkel | 33.8 | 33.8 | 429.5
Stålrør normaltykke | Nivå F | ORIGINAL | Fire Protection Wet | +TI=332.001-NZ0003 | 717.614 | 0 | 0 | 50 | Sprinkel | 60.2 | 60.2 | 717.6
Stålrør normaltykke | Nivå F | ORIGINAL | Fire Protection Wet | +TI=332.001-NZ0003 | 722.067 | 0 | 0 | 50 | Sprinkel | 60.2 | 60.2 | 722.1
4 x Stålrør normaltykke | Nivå F | ORIGINAL | Fire Protection Wet | +TI=332.001-NZ0003 | 9.193 | 0 | 0 | 25 | Sprinkel | 9.3 | 33.8 | 33.8
Stålrør normaltykke | Nivå F | ORIGINAL | Fire Protection Wet | +TI=332.001-NZ0003 | 162.011 | 0 | 0 | 25 | Sprinkel | 33.8 | 33.8 | 162.5
Stålrør normaltykke | Nivå F | ORIGINAL | Fire Protection Wet | +TI=332.001-NZ0003 | 118.85 | 0 | 0 | 40 | Sprinkel | 48.2 | 48.2 | 119.1
Stålrør normaltykke | Nivå F | ORIGINAL | Fire Protection Wet | +TI=332.001-NZ0003 | 129.619 | 0 | 0 | 25 | Sprinkel | 33.8 | 33.8 | 129.9
Stålrør normaltykke | Nivå F | ORIGINAL | Fire Protection Wet | +TI=332.001-NZ0003 | 140.85 | 0 | 0 | 65 | Sprinkel | 76 | 76 | 140.9
Stålrør normaltykke | Nivå F | ORIGINAL | Fire Protection Wet | +TI=332.001-NZ0003 | 581.729 | 0 | 0 | 25 | Sprinkel | 33.8 | 33.8 | 582.3
Stålrør normaltykke | Nivå F | ORIGINAL | Fire Protection Wet | +TI=332.001-NZ0003 | 9.278 | 0 | 0 | 25 | Sprinkel | 9.3 | 33.8 | 33.8
Stålrør normaltykke | Nivå F | ORIGINAL | Fire Protection Wet | +TI=332.001-NZ0003 | 454.229 | 0 | 0 | 25 | Sprinkel | 33.8 | 33.8 | 454
Stålrør normaltykke | Nivå F | ORIGINAL | Fire Protection Wet | +TI=332.001-NZ0003 | 9.136 | 0 | 0 | 25 | Sprinkel | 9.3 | 33.8 | 33.8
Stålrør normaltykke | Nivå F | ORIGINAL | Fire Protection Wet | +TI=332.001-NZ0003 | 568.918 | 0 | 0 | 25 | Sprinkel | 33.8 | 33.8 | 569
Stålrør normaltykke | Nivå F | ORIGINAL | Fire Protection Wet | +TI=332.001-NZ0003 | 170.21 | 0 | 0 | 25 | Sprinkel | 33.8 | 33.8 | 170.2
Stålrør normaltykke | Nivå F | ORIGINAL | Fire Protection Wet | +TI=332.001-NZ0003 | 143.783 | 0 | 0 | 25 | Sprinkel | 33.8 | 33.8 | 143.9
Stålrør normaltykke | Nivå F | ORIGINAL | Fire Protection Wet | +TI=332.001-NZ0003 | 602.076 | 0 | 0 | 25 | Sprinkel | 33.8 | 33.8 | 601.8
Stålrør normaltykke | Nivå F | ORIGINAL | Fire Protection Wet | +TI=332.001-NZ0003 | 44.75 | 0 | 0 | 15 | Sprinkel | 21.4 | 21.4 | 44.8
Stålrør normaltykke | Nivå F | ORIGINAL | Fire Protection Wet | +TI=332.001-NZ0003 | 84.748 | 0 | 0 | 15 | Sprinkel | 21.4 | 21.4 | 84.7
Stålrør normaltykke | Nivå F | ORIGINAL | Fire Protection Wet | +TI=332.001-NZ0003 | 23.824 | 0 | 0 | 15 | Sprinkel | 21.4 | 21.4 | 23.8
Stålrør normaltykke | Nivå F | ORIGINAL | Fire Protection Wet | +TI=332.001-NZ0003 | 166.032 | 0 | 0 | 25 | Sprinkel | 33.8 | 33.8 | 165.6
Stålrør normaltykke | Nivå F | ORIGINAL | Fire Protection Wet | +TI=332.001-NZ0003 | 10.816 | 0 | 0 | 15 | Sprinkel | 10.8 | 21.4 | 21.4
Stålrør normaltykke | Nivå F | ORIGINAL | Fire Protection Wet | +TI=332.001-NZ0003 | 14.5 | 0 | 0 | 15 | Sprinkel | 13.8 | 21.4 | 21.4
Stålrør normaltykke | Nivå F | ORIGINAL | Fire Protection Wet | +TI=332.001-NZ0003 | 137.75 | 0 | 0 | 25 | Sprinkel | 33.8 | 33.8 | 138.2
Stålrør normaltykke | Nivå F | ORIGINAL | Fire Protection Wet | +TI=332.001-NZ0003 | 411.675 | 0 | 0 | 25 | Sprinkel | 33.8 | 33.8 | 411.9
Stålrør normaltykke | Nivå F | ORIGINAL | Fire Protection Wet | +TI=332.001-NZ0003 | 879.6 | 0 | 0 | 50 | Sprinkel | 60.2 | 60.2 | 879.6
Stålrør normaltykke | Nivå F | ORIGINAL | Fire Protection Wet | +TI=332.001-NZ0003 | 439.2 | 0 | 0 | 50 | Sprinkel | 60.2 | 60.2 | 439.2
Stålrør normaltykke | Nivå F | ORIGINAL | Fire Protection Wet | +TI=332.001-NZ0003 | 718.896 | 0 | 0 | 50 | Sprinkel | 60.2 | 60.2 | 718.9
Stålrør normaltykke | Nivå F | ORIGINAL | Fire Protection Wet | +TI=332.001-NZ0003 | 339.2 | 0 | 0 | 50 | Sprinkel | 60.2 | 60.2 | 338.7
Stålrør normaltykke | Nivå F | ORIGINAL | Fire Protection Wet | +TI=332.001-NZ0003 | 200.85 | 0 | 0 | 25 | Sprinkel | 33.8 | 33.8 | 201.1
Stålrør normaltykke | Nivå F | ORIGINAL | Fire Protection Wet | +TI=332.001-NZ0003 | 1194.96 | 0 | 0 | 40 | Sprinkel | 48.2 | 48.2 | 1195
Stålrør normaltykke | Nivå F | ORIGINAL | Fire Protection Wet | +TI=332.001-NZ0003 | 183.098 | 0 | 0 | 25 | Sprinkel | 33.8 | 33.8 | 182.7
Stålrør normaltykke | Nivå F | ORIGINAL | Fire Protection Wet | +TI=332.001-NZ0003 | 42.6 | 0 | 0 | 25 | Sprinkel | 33.8 | 33.8 | 42.7
Stålrør normaltykke | Nivå F | ORIGINAL | Fire Protection Wet | +TI=332.001-NZ0003 | 191.473 | 0 | 0 | 25 | Sprinkel | 33.8 | 33.8 | 191.5
Stålrør normaltykke | Nivå F | ORIGINAL | Fire Protection Wet | +TI=332.001-NZ0003 | 56.3 | 0 | 0 | 25 | Sprinkel | 33.8 | 33.8 | 56
Stålrør normaltykke | Nivå F | ORIGINAL | Fire Protection Wet | +TI=332.001-NZ0003 | 94.53 | 0 | 0 | 32 | Sprinkel | 42.4 | 42.4 | 94.5
Stålrør normaltykke | Nivå F | ORIGINAL | Fire Protection Wet | +TI=332.001-NZ0003 | 318.37 | 0 | 0 | 32 | Sprinkel | 42.4 | 42.4 | 318.5
Stålrør normaltykke | Nivå F | ORIGINAL | Fire Protection Wet | +TI=332.001-NZ0003 | 31.3 | 0 | 0 | 32 | Sprinkel | 42.4 | 42.4 | 31.4
Stålrør normaltykke | Nivå F | ORIGINAL | Fire Protection Wet | +TI=332.001-NZ0003 | 34.416 | 0 | 0 | 32 | Sprinkel | 33.5 | 42.4 | 42.4
Stålrør normaltykke | Nivå F | ORIGINAL | Fire Protection Wet | +TI=332.001-NZ0003 | 1014.26 | 0 | 0 | 32 | Sprinkel | 42.4 | 42.4 | 1014.3
Stålrør normaltykke | Nivå F | ORIGINAL | Fire Protection Wet | +TI=332.001-NZ0003 | 68.8 | 0 | 0 | 32 | Sprinkel | 42.4 | 42.4 | 69.1
Stålrør normaltykke | Nivå F | ORIGINAL | Fire Protection Wet | +TI=332.001-NZ0003 | 272.546 | 0 | 0 | 25 | Sprinkel | 33.8 | 33.8 | 271.6
Stålrør normaltykke | Nivå F | ORIGINAL | Fire Protection Wet | +TI=332.001-NZ0003 | 61.3 | 0 | 0 | 32 | Sprinkel | 42.4 | 42.4 | 61.3
Stålrør normaltykke | Nivå F | ORIGINAL | Fire Protection Wet | +TI=332.001-NZ0003 | 223.7 | 0 | 0 | 25 | Sprinkel | 33.8 | 33.8 | 223.8
Stålrør normaltykke | Nivå F | ORIGINAL | Fire Protection Wet | +TI=332.001-NZ0003 | 1976.98 | 0 | 0 | 32 | Sprinkel | 42.4 | 42.4 | 1977
Stålrør normaltykke | Nivå F | ORIGINAL | Fire Protection Wet | +TI=332.001-NZ0003 | 76.4 | 0 | 0 | 25 | Sprinkel | 33.8 | 33.8 | 76.3
Stålrør normaltykke | Nivå F | ORIGINAL | Fire Protection Wet | +TI=332.001-NZ0003 | 43.65 | 0 | 0 | 25 | Sprinkel | 33.8 | 33.8 | 43.7
Stålrør normaltykke | Nivå F | ORIGINAL | Fire Protection Wet | +TI=332.001-NZ0003 | 1108.42 | 0 | 0 | 50 | Sprinkel | 60.2 | 60.2 | 1108.4
Stålrør normaltykke | Nivå F | ORIGINAL | Fire Protection Wet | +TI=332.001-NZ0003 | 798.654 | 0 | 0 | 50 | Sprinkel | 60.2 | 60.2 | 798.7
Stålrør normaltykke | Nivå F | ORIGINAL | Fire Protection Wet | +TI=332.001-NZ0003 | 111.991 | 0 | 0 | 32 | Sprinkel | 42.4 | 42.4 | 112.5
Stålrør normaltykke | Nivå F | ORIGINAL | Fire Protection Wet | +TI=332.001-NZ0003 | 236.2 | 0 | 0 | 25 | Sprinkel | 33.8 | 33.8 | 235.8
Stålrør normaltykke | Nivå F | ORIGINAL | Fire Protection Wet | +TI=332.001-NZ0003 | 1554.51 | 0 | 0 | 25 | Sprinkel | 33.8 | 33.8 | 1554.5
Stålrør normaltykke | Nivå F | ORIGINAL | Fire Protection Wet | +TI=332.001-NZ0003 | 441.397 | 0 | 0 | 25 | Sprinkel | 33.8 | 33.8 | 440.8
2 x Stålrør normaltykke | Nivå F | ORIGINAL | Fire Protection Wet | +TI=332.001-NZ0003 | 48.8 | 0 | 0 | 25 | Sprinkel | 33.8 | 33.8 | 48.8
Stålrør normaltykke | Nivå F | ORIGINAL | Fire Protection Wet | +TI=332.001-NZ0003 | 398.902 | 0 | 0 | 25 | Sprinkel | 33.8 | 33.8 | 398.8
Stålrør normaltykke | Nivå F | ORIGINAL | Fire Protection Wet | +TI=332.001-NZ0003 | 49.9 | 0 | 0 | 25 | Sprinkel | 33.8 | 33.8 | 50.1
Stålrør normaltykke | Nivå F | ORIGINAL | Fire Protection Wet | +TI=332.001-NZ0003 | 3.867 | 0 | 0 | 40 | Sprinkel | 48.2 | 48.2 | 3.7
Stålrør normaltykke | Nivå F | ORIGINAL | Fire Protection Wet | +TI=332.001-NZ0003 | 67.75 | 0 | 0 | 25 | Sprinkel | 33.8 | 33.8 | 67.8
Stålrør normaltykke | Nivå F | ORIGINAL | Fire Protection Wet | +TI=332.001-NZ0003 | 196.15 | 0 | 0 | 25 | Sprinkel | 33.8 | 33.8 | 195.7
Stålrør normaltykke | Nivå F | ORIGINAL | Fire Protection Wet | +TI=332.001-NZ0003 | 81.498 | 0 | 0 | 25 | Sprinkel | 33.8 | 33.8 | 82.4
Stålrør normaltykke | Nivå F | ORIGINAL | Fire Protection Wet | +TI=332.001-NZ0003 | 153.65 | 0 | 0 | 25 | Sprinkel | 33.8 | 33.8 | 153.8
Stålrør normaltykke | Nivå F | ORIGINAL | Fire Protection Wet | +TI=332.001-NZ0003 | 668.538 | 0 | 0 | 25 | Sprinkel | 33.8 | 33.8 | 668
Stålrør normaltykke | Nivå F | ORIGINAL | Fire Protection Wet | +TI=332.001-NZ0003 | 55.52 | 0 | 0 | 50 | Sprinkel | 60.2 | 60.2 | 55.5
Stålrør normaltykke | Nivå F | ORIGINAL | Fire Protection Wet | +TI=332.001-NZ0003 | 5.4 | 0 | 0 | 25 | Sprinkel | 5.4 | 33.8 | 33.8
Stålrør normaltykke | Nivå F | ORIGINAL | Fire Protection Wet | +TI=332.001-NZ0003 | 397.4 | 0 | 0 | 25 | Sprinkel | 33.8 | 33.8 | 396.8
Stålrør normaltykke | Nivå F | ORIGINAL | Fire Protection Wet | +TI=332.001-NZ0003 | 501.348 | 0 | 0 | 25 | Sprinkel | 33.8 | 33.8 | 500.9
Stålrør normaltykke | Nivå F | ORIGINAL | Fire Protection Wet | +TI=332.001-NZ0003 | 1144.6 | 0 | 0 | 25 | Sprinkel | 33.8 | 33.8 | 1145.2
Stålrør normaltykke | Nivå F | ORIGINAL | Fire Protection Wet | +TI=332.001-NZ0003 | 25.4 | 0 | 0 | 32 | Sprinkel | 42.4 | 42.4 | 24.6
Stålrør normaltykke | Nivå F | ORIGINAL | Fire Protection Wet | +TI=332.001-NZ0003 | 147.4 | 0 | 0 | 25 | Sprinkel | 33.8 | 33.8 | 147.3
Stålrør normaltykke | Nivå F | ORIGINAL | Fire Protection Wet | +TI=332.001-NZ0003 | 74.2 | 0 | 0 | 25 | Sprinkel | 33.8 | 33.8 | 73.8
Stålrør normaltykke | Nivå F | ORIGINAL | Fire Protection Wet | +TI=332.001-NZ0003 | 1642.01 | 0 | 0 | 25 | Sprinkel | 33.8 | 33.8 | 1642
Stålrør normaltykke | Nivå F | ORIGINAL | Fire Protection Wet | +TI=332.001-NZ0003 | 386.491 | 0 | 0 | 25 | Sprinkel | 33.8 | 33.8 | 385.8
Stålrør normaltykke | Nivå D | ORIGINAL | Fire Protection Wet | +TI=332.001-NZ0005 | 1603.2 | 0 | 0 | 40 | Sprinkel | 48.2 | 48.2 | 1603.2
4 x Stålrør normaltykke | Nivå D | ORIGINAL | Fire Protection Wet | +TI=332.001-NZ0006 | 96.748 | 0 | 0 | 15 | Sprinkel | 21.4 | 21.4 | 96.7
Stålrør normaltykke | Nivå D | ORIGINAL | Fire Protection Wet | +TI=332.001-NZ0006 | 1802.28 | 0 | 0 | 40 | Sprinkel | 48.2 | 48.2 | 1801.9
2 x Stålrør normaltykke | Nivå D | ORIGINAL | Fire Protection Wet | +TI=332.001-NZ0006 | 84.348 | 0 | 0 | 25 | Sprinkel | 33.8 | 33.8 | 84.4
2 x Stålrør normaltykke | Nivå D | ORIGINAL | Fire Protection Wet | +TI=332.001-NZ0006 | 3544.8 | 0 | 0 | 40 | Sprinkel | 48.2 | 48.2 | 3544.8
2 x Stålrør normaltykke | Nivå D | ORIGINAL | Fire Protection Wet | +TI=332.001-NZ0006 | 964.678 | 0 | 0 | 40 | Sprinkel | 48.2 | 48.2 | 964.7
3 x Stålrør normaltykke | Nivå D | ORIGINAL | Fire Protection Wet | +TI=332.001-NZ0006 | 95.022 | 0 | 0 | 25 | Sprinkel | 33.8 | 33.8 | 95
2 x Stålrør normaltykke | Nivå D | ORIGINAL | Fire Protection Wet | +TI=332.001-NZ0006 | 3532.4 | 0 | 0 | 40 | Sprinkel | 48.2 | 48.2 | 3532.4
Stålrør normaltykke | Nivå D | ORIGINAL | Fire Protection Wet | +TI=332.001-NZ0006 | 952.278 | 0 | 0 | 40 | Sprinkel | 48.2 | 48.2 | 952
Stålrør normaltykke | Nivå D | ORIGINAL | Fire Protection Wet | +TI=332.001-NZ0006 | 3557.2 | 0 | 0 | 40 | Sprinkel | 48.2 | 48.2 | 3557.4
2 x Stålrør normaltykke | Nivå D | ORIGINAL | Fire Protection Wet | +TI=332.001-NZ0006 | 103.074 | 0 | 0 | 40 | Sprinkel | 48.2 | 48.2 | 103.1
Stålrør normaltykke | Nivå D | ORIGINAL | Fire Protection Wet | +TI=332.001-NZ0006 | 393.393 | 0 | 0 | 100 | Sprinkel | 114.2 | 114.2 | 393.4
2 x Stålrør normaltykke | Nivå D | ORIGINAL | Fire Protection Wet | +TI=332.001-NZ0006 | 2903.2 | 0 | 0 | 100 | Sprinkel | 114.2 | 114.2 | 2903.2
Stålrør normaltykke | Nivå D | ORIGINAL | Fire Protection Wet | +TI=332.001-NZ0006 | 92.4 | 0 | 0 | 40 | Sprinkel | 48.2 | 48.2 | 91.6
Stålrør normaltykke | Nivå D | ORIGINAL | Fire Protection Wet | +TI=332.001-NZ0005 | 1109.02 | 0 | 0 | 40 | Sprinkel | 48.2 | 48.2 | 1109
Stålrør normaltykke | Nivå D | ORIGINAL | Fire Protection Wet | +TI=332.001-NZ0005 | 2066.12 | 0 | 0 | 40 | Sprinkel | 48.2 | 48.2 | 2066.1
Stålrør normaltykke | Nivå D | ORIGINAL | Fire Protection Wet | +TI=332.001-NZ0005 | 84.179 | 0 | 0 | 25 | Sprinkel | 33.8 | 33.8 | 84.4
Stålrør normaltykke | Nivå D | ORIGINAL | Fire Protection Wet | +TI=332.001-NZ0006 | 1634.12 | 0 | 0 | 40 | Sprinkel | 48.2 | 48.2 | 1634.1
Stålrør normaltykke | Nivå F -0,7 | ORIGINAL | Fire Protection Wet | +TI=332.001-NZ0003 | 168.7 | 0 | 0 | 25 | Sprinkel | 33.8 | 33.8 | 168.8
Stålrør normaltykke | Nivå C | RESULT | Fire Protection Other | +TI=330.003 B-1 |  |  |  |  | BRANNVANN TRYKK | 114 | 114 | 934
Stålrør normaltykke | Nivå D | RESULT | Hydronic Supply | 32= T 55° Kopi 1 |  |  |  |  | GULVVARME T | 34 | 34 | 5312
Stålrør normaltykke | Nivå D | RESULT | Hydronic Return | +TI=323.002 R-1 |  |  |  |  | GULVVARME R | 34 | 34 | 4889
Stålrør normaltykke | Nivå D + 1,2 m | RESULT | Hydronic Supply | +TI=320.001 T |  |  |  |  | VARME T | 34 | 34 | 9790
Stålrør normaltykke | Nivå F | RESULT | Fire Protection Wet | +TI=332.001-NZ0003 |  |  |  |  | Sprinkel | 88 | 88 | 551
Stålrør normaltykke | Nivå D | RESULT | Hydronic Supply | +TI=322.004 T |  |  |  |  | SHUNTET VARME T | 48 | 48 | 6277
Stålrør normaltykke | Nivå D | RESULT | Hydronic Return | +TI=322.004 R |  |  |  |  | SHUNTET VARME R | 48 | 48 | 10704
Stålrør normaltykke | Nivå D | RESULT | Fire Protection Wet | +TI=332.001-NZ0005 |  |  |  |  | Sprinkel | 60 | 60 | 8423
Stålrør normaltykke | Nivå D | RESULT | Hydronic Return | +TI=370.001 R |  |  |  |  | KJØL R | 42 | 42 | 653
Stålrør normaltykke | Nivå D | RESULT | Hydronic Supply | +TI=370.001 T |  |  |  |  | KJØL T | 42 | 42 | 653
3 x Stålrør normaltykke | Nivå D | RESULT | Fire Protection Wet | +TI=332.001-NZ0006 |  |  |  |  | Sprinkel | 48 | 48 | 2966
Stålrør normaltykke | Nivå D | RESULT | Fire Protection Wet | +TI=332.001-NZ0006 |  |  |  |  | Sprinkel | 60 | 116 | 1754

# IfcFlowSegment: Super-MA (10)
In: Nivå D
Type - PredefinedType: RIGIDSEGMENT
Classification: UB2.1115131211 Not defined (NS3420)
ePset_Simplebim - Assembly Level: Leaf
MagiCAD Pset_Pipe - User Code: Super-MA; Material: MA; NationalCode: UB2.1115131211
Name | Splitting | MagiCAD Pset_Water, dpTot_SizingFlow_kPa (Pa) = MagiCAD Pset_Water, pTot_SizingFlow_kPa (Pa) = MagiCAD Pset_Water, v_SizingFlow_ms (m/s) = MagiCAD Pset_Heating, v_SizingFlow_ms (m/s) = MagiCAD Pset_Heating, pTot_SizingFlow_kPa (Pa) = MagiCAD Pset_Heating, dpTot_SizingFlow_kPa (Pa) = Insulation_thickness_mm (mm) = qv_SizingFlow_ls (m3/s) | SystemType | SystemName = Group | SystemClass | Length_mm (mm) | ConnectionSize_mm (mm) | Length (Simplebim) (mm) | Height (Simplebim) (mm) | Width (Simplebim) (mm)
Super-MA | ORIGINAL | 0 | SPV FETT | +TI=313.403 | Sanitary | 677.281 | 110 | 676.7 | 110 | 110
Super-MA | ORIGINAL | 0 | SPV FETT | +TI=313.403 | Sanitary | 242.238 | 110 | 241.8 | 110 | 110
Super-MA | ORIGINAL | 0 | SPV FETT | +TI=313.403 | Sanitary | 353.444 | 110 | 353.4 | 110 | 110
Super-MA | ORIGINAL | 0 | SPV FETT | +TI=313.403 | Sanitary | 538.6 | 110 | 538.9 | 110 | 110
Super-MA | ORIGINAL | 0 | SPV FETT | +TI=313.403 | Sanitary | 238.959 | 75 | 239 | 75 | 75
Super-MA | ORIGINAL | 0 | SPV FETT | +TI=313.403 | Sanitary | 5570.14 | 110 | 5570.1 | 110 | 110
Super-MA | ORIGINAL | 0 | Undefined |  | Undefined | 40 | 75 | 75 | 40 | 75
Super-MA | ORIGINAL | 0 | Undefined |  | Undefined | 97.77 | 58 | 97.8 | 58 | 58
Super-MA | ORIGINAL | 0 | SPV FETT | +TI=313.403 | Sanitary | 373.382 | 75 | 372.6 | 75 | 75
Super-MA | RESULT |  | SPV FETT | +TI=313.403 | Sanitary |  |  | 4505 | 110 | 110

# IfcFlowSegment: Trekkerør, glatt (7)
In: Nivå F
Type - PredefinedType: CONDUITSEGMENT
ePset_LocationTool - Splitting: RESULT
ePset_Simplebim - Assembly Level: Leaf
ePset_SimplebimBasicQuantities - Height (Simplebim): 50 mm
MagiCAD Pset_Conduit - System code: 4110
Group: Trekkerør generelt
Name | Width (Simplebim) (mm) | Length (Simplebim) (mm)
Trekkerør, glatt | 50 | 1547
Trekkerør, glatt | 50 | 1559
Trekkerør, glatt | 50 | 1560
2 x Trekkerør, glatt | 50 | 1546
Trekkerør, glatt | 50 | 1539
Trekkerør, glatt | 25 | 1560

# IfcFlowSegment: Trekkerør, korrugert (137)
In: Nivå F
Type - PredefinedType: CONDUITSEGMENT
MagiCAD Pset_Conduit - System code: 4110
ePset_Simplebim - Assembly Level: Leaf
Group: Trekkerør generelt
Name | NominalWidth (mm) = NominalHeight (mm) = Diameter [mm] (mm) | NominalLength (mm) = Length [mm] (mm) | Length (Simplebim) (mm) | Height (Simplebim) (mm) | Width (Simplebim) (mm) | Splitting
3 x Trekkerør, korrugert | 20 | 96.612 | 96.6 | 20 | 20 | ORIGINAL
Trekkerør, korrugert | 20 | 897.452 | 897.5 | 20 | 20 | ORIGINAL
2 x Trekkerør, korrugert | 20 | 95.063 | 95.1 | 20 | 20 | ORIGINAL
2 x Trekkerør, korrugert | 20 | 33.512 | 33.5 | 20 | 20 | ORIGINAL
Trekkerør, korrugert | 20 | 200.444 | 200.4 | 20 | 20 | ORIGINAL
Trekkerør, korrugert | 20 | 64.62 | 64.6 | 20 | 20 | ORIGINAL
Trekkerør, korrugert | 25 | 5924.11 | 5924.1 | 25 | 25 | ORIGINAL
Trekkerør, korrugert | 25 | 727.09 | 726.7 | 25 | 25 | ORIGINAL
3 x Trekkerør, korrugert | 25 | 432.923 | 432.9 | 25 | 25 | ORIGINAL
Trekkerør, korrugert | 25 | 706.379 | 705.5 | 25 | 25 | ORIGINAL
Trekkerør, korrugert | 25 | 685.668 | 685.7 | 25 | 25 | ORIGINAL
3 x Trekkerør, korrugert | 25 | 3253.97 | 3254 | 25 | 25 | ORIGINAL
Trekkerør, korrugert | 25 | 577.984 | 577.5 | 25 | 25 | ORIGINAL
Trekkerør, korrugert | 25 | 436.638 | 436.6 | 25 | 25 | ORIGINAL
Trekkerør, korrugert | 25 | 619.405 | 618.9 | 25 | 25 | ORIGINAL
Trekkerør, korrugert | 25 | 457.348 | 456.6 | 25 | 25 | ORIGINAL
Trekkerør, korrugert | 25 | 660.827 | 661.1 | 25 | 25 | ORIGINAL
Trekkerør, korrugert | 25 | 478.059 | 478.1 | 25 | 25 | ORIGINAL
3 x Trekkerør, korrugert | 25 | 2266.1 | 2266.1 | 25 | 25 | ORIGINAL
Trekkerør, korrugert | 25 | 702.248 | 702.4 | 25 | 25 | ORIGINAL
Trekkerør, korrugert | 25 | 498.77 | 499.3 | 25 | 25 | ORIGINAL
Trekkerør, korrugert | 25 | 743.67 | 743.7 | 25 | 25 | ORIGINAL
Trekkerør, korrugert | 25 | 519.481 | 520.5 | 25 | 25 | ORIGINAL
Trekkerør, korrugert | 25 | 785.091 | 785 | 25 | 25 | ORIGINAL
Trekkerør, korrugert | 25 | 540.191 | 539.8 | 25 | 25 | ORIGINAL
Trekkerør, korrugert | 25 | 2188.68 | 2188.7 | 25 | 25 | ORIGINAL
3 x Trekkerør, korrugert | 25 | 1278.23 | 1278.2 | 25 | 25 | ORIGINAL
Trekkerør, korrugert | 25 | 826.512 | 826.4 | 25 | 25 | ORIGINAL
Trekkerør, korrugert | 25 | 560.902 | 560.9 | 25 | 25 | ORIGINAL
Trekkerør, korrugert | 25 | 2147.26 | 2147.4 | 25 | 25 | ORIGINAL
Trekkerør, korrugert | 25 | 867.934 | 867.8 | 25 | 25 | ORIGINAL
Trekkerør, korrugert | 25 | 581.613 | 581.6 | 25 | 25 | ORIGINAL
Trekkerør, korrugert | 25 | 2105.84 | 2105.8 | 25 | 25 | ORIGINAL
Trekkerør, korrugert | 25 | 909.355 | 909.4 | 25 | 25 | ORIGINAL
Trekkerør, korrugert | 25 | 602.323 | 601.9 | 25 | 25 | ORIGINAL
Trekkerør, korrugert | 25 | 700.207 | 699.6 | 25 | 25 | ORIGINAL
3 x Trekkerør, korrugert | 25 | 1917.85 | 1918 | 25 | 25 | ORIGINAL
Trekkerør, korrugert | 25 | 623.034 | 622.6 | 25 | 25 | ORIGINAL
Trekkerør, korrugert | 25 | 658.786 | 658.8 | 25 | 25 | ORIGINAL
Trekkerør, korrugert | 25 | 643.745 | 644.3 | 25 | 25 | ORIGINAL
Trekkerør, korrugert | 25 | 617.365 | 617.3 | 25 | 25 | ORIGINAL
Trekkerør, korrugert | 25 | 664.455 | 664 | 25 | 25 | ORIGINAL
Trekkerør, korrugert | 25 | 488.075 | 488.1 | 25 | 25 | ORIGINAL
Trekkerør, korrugert | 25 | 446.654 | 446.7 | 25 | 25 | ORIGINAL
Trekkerør, korrugert | 25 | 405.233 | 405.2 | 25 | 25 | ORIGINAL
Trekkerør, korrugert | 25 | 275.943 | 275.9 | 25 | 25 | ORIGINAL
Trekkerør, korrugert | 25 | 234.522 | 234.5 | 25 | 25 | ORIGINAL
Trekkerør, korrugert | 25 | 193.1 | 193.1 | 25 | 25 | ORIGINAL
Trekkerør, korrugert | 25 | 639.259 | 639.3 | 25 | 25 | ORIGINAL
3 x Trekkerør, korrugert | 25 | 1296.25 | 1296.2 | 25 | 25 | ORIGINAL
Trekkerør, korrugert | 25 | 680.68 | 680.7 | 25 | 25 | ORIGINAL
Trekkerør, korrugert | 25 | 722.102 | 722.1 | 25 | 25 | ORIGINAL
Trekkerør, korrugert | 25 | 544.67 | 544.7 | 25 | 25 | ORIGINAL
2 x Trekkerør, korrugert | 25 | 283.842 | 283.8 | 25 | 25 | ORIGINAL
Trekkerør, korrugert | 25 | 503.249 | 503.2 | 25 | 25 | ORIGINAL
Trekkerør, korrugert | 25 | 461.447 | 461.4 | 25 | 25 | ORIGINAL
Trekkerør, korrugert | 25 | 284.111 | 283.8 | 25 | 25 | ORIGINAL
Trekkerør, korrugert | 25 | 566.904 | 566.9 | 25 | 25 | ORIGINAL
Trekkerør, korrugert | 25 | 444.473 | 444.5 | 25 | 25 | ORIGINAL
Trekkerør, korrugert | 25 | 691.168 | 691.2 | 25 | 25 | ORIGINAL
Trekkerør, korrugert | 25 | 506.605 | 507 | 25 | 25 | ORIGINAL
Trekkerør, korrugert | 25 | 608.325 | 608 | 25 | 25 | ORIGINAL
Trekkerør, korrugert | 25 | 465.183 | 465.2 | 25 | 25 | ORIGINAL
Trekkerør, korrugert | 25 | 649.747 | 650.5 | 25 | 25 | ORIGINAL
Trekkerør, korrugert | 25 | 485.894 | 486.3 | 25 | 25 | ORIGINAL
Trekkerør, korrugert | 25 | 732.59 | 732.6 | 25 | 25 | ORIGINAL
Trekkerør, korrugert | 25 | 527.315 | 527.1 | 25 | 25 | ORIGINAL
Trekkerør, korrugert | 25 | 774.011 | 774 | 25 | 25 | ORIGINAL
Trekkerør, korrugert | 25 | 548.026 | 548.4 | 25 | 25 | ORIGINAL
3 x Trekkerør, korrugert | 25 | 644.375 | 644.3 | 25 | 25 | ORIGINAL
Trekkerør, korrugert | 25 | 610.158 | 610.2 | 25 | 25 | ORIGINAL
Trekkerør, korrugert | 25 | 589.447 | 589.3 | 25 | 25 | ORIGINAL
Trekkerør, korrugert | 25 | 568.737 | 569.2 | 25 | 25 | ORIGINAL
Trekkerør, korrugert | 25 | 340 | 340.4 | 25 | 25 | ORIGINAL
Trekkerør, korrugert |  |  | 8123 | 24 | 24 | RESULT
Trekkerør, korrugert |  |  | 8453 | 24 | 24 | RESULT
Trekkerør, korrugert |  |  | 8473 | 24 | 24 | RESULT
Trekkerør, korrugert |  |  | 8932 | 24 | 24 | RESULT
Trekkerør, korrugert |  |  | 8973 | 24 | 24 | RESULT
Trekkerør, korrugert |  |  | 8952 | 24 | 24 | RESULT
Trekkerør, korrugert |  |  | 8432 | 24 | 24 | RESULT
Trekkerør, korrugert |  |  | 8956 | 24 | 24 | RESULT
Trekkerør, korrugert |  |  | 8977 | 24 | 24 | RESULT
Trekkerør, korrugert |  |  | 8998 | 24 | 24 | RESULT
Trekkerør, korrugert |  |  | 7969 | 24 | 24 | RESULT
Trekkerør, korrugert |  |  | 7990 | 24 | 24 | RESULT
Trekkerør, korrugert |  |  | 8011 | 24 | 24 | RESULT
Trekkerør, korrugert |  |  | 6141 | 24 | 24 | RESULT
Trekkerør, korrugert |  |  | 6171 | 24 | 24 | RESULT
Trekkerør, korrugert |  |  | 6200 | 24 | 25 | RESULT
Trekkerør, korrugert |  |  | 4744 | 24 | 24 | RESULT
Trekkerør, korrugert |  |  | 4774 | 24 | 25 | RESULT
Trekkerør, korrugert |  |  | 4803 | 26 | 24 | RESULT
Trekkerør, korrugert |  |  | 3347 | 26 | 24 | RESULT
Trekkerør, korrugert |  |  | 3377 | 24 | 24 | RESULT
Trekkerør, korrugert |  |  | 3406 | 24 | 24 | RESULT
3 x Trekkerør, korrugert |  |  | 8505 | 24 | 24 | RESULT
2 x Trekkerør, korrugert |  |  | 8484 | 24 | 24 | RESULT
2 x Trekkerør, korrugert |  |  | 8464 | 24 | 24 | RESULT
Trekkerør, korrugert |  |  | 8485 | 24 | 24 | RESULT
Trekkerør, korrugert |  |  | 8463 | 24 | 24 | RESULT
Trekkerør, korrugert |  |  | 8931 | 24 | 24 | RESULT
Trekkerør, korrugert |  |  | 8911 | 24 | 24 | RESULT
Trekkerør, korrugert |  |  | 8890 | 24 | 24 | RESULT
Trekkerør, korrugert |  |  | 7902 | 24 | 24 | RESULT
Trekkerør, korrugert |  |  | 7943 | 24 | 24 | RESULT
Trekkerør, korrugert |  |  | 6956 | 24 | 24 | RESULT
Trekkerør, korrugert |  |  | 6935 | 24 | 24 | RESULT
Trekkerør, korrugert |  |  | 6914 | 24 | 24 | RESULT
Trekkerør, korrugert |  |  | 7923 | 24 | 24 | RESULT
Trekkerør, korrugert |  |  | 5926 | 24 | 24 | RESULT
Trekkerør, korrugert |  |  | 5947 | 24 | 24 | RESULT
Trekkerør, korrugert |  |  | 5968 | 24 | 24 | RESULT
Trekkerør, korrugert |  |  | 446 | 20 | 20 | RESULT

# IfcFlowTerminal: BLP-K115-141C-STD (2)
In: Nivå F
Type - Description: Standard Response bulb thermal element, K=115
MagiCAD Pset_Sprinkler - KFactor: 115; Nominal Release Temperature [°C]: 141; Product code: BLP-K115-141C-STD; Description: Standard Response bulb thermal element, K=115; Manufacturer: Generic China
ePset_Simplebim - Assembly Level: Leaf
ePset_LocationTool - Splitting: ORIGINAL
Group: +TI=332.001-NZ0003

# IfcFlowTerminal: BRTR-600-600 (2)
Type - Description: Wire mesh grilles, rectangular
ePset_LocationTool - Splitting: ORIGINAL
ePset_Simplebim - Assembly Level: Leaf
MagiCAD Pset_AirTerminal - User Code: AS053T; Manufacturer: Bevent Rasch; ProductCode: BRTR-600-600; dpTot_SizingFlow_Pa: 0 Pa; qv_SizingFlow_ms: 0 m/s; Description: Wire mesh grilles, rectangular; ConnectionSize_mm: 600; qv_SizingFlow_ls: 194.444 m3/s
Group: 36 Tilluft
Name | In
BRTR-600-600 | Nivå F
BRTR-600-600 | Nivå F - 0,7 m

# IfcFlowTerminal: CU/P-15-K80-68DGR-QR (3)
In: Nivå F
Type - Description: Conventional, upright and pendent installation, QR, K=80
MagiCAD Pset_Sprinkler - Description: Conventional, upright and pendent installation, QR, K=80; Manufacturer: General; KFactor: 80; Nominal Release Temperature [°C]: 68; User Code: CUP01; Product code: CU/P-15-K80-68DGR-QR
ePset_LocationTool - Splitting: ORIGINAL
ePset_Simplebim - Assembly Level: Leaf
Group: +TI=332.001-NZ0003

# IfcFlowTerminal: IB3223 Zumtobel Thorn MICA SLIM I 9L90 ACC 8D 840 RS SF (3)
In: Nivå F
Type - Description: Lysarmatur LED innfelt i gulv
MagiCAD Pset_Device - Switchboard: +TI=433.625; Active Power: 27.3 W; System code: 442; Circuit order no: 41; User code: IB3223; Length [mm]: 0 mm; Width [mm]: 0 mm; Height [mm]: 0 mm; Number of Poles: 1; Installation Code: 2; Manufacturer: General; Power Factor: 1; Voltage: 230
Pset_ElectricalDeviceCommon - ElectricalDeviceNominalPower: 27.3 W; NumberOfPoles: 1; NominalVoltage: 230
ePset_Simplebim - Assembly Level: Leaf
ePset_LocationTool - Splitting: ORIGINAL
Pset_LightFixtureTypeCommon - TotalWattage: 27.3 W
Group: Belysningsutstyr

# IfcFlowTerminal: IB5301 Zumtobel Craft 140W LED840 L330 PM WB LDO WH (7)
In: Nivå D + 1,2 m
Type - Description: Lysarmatur LED Rektangulær Utenpåliggende Teknisk
MagiCAD Pset_Device - Switchboard: +TI=433.623; System code: 442; Manufacturer: Zumtobel; Active Power: 0 W; Length [mm]: 0 mm; Width [mm]: 0 mm; Height [mm]: 0 mm; Number of Poles: 0; Power Factor: 0; Voltage: 0; Installation Code: 3; User code: IB5301
ePset_LocationTool - Splitting: ORIGINAL
Pset_LightFixtureTypeCommon - TotalWattage: 0 W
ePset_Simplebim - Assembly Level: Leaf
Pset_ElectricalDeviceCommon - ElectricalDeviceNominalPower: 0 W; NumberOfPoles: 0; NominalVoltage: 0
Group: Belysningsutstyr
Name | Circuit order no
3 x IB5301 Zumtobel Craft 140W LED840 L330 PM WB LDO WH | 15
2 x IB5301 Zumtobel Craft 140W LED840 L330 PM WB LDO WH | 13
IB5301 Zumtobel Craft 140W LED840 L330 PM WB LDO WH | 14
IB5301 Zumtobel Craft 140W LED840 L330 PM WB LDO WH | 16

# IfcFlowTerminal: IB5306 Zumtobel TECTON A SGL L1463 53W LED840 WB LDE WH
In: Nivå F
Type - Description: Lysarmatur LED Lineær Utenpåliggende Teknisk
MagiCAD Pset_Device - Switchboard: +TI=433.625; Circuit order no: 34; System code: 442; Manufacturer: Zumtobel; Active Power: 0 W; Length [mm]: 0 mm; Width [mm]: 0 mm; Height [mm]: 0 mm; Number of Poles: 0; Power Factor: 0; Voltage: 0; Installation Code: 3; User code: IB5306
ePset_LocationTool - Splitting: ORIGINAL
Pset_LightFixtureTypeCommon - TotalWattage: 0 W
ePset_Simplebim - Assembly Level: Leaf
Pset_ElectricalDeviceCommon - ElectricalDeviceNominalPower: 0 W; NumberOfPoles: 0; NominalVoltage: 0
Group: Belysningsutstyr

# IfcFlowTerminal: IB5347 Zumtobel Perluce O LED3800-840 L1220 LDE IP54 WH (Vertikal)
In: Nivå H
Type - Description: Lysarmatur LED Lineær Utenpåliggende Teknisk
Pset_LightFixtureTypeCommon - TotalWattage: 0 W
ePset_Simplebim - Assembly Level: Leaf
Pset_ElectricalDeviceCommon - ElectricalDeviceNominalPower: 0 W; NumberOfPoles: 0; NominalVoltage: 0
ePset_LocationTool - Splitting: ORIGINAL
MagiCAD Pset_Device - System code: 442; User code: IB5347; Active Power: 0 W; Length [mm]: 0 mm; Width [mm]: 0 mm; Height [mm]: 0 mm; Number of Poles: 0; Power Factor: 0; Voltage: 0; Installation Code: 3
Group: Belysningsutstyr

# IfcFlowTerminal: IB5384 Zumtobel RRL L1500 LED2700 830-60 NB LDE
In: Nivå F
Type - Description: Lysarmatur LED Lineær List Utenpåliggende Slepelys teknisk sjakt
MagiCAD Pset_Device - User code: IB5384; Switchboard: +TI=433.625; System code: 442; Number of Poles: 0; Power Factor: 0; Installation Code: 3; Circuit order no: 35
ePset_Simplebim - Assembly Level: Leaf
Pset_ElectricalDeviceCommon - NumberOfPoles: 0
ePset_LocationTool - Splitting: RESULT
Group: Belysningsutstyr

# IfcFlowTerminal: IB7333 Zumtobel Puresign 150 AW NDA
In: Nivå F
Type - Description: Markeringslys ensidig 30 meter leseavstand vegg
MagiCAD Pset_Device - System code: 443; Manufacturer: Zumtobel; Switchboard: +TI=443.421; Length [mm]: 0 mm; Width [mm]: 0 mm; Height [mm]: 0 mm; Number of Poles: 1; User code: IB7333; Circuit order no: 3; Installation Code: 3; Power Factor: 1; Active Power: 4.5 W; Voltage: 230
ePset_Simplebim - Assembly Level: Leaf
Pset_ElectricalDeviceCommon - NumberOfPoles: 1; ElectricalDeviceNominalPower: 4.5 W; NominalVoltage: 230
Pset_LightFixtureTypeCommon - TotalWattage: 4.5 W
ePset_LocationTool - Splitting: ORIGINAL
Group: Utstyr for nødlys

# IfcFlowTerminal: IB7334 Zumtobel Puresign/Consign 150 ASI NDA (2)
In: Nivå F
Type - Description: Markeringslys ensidig 30 meter leseavstand wire
MagiCAD Pset_Device - User code: IB7334; System code: 443; Manufacturer: Zumtobel; Switchboard: +TI=443.421; Length [mm]: 0 mm; Width [mm]: 0 mm; Height [mm]: 0 mm; Number of Poles: 1; Power Factor: 1; Active Power: 4.5 W; Voltage: 230; Installation Code: 13
ePset_Simplebim - Assembly Level: Leaf
ePset_LocationTool - Splitting: ORIGINAL
Pset_ElectricalDeviceCommon - NumberOfPoles: 1; ElectricalDeviceNominalPower: 4.5 W; NominalVoltage: 230
Pset_LightFixtureTypeCommon - TotalWattage: 4.5 W
Group: Utstyr for nødlys
Name | Circuit order no
IB7334 Zumtobel Puresign/Consign 150 ASI NDA | 3
IB7334 Zumtobel Puresign/Consign 150 ASI NDA | 6

# IfcFlowTerminal: IB7405 Zumtobel Resclite C Antipanic ED NDA WH (2)
In: Nivå F
Type - Description: Ledelys innfelt i himling
Pset_LightFixtureTypeCommon - TotalWattage: 6 W
ePset_LocationTool - Splitting: ORIGINAL
ePset_Simplebim - Assembly Level: Leaf
Pset_ElectricalDeviceCommon - NumberOfPoles: 1; ElectricalDeviceNominalPower: 6 W; NominalVoltage: 230
MagiCAD Pset_Device - System code: 443; Product code: Resclite C Antipanic ED NDA WH; Manufacturer: Zumtobel; Switchboard: +TI=443.421; Length [mm]: 0 mm; Width [mm]: 0 mm; Height [mm]: 0 mm; Number of Poles: 1; Installation Code: 2; Power Factor: 1; Active Power: 6 W; Voltage: 230; User code: IB7405
Group: Utstyr for nødlys
Name | Circuit order no
IB7405 Zumtobel Resclite C Antipanic ED NDA WH | 6
IB7405 Zumtobel Resclite C Antipanic ED NDA WH | 3

# IfcFlowTerminal: Industrial 407-110B 300x300
In: Nivå F
Type - Description: Floor drain, industrial. Medium/heavy duty. Tiles waterproof
ePset_Simplebim - Assembly Level: Leaf
ePset_LocationTool - Splitting: ORIGINAL
MagiCAD Pset_DrainageDevices - Manufacturer: Blucher; ConnectionSize_mm: 0 mm; User Code: Rsluk110; Product Code: BM NO. 774.473.110 IND 407-110B 300x300 Vertical; Description: Floor drain, industrial. Medium/heavy duty. Tiles waterproof
Group: +TI=313.403

# IfcFlowTerminal: Jordet-topolet-2-veis-Påvegg
In: Nivå F
Type - Description: Jordet topolet 2-veis Påvegg Horizontal; PredefinedType: POWEROUTLET
Pset_ElectricalDeviceCommon - ElectricalDeviceNominalPower: 0 W; NumberOfPoles: 1; NominalVoltage: 230
MagiCAD Pset_Device - Switchboard: +TI=433.625; Active Power: 0 W; Length [mm]: 0 mm; Width [mm]: 0 mm; Height [mm]: 0 mm; Number of Poles: 1; Circuit order no: 4; Installation Code: 4; P1: -UE; Power Factor: 1; Voltage: 230; System code: 463
ePset_Simplebim - Assembly Level: Leaf
Pset_OutletTypeCommon - IsPluggableOutlet: yes
ePset_LocationTool - Splitting: ORIGINAL
Group: Utstyr for virksomhet

# IfcFlowTerminal: KSO 160
In: Nivå F
Type - Description: Exhaust diffusor.
ePset_LocationTool - Splitting: ORIGINAL
MagiCAD Pset_AirTerminal - Manufacturer: TROX Auranor; dpTot_SizingFlow_Pa: 0 Pa; qv_SizingFlow_ms: 0 m/s; ProductCode: KSO-160; qv_SizingFlow_ls: 60 m3/s; ConnectionSize_mm: 160; Description: Exhaust diffusor.
ePset_Simplebim - Assembly Level: Leaf
Group: 36= A Kopi 21

# IfcFlowTerminal: SP-15-K80-68DGR-STD (2)
In: Nivå F
Type - Description: Spray, pendent installation, STD, K=80
MagiCAD Pset_Sprinkler - User Code: HIMLING; Product code: SP-15-K80-68DGR-STD; Description: Spray, pendent installation, STD, K=80; Manufacturer: General; KFactor: 80; Nominal Release Temperature [°C]: 68
ePset_LocationTool - Splitting: ORIGINAL
ePset_Simplebim - Assembly Level: Leaf
Group: +TI=332.001-NZ0003

# IfcFlowTerminal: SP-15-K80-68DGR-STD-HIMLING (11)
Type - Description: Spray, pendent installation, STD, K=80
MagiCAD Pset_Sprinkler - User Code: HIMLING; Product code: SP-15-K80-68DGR-STD; Description: Spray, pendent installation, STD, K=80; Manufacturer: General; KFactor: 80; Nominal Release Temperature [°C]: 68
ePset_LocationTool - Splitting: ORIGINAL
ePset_Simplebim - Assembly Level: Leaf
Group: +TI=332.001-NZ0003
Name | In
10 x SP-15-K80-68DGR-STD-HIMLING | Nivå F
SP-15-K80-68DGR-STD-HIMLING | Nivå F -0,7

# IfcFlowTerminal: SP-15-K80-68DGR-STD-STÅENDE (10)
In: Nivå D
Type - Description: Spray, pendent installation, STD, K=80
Classification: RS1.3000121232 Not defined (NS3420)
ePset_LocationTool - Splitting: ORIGINAL
MagiCAD Pset_Sprinkler - User Code: UZ03T; NationalCode: RS1.3000121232; Product code: SP-15-K80-68DGR-STD; Description: Spray, pendent installation, STD, K=80; Manufacturer: General; KFactor: 80; Nominal Release Temperature [°C]: 68
ePset_Simplebim - Assembly Level: Leaf
Name | Group
9 x SP-15-K80-68DGR-STD-STÅENDE | +TI=332.001-NZ0006
SP-15-K80-68DGR-STD-STÅENDE | +TI=332.001-NZ0005

# IfcFlowTerminal: SU-20-K115-68DGR-STD (6)
In: Nivå F
Type - Description: Spray, upright installation, STD, K=115
ePset_Simplebim - Assembly Level: Leaf
ePset_LocationTool - Splitting: ORIGINAL
MagiCAD Pset_Sprinkler - Product code: SU-20-K115-68DGR-STD; Manufacturer: Generic; Nominal Release Temperature [°C]: 68; KFactor: 115; User Code: HODE 3/4"; Description: Spray, upright installation, STD, K=115
Group: +TI=332.001-NZ0003

# IfcFurnishingElement: A272 - Basis boks:A272 - Basis boks, A272 - Basis boks:A272 - Basis boks:59292115
In: Nivå F
Type - Material: <Unnamed>
Pset_QuantityTakeOff - Reference: A272 - Basis boks
ePset_Simplebim - Assembly Level: Leaf
ePset_LocationTool - Splitting: ORIGINAL
AVINOR - 08_Status: S4; 07_Fase: F90; 05_ID-nummer: +TI=241.052; 06_Omrade: TI; 03_Ansvar: 72717; 02_Prosjekt: T20100; 01_Lufthavnkode: ENGM

# IfcMember: HEB320, STÅLSØYLE
In: F
Description: HEB320; Material: STEEL/S355
Tekla Quantity - WEIGTH_NET: 83.1951 kg; VOLUME_NET: 0.0106 m3; Length: 769.694 mm; VOLUME_GROSS: 0.01242 m3; Heigth: 320 mm; Width: 300 mm; AREA_GROSS: 1.36313 m2; AREA_NET: 1.27397 m2; WEIGTH_GROSS: 97.4591 kg
ePset_LocationTool - Splitting: ORIGINAL
Pset_MemberCommon - LoadBearing: no; Reference: DSS-0(?)
Tekla Common - Grade: S355; Top elevation: +211.312; Assembly mark: SS-0(?); Class: 320; Name: STÅLSØYLE; Part mark: DSS-0(?); Bottom elevation: +210.655; Profile: HEB320
AVINOR - 07_Fase: F40; 08_Status: S1; 06_Omrade: TI; 05_ID-nummer: +TI=222.007; 04_Kontrakt: 72245; 03_Ansvar: 72245; 02_Prosjekt: T20100; 01_Lufthavnkode: ENGM
ePset_SimplebimBasicQuantities - Weight, as steel (Simplebim): 83.1951 kg; Volume, net (Simplebim): 0.0105981 m3; Height (Simplebim): 769.694 mm; Area, sides, net (Simplebim): 1.27397 m2; Length (Simplebim): 320 mm; Width (Simplebim): 300 mm
ePset_Simplebim - Assembly Level: Leaf

# IfcMember: PL20*820 (2)
In: F
Description: PL20*820
ePset_SimplebimBasicQuantities - Width (Simplebim): 20 mm
Tekla Common - Top elevation: +211.311; Grade: S355; Bottom elevation: +211.020; Assembly mark: SS-0(?); Class: 320; Name: STÅLSØYLE; Part mark: DSS-0(?); Profile: PL20*820
Pset_MemberCommon - LoadBearing: no; Reference: DSS-0(?)
AVINOR - 07_Fase: F40; 08_Status: S1; 06_Omrade: TI; 05_ID-nummer: +TI=222.007; 04_Kontrakt: 72245; 03_Ansvar: 72245; 02_Prosjekt: T20100; 01_Lufthavnkode: ENGM
ePset_Simplebim - Assembly Level: Leaf
Name | Weight, as steel (Simplebim) (kg) | Area, sides, net (Simplebim) (m2) | Volume, net (Simplebim) (m3) | Length (Simplebim) (mm) | Height (Simplebim) (mm) | Splitting
STÅLSØYLE | 38.2049 | 0.531357 | 0.00486686 | 820 | 296.76 | ORIGINAL | Material: STEEL/S355; Tekla Quantity - AREA_NET: 0.53136 m2; AREA_GROSS: 0.53136 m2; VOLUME_GROSS: 0.00487 m3; VOLUME_NET: 0.00487 m3; WEIGTH_NET: 38.2049 kg; WEIGTH_GROSS: 38.2049 kg; Width: 20 mm; Heigth: 820 mm; Length: 296.76 mm
STÅLSØYLE | 19.0913 | 0.271462 | 0.00243201 | 410 | 297 | RESULT

# IfcMember: RHS80*8 (4)
In: F
Description: RHS80*8; Material: STEEL/S355J2H
Pset_MemberCommon - LoadBearing: no
Tekla Quantity - Width: 80 mm; Heigth: 80 mm
ePset_SimplebimBasicQuantities - Length (Simplebim): 80 mm; Width (Simplebim): 80 mm
Tekla Common - Profile: RHS80*8; Grade: S355J2H; Name: STÅLDIAGONAL; Class: 331
ePset_Simplebim - Assembly Level: Leaf
ePset_LocationTool - Splitting: ORIGINAL
AVINOR - 08_Status: S4; 07_Fase: F90; 06_Omrade: TI; 04_Kontrakt: 72717; 02_Prosjekt: T20100; 05_ID-nummer: +TI=221.041; 03_Ansvar: 72101; 01_Lufthavnkode: ENGM
Name | Reference = Part mark | VOLUME_GROSS (m3) | WEIGTH_NET (kg) = Weight, as steel (Simplebim) (kg) | AREA_GROSS (m2) | WEIGTH_GROSS (kg) | AREA_NET (m2) | VOLUME_NET (m3) | Length (mm) = Height (Simplebim) (mm) | Area, sides, net (Simplebim) (m2) | Volume, net (Simplebim) (m3) | Bottom elevation | Top elevation | Assembly mark
STÅLDIAGONAL | DSD-1417(?) | 0.00693 | 54.2968 | 0.96574 | 54.4224 | 0.9653 | 0.00692 | 3037.86 | 1.73754 | 0.00691678 | +210.895 | +213.359 | SD-787(?)
STÅLDIAGONAL | DSD-1418(?) | 0.00623 | 48.7268 | 0.86707 | 48.8524 | 0.86663 | 0.00621 | 2722.66 | 1.55993 | 0.00620723 | +210.895 | +213.291 | SD-788(?)
STÅLDIAGONAL | DSD-1419 | 0.00696 | 54.4042 | 0.96957 | 54.6554 | 0.96868 | 0.00692 | 3021.91 | 1.74363 | 0.00693048 | +210.988 | +213.482 | SD-786(?)
STÅLDIAGONAL | DSD-1424(?) | 0.00685 | 49.2792 | 0.95248 | 53.6892 | 0.87755 | 0.00629 | 2867.54 | 1.57959 | 0.0062776 | +210.899 | +213.560 | SS-7783(?)

# IfcMember: Rectangular Mullion:A241 - 10 mm fuge (2)
In: Nivå F
Type - PredefinedType: MULLION; Material: Fuge transparent
ePset_SimplebimBasicQuantities - Width (Simplebim): 20 mm; Height (Simplebim): 10 mm
Pset_QuantityTakeOff - Reference: A241 - 10 mm fuge
ePset_Simplebim - Assembly Level: Leaf
Pset_MemberCommon - Reference: A241 - 10 mm fuge; IsExternal: no
AVINOR - 03_Ansvar: 72253; 08_Status: S4; 07_Fase: F90; 06_Omrade: TI; 02_Prosjekt: T20100; 01_Lufthavnkode: ENGM
Name (Rectangular Mullion:A241 - 10 mm fuge:...) | Length (Simplebim) (mm) | Weight, as steel (Simplebim) (kg) | Volume, net (Simplebim) (m3) | Area, sides, net (Simplebim) (m2) | Splitting | 05_ID-nummer
61214909 | 823.003 | 1.29212 | 0.000164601 | 0.0497802 | ORIGINAL | +TI=245.002 | Pset_MemberCommon - Span: 823.003 mm
62371183 | 557 | 0.87372 | 0.000111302 | 0.0337906 | RESULT | +TI=245.003

# IfcMember: Rectangular Mullion:A241 - 4 mm fuge - til venstre, Rectangular Mullion:A241 - 4 mm fuge - til venstre:44969103
In: Nivå F
Type - PredefinedType: MULLION; Material: Fuge transparent
Pset_QuantityTakeOff - Reference: A241 - 4 mm fuge - til venstre
ePset_SimplebimBasicQuantities - Volume, net (Simplebim): 0.000006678 m3; Area, sides, net (Simplebim): 0.007815 m2; Weight, as steel (Simplebim): 0.0524223 kg; Width (Simplebim): 3 mm; Height (Simplebim): 4 mm; Length (Simplebim): 557 mm
ePset_LocationTool - Splitting: RESULT
ePset_Simplebim - Assembly Level: Leaf
Pset_MemberCommon - Reference: A241 - 4 mm fuge - til venstre; IsExternal: no
AVINOR - 03_Ansvar: 72253; 08_Status: S4; 07_Fase: F90; 05_ID-nummer: +TI=245.003; 06_Omrade: TI; 02_Prosjekt: T20100; 01_Lufthavnkode: ENGM

# IfcPlate: PL10*125 (9)
In: F
Description: PL10*125; Material: STEEL/S355
Tekla Quantity - AREA_GROSS: 0.01563 m2; Length: 125.002 mm; WEIGTH_GROSS: 1.22659 kg; VOLUME_GROSS: 0.00009 m3; VOLUME_NET: 0.00009 m3; AREA_NET: 0.02461 m2; WEIGTH_NET: 0.79385 kg; Width: 10 mm; Heigth: 125 mm
AVINOR - 08_Status: S4; 07_Fase: F40; 06_Omrade: TI; 05_ID-nummer: +TI=223.008; 03_Ansvar: 72242; 04_Kontrakt: 72242; 02_Prosjekt: T20100; 01_Lufthavnkode: ENGM
ePset_LocationTool - Splitting: ORIGINAL
Pset_PlateCommon - LoadBearing: no; Reference: DSB-17265(?)
ePset_Simplebim - Assembly Level: Leaf
Tekla Common - Assembly mark: SB-10284(?); Grade: S355; Name: STÅLBJELKE; Top elevation: +210.805; Profile: PL10*125; Part mark: DSB-17265(?); Bottom elevation: +210.680; Class: 330
ePset_SimplebimBasicQuantities - Area, largest surface, net (Simplebim): 0.0101127 m2; Volume, net (Simplebim): 0.000101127 m3; Weight, as steel (Simplebim): 0.79385 kg

# IfcPlate: PL15*350 (6)
In: F
Description: PL15*350; Material: STEEL/S355
Pset_PlateCommon - Reference: DSB-12181; LoadBearing: no
ePset_LocationTool - Splitting: ORIGINAL
Tekla Common - Grade: S355; Assembly mark: SB-6984; Profile: PL15*350; Name: STÅLBJELKE; Bottom elevation: +210.115; Part mark: DSB-12181; Class: 330; Top elevation: +210.655
AVINOR - 08_Status: S4; 07_Fase: F40; 06_Omrade: TI; 05_ID-nummer: +TI=223.008; 03_Ansvar: 72242; 04_Kontrakt: 72242; 02_Prosjekt: T20100; 01_Lufthavnkode: ENGM
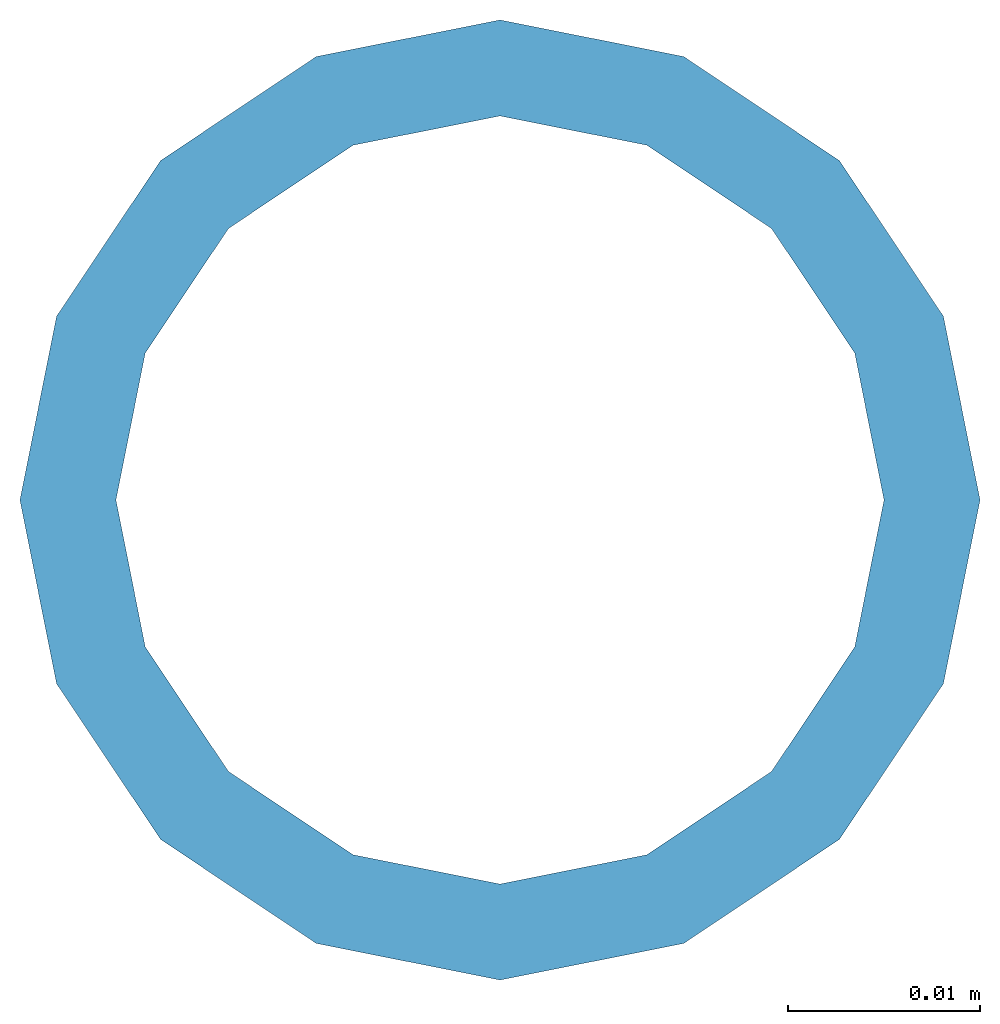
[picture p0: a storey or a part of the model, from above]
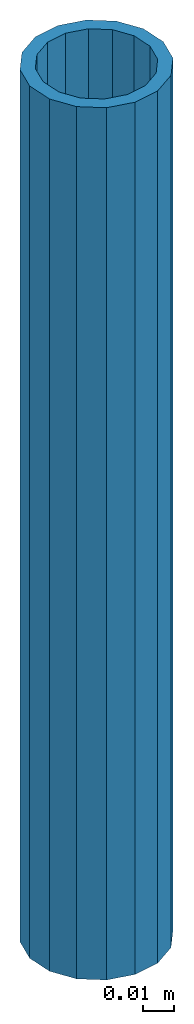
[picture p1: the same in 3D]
Properties of the parts of a building model (IFC2X3), part 6 of 6

# IfcPlate: PL15*350 (6)
ePset_SimplebimBasicQuantities - Volume, net (Simplebim): 0.00199676 m3; Weight, as steel (Simplebim): 15.6746 kg; Area, largest surface, net (Simplebim): 0.133117 m2
ePset_Simplebim - Assembly Level: Leaf
Tekla Quantity - WEIGTH_GROSS: 22.2248 kg; Length: 540.002 mm; Heigth: 349.527 mm; WEIGTH_NET: 15.6746 kg; AREA_NET: 0.2904 m2; VOLUME_GROSS: 0.002 m3; VOLUME_NET: 0.002 m3; AREA_GROSS: 0.18875 m2; Width: 15 mm

# IfcPlate: PL15*440, STÅLBJELKE
In: F
Description: PL15*440; Material: STEEL/S355
AVINOR - 08_Status: S4; 07_Fase: F40; 06_Omrade: TI; 05_ID-nummer: +TI=223.008; 03_Ansvar: 72242; 04_Kontrakt: 72242; 02_Prosjekt: T20100; 01_Lufthavnkode: ENGM
Pset_PlateCommon - Reference: DSB-10107; LoadBearing: no
ePset_Simplebim - Assembly Level: Leaf
ePset_SimplebimBasicQuantities - Weight, as steel (Simplebim): 30.5679 kg; Volume, net (Simplebim): 0.003894 m3; Area, largest surface, net (Simplebim): 0.2596 m2
Tekla Quantity - WEIGTH_NET: 30.5679 kg; WEIGTH_GROSS: 30.5679 kg; VOLUME_NET: 0.00389 m3; VOLUME_GROSS: 0.00389 m3; Width: 15 mm; Heigth: 440 mm; Length: 590 mm; AREA_GROSS: 0.2596 m2; AREA_NET: 0.5501 m2
Tekla Common - Grade: S355; Profile: PL15*440; Assembly mark: SB-5317; Name: STÅLBJELKE; Part mark: DSB-10107; Bottom elevation: +210.165; Class: 330; Top elevation: +210.605
ePset_LocationTool - Splitting: ORIGINAL

# IfcPlate: PL20*340 (3)
In: F
Description: PL20*340; Material: STEEL/S355
ePset_SimplebimBasicQuantities - Area, largest surface, net (Simplebim): 0.1649 m2; Weight, as steel (Simplebim): 25.8893 kg; Volume, net (Simplebim): 0.003298 m3
Tekla Common - Grade: S355; Name: STÅLBJELKE; Assembly mark: SB-7670; Bottom elevation: +210.140; Part mark: DSB-13300; Profile: PL20*340; Class: 330; Top elevation: +210.625
AVINOR - 08_Status: S4; 07_Fase: F40; 06_Omrade: TI; 05_ID-nummer: +TI=223.008; 03_Ansvar: 72242; 04_Kontrakt: 72242; 02_Prosjekt: T20100; 01_Lufthavnkode: ENGM
ePset_LocationTool - Splitting: ORIGINAL
Pset_PlateCommon - Reference: DSB-13300; LoadBearing: no
ePset_Simplebim - Assembly Level: Leaf
Tekla Quantity - VOLUME_NET: 0.0033 m3; VOLUME_GROSS: 0.0033 m3; Width: 20 mm; Heigth: 340 mm; Length: 485 mm; AREA_NET: 0.3628 m2; AREA_GROSS: 0.1649 m2; WEIGTH_GROSS: 25.8893 kg; WEIGTH_NET: 25.8893 kg

# IfcPlate: PL20*683 (2)
In: F
Description: PL20*683
Tekla Common - Grade: S355; Assembly mark: SS-0(?); Class: 320; Top elevation: +211.317; Profile: PL20*683; Name: STÅLSØYLE; Part mark: DSS-0(?); Bottom elevation: +210.655
Pset_PlateCommon - LoadBearing: no; Reference: DSS-0(?)
AVINOR - 07_Fase: F40; 08_Status: S1; 06_Omrade: TI; 05_ID-nummer: +TI=222.007; 03_Ansvar: 72245; 04_Kontrakt: 72245; 02_Prosjekt: T20100; 01_Lufthavnkode: ENGM
ePset_Simplebim - Assembly Level: Leaf
Name | Area, largest surface, net (Simplebim) (m2) | Weight, as steel (Simplebim) (kg) | Volume, net (Simplebim) (m3) | Splitting
STÅLSØYLE | 0.362391 | 56.8954 | 0.00724782 | ORIGINAL | Material: STEEL/S355; Tekla Quantity - VOLUME_NET: 0.00724 m3; VOLUME_GROSS: 0.00724 m3; AREA_NET: 0.78491 m2; Heigth: 683.374 mm; WEIGTH_GROSS: 87.9776 kg; AREA_GROSS: 0.56037 m2; WEIGTH_NET: 56.8954 kg; Width: 20 mm; Length: 820 mm
STÅLSØYLE | 0.181024 | 28.4208 | 0.00362049 | RESULT

# IfcPlate: PL30*500, INNSTØPNGODS
In: F
Description: PL30*500; Material: STEEL/S355
Tekla Quantity - VOLUME_GROSS: 0.00749 m3; VOLUME_NET: 0.0075 m3; AREA_NET: 0.56 m2; AREA_GROSS: 0.25 m2; Width: 30 mm; WEIGTH_GROSS: 58.875 kg; WEIGTH_NET: 58.875 kg; Heigth: 500 mm; Length: 500 mm
AVINOR - 08_Status: S4; 07_Fase: F40; 06_Omrade: TI; 05_ID-nummer: +TI=222.006; 03_Ansvar: 72242; 04_Kontrakt: 72242; 02_Prosjekt: T20100; 01_Lufthavnkode: ENGM
Tekla Common - Grade: S355; Bottom elevation: +210.050; Top elevation: +210.080; Name: INNSTØPNGODS; Assembly mark: INN-104; Class: 371; Part mark: DINN-141; Profile: PL30*500
Pset_PlateCommon - LoadBearing: no; Reference: DINN-141
ePset_SimplebimBasicQuantities - Weight, as steel (Simplebim): 58.875 kg; Volume, net (Simplebim): 0.0075 m3; Area, largest surface, net (Simplebim): 0.25 m2
ePset_Simplebim - Assembly Level: Leaf
ePset_LocationTool - Splitting: ORIGINAL

# IfcPlate: PL30*750 (4)
In: F
Description: PL30*750
Pset_PlateCommon - LoadBearing: no
AVINOR - 08_Status: S4; 07_Fase: F40; 06_Omrade: TI; 05_ID-nummer: +TI=222.006; 03_Ansvar: 72242; 04_Kontrakt: 72242; 02_Prosjekt: T20100; 01_Lufthavnkode: ENGM
Tekla Common - Profile: PL30*750; Grade: S355; Name: INNSTØPNGODS; Class: 371
ePset_Simplebim - Assembly Level: Leaf
Name | Reference = Part mark | Volume, net (Simplebim) (m3) | Area, largest surface, net (Simplebim) (m2) | Weight, as steel (Simplebim) (kg) | Top elevation | Assembly mark | Bottom elevation | Splitting
INNSTØPNGODS | DINN-139 | 0.0132214 | 0.440712 | 103.788 | +210.720 | INN-101 | +210.690 | ORIGINAL | Material: STEEL/S355; Tekla Quantity - AREA_NET: 0.95207 m2; AREA_GROSS: 0.5625 m2; Width: 30 mm; WEIGTH_GROSS: 132.469 kg; Heigth: 750 mm; Length: 750 mm; VOLUME_GROSS: 0.01322 m3; VOLUME_NET: 0.01322 m3; WEIGTH_NET: 103.788 kg
INNSTØPNGODS | DINN-139 | 0.0132214 | 0.440712 | 103.788 | +210.080 | INN-102 | +210.050 | ORIGINAL | Material: STEEL/S355; Tekla Quantity - AREA_NET: 0.95207 m2; AREA_GROSS: 0.5625 m2; Width: 30 mm; WEIGTH_GROSS: 132.469 kg; Heigth: 750 mm; Length: 750 mm; VOLUME_GROSS: 0.01322 m3; VOLUME_NET: 0.01322 m3; WEIGTH_NET: 103.788 kg
INNSTØPNGODS | DINN-152 | 0.00621907 | 0.207304 | 48.8197 | +210.720 | INN-116 | +210.690 | RESULT
INNSTØPNGODS | DINN-152 | 0.00621907 | 0.207304 | 48.8197 | +210.080 | INN-115 | +210.050 | RESULT

# IfcPlate: System Panel:A245 - KL- X - butikkfasade avklares (8)
In: Nivå F
Type - PredefinedType: CURTAIN_PANEL; Material: Metal - Preget plate
AVINOR - 08_Status: S4; 07_Fase: F90; 06_Omrade: TI; 02_Prosjekt: T20100; 01_Lufthavnkode: ENGM
ePset_Simplebim - Assembly Level: Leaf
Pset_PlateCommon - Reference: A245 - KL- X - butikkfasade avklares; IsExternal: no
Pset_QuantityTakeOff - Reference: A245 - KL- X - butikkfasade avklares
ePset_LocationTool - Splitting: ORIGINAL
Name (System Panel:A245 - KL- X - butikkfasade avklares:...) | 03_Ansvar | 05_ID-nummer | Weight, as steel (Simplebim) (kg) | Volume, net (Simplebim) (m3) | Area, largest surface, net (Simplebim) (m2)
58847958 | 72253 | +TI=245.003 | 250.921 | 0.0319645 | 0.532742
68551592 | 72717 | +TI=245.050 | 602.88 | 0.0768 | 1.28
68551352 | 72717 | +TI=245.050 | 588.75 | 0.075 | 1.25
68551329 | 72717 | +TI=245.050 | 602.88 | 0.0768 | 1.28
68551792 | 72717 | +TI=245.050 | 214.19 | 0.0272853 | 0.454756
59292839 | 72253 | +TI=245.003 | 236.673 | 0.0301494 | 0.502491
68551525 | 72717 | +TI=245.050 | 360.319 | 0.0459006 | 0.765009
68555853 | 72253 | +TI=245.003 | 49.2195 | 0.00627 | 0.1045

# IfcPlate: System Panel:A245 - KL-G04 - Veggkledning glasspanel, System Panel:A245 - KL-G04 - Veggkledning glasspanel:66368417
In: Nivå F
Type - PredefinedType: CURTAIN_PANEL; Material: Glass Diagrid opalisert
ePset_SimplebimBasicQuantities - Area, largest surface, net (Simplebim): 0.878669 m2; Weight, as steel (Simplebim): 68.9755 kg; Volume, net (Simplebim): 0.00878669 m3
Pset_QuantityTakeOff - Reference: A245 - KL-G04 - Veggkledning glasspanel
Pset_PlateCommon - IsExternal: no; Reference: A245 - KL-G04 - Veggkledning glasspanel
ePset_Simplebim - Assembly Level: Leaf
ePset_LocationTool - Splitting: ORIGINAL
AVINOR - 08_Status: S4; 07_Fase: F90; 06_Omrade: TI; 03_Ansvar: 72717; 02_Prosjekt: T20100; 05_ID-nummer: +TI=245.039; 01_Lufthavnkode: ENGM

# IfcPlate: System Panel:A245 - KL-G07.3 - Veggkledning glasspanel, System Panel:A245 - KL-G07.3 - Veggkledning glasspanel:61214908
In: Nivå F
Type - PredefinedType: CURTAIN_PANEL; Material: Glasskledning, silketrykket(1)
Pset_QuantityTakeOff - Reference: A245 - KL-G07.3 - Veggkledning glasspanel
AVINOR - 03_Ansvar: 72253; 08_Status: S4; 07_Fase: F90; 05_ID-nummer: +TI=245.002; 06_Omrade: TI; 02_Prosjekt: T20100; 01_Lufthavnkode: ENGM
ePset_LocationTool - Splitting: ORIGINAL
Pset_PlateCommon - IsExternal: no; Reference: A245 - KL-G07.3 - Veggkledning glasspanel
ePset_Simplebim - Assembly Level: Leaf
ePset_SimplebimBasicQuantities - Volume, net (Simplebim): 0.0232581 m3; Area, largest surface, net (Simplebim): 2.32581 m2; Weight, as steel (Simplebim): 182.576 kg

# IfcPlate: System Panel:A245 - KL-M02 - Veggkledning aluminium laserskåret mønster (10)
In: Nivå F
Type - PredefinedType: CURTAIN_PANEL; Material: T2_Metallkledning_Laserskåret
AVINOR - 03_Ansvar: 72253; 08_Status: S4; 07_Fase: F90; 05_ID-nummer: +TI=245.003; 06_Omrade: TI; 02_Prosjekt: T20100; 01_Lufthavnkode: ENGM
Pset_QuantityTakeOff - Reference: A245 - KL-M02 - Veggkledning aluminium laserskåret mønster
ePset_Simplebim - Assembly Level: Leaf
Pset_PlateCommon - Reference: A245 - KL-M02 - Veggkledning aluminium laserskåret mønster; IsExternal: no
Name (System Panel:A245 - KL-M02 - Veggkledning aluminium laserskåret mønster:...) | Volume, net (Simplebim) (m3) | Area, largest surface, net (Simplebim) (m2) | Weight, as steel (Simplebim) (kg) | Splitting
44969018 | 0.00256095 | 0.85365 | 20.1035 | ORIGINAL
44969058 | 0.001377 | 0.459 | 10.8094 | ORIGINAL
44969124 | 0.001377 | 0.459 | 10.8094 | ORIGINAL
44969068 | 0.00299842 | 0.999474 | 23.5376 | RESULT
44969032 | 0.00163958 | 0.546525 | 12.8707 | RESULT
44969099 | 0.004293 | 1.431 | 33.7001 | RESULT
44969100 | 0.00428677 | 1.42892 | 33.6512 | RESULT
44969119 | 0.00428677 | 1.42892 | 33.6512 | RESULT
44969101 | 0.004293 | 1.431 | 33.7001 | RESULT
44969055 | 0.00225469 | 0.751562 | 17.6993 | RESULT

# IfcPlate: System Panel:A245 - KL-M03 - Veggkledning metallplate plan, for betongvegg (12)
In: Nivå F
Type - PredefinedType: CURTAIN_PANEL; Material: T2_Metal_Aluminium
AVINOR - 03_Ansvar: 72253; 08_Status: S4; 07_Fase: F90; 05_ID-nummer: +TI=245.003; 06_Omrade: TI; 02_Prosjekt: T20100; 01_Lufthavnkode: ENGM
Pset_QuantityTakeOff - Reference: A245 - KL-M03 - Veggkledning metallplate plan, for betongvegg
ePset_Simplebim - Assembly Level: Leaf
Pset_PlateCommon - Reference: A245 - KL-M03 - Veggkledning metallplate plan, for betongvegg; IsExternal: no
Name (System Panel:A245 - KL-M03 - Veggkledning metallplate plan, for betongvegg:...) | Volume, net (Simplebim) (m3) | Area, largest surface, net (Simplebim) (m2) | Weight, as steel (Simplebim) (kg) | Splitting
43231224 | 0.00691695 | 2.30565 | 54.2981 | ORIGINAL
43231225 | 0.007695 | 2.565 | 60.4058 | ORIGINAL
43231226 | 0.007695 | 2.565 | 60.4058 | ORIGINAL
43231227 | 0.00691695 | 2.30565 | 54.2981 | ORIGINAL
61928271 | 0.00400995 | 1.33665 | 31.4781 | ORIGINAL
43303081 | 0.0004221 | 0.1407 | 3.31349 | RESULT
43231233 | 0.00081 | 0.27 | 6.3585 | RESULT
43231234 | 0.0007281 | 0.2427 | 5.71559 | RESULT
43231231 | 0.0007281 | 0.2427 | 5.71559 | RESULT
43231232 | 0.00081 | 0.27 | 6.3585 | RESULT
41559977 | 0.00057105 | 0.19035 | 4.48274 | RESULT
43297045 | 0.00542498 | 1.80832 | 42.5861 | RESULT

# IfcPlate: System Panel:A245 - KL-M07 - Veggkledning ventilasjonsrist tekniske sjakter (4)
In: Nivå F
Type - PredefinedType: CURTAIN_PANEL; Material: T2_Ventilasjonsrist
AVINOR - 03_Ansvar: 72253; 08_Status: S4; 07_Fase: F90; 05_ID-nummer: +TI=245.003; 06_Omrade: TI; 02_Prosjekt: T20100; 01_Lufthavnkode: ENGM
ePset_Simplebim - Assembly Level: Leaf
ePset_LocationTool - Splitting: ORIGINAL
Pset_PlateCommon - Reference: A245 - KL-M07 - Veggkledning ventilasjonsrist tekniske sjakter; IsExternal: no
Pset_QuantityTakeOff - Reference: A245 - KL-M07 - Veggkledning ventilasjonsrist tekniske sjakter
Name (System Panel:A245 - KL-M07 - Veggkledning ventilasjonsrist tekniske sjakter:...) | Area, largest surface, net (Simplebim) (m2) | Volume, net (Simplebim) (m3) | Weight, as steel (Simplebim) (kg)
44969121 | 0.61425 | 0.0184275 | 144.656
44969091 | 1.07325 | 0.0321975 | 252.75
44969118 | 1.07325 | 0.0321975 | 252.75
44969093 | 0.61425 | 0.0184275 | 144.656

# IfcPlate: System Panel:A245 - KL-M18 - Veggkledning metallplate 18 plan RAL 9007, System Panel:A245 - KL-M18 - Veggkledning metallplate 18 plan RAL 9007:67003904
In: Nivå F
Type - PredefinedType: CURTAIN_PANEL; Material: T2_Metal_Aluminium
ePset_LocationTool - Splitting: ORIGINAL
ePset_Simplebim - Assembly Level: Leaf
Pset_QuantityTakeOff - Reference: A245 - KL-M18 - Veggkledning metallplate 18 plan RAL 9007
Pset_PlateCommon - Reference: A245 - KL-M18 - Veggkledning metallplate 18 plan RAL 9007; IsExternal: no
AVINOR - 08_Status: S4; 07_Fase: F90; 06_Omrade: TI; 03_Ansvar: 72717; 05_ID-nummer: +TI=245.015; 02_Prosjekt: T20100; 01_Lufthavnkode: ENGM
ePset_SimplebimBasicQuantities - Weight, as steel (Simplebim): 24.6121 kg; Area, largest surface, net (Simplebim): 1.0451 m2; Volume, net (Simplebim): 0.0031353 m3

# IfcPlate: System Panel:A245 - KL-S01 - Veggkledning metallplate sokkel - IGK - 10mm, System Panel:A245 - KL-S01 - Veggkledning metallplate sokkel - IGK - 10mm:58847959
In: Nivå F
Type - PredefinedType: CURTAIN_PANEL; Material: _NSW Stål, rustfritt
AVINOR - 03_Ansvar: 72253; 08_Status: S4; 07_Fase: F90; 05_ID-nummer: +TI=245.003; 06_Omrade: TI; 02_Prosjekt: T20100; 01_Lufthavnkode: ENGM
ePset_LocationTool - Splitting: ORIGINAL
ePset_SimplebimBasicQuantities - Weight, as steel (Simplebim): 9.69086 kg; Volume, net (Simplebim): 0.0012345 m3; Area, largest surface, net (Simplebim): 0.12345 m2
Pset_QuantityTakeOff - Reference: A245 - KL-S01 - Veggkledning metallplate sokkel - IGK - 10mm
ePset_Simplebim - Assembly Level: Leaf
Pset_PlateCommon - IsExternal: no; Reference: A245 - KL-S01 - Veggkledning metallplate sokkel - IGK - 10mm

# IfcPlate: System Panel:A245 - KL-S01 - Veggkledning metallplate sokkel - IMK - 20mm (6)
In: Nivå F
Type - PredefinedType: CURTAIN_PANEL; Material: _NSW Stål, rustfritt
Pset_PlateCommon - IsExternal: no; Reference: A245 - KL-S01 - Veggkledning metallplate sokkel - IMK - 20mm
AVINOR - 03_Ansvar: 72253; 08_Status: S4; 07_Fase: F90; 05_ID-nummer: +TI=245.003; 06_Omrade: TI; 02_Prosjekt: T20100; 01_Lufthavnkode: ENGM
ePset_Simplebim - Assembly Level: Leaf
Pset_QuantityTakeOff - Reference: A245 - KL-S01 - Veggkledning metallplate sokkel - IMK - 20mm
Name (System Panel:A245 - KL-S01 - Veggkledning metallplate sokkel - IMK - 20mm:...) | Volume, net (Simplebim) (m3) | Area, largest surface, net (Simplebim) (m2) | Weight, as steel (Simplebim) (kg) | Splitting
15186955 | 0.010254 | 0.5127 | 80.4939 | ORIGINAL
43303079 | 0.0014028 | 0.0701398 | 11.0119 | ORIGINAL
44968984 | 0.0012195 | 0.060975 | 9.57308 | ORIGINAL
62371496 | 0.00954413 | 0.477206 | 74.9214 | ORIGINAL
62371180 | 0.00144693 | 0.0723463 | 11.3584 | RESULT
27491892 | 0.0019035 | 0.095175 | 14.9425 | RESULT

# IfcRailing: A247 - Fendring:A247 Fendring - FE-S01 - Avviser, montert m. brakett mot dekke, 1 rør Ø=49 mm (2)
In: Nivå F
Type - Material: <Unnamed>
AVINOR - 03_Ansvar: 72253; 08_Status: S4; 07_Fase: F90; 06_Omrade: TI; 05_ID-nummer: +TI=251.012-IY0002; 02_Prosjekt: T20100; 01_Lufthavnkode: ENGM
ePset_LocationTool - Splitting: ORIGINAL
Pset_QuantityTakeOff - Reference: A247 Fendring - FE-S01 - Avviser, montert m. brakett mot dekke, 1 rør Ø=49 mm
ePset_Simplebim - Assembly Level: Leaf
Pset_RailingCommon - Reference: A247 Fendring - FE-S01 - Avviser, montert m. brakett mot dekke, 1 rør Ø=49 mm; IsExternal: no
ePset_SimplebimBasicQuantities - Width: 48.4 mm; Height: 48.4 mm
Name (A247 - Fendring:A247 Fendring - FE-S01 - Avviser, montert m. brakett mot dekke, 1 rør Ø=49 mm:...) | Length (mm)
39880433 | 7799.67
61226797 | 622.514

# IfcSlab: 150*9000 (2)
In: F
Description: 150*9000; PredefinedType: FLOOR
ePset_LocationTool - Splitting: RESULT
ePset_SimplebimBasicQuantities - Thickness (Simplebim): 150 mm
ePset_Simplebim - Assembly Level: Leaf
Tekla Common - Profile: 150*9000; Name: PÅSTØP; Top elevation: +210.830; Class: 262; Bottom elevation: +210.680; Grade: B30
AVINOR - 08_Status: S4; 07_Fase: F40; 05_ID-nummer: +TI=251.006; 06_Omrade: TI; 03_Ansvar: 72242; 04_Kontrakt: 72242; 02_Prosjekt: T20100; 01_Lufthavnkode: ENGM
Pset_SlabCommon - LoadBearing: no
Name | Volume, net (Simplebim) (m3) | Area, largest surface, net (Simplebim) (m2) = Area, top, net (Simplebim) (m2) | Area, sides, net (Simplebim) (m2) | Perimeter (Simplebim) (mm) | Part mark = Reference | Assembly mark
PÅSTØP | 2.77724 | 18.5524 | 4.91008 | 32733.9 | Concrete-3912 | PST-253
PÅSTØP | 18.909 | 126.135 | 7.05506 | 47033.7 | Concrete-1708 | PST-112

# IfcSlab: 265*590, PREFABDEKKE
In: F
Description: 265*590; PredefinedType: FLOOR; Material: CONCRETE/C35/45
Pset_SlabCommon - LoadBearing: no; Reference: Concrete-19037
Tekla Common - Bottom elevation: +210.415; Name: PREFABDEKKE; Profile: 265*590; Assembly mark: PD-566; Grade: C35/45; Class: 160; Top elevation: +210.680; Part mark: Concrete-19037
Tekla Quantity - Heigth: 589.996 mm; Length: 3400 mm; AREA_NET: 6.12668 m2; VOLUME_NET: 0.53159 m3; VOLUME_GROSS: 0.53159 m3; AREA_GROSS: 2.00599 m2; Width: 265 mm; WEIGTH_NET: 1275.81 kg; WEIGTH_GROSS: 1275.81 kg
ePset_SimplebimBasicQuantities - Volume, net (Simplebim): 0.531587 m3; Perimeter (Simplebim): 7980 mm; Area, largest surface, net (Simplebim): 2.00599 m2; Area, top, net (Simplebim): 2.00599 m2; Area, sides, net (Simplebim): 2.1147 m2; Thickness (Simplebim): 265 mm
ePset_Simplebim - Assembly Level: Leaf
AVINOR - 08_Status: S4; 07_Fase: F40; 05_ID-nummer: +TI=251.007; 06_Omrade: TI; 03_Ansvar: 72242; 04_Kontrakt: 72242; 02_Prosjekt: T20100; 01_Lufthavnkode: ENGM
ePset_LocationTool - Splitting: ORIGINAL

# IfcSlab: 8580*265, PREFABDEKKE
In: F
Description: 8580*265; PredefinedType: FLOOR
ePset_SimplebimBasicQuantities - Area, top, net (Simplebim): 0.720173 m2; Area, largest surface, net (Simplebim): 0.658053 m2; Perimeter (Simplebim): 3281.22 mm; Area, sides, net (Simplebim): 0.869524 m2; Volume, net (Simplebim): 0.170639 m3; Thickness (Simplebim): 265 mm
Tekla Common - Bottom elevation: +210.415; Profile: 8580*265; Name: PREFABDEKKE; Part mark: Concrete-20906; Assembly mark: PD-594; Grade: C35/45; Class: 160; Top elevation: +210.680
Pset_SlabCommon - Reference: Concrete-20906; LoadBearing: no
ePset_Simplebim - Assembly Level: Leaf
ePset_LocationTool - Splitting: RESULT
AVINOR - 08_Status: S4; 07_Fase: F40; 05_ID-nummer: +TI=251.007; 06_Omrade: TI; 03_Ansvar: 72242; 04_Kontrakt: 72242; 02_Prosjekt: T20100; 01_Lufthavnkode: ENGM

# IfcSlab: Floor:A251 - Isolasjon - 250 mm, Floor:A251 - Isolasjon - 250 mm:33471831:3
In: Nivå F
Type - PredefinedType: FLOOR; Material: _NSW Isolasjon trykkfast 250 mm
Pset_ReinforcementBarPitchOfSlab - Reference: A251 - Isolasjon - 250 mm; sets with these values: 2
Pset_SlabCommon - Reference: A251 - Isolasjon - 250 mm; IsExternal: no; LoadBearing: no
AVINOR - 08_Status: S4; 07_Fase: F40; 06_Omrade: TI; 03_Ansvar: 72245; 02_Prosjekt: T20100; 01_Lufthavnkode: ENGM
ePset_Simplebim - Assembly Level: Leaf
ePset_SimplebimBasicQuantities - Volume, net (Simplebim): 2.69295 m3; Thickness (Simplebim): 205 mm; Area, largest surface, net (Simplebim): 13.1363 m2; Area, top, net (Simplebim): 13.1363 m2; Area, sides, net (Simplebim): 4.83488 m2; Perimeter (Simplebim): 23584.8 mm
ePset_LocationTool - Splitting: RESULT

# IfcSlab: Floor:A254 - Avretting 45mm, Floor:A254 - Avretting 45mm:54035969
In: Nivå F
Type - PredefinedType: FLOOR; Material: T2_Mørtel 45 mm
AVINOR - 03_Ansvar: 72253; 08_Status: S4; 07_Fase: F90; 06_Omrade: TI; 02_Prosjekt: T20100; 05_ID-nummer: +TI=254.076; 01_Lufthavnkode: ENGM
ePset_SimplebimBasicQuantities - Area, top, net (Simplebim): 144.079 m2; Area, largest surface, net (Simplebim): 144.079 m2; Area, sides, net (Simplebim): 2.64078 m2; Thickness (Simplebim): 45 mm; Volume, net (Simplebim): 6.48354 m3; Perimeter (Simplebim): 58684 mm
ePset_Simplebim - Assembly Level: Leaf
Pset_QuantityTakeOff - Reference: A254 - Avretting 45mm; sets with these values: 2
Pset_SlabCommon - IsExternal: no; LoadBearing: no; Reference: A254 - Avretting 45mm
ePset_LocationTool - Splitting: RESULT

# IfcSlab: Floor:A254 - Gulv ARK - 150 mm, Floor:A254 - Gulv ARK - 150 mm:23380274
In: Nivå F
Type - PredefinedType: FLOOR; Material: _NSW Generell Gulv (Floor) 150 mm
ePset_SimplebimBasicQuantities - Area, largest surface, net (Simplebim): 0.289251 m2; Area, top, net (Simplebim): 0.289251 m2; Volume, net (Simplebim): 0.0433877 m3; Area, sides, net (Simplebim): 0.3669 m2; Thickness (Simplebim): 150 mm; Perimeter (Simplebim): 2446 mm
Pset_SlabCommon - IsExternal: no; LoadBearing: no; Reference: A254 - Gulv ARK - 150 mm
Pset_QuantityTakeOff - Reference: A254 - Gulv ARK - 150 mm; sets with these values: 2
AVINOR - 03_Ansvar: 72253; 08_Status: S4; 07_Fase: F90; 05_ID-nummer: +TI=251.033; 06_Omrade: TI; 02_Prosjekt: T20100; 01_Lufthavnkode: ENGM
ePset_Simplebim - Assembly Level: Leaf
ePset_LocationTool - Splitting: RESULT

# IfcSlab: Floor:A254 - Rist over konvektor Pirrot - 40 mm, Floor:A254 - Rist over konvektor Pirrot - 40 mm:33395488:7
In: Nivå F
Type - PredefinedType: FLOOR; Material: _T2 Rist over konvektor pirrot 40x40mm 40 mm
Pset_SlabCommon - IsExternal: no; LoadBearing: no; Reference: A254 - Rist over konvektor Pirrot - 40 mm
Pset_ReinforcementBarPitchOfSlab - Reference: A254 - Rist over konvektor Pirrot - 40 mm; sets with these values: 2
ePset_Simplebim - Assembly Level: Leaf
AVINOR - 03_Ansvar: 72253; 08_Status: S4; 07_Fase: F90; 06_Omrade: TI; 02_Prosjekt: T20100; 05_ID-nummer: +TI=251.078; 01_Lufthavnkode: ENGM
ePset_SimplebimBasicQuantities - Perimeter (Simplebim): 21478.5 mm; Area, sides, net (Simplebim): 0.859139 m2; Area, largest surface, net (Simplebim): 2.76275 m2; Area, top, net (Simplebim): 2.76275 m2; Thickness (Simplebim): 40 mm; Volume, net (Simplebim): 0.11051 m3
ePset_LocationTool - Splitting: RESULT

# IfcSlab: Floor:A254 - Tregulv inkl. lim - 25 mm (3)
In: Nivå F
Type - PredefinedType: FLOOR; Material: T2_Tregulv Gulvplaner 25 mm
Pset_QuantityTakeOff - Reference: A254 - Tregulv inkl. lim - 25 mm; sets with these values: 2
ePset_SimplebimBasicQuantities - Thickness (Simplebim): 25 mm
Pset_SlabCommon - IsExternal: no; LoadBearing: no; Reference: A254 - Tregulv inkl. lim - 25 mm
ePset_Simplebim - Assembly Level: Leaf
AVINOR - 03_Ansvar: 72253; 08_Status: S4; 07_Fase: F90; 05_ID-nummer: +TI=254.005; 06_Omrade: TI; 02_Prosjekt: T20100; 01_Lufthavnkode: ENGM
Name (Floor:A254 - Tregulv inkl. lim - 25 mm:...) | Area, sides, net (Simplebim) (m2) | Volume, net (Simplebim) (m3) | Area, largest surface, net (Simplebim) (m2) | Area, top, net (Simplebim) (m2) | Perimeter (Simplebim) (mm) | Splitting
66648103:2 | 0.0588288 | 0.0109887 | 0.439548 | 0.439548 | 2353.15 | ORIGINAL | Pset_SlabCommon - PitchAngle: 0 deg
23478928 | 1.41432 | 0.144089 | 4.97367 | 5.76356 | 56572.7 | RESULT
66648103 | 1.35046 | 0.145835 | 4.10785 | 5.83341 | 54018.4 | RESULT

# IfcSlab: HD265 (18)
In: F
Description: HD265; PredefinedType: FLOOR
ePset_SimplebimBasicQuantities - Thickness (Simplebim): 265 mm
AVINOR - 08_Status: S4; 07_Fase: F40; 06_Omrade: TI; 03_Ansvar: 72242; 04_Kontrakt: 72242; 02_Prosjekt: T20100; 05_ID-nummer: +TI=251.019; 01_Lufthavnkode: ENGM
Tekla Common - Bottom elevation: +210.415; Grade: C45/55; Profile: HD265; Name: HULLDEKKE; Class: 162; Top elevation: +210.680
ePset_Simplebim - Assembly Level: Leaf
Pset_SlabCommon - LoadBearing: no
Name | Material | Area, largest surface, net (Simplebim) (m2) | Area, top, net (Simplebim) (m2) | Perimeter (Simplebim) (mm) | Area, sides, net (Simplebim) (m2) | Volume, net (Simplebim) (m3) | Assembly mark | Part mark = Reference | VOLUME_NET (m3) | AREA_NET (m2) | WEIGTH_GROSS (kg) | VOLUME_GROSS (m3) | AREA_GROSS (m2) | WEIGTH_NET (kg) | Heigth (mm) | Width (mm) | Length (mm) | Splitting
10 x HULLDEKKE | CONCRETE/C45/55 | 9.9758 | 10.1835 | 111093 | 29.4397 | 1.48758 | HD-671 | HD-245 | 1.48758 | 49.9307 | 3581.01 | 1.49209 | 0 | 3570.18 | 265 | 1200 | 8550 | ORIGINAL
HULLDEKKE | CONCRETE/C45/55 | 9.81893 | 10.0234 | 109367 | 28.9822 | 1.46418 | HD-3619 | HD-853 | 1.46418 | 49.151 | 3524.7 | 1.46863 | 0 | 3514.04 | 265 | 1200 | 8415.55 | ORIGINAL
HULLDEKKE |  | 1.34779 | 2.19848 | 9746.26 | 2.58276 | 0.217635 | HD-671 | HD-245 |  |  |  |  |  |  |  |  |  | RESULT
HULLDEKKE |  | 1.45894 | 2.34969 | 10874.9 | 2.88185 | 0.217555 | HD-671 | HD-245 |  |  |  |  |  |  |  |  |  | RESULT
HULLDEKKE |  | 1.45878 | 2.34943 | 10873.9 | 2.88157 | 0.217532 | HD-671 | HD-245 |  |  |  |  |  |  |  |  |  | RESULT
HULLDEKKE |  | 1.45862 | 2.34918 | 10872.8 | 2.8813 | 0.217508 | HD-671 | HD-245 |  |  |  |  |  |  |  |  |  | RESULT
HULLDEKKE |  | 1.45847 | 2.34892 | 10871.8 | 2.88102 | 0.217484 | HD-671 | HD-245 |  |  |  |  |  |  |  |  |  | RESULT
HULLDEKKE |  | 1.45831 | 2.34867 | 10870.7 | 2.88075 | 0.217461 | HD-671 | HD-245 |  |  |  |  |  |  |  |  |  | RESULT
HULLDEKKE |  | 5.54365 | 9.17726 | 37919.2 | 10.0486 | 0.797549 | HD-671 | HD-245 |  |  |  |  |  |  |  |  |  | RESULT

# IfcSystem (37)
Name | Description
Bæresystem generelt | 410 | MagiCAD Pset_System - Description: Bæresystem generelt; Code: 410
Bæresystem for tele- og automasjon | 5111 | MagiCAD Pset_System - Description: Bæresystem for tele- og automasjon; Code: 5111
Trekkerør generelt | 4110 | MagiCAD Pset_System - Description: Trekkerør generelt; Code: 4110
Brannalarm | 542 | MagiCAD Pset_System - Description: Brannalarm; Code: 542
Brannspjeld | 542-DI | MagiCAD Pset_System - Description: Brannspjeld; Code: 542-DI
STIGEKABEL-SEKUNDÆR | 501-B | MagiCAD Pset_System - Description: STIGEKABEL-SEKUNDÆR; Code: 501-B
Adgangskontroll, Innbruddsalarm | 543 | MagiCAD Pset_System - Description: Adgangskontroll, Innbruddsalarm; Code: 543
+TI=310.201-1 | +TI=310.201-1
+TI=310.101-1 | +TI=310.101-1
+TI=370.001 R | +TI=370.001 R
+TI=370.001 T | 372.000 | MagiCAD Pset_System - Code: 372.000
+TI=320.001 T | +TI=320.001 T
+TI=313.003 | +TI=313.003
+TI=330.003 B-1 | +TI=330.003 B-1
+TI=313.403 | +TI=313.403
+TI=323.002 R-1 | +TI=323.002 R-1
32= T 55° Kopi 1 | 32= T 55° Kopi 1
+TI=350.001 T-1 | +TI=350.001 T-1
+TI=350.001 R-1 | +TI=350.001 R-1
+TI=322.004 R | +TI=322.004 R
+TI=313.207 | +TI=313.207
+TI=322.004 T | +TI=322.004 T
31= Spillvann 3 | 31= Spillvann 3
32= R 50° Kopi 1 | 32= R 50° Kopi 1
37= R 18° Kopi 1 | 37= R 18° Kopi 1
32= T 60° Kopi 4 | 32= T 60° Kopi 4
37= T 9° Kopi 1 | 37= T 9° Kopi 1
+TI=332.001-NZ0003 | +TI=332.001-NZ0003
+TI=332.001-NZ0005 | +TI=332.001-NZ0005
+TI=332.001-NZ0006 | +TI=332.001-NZ0006
36= T Kopi 184 | 36= T Kopi 184
36 Tilluft | 36 Tilluft
36= T Kopi 13 | 36= T Kopi 13
+TI=360.051 A | +TI=360.051 A
36= A Kopi 20 | 36= A Kopi 20
36= A Kopi 210 | 36= A Kopi 210
36= A Kopi 21 | 36= A Kopi 21

# IfcWall: 25100*250, PLASSTØPTVEGG
In: B
Description: 25100*250
Tekla Common - Bottom elevation: +195.500; Profile: 25100*250; Name: PLASSTØPTVEGG; Assembly mark: PLV-2046(?); Class: 250; Grade: C35/45; Top elevation: +220.600; Finish: Sjakt; Part mark: Concrete-15639(?)
ePset_Simplebim - Assembly Level: Leaf
Pset_WallCommon - LoadBearing: no; Reference: Concrete-15639(?)
ePset_SimplebimBasicQuantities - Area, side, gross, larger (Simplebim): 14.62 m2; Area, side, gross, average (Simplebim): 14.62 m2; Area, side, gross, smaller (Simplebim): 14.62 m2; Area, side, net, larger (Simplebim): 14.62 m2; Area, side, net, average (Simplebim): 14.62 m2; Area, side, net, smaller (Simplebim): 14.62 m2; Area, largest surface, net (Simplebim): 14.62 m2; Area, side, gross, AABB (Simplebim): 14.62 m2; Volume, net (Simplebim): 3.655 m3; Thickness (Simplebim): 250 mm; Length (Simplebim): 3400 mm; Height (Simplebim): 4300 mm
ePset_LocationTool - Splitting: RESULT
AVINOR - 08_Status: S4; 07_Fase: F90; 05_ID-nummer: +TI=241.001; 06_Omrade: TI; 04_Kontrakt: 72241; 02_Prosjekt: T20100; 03_Ansvar: 72101; 01_Lufthavnkode: ENGM

# IfcWall: Basic Wall:A231 - SBE 250 iso+100 lettklinker+15mm puss, Basic Wall:A231 - SBE 250 iso+100 lettklinker+15mm puss:27940618
In: Nivå F - 0,7 m
Type - PredefinedType: STANDARD; Material: _NSW Murpuss 15 mm, _NSW Lettklinker 100 mm, _NSW Isolasjon 250 mm
Type - Pset_ReinforcementBarPitchOfWall - Description: Kledning på fasade nivå D
Pset_WallCommon - Reference: A231 - SBE 250 iso+100 lettklinker+15mm puss; IsExternal: yes; ExtendToStructure: no; LoadBearing: no
Pset_QuantityTakeOff - Reference: A231 - SBE 250 iso+100 lettklinker+15mm puss; sets with these values: 2
ePset_SimplebimBasicQuantities - Volume, net (Simplebim): 0.0490861 m3; Area, side, gross, smaller (Simplebim): 0.134483 m2; Area, side, gross, average (Simplebim): 0.134483 m2; Area, side, gross, larger (Simplebim): 0.134483 m2; Area, side, net, average (Simplebim): 0.134483 m2; Area, side, net, larger (Simplebim): 0.134483 m2; Area, side, net, smaller (Simplebim): 0.134483 m2; Area, side, gross, AABB (Simplebim): 0.134375 m2; Area, largest surface, net (Simplebim): 0.228307 m2; Height (Simplebim): 215 mm; Thickness (Simplebim): 366 mm; Length (Simplebim): 625 mm
AVINOR - 08_Status: S4; 07_Fase: F40; 06_Omrade: TI; 05_ID-nummer: +TI=231.006; 03_Ansvar: 72245; 02_Prosjekt: T20100; 01_Lufthavnkode: ENGM
ePset_Simplebim - Assembly Level: Leaf
ePset_LocationTool - Splitting: RESULT

# IfcWall: Basic Wall:A231 - SHIRT I PIRROT OG PIRNORD -330, Basic Wall:A231 - SHIRT I PIRROT OG PIRNORD -330:31020228
In: Nivå F
Type - PredefinedType: STANDARD; Material: Kledning 15 mm, _NSW Isolasjon trykkfast 300 mm, Kledning 15 mm
Type - Pset_ReinforcementBarPitchOfWall - Description: Generell yttervegg 200mm
AVINOR - 08_Status: S4; 07_Fase: F40; 06_Omrade: TI; 03_Ansvar: 72245; 02_Prosjekt: T20100; 01_Lufthavnkode: ENGM
ePset_LocationTool - Splitting: RESULT
Pset_QuantityTakeOff - Reference: A231 - SHIRT I PIRROT OG PIRNORD -330; sets with these values: 2
ePset_Simplebim - Assembly Level: Leaf
Pset_WallCommon - IsExternal: yes; ExtendToStructure: no; LoadBearing: no; Reference: A231 - SHIRT I PIRROT OG PIRNORD -330
ePset_SimplebimBasicQuantities - Area, side, gross, larger (Simplebim): 6.78177 m2; Area, side, gross, average (Simplebim): 6.78177 m2; Area, side, gross, smaller (Simplebim): 6.78177 m2; Area, side, net, larger (Simplebim): 6.78177 m2; Area, side, net, average (Simplebim): 6.78177 m2; Area, side, gross, AABB (Simplebim): 6.78177 m2; Area, side, net, smaller (Simplebim): 6.78177 m2; Area, largest surface, net (Simplebim): 6.78177 m2; Thickness (Simplebim): 330 mm; Height (Simplebim): 715 mm; Length (Simplebim): 9485 mm; Volume, net (Simplebim): 2.23799 m3

# IfcWall: Basic Wall:A241 - FV-75 (2)
In: Nivå G - 2,0m
Type - PredefinedType: STANDARD; Material: T2_Gips Protect F 15 mm, T2_Gips Protect F 15 mm, _NSW Stålstender, uisolert 75 mm
Pset_WallCommon - IsExternal: no; ExtendToStructure: no; LoadBearing: no; Reference: A241 - FV-75
AVINOR - 03_Ansvar: 72253; 08_Status: S4; 07_Fase: F90; 05_ID-nummer: +TI=241.005; 06_Omrade: TI; 02_Prosjekt: T20100; 01_Lufthavnkode: ENGM
Pset_QuantityTakeOff - Reference: A241 - FV-75; sets with these values: 2
ePset_SimplebimBasicQuantities - Thickness (Simplebim): 105 mm; Height (Simplebim): 500 mm
ePset_Simplebim - Assembly Level: Leaf
Identity Data - CQFireRequirement: EI 60/ A2-s1,d0
ePset_LocationTool - Splitting: RESULT
Name (Basic Wall:A241 - FV-75:...) | Area, side, gross, larger (Simplebim) (m2) = Area, side, gross, smaller (Simplebim) (m2) = Area, side, gross, average (Simplebim) (m2) = Area, side, net, average (Simplebim) (m2) = Area, side, net, larger (Simplebim) (m2) = Area, largest surface, net (Simplebim) (m2) = Area, side, net, smaller (Simplebim) (m2) | Area, side, gross, AABB (Simplebim) (m2) | Volume, net (Simplebim) (m3) | Length (Simplebim) (mm)
44245155 | 0.807991 | 0.808 | 0.0848391 | 1616
44245156 | 0.519757 | 0.52 | 0.0545745 | 1040

# IfcWall: Basic Wall:A241 - RVF-103 (2)
In: Nivå G - 2,0m
Type - PredefinedType: STANDARD; Material: T2_Gips Fibergips 12.5 mm, T2_Gips Protect F 15 mm, _NSW Stålstender, uisolert 100 mm, T2_Gips Protect F 15 mm, T2_Gips Fibergips 12.5 mm
Type - Pset_ReinforcementBarPitchOfWall - Description: Teknisk sjakt m/forsterkede stendere H: 7m
AVINOR - 03_Ansvar: 72253; 08_Status: S4; 07_Fase: F90; 05_ID-nummer: +TI=241.005; 06_Omrade: TI; 02_Prosjekt: T20100; 01_Lufthavnkode: ENGM
ePset_LocationTool - Splitting: RESULT
ePset_SimplebimBasicQuantities - Thickness (Simplebim): 155 mm; Height (Simplebim): 500 mm
Pset_WallCommon - IsExternal: no; ExtendToStructure: no; LoadBearing: no; Reference: A241 - RVF-103
Pset_QuantityTakeOff - Reference: A241 - RVF-103; sets with these values: 2
ePset_Simplebim - Assembly Level: Leaf
Identity Data - CQFireRequirement: EI 60/ A2-s1,d0
Name (Basic Wall:A241 - RVF-103:...) | Area, side, net, smaller (Simplebim) (m2) = Area, largest surface, net (Simplebim) (m2) = Area, side, net, larger (Simplebim) (m2) = Area, side, net, average (Simplebim) (m2) = Area, side, gross, larger (Simplebim) (m2) = Area, side, gross, average (Simplebim) (m2) = Area, side, gross, smaller (Simplebim) (m2) | Area, side, gross, AABB (Simplebim) (m2) | Volume, net (Simplebim) (m3) | Length (Simplebim) (mm)
4337149 | 0.827996 | 0.828 | 0.128339 | 1656
43933487 | 0.655 | 0.655 | 0.101525 | 1310

# IfcWall: Basic Wall:A241 - RVR-101 (2)
Type - PredefinedType: STANDARD; Material: Plate - Gips 12.5 mm, Plate - Gips 12.5 mm, _NSW Stålstender, uisolert 100 mm, Plate - Gips 12.5 mm, Plate - Gips 12.5 mm
Pset_WallCommon - IsExternal: no; ExtendToStructure: no; LoadBearing: no; Reference: A241 - RVR-101
ePset_SimplebimBasicQuantities - Length (Simplebim): 5739.51 mm; Thickness (Simplebim): 150 mm
ePset_LocationTool - Splitting: ORIGINAL
AVINOR - 03_Ansvar: 72253; 08_Status: S4; 07_Fase: F90; 05_ID-nummer: +TI=241.005; 06_Omrade: TI; 02_Prosjekt: T20100; 01_Lufthavnkode: ENGM
Pset_QuantityTakeOff - Reference: A241 - RVR-101; sets with these values: 2
ePset_Simplebim - Assembly Level: Leaf
Name (Basic Wall:A241 - RVR-101:...) | In | Area, side, net, average (Simplebim) (m2) = Area, side, net, larger (Simplebim) (m2) = Area, side, net, smaller (Simplebim) (m2) | Area, largest surface, net (Simplebim) (m2) | Area, side, gross, AABB (Simplebim) (m2) = Area, side, gross, average (Simplebim) (m2) = Area, side, gross, smaller (Simplebim) (m2) = Area, side, gross, larger (Simplebim) (m2) | Height (Simplebim) (mm) | Volume, net (Simplebim) (m3)
5878303 | Nivå F | 13.3504 | 13.3504 | 16.0706 | 2800 | 2.00255
5878303 | Nivå G - 2,0m | 0.832229 | 0.860927 | 0.832229 | 145 | 0.124834

# IfcWall: Basic Wall:A241 - SXVXS-100 (2)
Type - PredefinedType: STANDARD; Material: Plate - Gips 13 mm, _NSW X-finer 12 mm, _NSW Stålstender, uisolert 100 mm, _NSW X-finer 12 mm, Plate - Gips 13 mm
Type - Pset_ReinforcementBarPitchOfWall - Description: Tilsvarende: T2 - IVEGG-125 - Forprosjekt
Type - Pset_WallCommon - AcousticRating: 37dB
Identity Data - CQFireRequirement: EI 30
ePset_LocationTool - Splitting: ORIGINAL
AVINOR - 03_Ansvar: 72253; 08_Status: S4; 07_Fase: F90; 05_ID-nummer: +TI=241.005; 06_Omrade: TI; 02_Prosjekt: T20100; 01_Lufthavnkode: ENGM
Pset_ReinforcementBarPitchOfWall - Reference: A241 - SXVXS-100; sets with these values: 2
Pset_WallCommon - IsExternal: no; ExtendToStructure: no; LoadBearing: no; Reference: A241 - SXVXS-100
ePset_Simplebim - Assembly Level: Leaf
ePset_SimplebimBasicQuantities - Thickness (Simplebim): 150 mm
Name (Basic Wall:A241 - SXVXS-100:...) | In | Length (Simplebim) (mm) | Volume, net (Simplebim) (m3) | Area, side, gross, AABB (Simplebim) (m2) | Area, side, net, average (Simplebim) (m2) = Area, side, net, larger (Simplebim) (m2) = Area, side, gross, larger (Simplebim) (m2) = Area, side, gross, smaller (Simplebim) (m2) = Area, side, gross, average (Simplebim) (m2) = Area, largest surface, net (Simplebim) (m2) = Area, side, net, smaller (Simplebim) (m2) | Height (Simplebim) (mm)
58696931 | Nivå F | 10830.5 | 4.41842 | 30.5963 | 29.4561 | 2825
58696931 | Nivå G - 2,0m | 10887.1 | 0.322507 | 2.15565 | 2.15005 | 198

# IfcWall: Basic Wall:A245 - Butikkfasader bjelke/kasse, Basic Wall:A245 - Butikkfasader bjelke/kasse:61156090
In: Nivå F
Type - PredefinedType: STANDARD; Material: T2 - Stål 200 mm
ePset_LocationTool - Splitting: ORIGINAL
AVINOR - 08_Status: S4; 07_Fase: F90; 05_ID-nummer: +TI=245.051; 06_Omrade: TI; 03_Ansvar: 72717; 02_Prosjekt: T20100; 01_Lufthavnkode: ENGM
ePset_SimplebimBasicQuantities - Length (Simplebim): 9325 mm; Height (Simplebim): 2500 mm; Area, side, gross, AABB (Simplebim): 23.3125 m2; Volume, net (Simplebim): 0.0523297 m3; Area, side, net, smaller (Simplebim): 0.261649 m2; Area, side, net, average (Simplebim): 0.261649 m2; Area, side, net, larger (Simplebim): 0.261649 m2; Area, largest surface, net (Simplebim): 0.5 m2; Thickness (Simplebim): 200 mm; Area, side, gross, average (Simplebim): 23.3116 m2; Area, side, gross, smaller (Simplebim): 23.3116 m2; Area, side, gross, larger (Simplebim): 23.3116 m2
ePset_Simplebim - Assembly Level: Leaf
Pset_ReinforcementBarPitchOfWall - Reference: A245 - Butikkfasader bjelke/kasse; sets with these values: 2
Pset_WallCommon - Reference: A245 - Butikkfasader bjelke/kasse; IsExternal: no; ExtendToStructure: no; LoadBearing: no

# IfcWallStandardCase: Basic Wall:A231 - SBE 250 iso+100 lettklinker+15mm puss, Basic Wall:A231 - SBE 250 iso+100 lettklinker+15mm puss:27940620
In: Nivå F - 0,7 m
Type - PredefinedType: STANDARD; Material: _NSW Murpuss 15 mm, _NSW Lettklinker 100 mm, _NSW Isolasjon 250 mm
Type - Pset_ReinforcementBarPitchOfWall - Description: Kledning på fasade nivå D
Pset_WallCommon - Reference: A231 - SBE 250 iso+100 lettklinker+15mm puss; IsExternal: yes; ExtendToStructure: no; LoadBearing: no
ePset_SimplebimBasicQuantities - Area, largest surface, net (Simplebim): 0.315725 m2; Length (Simplebim): 865 mm; Volume, net (Simplebim): 0.0678809 m3; Height (Simplebim): 215 mm; Thickness (Simplebim): 365 mm; Area, side, net, smaller (Simplebim): 0.185975 m2; Area, side, gross, average (Simplebim): 0.185975 m2; Area, side, gross, smaller (Simplebim): 0.185975 m2; Area, side, gross, larger (Simplebim): 0.185975 m2; Area, side, net, larger (Simplebim): 0.185975 m2; Area, side, net, average (Simplebim): 0.185975 m2; Area, side, gross, AABB (Simplebim): 0.185975 m2
Pset_QuantityTakeOff - Reference: A231 - SBE 250 iso+100 lettklinker+15mm puss; sets with these values: 2
AVINOR - 08_Status: S4; 07_Fase: F40; 06_Omrade: TI; 05_ID-nummer: +TI=231.006; 03_Ansvar: 72245; 02_Prosjekt: T20100; 01_Lufthavnkode: ENGM
ePset_LocationTool - Splitting: ORIGINAL
ePset_Simplebim - Assembly Level: Leaf

# IfcWallStandardCase: Basic Wall:A241 - FV-75 (2)
In: Nivå F
Type - PredefinedType: STANDARD; Material: T2_Gips Protect F 15 mm, T2_Gips Protect F 15 mm, _NSW Stålstender, uisolert 75 mm
Pset_WallCommon - IsExternal: no; ExtendToStructure: no; LoadBearing: no; Reference: A241 - FV-75
ePset_SimplebimBasicQuantities - Height (Simplebim): 2800 mm; Thickness (Simplebim): 105 mm
AVINOR - 03_Ansvar: 72253; 08_Status: S4; 07_Fase: F90; 05_ID-nummer: +TI=241.005; 06_Omrade: TI; 02_Prosjekt: T20100; 01_Lufthavnkode: ENGM
Pset_QuantityTakeOff - Reference: A241 - FV-75; sets with these values: 2
ePset_Simplebim - Assembly Level: Leaf
Identity Data - CQFireRequirement: EI 60/ A2-s1,d0
ePset_LocationTool - Splitting: ORIGINAL
Name (Basic Wall:A241 - FV-75:...) | Length (Simplebim) (mm) | Area, side, gross, average (Simplebim) (m2) = Area, side, gross, smaller (Simplebim) (m2) = Area, side, gross, larger (Simplebim) (m2) = Area, side, net, larger (Simplebim) (m2) = Area, side, net, average (Simplebim) (m2) = Area, side, net, smaller (Simplebim) (m2) = Area, largest surface, net (Simplebim) (m2) = Area, side, gross, AABB (Simplebim) (m2) | Volume, net (Simplebim) (m3)
44245155 | 1615.98 | 4.52475 | 0.475099
44245156 | 1039.51 | 2.91064 | 0.305617

# IfcWallStandardCase: Basic Wall:A241 - RVF-103 (2)
In: Nivå F
Type - PredefinedType: STANDARD; Material: T2_Gips Fibergips 12.5 mm, T2_Gips Protect F 15 mm, _NSW Stålstender, uisolert 100 mm, T2_Gips Protect F 15 mm, T2_Gips Fibergips 12.5 mm
Type - Pset_ReinforcementBarPitchOfWall - Description: Teknisk sjakt m/forsterkede stendere H: 7m
ePset_SimplebimBasicQuantities - Height (Simplebim): 2800 mm; Thickness (Simplebim): 155 mm
AVINOR - 03_Ansvar: 72253; 08_Status: S4; 07_Fase: F90; 05_ID-nummer: +TI=241.005; 06_Omrade: TI; 02_Prosjekt: T20100; 01_Lufthavnkode: ENGM
Pset_WallCommon - IsExternal: no; ExtendToStructure: no; LoadBearing: no; Reference: A241 - RVF-103
Pset_QuantityTakeOff - Reference: A241 - RVF-103; sets with these values: 2
ePset_LocationTool - Splitting: ORIGINAL
ePset_Simplebim - Assembly Level: Leaf
Identity Data - CQFireRequirement: EI 60/ A2-s1,d0
Name (Basic Wall:A241 - RVF-103:...) | Area, largest surface, net (Simplebim) (m2) = Area, side, net, smaller (Simplebim) (m2) = Area, side, net, average (Simplebim) (m2) = Area, side, net, larger (Simplebim) (m2) = Area, side, gross, AABB (Simplebim) (m2) | Area, side, gross, larger (Simplebim) (m2) = Area, side, gross, smaller (Simplebim) (m2) = Area, side, gross, average (Simplebim) (m2) | Length (Simplebim) (mm) | Volume, net (Simplebim) (m3)
4337149 | 4.63678 | 4.65185 | 1655.99 | 0.718286
43933487 | 3.668 | 3.668 | 1310 | 0.56854

# IfcWallStandardCase: Basic Wall:A241 - SXVXS-100 (2)
Type - PredefinedType: STANDARD; Material: Plate - Gips 13 mm, _NSW X-finer 12 mm, _NSW Stålstender, uisolert 100 mm, _NSW X-finer 12 mm, Plate - Gips 13 mm
Type - Pset_ReinforcementBarPitchOfWall - Description: Tilsvarende: T2 - IVEGG-125 - Forprosjekt
Type - Pset_WallCommon - AcousticRating: 37dB
ePset_SimplebimBasicQuantities - Thickness (Simplebim): 150 mm; Length (Simplebim): 835.003 mm
AVINOR - 03_Ansvar: 72253; 08_Status: S4; 07_Fase: F90; 05_ID-nummer: +TI=241.005; 06_Omrade: TI; 02_Prosjekt: T20100; 01_Lufthavnkode: ENGM
ePset_LocationTool - Splitting: ORIGINAL
Pset_ReinforcementBarPitchOfWall - Reference: A241 - SXVXS-100; sets with these values: 2
Pset_WallCommon - IsExternal: no; ExtendToStructure: no; LoadBearing: no; Reference: A241 - SXVXS-100
ePset_Simplebim - Assembly Level: Leaf
Name (Basic Wall:A241 - SXVXS-100:...) | In | Height (Simplebim) (mm) | Volume, net (Simplebim) (m3) | Area, side, gross, average (Simplebim) (m2) = Area, side, gross, smaller (Simplebim) (m2) = Area, side, gross, larger (Simplebim) (m2) = Area, side, net, larger (Simplebim) (m2) = Area, side, net, average (Simplebim) (m2) = Area, side, net, smaller (Simplebim) (m2) = Area, largest surface, net (Simplebim) (m2) = Area, side, gross, AABB (Simplebim) (m2)
58696937 | Nivå F | 2800 | 0.350701 | 2.33801
58696937 | Nivå G - 2,0m | 198 | 0.0247996 | 0.165331

# IfcWallStandardCase: Basic Wall:A245 - Butikkfasader bjelke/kasse (5)
Type - PredefinedType: STANDARD; Material: T2 - Stål 200 mm
ePset_LocationTool - Splitting: ORIGINAL
AVINOR - 08_Status: S4; 07_Fase: F90; 05_ID-nummer: +TI=245.051; 06_Omrade: TI; 03_Ansvar: 72717; 02_Prosjekt: T20100; 01_Lufthavnkode: ENGM
ePset_Simplebim - Assembly Level: Leaf
ePset_SimplebimBasicQuantities - Thickness (Simplebim): 200 mm
Pset_ReinforcementBarPitchOfWall - Reference: A245 - Butikkfasader bjelke/kasse; sets with these values: 2
Pset_WallCommon - Reference: A245 - Butikkfasader bjelke/kasse; IsExternal: no; ExtendToStructure: no; LoadBearing: no
Name (Basic Wall:A245 - Butikkfasader bjelke/kasse:...) | In | Area, side, gross, average (Simplebim) (m2) = Area, side, gross, smaller (Simplebim) (m2) = Area, side, gross, larger (Simplebim) (m2) | Length (Simplebim) (mm) | Area, side, net, larger (Simplebim) (m2) = Area, side, net, average (Simplebim) (m2) = Area, side, net, smaller (Simplebim) (m2) | Area, largest surface, net (Simplebim) (m2) | Area, side, gross, AABB (Simplebim) (m2) | Volume, net (Simplebim) (m3) | Height (Simplebim) (mm)
58911258 | Nivå F | 14.3255 | 9335 | 2.8005 | 2.8005 | 2.8005 | 0.5601 | 300
58911258 | Nivå G - 2,0m | 13.392 | 9335 | 1.867 | 1.867 | 1.867 | 0.3734 | 200
59292837 | Nivå F | 0.7605 | 2535 | 0.7605 | 0.7605 | 0.7605 | 0.1521 | 300
59292837 | Nivå G - 2,0m | 0.507 | 2535 | 0.507 | 0.507 | 0.507 | 0.1014 | 200
61156197 | Nivå F | 4.9625 | 1985 | 0.1875 | 0.5 | 4.9625 | 0.0375 | 2500
